VERSION 5.8 ;
BUSBITCHARS "[]" ;
DIVIDERCHAR "/" ;
UNITS
    DATABASE MICRONS 1000 ;
END UNITS

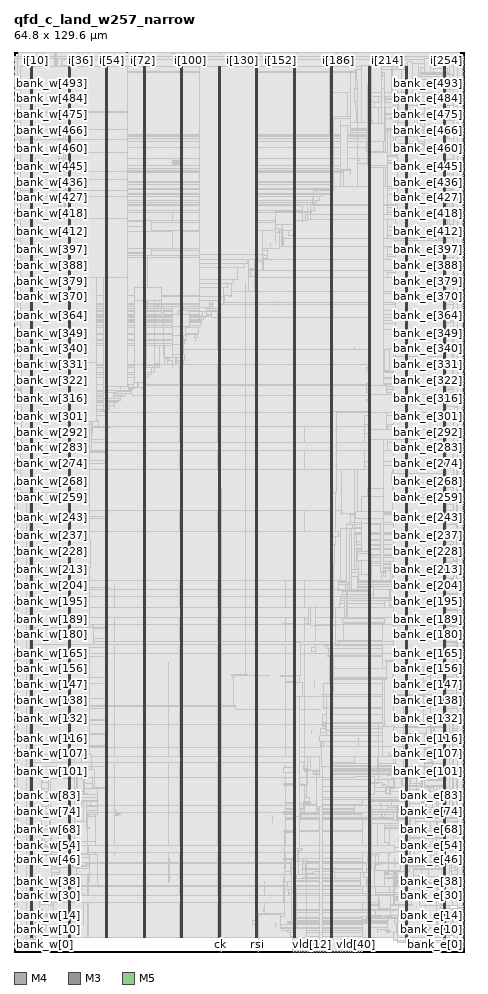
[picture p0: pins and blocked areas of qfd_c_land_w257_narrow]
MACRO qfd_c_land_w257_narrow
  FOREIGN qfd_c_land_w257_narrow 0 0 ;
  CLASS BLOCK ;
  SIZE 64.8 BY 129.6 ;
  PIN bank_e[0]
    DIRECTION OUTPUT ;
    USE SIGNAL ;
    PORT
      LAYER M4 ;
        RECT  64.716 0.672 64.8 0.696 ;
    END
  END bank_e[0]
  PIN bank_e[100]
    DIRECTION OUTPUT ;
    USE SIGNAL ;
    PORT
      LAYER M4 ;
        RECT  64.716 25.68 64.8 25.704 ;
    END
  END bank_e[100]
  PIN bank_e[101]
    DIRECTION OUTPUT ;
    USE SIGNAL ;
    PORT
      LAYER M4 ;
        RECT  64.716 25.92 64.8 25.944 ;
    END
  END bank_e[101]
  PIN bank_e[102]
    DIRECTION OUTPUT ;
    USE SIGNAL ;
    PORT
      LAYER M4 ;
        RECT  64.716 26.16 64.8 26.184 ;
    END
  END bank_e[102]
  PIN bank_e[103]
    DIRECTION OUTPUT ;
    USE SIGNAL ;
    PORT
      LAYER M4 ;
        RECT  64.716 26.4 64.8 26.424 ;
    END
  END bank_e[103]
  PIN bank_e[104]
    DIRECTION OUTPUT ;
    USE SIGNAL ;
    PORT
      LAYER M4 ;
        RECT  64.716 26.64 64.8 26.664 ;
    END
  END bank_e[104]
  PIN bank_e[105]
    DIRECTION OUTPUT ;
    USE SIGNAL ;
    PORT
      LAYER M4 ;
        RECT  64.716 26.928 64.8 26.952 ;
    END
  END bank_e[105]
  PIN bank_e[106]
    DIRECTION OUTPUT ;
    USE SIGNAL ;
    PORT
      LAYER M4 ;
        RECT  64.716 27.168 64.8 27.192 ;
    END
  END bank_e[106]
  PIN bank_e[107]
    DIRECTION OUTPUT ;
    USE SIGNAL ;
    PORT
      LAYER M4 ;
        RECT  64.716 27.408 64.8 27.432 ;
    END
  END bank_e[107]
  PIN bank_e[108]
    DIRECTION OUTPUT ;
    USE SIGNAL ;
    PORT
      LAYER M4 ;
        RECT  64.716 27.648 64.8 27.672 ;
    END
  END bank_e[108]
  PIN bank_e[109]
    DIRECTION OUTPUT ;
    USE SIGNAL ;
    PORT
      LAYER M4 ;
        RECT  64.716 27.888 64.8 27.912 ;
    END
  END bank_e[109]
  PIN bank_e[10]
    DIRECTION OUTPUT ;
    USE SIGNAL ;
    PORT
      LAYER M4 ;
        RECT  64.716 3.168 64.8 3.192 ;
    END
  END bank_e[10]
  PIN bank_e[110]
    DIRECTION OUTPUT ;
    USE SIGNAL ;
    PORT
      LAYER M4 ;
        RECT  64.716 28.176 64.8 28.2 ;
    END
  END bank_e[110]
  PIN bank_e[111]
    DIRECTION OUTPUT ;
    USE SIGNAL ;
    PORT
      LAYER M4 ;
        RECT  64.716 28.416 64.8 28.44 ;
    END
  END bank_e[111]
  PIN bank_e[112]
    DIRECTION OUTPUT ;
    USE SIGNAL ;
    PORT
      LAYER M4 ;
        RECT  64.716 28.656 64.8 28.68 ;
    END
  END bank_e[112]
  PIN bank_e[113]
    DIRECTION OUTPUT ;
    USE SIGNAL ;
    PORT
      LAYER M4 ;
        RECT  64.716 28.896 64.8 28.92 ;
    END
  END bank_e[113]
  PIN bank_e[114]
    DIRECTION OUTPUT ;
    USE SIGNAL ;
    PORT
      LAYER M4 ;
        RECT  64.716 29.136 64.8 29.16 ;
    END
  END bank_e[114]
  PIN bank_e[115]
    DIRECTION OUTPUT ;
    USE SIGNAL ;
    PORT
      LAYER M4 ;
        RECT  64.716 29.424 64.8 29.448 ;
    END
  END bank_e[115]
  PIN bank_e[116]
    DIRECTION OUTPUT ;
    USE SIGNAL ;
    PORT
      LAYER M4 ;
        RECT  64.716 29.664 64.8 29.688 ;
    END
  END bank_e[116]
  PIN bank_e[117]
    DIRECTION OUTPUT ;
    USE SIGNAL ;
    PORT
      LAYER M4 ;
        RECT  64.716 29.904 64.8 29.928 ;
    END
  END bank_e[117]
  PIN bank_e[118]
    DIRECTION OUTPUT ;
    USE SIGNAL ;
    PORT
      LAYER M4 ;
        RECT  64.716 30.144 64.8 30.168 ;
    END
  END bank_e[118]
  PIN bank_e[119]
    DIRECTION OUTPUT ;
    USE SIGNAL ;
    PORT
      LAYER M4 ;
        RECT  64.716 30.432 64.8 30.456 ;
    END
  END bank_e[119]
  PIN bank_e[11]
    DIRECTION OUTPUT ;
    USE SIGNAL ;
    PORT
      LAYER M4 ;
        RECT  64.716 3.408 64.8 3.432 ;
    END
  END bank_e[11]
  PIN bank_e[120]
    DIRECTION OUTPUT ;
    USE SIGNAL ;
    PORT
      LAYER M4 ;
        RECT  64.716 30.672 64.8 30.696 ;
    END
  END bank_e[120]
  PIN bank_e[121]
    DIRECTION OUTPUT ;
    USE SIGNAL ;
    PORT
      LAYER M4 ;
        RECT  64.716 30.912 64.8 30.936 ;
    END
  END bank_e[121]
  PIN bank_e[122]
    DIRECTION OUTPUT ;
    USE SIGNAL ;
    PORT
      LAYER M4 ;
        RECT  64.716 31.152 64.8 31.176 ;
    END
  END bank_e[122]
  PIN bank_e[123]
    DIRECTION OUTPUT ;
    USE SIGNAL ;
    PORT
      LAYER M4 ;
        RECT  64.716 31.392 64.8 31.416 ;
    END
  END bank_e[123]
  PIN bank_e[124]
    DIRECTION OUTPUT ;
    USE SIGNAL ;
    PORT
      LAYER M4 ;
        RECT  64.716 31.68 64.8 31.704 ;
    END
  END bank_e[124]
  PIN bank_e[125]
    DIRECTION OUTPUT ;
    USE SIGNAL ;
    PORT
      LAYER M4 ;
        RECT  64.716 31.92 64.8 31.944 ;
    END
  END bank_e[125]
  PIN bank_e[126]
    DIRECTION OUTPUT ;
    USE SIGNAL ;
    PORT
      LAYER M4 ;
        RECT  64.716 32.16 64.8 32.184 ;
    END
  END bank_e[126]
  PIN bank_e[127]
    DIRECTION OUTPUT ;
    USE SIGNAL ;
    PORT
      LAYER M4 ;
        RECT  64.716 32.4 64.8 32.424 ;
    END
  END bank_e[127]
  PIN bank_e[128]
    DIRECTION OUTPUT ;
    USE SIGNAL ;
    PORT
      LAYER M4 ;
        RECT  64.716 32.64 64.8 32.664 ;
    END
  END bank_e[128]
  PIN bank_e[129]
    DIRECTION OUTPUT ;
    USE SIGNAL ;
    PORT
      LAYER M4 ;
        RECT  64.716 32.928 64.8 32.952 ;
    END
  END bank_e[129]
  PIN bank_e[12]
    DIRECTION OUTPUT ;
    USE SIGNAL ;
    PORT
      LAYER M4 ;
        RECT  64.716 3.648 64.8 3.672 ;
    END
  END bank_e[12]
  PIN bank_e[130]
    DIRECTION OUTPUT ;
    USE SIGNAL ;
    PORT
      LAYER M4 ;
        RECT  64.716 33.168 64.8 33.192 ;
    END
  END bank_e[130]
  PIN bank_e[131]
    DIRECTION OUTPUT ;
    USE SIGNAL ;
    PORT
      LAYER M4 ;
        RECT  64.716 33.408 64.8 33.432 ;
    END
  END bank_e[131]
  PIN bank_e[132]
    DIRECTION OUTPUT ;
    USE SIGNAL ;
    PORT
      LAYER M4 ;
        RECT  64.716 33.648 64.8 33.672 ;
    END
  END bank_e[132]
  PIN bank_e[133]
    DIRECTION OUTPUT ;
    USE SIGNAL ;
    PORT
      LAYER M4 ;
        RECT  64.716 33.888 64.8 33.912 ;
    END
  END bank_e[133]
  PIN bank_e[134]
    DIRECTION OUTPUT ;
    USE SIGNAL ;
    PORT
      LAYER M4 ;
        RECT  64.716 34.176 64.8 34.2 ;
    END
  END bank_e[134]
  PIN bank_e[135]
    DIRECTION OUTPUT ;
    USE SIGNAL ;
    PORT
      LAYER M4 ;
        RECT  64.716 34.416 64.8 34.44 ;
    END
  END bank_e[135]
  PIN bank_e[136]
    DIRECTION OUTPUT ;
    USE SIGNAL ;
    PORT
      LAYER M4 ;
        RECT  64.716 34.656 64.8 34.68 ;
    END
  END bank_e[136]
  PIN bank_e[137]
    DIRECTION OUTPUT ;
    USE SIGNAL ;
    PORT
      LAYER M4 ;
        RECT  64.716 34.896 64.8 34.92 ;
    END
  END bank_e[137]
  PIN bank_e[138]
    DIRECTION OUTPUT ;
    USE SIGNAL ;
    PORT
      LAYER M4 ;
        RECT  64.716 35.136 64.8 35.16 ;
    END
  END bank_e[138]
  PIN bank_e[139]
    DIRECTION OUTPUT ;
    USE SIGNAL ;
    PORT
      LAYER M4 ;
        RECT  64.716 35.424 64.8 35.448 ;
    END
  END bank_e[139]
  PIN bank_e[13]
    DIRECTION OUTPUT ;
    USE SIGNAL ;
    PORT
      LAYER M4 ;
        RECT  64.716 3.888 64.8 3.912 ;
    END
  END bank_e[13]
  PIN bank_e[140]
    DIRECTION OUTPUT ;
    USE SIGNAL ;
    PORT
      LAYER M4 ;
        RECT  64.716 35.664 64.8 35.688 ;
    END
  END bank_e[140]
  PIN bank_e[141]
    DIRECTION OUTPUT ;
    USE SIGNAL ;
    PORT
      LAYER M4 ;
        RECT  64.716 35.904 64.8 35.928 ;
    END
  END bank_e[141]
  PIN bank_e[142]
    DIRECTION OUTPUT ;
    USE SIGNAL ;
    PORT
      LAYER M4 ;
        RECT  64.716 36.144 64.8 36.168 ;
    END
  END bank_e[142]
  PIN bank_e[143]
    DIRECTION OUTPUT ;
    USE SIGNAL ;
    PORT
      LAYER M4 ;
        RECT  64.716 36.432 64.8 36.456 ;
    END
  END bank_e[143]
  PIN bank_e[144]
    DIRECTION OUTPUT ;
    USE SIGNAL ;
    PORT
      LAYER M4 ;
        RECT  64.716 36.672 64.8 36.696 ;
    END
  END bank_e[144]
  PIN bank_e[145]
    DIRECTION OUTPUT ;
    USE SIGNAL ;
    PORT
      LAYER M4 ;
        RECT  64.716 36.912 64.8 36.936 ;
    END
  END bank_e[145]
  PIN bank_e[146]
    DIRECTION OUTPUT ;
    USE SIGNAL ;
    PORT
      LAYER M4 ;
        RECT  64.716 37.152 64.8 37.176 ;
    END
  END bank_e[146]
  PIN bank_e[147]
    DIRECTION OUTPUT ;
    USE SIGNAL ;
    PORT
      LAYER M4 ;
        RECT  64.716 37.392 64.8 37.416 ;
    END
  END bank_e[147]
  PIN bank_e[148]
    DIRECTION OUTPUT ;
    USE SIGNAL ;
    PORT
      LAYER M4 ;
        RECT  64.716 37.68 64.8 37.704 ;
    END
  END bank_e[148]
  PIN bank_e[149]
    DIRECTION OUTPUT ;
    USE SIGNAL ;
    PORT
      LAYER M4 ;
        RECT  64.716 37.92 64.8 37.944 ;
    END
  END bank_e[149]
  PIN bank_e[14]
    DIRECTION OUTPUT ;
    USE SIGNAL ;
    PORT
      LAYER M4 ;
        RECT  64.716 4.176 64.8 4.2 ;
    END
  END bank_e[14]
  PIN bank_e[150]
    DIRECTION OUTPUT ;
    USE SIGNAL ;
    PORT
      LAYER M4 ;
        RECT  64.716 38.16 64.8 38.184 ;
    END
  END bank_e[150]
  PIN bank_e[151]
    DIRECTION OUTPUT ;
    USE SIGNAL ;
    PORT
      LAYER M4 ;
        RECT  64.716 38.4 64.8 38.424 ;
    END
  END bank_e[151]
  PIN bank_e[152]
    DIRECTION OUTPUT ;
    USE SIGNAL ;
    PORT
      LAYER M4 ;
        RECT  64.716 38.64 64.8 38.664 ;
    END
  END bank_e[152]
  PIN bank_e[153]
    DIRECTION OUTPUT ;
    USE SIGNAL ;
    PORT
      LAYER M4 ;
        RECT  64.716 38.928 64.8 38.952 ;
    END
  END bank_e[153]
  PIN bank_e[154]
    DIRECTION OUTPUT ;
    USE SIGNAL ;
    PORT
      LAYER M4 ;
        RECT  64.716 39.168 64.8 39.192 ;
    END
  END bank_e[154]
  PIN bank_e[155]
    DIRECTION OUTPUT ;
    USE SIGNAL ;
    PORT
      LAYER M4 ;
        RECT  64.716 39.408 64.8 39.432 ;
    END
  END bank_e[155]
  PIN bank_e[156]
    DIRECTION OUTPUT ;
    USE SIGNAL ;
    PORT
      LAYER M4 ;
        RECT  64.716 39.648 64.8 39.672 ;
    END
  END bank_e[156]
  PIN bank_e[157]
    DIRECTION OUTPUT ;
    USE SIGNAL ;
    PORT
      LAYER M4 ;
        RECT  64.716 39.888 64.8 39.912 ;
    END
  END bank_e[157]
  PIN bank_e[158]
    DIRECTION OUTPUT ;
    USE SIGNAL ;
    PORT
      LAYER M4 ;
        RECT  64.716 40.176 64.8 40.2 ;
    END
  END bank_e[158]
  PIN bank_e[159]
    DIRECTION OUTPUT ;
    USE SIGNAL ;
    PORT
      LAYER M4 ;
        RECT  64.716 40.416 64.8 40.44 ;
    END
  END bank_e[159]
  PIN bank_e[15]
    DIRECTION OUTPUT ;
    USE SIGNAL ;
    PORT
      LAYER M4 ;
        RECT  64.716 4.416 64.8 4.44 ;
    END
  END bank_e[15]
  PIN bank_e[160]
    DIRECTION OUTPUT ;
    USE SIGNAL ;
    PORT
      LAYER M4 ;
        RECT  64.716 40.656 64.8 40.68 ;
    END
  END bank_e[160]
  PIN bank_e[161]
    DIRECTION OUTPUT ;
    USE SIGNAL ;
    PORT
      LAYER M4 ;
        RECT  64.716 40.896 64.8 40.92 ;
    END
  END bank_e[161]
  PIN bank_e[162]
    DIRECTION OUTPUT ;
    USE SIGNAL ;
    PORT
      LAYER M4 ;
        RECT  64.716 41.136 64.8 41.16 ;
    END
  END bank_e[162]
  PIN bank_e[163]
    DIRECTION OUTPUT ;
    USE SIGNAL ;
    PORT
      LAYER M4 ;
        RECT  64.716 41.424 64.8 41.448 ;
    END
  END bank_e[163]
  PIN bank_e[164]
    DIRECTION OUTPUT ;
    USE SIGNAL ;
    PORT
      LAYER M4 ;
        RECT  64.716 41.664 64.8 41.688 ;
    END
  END bank_e[164]
  PIN bank_e[165]
    DIRECTION OUTPUT ;
    USE SIGNAL ;
    PORT
      LAYER M4 ;
        RECT  64.716 41.904 64.8 41.928 ;
    END
  END bank_e[165]
  PIN bank_e[166]
    DIRECTION OUTPUT ;
    USE SIGNAL ;
    PORT
      LAYER M4 ;
        RECT  64.716 42.144 64.8 42.168 ;
    END
  END bank_e[166]
  PIN bank_e[167]
    DIRECTION OUTPUT ;
    USE SIGNAL ;
    PORT
      LAYER M4 ;
        RECT  64.716 42.432 64.8 42.456 ;
    END
  END bank_e[167]
  PIN bank_e[168]
    DIRECTION OUTPUT ;
    USE SIGNAL ;
    PORT
      LAYER M4 ;
        RECT  64.716 42.672 64.8 42.696 ;
    END
  END bank_e[168]
  PIN bank_e[169]
    DIRECTION OUTPUT ;
    USE SIGNAL ;
    PORT
      LAYER M4 ;
        RECT  64.716 42.912 64.8 42.936 ;
    END
  END bank_e[169]
  PIN bank_e[16]
    DIRECTION OUTPUT ;
    USE SIGNAL ;
    PORT
      LAYER M4 ;
        RECT  64.716 4.656 64.8 4.68 ;
    END
  END bank_e[16]
  PIN bank_e[170]
    DIRECTION OUTPUT ;
    USE SIGNAL ;
    PORT
      LAYER M4 ;
        RECT  64.716 43.152 64.8 43.176 ;
    END
  END bank_e[170]
  PIN bank_e[171]
    DIRECTION OUTPUT ;
    USE SIGNAL ;
    PORT
      LAYER M4 ;
        RECT  64.716 43.392 64.8 43.416 ;
    END
  END bank_e[171]
  PIN bank_e[172]
    DIRECTION OUTPUT ;
    USE SIGNAL ;
    PORT
      LAYER M4 ;
        RECT  64.716 43.68 64.8 43.704 ;
    END
  END bank_e[172]
  PIN bank_e[173]
    DIRECTION OUTPUT ;
    USE SIGNAL ;
    PORT
      LAYER M4 ;
        RECT  64.716 43.92 64.8 43.944 ;
    END
  END bank_e[173]
  PIN bank_e[174]
    DIRECTION OUTPUT ;
    USE SIGNAL ;
    PORT
      LAYER M4 ;
        RECT  64.716 44.16 64.8 44.184 ;
    END
  END bank_e[174]
  PIN bank_e[175]
    DIRECTION OUTPUT ;
    USE SIGNAL ;
    PORT
      LAYER M4 ;
        RECT  64.716 44.4 64.8 44.424 ;
    END
  END bank_e[175]
  PIN bank_e[176]
    DIRECTION OUTPUT ;
    USE SIGNAL ;
    PORT
      LAYER M4 ;
        RECT  64.716 44.64 64.8 44.664 ;
    END
  END bank_e[176]
  PIN bank_e[177]
    DIRECTION OUTPUT ;
    USE SIGNAL ;
    PORT
      LAYER M4 ;
        RECT  64.716 44.928 64.8 44.952 ;
    END
  END bank_e[177]
  PIN bank_e[178]
    DIRECTION OUTPUT ;
    USE SIGNAL ;
    PORT
      LAYER M4 ;
        RECT  64.716 45.168 64.8 45.192 ;
    END
  END bank_e[178]
  PIN bank_e[179]
    DIRECTION OUTPUT ;
    USE SIGNAL ;
    PORT
      LAYER M4 ;
        RECT  64.716 45.408 64.8 45.432 ;
    END
  END bank_e[179]
  PIN bank_e[17]
    DIRECTION OUTPUT ;
    USE SIGNAL ;
    PORT
      LAYER M4 ;
        RECT  64.716 4.896 64.8 4.92 ;
    END
  END bank_e[17]
  PIN bank_e[180]
    DIRECTION OUTPUT ;
    USE SIGNAL ;
    PORT
      LAYER M4 ;
        RECT  64.716 45.648 64.8 45.672 ;
    END
  END bank_e[180]
  PIN bank_e[181]
    DIRECTION OUTPUT ;
    USE SIGNAL ;
    PORT
      LAYER M4 ;
        RECT  64.716 45.888 64.8 45.912 ;
    END
  END bank_e[181]
  PIN bank_e[182]
    DIRECTION OUTPUT ;
    USE SIGNAL ;
    PORT
      LAYER M4 ;
        RECT  64.716 46.176 64.8 46.2 ;
    END
  END bank_e[182]
  PIN bank_e[183]
    DIRECTION OUTPUT ;
    USE SIGNAL ;
    PORT
      LAYER M4 ;
        RECT  64.716 46.416 64.8 46.44 ;
    END
  END bank_e[183]
  PIN bank_e[184]
    DIRECTION OUTPUT ;
    USE SIGNAL ;
    PORT
      LAYER M4 ;
        RECT  64.716 46.656 64.8 46.68 ;
    END
  END bank_e[184]
  PIN bank_e[185]
    DIRECTION OUTPUT ;
    USE SIGNAL ;
    PORT
      LAYER M4 ;
        RECT  64.716 46.896 64.8 46.92 ;
    END
  END bank_e[185]
  PIN bank_e[186]
    DIRECTION OUTPUT ;
    USE SIGNAL ;
    PORT
      LAYER M4 ;
        RECT  64.716 47.184 64.8 47.208 ;
    END
  END bank_e[186]
  PIN bank_e[187]
    DIRECTION OUTPUT ;
    USE SIGNAL ;
    PORT
      LAYER M4 ;
        RECT  64.716 47.424 64.8 47.448 ;
    END
  END bank_e[187]
  PIN bank_e[188]
    DIRECTION OUTPUT ;
    USE SIGNAL ;
    PORT
      LAYER M4 ;
        RECT  64.716 47.664 64.8 47.688 ;
    END
  END bank_e[188]
  PIN bank_e[189]
    DIRECTION OUTPUT ;
    USE SIGNAL ;
    PORT
      LAYER M4 ;
        RECT  64.716 47.904 64.8 47.928 ;
    END
  END bank_e[189]
  PIN bank_e[18]
    DIRECTION OUTPUT ;
    USE SIGNAL ;
    PORT
      LAYER M4 ;
        RECT  64.716 5.136 64.8 5.16 ;
    END
  END bank_e[18]
  PIN bank_e[190]
    DIRECTION OUTPUT ;
    USE SIGNAL ;
    PORT
      LAYER M4 ;
        RECT  64.716 48.144 64.8 48.168 ;
    END
  END bank_e[190]
  PIN bank_e[191]
    DIRECTION OUTPUT ;
    USE SIGNAL ;
    PORT
      LAYER M4 ;
        RECT  64.716 48.432 64.8 48.456 ;
    END
  END bank_e[191]
  PIN bank_e[192]
    DIRECTION OUTPUT ;
    USE SIGNAL ;
    PORT
      LAYER M4 ;
        RECT  64.716 48.672 64.8 48.696 ;
    END
  END bank_e[192]
  PIN bank_e[193]
    DIRECTION OUTPUT ;
    USE SIGNAL ;
    PORT
      LAYER M4 ;
        RECT  64.716 48.912 64.8 48.936 ;
    END
  END bank_e[193]
  PIN bank_e[194]
    DIRECTION OUTPUT ;
    USE SIGNAL ;
    PORT
      LAYER M4 ;
        RECT  64.716 49.152 64.8 49.176 ;
    END
  END bank_e[194]
  PIN bank_e[195]
    DIRECTION OUTPUT ;
    USE SIGNAL ;
    PORT
      LAYER M4 ;
        RECT  64.716 49.392 64.8 49.416 ;
    END
  END bank_e[195]
  PIN bank_e[196]
    DIRECTION OUTPUT ;
    USE SIGNAL ;
    PORT
      LAYER M4 ;
        RECT  64.716 49.68 64.8 49.704 ;
    END
  END bank_e[196]
  PIN bank_e[197]
    DIRECTION OUTPUT ;
    USE SIGNAL ;
    PORT
      LAYER M4 ;
        RECT  64.716 49.92 64.8 49.944 ;
    END
  END bank_e[197]
  PIN bank_e[198]
    DIRECTION OUTPUT ;
    USE SIGNAL ;
    PORT
      LAYER M4 ;
        RECT  64.716 50.16 64.8 50.184 ;
    END
  END bank_e[198]
  PIN bank_e[199]
    DIRECTION OUTPUT ;
    USE SIGNAL ;
    PORT
      LAYER M4 ;
        RECT  64.716 50.4 64.8 50.424 ;
    END
  END bank_e[199]
  PIN bank_e[19]
    DIRECTION OUTPUT ;
    USE SIGNAL ;
    PORT
      LAYER M4 ;
        RECT  64.716 5.424 64.8 5.448 ;
    END
  END bank_e[19]
  PIN bank_e[1]
    DIRECTION OUTPUT ;
    USE SIGNAL ;
    PORT
      LAYER M4 ;
        RECT  64.716 0.912 64.8 0.936 ;
    END
  END bank_e[1]
  PIN bank_e[200]
    DIRECTION OUTPUT ;
    USE SIGNAL ;
    PORT
      LAYER M4 ;
        RECT  64.716 50.64 64.8 50.664 ;
    END
  END bank_e[200]
  PIN bank_e[201]
    DIRECTION OUTPUT ;
    USE SIGNAL ;
    PORT
      LAYER M4 ;
        RECT  64.716 50.928 64.8 50.952 ;
    END
  END bank_e[201]
  PIN bank_e[202]
    DIRECTION OUTPUT ;
    USE SIGNAL ;
    PORT
      LAYER M4 ;
        RECT  64.716 51.168 64.8 51.192 ;
    END
  END bank_e[202]
  PIN bank_e[203]
    DIRECTION OUTPUT ;
    USE SIGNAL ;
    PORT
      LAYER M4 ;
        RECT  64.716 51.408 64.8 51.432 ;
    END
  END bank_e[203]
  PIN bank_e[204]
    DIRECTION OUTPUT ;
    USE SIGNAL ;
    PORT
      LAYER M4 ;
        RECT  64.716 51.648 64.8 51.672 ;
    END
  END bank_e[204]
  PIN bank_e[205]
    DIRECTION OUTPUT ;
    USE SIGNAL ;
    PORT
      LAYER M4 ;
        RECT  64.716 51.888 64.8 51.912 ;
    END
  END bank_e[205]
  PIN bank_e[206]
    DIRECTION OUTPUT ;
    USE SIGNAL ;
    PORT
      LAYER M4 ;
        RECT  64.716 52.176 64.8 52.2 ;
    END
  END bank_e[206]
  PIN bank_e[207]
    DIRECTION OUTPUT ;
    USE SIGNAL ;
    PORT
      LAYER M4 ;
        RECT  64.716 52.416 64.8 52.44 ;
    END
  END bank_e[207]
  PIN bank_e[208]
    DIRECTION OUTPUT ;
    USE SIGNAL ;
    PORT
      LAYER M4 ;
        RECT  64.716 52.656 64.8 52.68 ;
    END
  END bank_e[208]
  PIN bank_e[209]
    DIRECTION OUTPUT ;
    USE SIGNAL ;
    PORT
      LAYER M4 ;
        RECT  64.716 52.896 64.8 52.92 ;
    END
  END bank_e[209]
  PIN bank_e[20]
    DIRECTION OUTPUT ;
    USE SIGNAL ;
    PORT
      LAYER M4 ;
        RECT  64.716 5.664 64.8 5.688 ;
    END
  END bank_e[20]
  PIN bank_e[210]
    DIRECTION OUTPUT ;
    USE SIGNAL ;
    PORT
      LAYER M4 ;
        RECT  64.716 53.184 64.8 53.208 ;
    END
  END bank_e[210]
  PIN bank_e[211]
    DIRECTION OUTPUT ;
    USE SIGNAL ;
    PORT
      LAYER M4 ;
        RECT  64.716 53.424 64.8 53.448 ;
    END
  END bank_e[211]
  PIN bank_e[212]
    DIRECTION OUTPUT ;
    USE SIGNAL ;
    PORT
      LAYER M4 ;
        RECT  64.716 53.664 64.8 53.688 ;
    END
  END bank_e[212]
  PIN bank_e[213]
    DIRECTION OUTPUT ;
    USE SIGNAL ;
    PORT
      LAYER M4 ;
        RECT  64.716 53.904 64.8 53.928 ;
    END
  END bank_e[213]
  PIN bank_e[214]
    DIRECTION OUTPUT ;
    USE SIGNAL ;
    PORT
      LAYER M4 ;
        RECT  64.716 54.144 64.8 54.168 ;
    END
  END bank_e[214]
  PIN bank_e[215]
    DIRECTION OUTPUT ;
    USE SIGNAL ;
    PORT
      LAYER M4 ;
        RECT  64.716 54.432 64.8 54.456 ;
    END
  END bank_e[215]
  PIN bank_e[216]
    DIRECTION OUTPUT ;
    USE SIGNAL ;
    PORT
      LAYER M4 ;
        RECT  64.716 54.672 64.8 54.696 ;
    END
  END bank_e[216]
  PIN bank_e[217]
    DIRECTION OUTPUT ;
    USE SIGNAL ;
    PORT
      LAYER M4 ;
        RECT  64.716 54.912 64.8 54.936 ;
    END
  END bank_e[217]
  PIN bank_e[218]
    DIRECTION OUTPUT ;
    USE SIGNAL ;
    PORT
      LAYER M4 ;
        RECT  64.716 55.152 64.8 55.176 ;
    END
  END bank_e[218]
  PIN bank_e[219]
    DIRECTION OUTPUT ;
    USE SIGNAL ;
    PORT
      LAYER M4 ;
        RECT  64.716 55.392 64.8 55.416 ;
    END
  END bank_e[219]
  PIN bank_e[21]
    DIRECTION OUTPUT ;
    USE SIGNAL ;
    PORT
      LAYER M4 ;
        RECT  64.716 5.904 64.8 5.928 ;
    END
  END bank_e[21]
  PIN bank_e[220]
    DIRECTION OUTPUT ;
    USE SIGNAL ;
    PORT
      LAYER M4 ;
        RECT  64.716 55.68 64.8 55.704 ;
    END
  END bank_e[220]
  PIN bank_e[221]
    DIRECTION OUTPUT ;
    USE SIGNAL ;
    PORT
      LAYER M4 ;
        RECT  64.716 55.92 64.8 55.944 ;
    END
  END bank_e[221]
  PIN bank_e[222]
    DIRECTION OUTPUT ;
    USE SIGNAL ;
    PORT
      LAYER M4 ;
        RECT  64.716 56.16 64.8 56.184 ;
    END
  END bank_e[222]
  PIN bank_e[223]
    DIRECTION OUTPUT ;
    USE SIGNAL ;
    PORT
      LAYER M4 ;
        RECT  64.716 56.4 64.8 56.424 ;
    END
  END bank_e[223]
  PIN bank_e[224]
    DIRECTION OUTPUT ;
    USE SIGNAL ;
    PORT
      LAYER M4 ;
        RECT  64.716 56.64 64.8 56.664 ;
    END
  END bank_e[224]
  PIN bank_e[225]
    DIRECTION OUTPUT ;
    USE SIGNAL ;
    PORT
      LAYER M4 ;
        RECT  64.716 56.928 64.8 56.952 ;
    END
  END bank_e[225]
  PIN bank_e[226]
    DIRECTION OUTPUT ;
    USE SIGNAL ;
    PORT
      LAYER M4 ;
        RECT  64.716 57.168 64.8 57.192 ;
    END
  END bank_e[226]
  PIN bank_e[227]
    DIRECTION OUTPUT ;
    USE SIGNAL ;
    PORT
      LAYER M4 ;
        RECT  64.716 57.408 64.8 57.432 ;
    END
  END bank_e[227]
  PIN bank_e[228]
    DIRECTION OUTPUT ;
    USE SIGNAL ;
    PORT
      LAYER M4 ;
        RECT  64.716 57.648 64.8 57.672 ;
    END
  END bank_e[228]
  PIN bank_e[229]
    DIRECTION OUTPUT ;
    USE SIGNAL ;
    PORT
      LAYER M4 ;
        RECT  64.716 57.936 64.8 57.96 ;
    END
  END bank_e[229]
  PIN bank_e[22]
    DIRECTION OUTPUT ;
    USE SIGNAL ;
    PORT
      LAYER M4 ;
        RECT  64.716 6.144 64.8 6.168 ;
    END
  END bank_e[22]
  PIN bank_e[230]
    DIRECTION OUTPUT ;
    USE SIGNAL ;
    PORT
      LAYER M4 ;
        RECT  64.716 58.176 64.8 58.2 ;
    END
  END bank_e[230]
  PIN bank_e[231]
    DIRECTION OUTPUT ;
    USE SIGNAL ;
    PORT
      LAYER M4 ;
        RECT  64.716 58.416 64.8 58.44 ;
    END
  END bank_e[231]
  PIN bank_e[232]
    DIRECTION OUTPUT ;
    USE SIGNAL ;
    PORT
      LAYER M4 ;
        RECT  64.716 58.656 64.8 58.68 ;
    END
  END bank_e[232]
  PIN bank_e[233]
    DIRECTION OUTPUT ;
    USE SIGNAL ;
    PORT
      LAYER M4 ;
        RECT  64.716 58.896 64.8 58.92 ;
    END
  END bank_e[233]
  PIN bank_e[234]
    DIRECTION OUTPUT ;
    USE SIGNAL ;
    PORT
      LAYER M4 ;
        RECT  64.716 59.184 64.8 59.208 ;
    END
  END bank_e[234]
  PIN bank_e[235]
    DIRECTION OUTPUT ;
    USE SIGNAL ;
    PORT
      LAYER M4 ;
        RECT  64.716 59.424 64.8 59.448 ;
    END
  END bank_e[235]
  PIN bank_e[236]
    DIRECTION OUTPUT ;
    USE SIGNAL ;
    PORT
      LAYER M4 ;
        RECT  64.716 59.664 64.8 59.688 ;
    END
  END bank_e[236]
  PIN bank_e[237]
    DIRECTION OUTPUT ;
    USE SIGNAL ;
    PORT
      LAYER M4 ;
        RECT  64.716 59.904 64.8 59.928 ;
    END
  END bank_e[237]
  PIN bank_e[238]
    DIRECTION OUTPUT ;
    USE SIGNAL ;
    PORT
      LAYER M4 ;
        RECT  64.716 60.144 64.8 60.168 ;
    END
  END bank_e[238]
  PIN bank_e[239]
    DIRECTION OUTPUT ;
    USE SIGNAL ;
    PORT
      LAYER M4 ;
        RECT  64.716 60.432 64.8 60.456 ;
    END
  END bank_e[239]
  PIN bank_e[23]
    DIRECTION OUTPUT ;
    USE SIGNAL ;
    PORT
      LAYER M4 ;
        RECT  64.716 6.384 64.8 6.408 ;
    END
  END bank_e[23]
  PIN bank_e[240]
    DIRECTION OUTPUT ;
    USE SIGNAL ;
    PORT
      LAYER M4 ;
        RECT  64.716 60.672 64.8 60.696 ;
    END
  END bank_e[240]
  PIN bank_e[241]
    DIRECTION OUTPUT ;
    USE SIGNAL ;
    PORT
      LAYER M4 ;
        RECT  64.716 60.912 64.8 60.936 ;
    END
  END bank_e[241]
  PIN bank_e[242]
    DIRECTION OUTPUT ;
    USE SIGNAL ;
    PORT
      LAYER M4 ;
        RECT  64.716 61.152 64.8 61.176 ;
    END
  END bank_e[242]
  PIN bank_e[243]
    DIRECTION OUTPUT ;
    USE SIGNAL ;
    PORT
      LAYER M4 ;
        RECT  64.716 61.392 64.8 61.416 ;
    END
  END bank_e[243]
  PIN bank_e[244]
    DIRECTION OUTPUT ;
    USE SIGNAL ;
    PORT
      LAYER M4 ;
        RECT  64.716 61.68 64.8 61.704 ;
    END
  END bank_e[244]
  PIN bank_e[245]
    DIRECTION OUTPUT ;
    USE SIGNAL ;
    PORT
      LAYER M4 ;
        RECT  64.716 61.92 64.8 61.944 ;
    END
  END bank_e[245]
  PIN bank_e[246]
    DIRECTION OUTPUT ;
    USE SIGNAL ;
    PORT
      LAYER M4 ;
        RECT  64.716 62.16 64.8 62.184 ;
    END
  END bank_e[246]
  PIN bank_e[247]
    DIRECTION OUTPUT ;
    USE SIGNAL ;
    PORT
      LAYER M4 ;
        RECT  64.716 62.4 64.8 62.424 ;
    END
  END bank_e[247]
  PIN bank_e[248]
    DIRECTION OUTPUT ;
    USE SIGNAL ;
    PORT
      LAYER M4 ;
        RECT  64.716 62.64 64.8 62.664 ;
    END
  END bank_e[248]
  PIN bank_e[249]
    DIRECTION OUTPUT ;
    USE SIGNAL ;
    PORT
      LAYER M4 ;
        RECT  64.716 62.928 64.8 62.952 ;
    END
  END bank_e[249]
  PIN bank_e[24]
    DIRECTION OUTPUT ;
    USE SIGNAL ;
    PORT
      LAYER M4 ;
        RECT  64.716 6.672 64.8 6.696 ;
    END
  END bank_e[24]
  PIN bank_e[250]
    DIRECTION OUTPUT ;
    USE SIGNAL ;
    PORT
      LAYER M4 ;
        RECT  64.716 63.168 64.8 63.192 ;
    END
  END bank_e[250]
  PIN bank_e[251]
    DIRECTION OUTPUT ;
    USE SIGNAL ;
    PORT
      LAYER M4 ;
        RECT  64.716 63.408 64.8 63.432 ;
    END
  END bank_e[251]
  PIN bank_e[252]
    DIRECTION OUTPUT ;
    USE SIGNAL ;
    PORT
      LAYER M4 ;
        RECT  64.716 63.648 64.8 63.672 ;
    END
  END bank_e[252]
  PIN bank_e[253]
    DIRECTION OUTPUT ;
    USE SIGNAL ;
    PORT
      LAYER M4 ;
        RECT  64.716 63.936 64.8 63.96 ;
    END
  END bank_e[253]
  PIN bank_e[254]
    DIRECTION OUTPUT ;
    USE SIGNAL ;
    PORT
      LAYER M4 ;
        RECT  64.716 64.176 64.8 64.2 ;
    END
  END bank_e[254]
  PIN bank_e[255]
    DIRECTION OUTPUT ;
    USE SIGNAL ;
    PORT
      LAYER M4 ;
        RECT  64.716 64.416 64.8 64.44 ;
    END
  END bank_e[255]
  PIN bank_e[256]
    DIRECTION OUTPUT ;
    USE SIGNAL ;
    PORT
      LAYER M4 ;
        RECT  64.716 64.656 64.8 64.68 ;
    END
  END bank_e[256]
  PIN bank_e[257]
    DIRECTION OUTPUT ;
    USE SIGNAL ;
    PORT
      LAYER M4 ;
        RECT  64.716 64.896 64.8 64.92 ;
    END
  END bank_e[257]
  PIN bank_e[258]
    DIRECTION OUTPUT ;
    USE SIGNAL ;
    PORT
      LAYER M4 ;
        RECT  64.716 65.184 64.8 65.208 ;
    END
  END bank_e[258]
  PIN bank_e[259]
    DIRECTION OUTPUT ;
    USE SIGNAL ;
    PORT
      LAYER M4 ;
        RECT  64.716 65.424 64.8 65.448 ;
    END
  END bank_e[259]
  PIN bank_e[25]
    DIRECTION OUTPUT ;
    USE SIGNAL ;
    PORT
      LAYER M4 ;
        RECT  64.716 6.912 64.8 6.936 ;
    END
  END bank_e[25]
  PIN bank_e[260]
    DIRECTION OUTPUT ;
    USE SIGNAL ;
    PORT
      LAYER M4 ;
        RECT  64.716 65.664 64.8 65.688 ;
    END
  END bank_e[260]
  PIN bank_e[261]
    DIRECTION OUTPUT ;
    USE SIGNAL ;
    PORT
      LAYER M4 ;
        RECT  64.716 65.904 64.8 65.928 ;
    END
  END bank_e[261]
  PIN bank_e[262]
    DIRECTION OUTPUT ;
    USE SIGNAL ;
    PORT
      LAYER M4 ;
        RECT  64.716 66.144 64.8 66.168 ;
    END
  END bank_e[262]
  PIN bank_e[263]
    DIRECTION OUTPUT ;
    USE SIGNAL ;
    PORT
      LAYER M4 ;
        RECT  64.716 66.432 64.8 66.456 ;
    END
  END bank_e[263]
  PIN bank_e[264]
    DIRECTION OUTPUT ;
    USE SIGNAL ;
    PORT
      LAYER M4 ;
        RECT  64.716 66.672 64.8 66.696 ;
    END
  END bank_e[264]
  PIN bank_e[265]
    DIRECTION OUTPUT ;
    USE SIGNAL ;
    PORT
      LAYER M4 ;
        RECT  64.716 66.912 64.8 66.936 ;
    END
  END bank_e[265]
  PIN bank_e[266]
    DIRECTION OUTPUT ;
    USE SIGNAL ;
    PORT
      LAYER M4 ;
        RECT  64.716 67.152 64.8 67.176 ;
    END
  END bank_e[266]
  PIN bank_e[267]
    DIRECTION OUTPUT ;
    USE SIGNAL ;
    PORT
      LAYER M4 ;
        RECT  64.716 67.392 64.8 67.416 ;
    END
  END bank_e[267]
  PIN bank_e[268]
    DIRECTION OUTPUT ;
    USE SIGNAL ;
    PORT
      LAYER M4 ;
        RECT  64.716 67.68 64.8 67.704 ;
    END
  END bank_e[268]
  PIN bank_e[269]
    DIRECTION OUTPUT ;
    USE SIGNAL ;
    PORT
      LAYER M4 ;
        RECT  64.716 67.92 64.8 67.944 ;
    END
  END bank_e[269]
  PIN bank_e[26]
    DIRECTION OUTPUT ;
    USE SIGNAL ;
    PORT
      LAYER M4 ;
        RECT  64.716 7.152 64.8 7.176 ;
    END
  END bank_e[26]
  PIN bank_e[270]
    DIRECTION OUTPUT ;
    USE SIGNAL ;
    PORT
      LAYER M4 ;
        RECT  64.716 68.16 64.8 68.184 ;
    END
  END bank_e[270]
  PIN bank_e[271]
    DIRECTION OUTPUT ;
    USE SIGNAL ;
    PORT
      LAYER M4 ;
        RECT  64.716 68.4 64.8 68.424 ;
    END
  END bank_e[271]
  PIN bank_e[272]
    DIRECTION OUTPUT ;
    USE SIGNAL ;
    PORT
      LAYER M4 ;
        RECT  64.716 68.688 64.8 68.712 ;
    END
  END bank_e[272]
  PIN bank_e[273]
    DIRECTION OUTPUT ;
    USE SIGNAL ;
    PORT
      LAYER M4 ;
        RECT  64.716 68.928 64.8 68.952 ;
    END
  END bank_e[273]
  PIN bank_e[274]
    DIRECTION OUTPUT ;
    USE SIGNAL ;
    PORT
      LAYER M4 ;
        RECT  64.716 69.168 64.8 69.192 ;
    END
  END bank_e[274]
  PIN bank_e[275]
    DIRECTION OUTPUT ;
    USE SIGNAL ;
    PORT
      LAYER M4 ;
        RECT  64.716 69.408 64.8 69.432 ;
    END
  END bank_e[275]
  PIN bank_e[276]
    DIRECTION OUTPUT ;
    USE SIGNAL ;
    PORT
      LAYER M4 ;
        RECT  64.716 69.648 64.8 69.672 ;
    END
  END bank_e[276]
  PIN bank_e[277]
    DIRECTION OUTPUT ;
    USE SIGNAL ;
    PORT
      LAYER M4 ;
        RECT  64.716 69.936 64.8 69.96 ;
    END
  END bank_e[277]
  PIN bank_e[278]
    DIRECTION OUTPUT ;
    USE SIGNAL ;
    PORT
      LAYER M4 ;
        RECT  64.716 70.176 64.8 70.2 ;
    END
  END bank_e[278]
  PIN bank_e[279]
    DIRECTION OUTPUT ;
    USE SIGNAL ;
    PORT
      LAYER M4 ;
        RECT  64.716 70.416 64.8 70.44 ;
    END
  END bank_e[279]
  PIN bank_e[27]
    DIRECTION OUTPUT ;
    USE SIGNAL ;
    PORT
      LAYER M4 ;
        RECT  64.716 7.392 64.8 7.416 ;
    END
  END bank_e[27]
  PIN bank_e[280]
    DIRECTION OUTPUT ;
    USE SIGNAL ;
    PORT
      LAYER M4 ;
        RECT  64.716 70.656 64.8 70.68 ;
    END
  END bank_e[280]
  PIN bank_e[281]
    DIRECTION OUTPUT ;
    USE SIGNAL ;
    PORT
      LAYER M4 ;
        RECT  64.716 70.896 64.8 70.92 ;
    END
  END bank_e[281]
  PIN bank_e[282]
    DIRECTION OUTPUT ;
    USE SIGNAL ;
    PORT
      LAYER M4 ;
        RECT  64.716 71.184 64.8 71.208 ;
    END
  END bank_e[282]
  PIN bank_e[283]
    DIRECTION OUTPUT ;
    USE SIGNAL ;
    PORT
      LAYER M4 ;
        RECT  64.716 71.424 64.8 71.448 ;
    END
  END bank_e[283]
  PIN bank_e[284]
    DIRECTION OUTPUT ;
    USE SIGNAL ;
    PORT
      LAYER M4 ;
        RECT  64.716 71.664 64.8 71.688 ;
    END
  END bank_e[284]
  PIN bank_e[285]
    DIRECTION OUTPUT ;
    USE SIGNAL ;
    PORT
      LAYER M4 ;
        RECT  64.716 71.904 64.8 71.928 ;
    END
  END bank_e[285]
  PIN bank_e[286]
    DIRECTION OUTPUT ;
    USE SIGNAL ;
    PORT
      LAYER M4 ;
        RECT  64.716 72.144 64.8 72.168 ;
    END
  END bank_e[286]
  PIN bank_e[287]
    DIRECTION OUTPUT ;
    USE SIGNAL ;
    PORT
      LAYER M4 ;
        RECT  64.716 72.432 64.8 72.456 ;
    END
  END bank_e[287]
  PIN bank_e[288]
    DIRECTION OUTPUT ;
    USE SIGNAL ;
    PORT
      LAYER M4 ;
        RECT  64.716 72.672 64.8 72.696 ;
    END
  END bank_e[288]
  PIN bank_e[289]
    DIRECTION OUTPUT ;
    USE SIGNAL ;
    PORT
      LAYER M4 ;
        RECT  64.716 72.912 64.8 72.936 ;
    END
  END bank_e[289]
  PIN bank_e[28]
    DIRECTION OUTPUT ;
    USE SIGNAL ;
    PORT
      LAYER M4 ;
        RECT  64.716 7.632 64.8 7.656 ;
    END
  END bank_e[28]
  PIN bank_e[290]
    DIRECTION OUTPUT ;
    USE SIGNAL ;
    PORT
      LAYER M4 ;
        RECT  64.716 73.152 64.8 73.176 ;
    END
  END bank_e[290]
  PIN bank_e[291]
    DIRECTION OUTPUT ;
    USE SIGNAL ;
    PORT
      LAYER M4 ;
        RECT  64.716 73.392 64.8 73.416 ;
    END
  END bank_e[291]
  PIN bank_e[292]
    DIRECTION OUTPUT ;
    USE SIGNAL ;
    PORT
      LAYER M4 ;
        RECT  64.716 73.68 64.8 73.704 ;
    END
  END bank_e[292]
  PIN bank_e[293]
    DIRECTION OUTPUT ;
    USE SIGNAL ;
    PORT
      LAYER M4 ;
        RECT  64.716 73.92 64.8 73.944 ;
    END
  END bank_e[293]
  PIN bank_e[294]
    DIRECTION OUTPUT ;
    USE SIGNAL ;
    PORT
      LAYER M4 ;
        RECT  64.716 74.16 64.8 74.184 ;
    END
  END bank_e[294]
  PIN bank_e[295]
    DIRECTION OUTPUT ;
    USE SIGNAL ;
    PORT
      LAYER M4 ;
        RECT  64.716 74.4 64.8 74.424 ;
    END
  END bank_e[295]
  PIN bank_e[296]
    DIRECTION OUTPUT ;
    USE SIGNAL ;
    PORT
      LAYER M4 ;
        RECT  64.716 74.688 64.8 74.712 ;
    END
  END bank_e[296]
  PIN bank_e[297]
    DIRECTION OUTPUT ;
    USE SIGNAL ;
    PORT
      LAYER M4 ;
        RECT  64.716 74.928 64.8 74.952 ;
    END
  END bank_e[297]
  PIN bank_e[298]
    DIRECTION OUTPUT ;
    USE SIGNAL ;
    PORT
      LAYER M4 ;
        RECT  64.716 75.168 64.8 75.192 ;
    END
  END bank_e[298]
  PIN bank_e[299]
    DIRECTION OUTPUT ;
    USE SIGNAL ;
    PORT
      LAYER M4 ;
        RECT  64.716 75.408 64.8 75.432 ;
    END
  END bank_e[299]
  PIN bank_e[29]
    DIRECTION OUTPUT ;
    USE SIGNAL ;
    PORT
      LAYER M4 ;
        RECT  64.716 7.92 64.8 7.944 ;
    END
  END bank_e[29]
  PIN bank_e[2]
    DIRECTION OUTPUT ;
    USE SIGNAL ;
    PORT
      LAYER M4 ;
        RECT  64.716 1.152 64.8 1.176 ;
    END
  END bank_e[2]
  PIN bank_e[300]
    DIRECTION OUTPUT ;
    USE SIGNAL ;
    PORT
      LAYER M4 ;
        RECT  64.716 75.648 64.8 75.672 ;
    END
  END bank_e[300]
  PIN bank_e[301]
    DIRECTION OUTPUT ;
    USE SIGNAL ;
    PORT
      LAYER M4 ;
        RECT  64.716 75.936 64.8 75.96 ;
    END
  END bank_e[301]
  PIN bank_e[302]
    DIRECTION OUTPUT ;
    USE SIGNAL ;
    PORT
      LAYER M4 ;
        RECT  64.716 76.176 64.8 76.2 ;
    END
  END bank_e[302]
  PIN bank_e[303]
    DIRECTION OUTPUT ;
    USE SIGNAL ;
    PORT
      LAYER M4 ;
        RECT  64.716 76.416 64.8 76.44 ;
    END
  END bank_e[303]
  PIN bank_e[304]
    DIRECTION OUTPUT ;
    USE SIGNAL ;
    PORT
      LAYER M4 ;
        RECT  64.716 76.656 64.8 76.68 ;
    END
  END bank_e[304]
  PIN bank_e[305]
    DIRECTION OUTPUT ;
    USE SIGNAL ;
    PORT
      LAYER M4 ;
        RECT  64.716 76.896 64.8 76.92 ;
    END
  END bank_e[305]
  PIN bank_e[306]
    DIRECTION OUTPUT ;
    USE SIGNAL ;
    PORT
      LAYER M4 ;
        RECT  64.716 77.184 64.8 77.208 ;
    END
  END bank_e[306]
  PIN bank_e[307]
    DIRECTION OUTPUT ;
    USE SIGNAL ;
    PORT
      LAYER M4 ;
        RECT  64.716 77.424 64.8 77.448 ;
    END
  END bank_e[307]
  PIN bank_e[308]
    DIRECTION OUTPUT ;
    USE SIGNAL ;
    PORT
      LAYER M4 ;
        RECT  64.716 77.664 64.8 77.688 ;
    END
  END bank_e[308]
  PIN bank_e[309]
    DIRECTION OUTPUT ;
    USE SIGNAL ;
    PORT
      LAYER M4 ;
        RECT  64.716 77.904 64.8 77.928 ;
    END
  END bank_e[309]
  PIN bank_e[30]
    DIRECTION OUTPUT ;
    USE SIGNAL ;
    PORT
      LAYER M4 ;
        RECT  64.716 8.16 64.8 8.184 ;
    END
  END bank_e[30]
  PIN bank_e[310]
    DIRECTION OUTPUT ;
    USE SIGNAL ;
    PORT
      LAYER M4 ;
        RECT  64.716 78.144 64.8 78.168 ;
    END
  END bank_e[310]
  PIN bank_e[311]
    DIRECTION OUTPUT ;
    USE SIGNAL ;
    PORT
      LAYER M4 ;
        RECT  64.716 78.432 64.8 78.456 ;
    END
  END bank_e[311]
  PIN bank_e[312]
    DIRECTION OUTPUT ;
    USE SIGNAL ;
    PORT
      LAYER M4 ;
        RECT  64.716 78.672 64.8 78.696 ;
    END
  END bank_e[312]
  PIN bank_e[313]
    DIRECTION OUTPUT ;
    USE SIGNAL ;
    PORT
      LAYER M4 ;
        RECT  64.716 78.912 64.8 78.936 ;
    END
  END bank_e[313]
  PIN bank_e[314]
    DIRECTION OUTPUT ;
    USE SIGNAL ;
    PORT
      LAYER M4 ;
        RECT  64.716 79.152 64.8 79.176 ;
    END
  END bank_e[314]
  PIN bank_e[315]
    DIRECTION OUTPUT ;
    USE SIGNAL ;
    PORT
      LAYER M4 ;
        RECT  64.716 79.392 64.8 79.416 ;
    END
  END bank_e[315]
  PIN bank_e[316]
    DIRECTION OUTPUT ;
    USE SIGNAL ;
    PORT
      LAYER M4 ;
        RECT  64.716 79.68 64.8 79.704 ;
    END
  END bank_e[316]
  PIN bank_e[317]
    DIRECTION OUTPUT ;
    USE SIGNAL ;
    PORT
      LAYER M4 ;
        RECT  64.716 79.92 64.8 79.944 ;
    END
  END bank_e[317]
  PIN bank_e[318]
    DIRECTION OUTPUT ;
    USE SIGNAL ;
    PORT
      LAYER M4 ;
        RECT  64.716 80.16 64.8 80.184 ;
    END
  END bank_e[318]
  PIN bank_e[319]
    DIRECTION OUTPUT ;
    USE SIGNAL ;
    PORT
      LAYER M4 ;
        RECT  64.716 80.4 64.8 80.424 ;
    END
  END bank_e[319]
  PIN bank_e[31]
    DIRECTION OUTPUT ;
    USE SIGNAL ;
    PORT
      LAYER M4 ;
        RECT  64.716 8.4 64.8 8.424 ;
    END
  END bank_e[31]
  PIN bank_e[320]
    DIRECTION OUTPUT ;
    USE SIGNAL ;
    PORT
      LAYER M4 ;
        RECT  64.716 80.688 64.8 80.712 ;
    END
  END bank_e[320]
  PIN bank_e[321]
    DIRECTION OUTPUT ;
    USE SIGNAL ;
    PORT
      LAYER M4 ;
        RECT  64.716 80.928 64.8 80.952 ;
    END
  END bank_e[321]
  PIN bank_e[322]
    DIRECTION OUTPUT ;
    USE SIGNAL ;
    PORT
      LAYER M4 ;
        RECT  64.716 81.168 64.8 81.192 ;
    END
  END bank_e[322]
  PIN bank_e[323]
    DIRECTION OUTPUT ;
    USE SIGNAL ;
    PORT
      LAYER M4 ;
        RECT  64.716 81.408 64.8 81.432 ;
    END
  END bank_e[323]
  PIN bank_e[324]
    DIRECTION OUTPUT ;
    USE SIGNAL ;
    PORT
      LAYER M4 ;
        RECT  64.716 81.648 64.8 81.672 ;
    END
  END bank_e[324]
  PIN bank_e[325]
    DIRECTION OUTPUT ;
    USE SIGNAL ;
    PORT
      LAYER M4 ;
        RECT  64.716 81.936 64.8 81.96 ;
    END
  END bank_e[325]
  PIN bank_e[326]
    DIRECTION OUTPUT ;
    USE SIGNAL ;
    PORT
      LAYER M4 ;
        RECT  64.716 82.176 64.8 82.2 ;
    END
  END bank_e[326]
  PIN bank_e[327]
    DIRECTION OUTPUT ;
    USE SIGNAL ;
    PORT
      LAYER M4 ;
        RECT  64.716 82.416 64.8 82.44 ;
    END
  END bank_e[327]
  PIN bank_e[328]
    DIRECTION OUTPUT ;
    USE SIGNAL ;
    PORT
      LAYER M4 ;
        RECT  64.716 82.656 64.8 82.68 ;
    END
  END bank_e[328]
  PIN bank_e[329]
    DIRECTION OUTPUT ;
    USE SIGNAL ;
    PORT
      LAYER M4 ;
        RECT  64.716 82.896 64.8 82.92 ;
    END
  END bank_e[329]
  PIN bank_e[32]
    DIRECTION OUTPUT ;
    USE SIGNAL ;
    PORT
      LAYER M4 ;
        RECT  64.716 8.64 64.8 8.664 ;
    END
  END bank_e[32]
  PIN bank_e[330]
    DIRECTION OUTPUT ;
    USE SIGNAL ;
    PORT
      LAYER M4 ;
        RECT  64.716 83.184 64.8 83.208 ;
    END
  END bank_e[330]
  PIN bank_e[331]
    DIRECTION OUTPUT ;
    USE SIGNAL ;
    PORT
      LAYER M4 ;
        RECT  64.716 83.424 64.8 83.448 ;
    END
  END bank_e[331]
  PIN bank_e[332]
    DIRECTION OUTPUT ;
    USE SIGNAL ;
    PORT
      LAYER M4 ;
        RECT  64.716 83.664 64.8 83.688 ;
    END
  END bank_e[332]
  PIN bank_e[333]
    DIRECTION OUTPUT ;
    USE SIGNAL ;
    PORT
      LAYER M4 ;
        RECT  64.716 83.904 64.8 83.928 ;
    END
  END bank_e[333]
  PIN bank_e[334]
    DIRECTION OUTPUT ;
    USE SIGNAL ;
    PORT
      LAYER M4 ;
        RECT  64.716 84.144 64.8 84.168 ;
    END
  END bank_e[334]
  PIN bank_e[335]
    DIRECTION OUTPUT ;
    USE SIGNAL ;
    PORT
      LAYER M4 ;
        RECT  64.716 84.432 64.8 84.456 ;
    END
  END bank_e[335]
  PIN bank_e[336]
    DIRECTION OUTPUT ;
    USE SIGNAL ;
    PORT
      LAYER M4 ;
        RECT  64.716 84.672 64.8 84.696 ;
    END
  END bank_e[336]
  PIN bank_e[337]
    DIRECTION OUTPUT ;
    USE SIGNAL ;
    PORT
      LAYER M4 ;
        RECT  64.716 84.912 64.8 84.936 ;
    END
  END bank_e[337]
  PIN bank_e[338]
    DIRECTION OUTPUT ;
    USE SIGNAL ;
    PORT
      LAYER M4 ;
        RECT  64.716 85.152 64.8 85.176 ;
    END
  END bank_e[338]
  PIN bank_e[339]
    DIRECTION OUTPUT ;
    USE SIGNAL ;
    PORT
      LAYER M4 ;
        RECT  64.716 85.44 64.8 85.464 ;
    END
  END bank_e[339]
  PIN bank_e[33]
    DIRECTION OUTPUT ;
    USE SIGNAL ;
    PORT
      LAYER M4 ;
        RECT  64.716 8.928 64.8 8.952 ;
    END
  END bank_e[33]
  PIN bank_e[340]
    DIRECTION OUTPUT ;
    USE SIGNAL ;
    PORT
      LAYER M4 ;
        RECT  64.716 85.68 64.8 85.704 ;
    END
  END bank_e[340]
  PIN bank_e[341]
    DIRECTION OUTPUT ;
    USE SIGNAL ;
    PORT
      LAYER M4 ;
        RECT  64.716 85.92 64.8 85.944 ;
    END
  END bank_e[341]
  PIN bank_e[342]
    DIRECTION OUTPUT ;
    USE SIGNAL ;
    PORT
      LAYER M4 ;
        RECT  64.716 86.16 64.8 86.184 ;
    END
  END bank_e[342]
  PIN bank_e[343]
    DIRECTION OUTPUT ;
    USE SIGNAL ;
    PORT
      LAYER M4 ;
        RECT  64.716 86.4 64.8 86.424 ;
    END
  END bank_e[343]
  PIN bank_e[344]
    DIRECTION OUTPUT ;
    USE SIGNAL ;
    PORT
      LAYER M4 ;
        RECT  64.716 86.688 64.8 86.712 ;
    END
  END bank_e[344]
  PIN bank_e[345]
    DIRECTION OUTPUT ;
    USE SIGNAL ;
    PORT
      LAYER M4 ;
        RECT  64.716 86.928 64.8 86.952 ;
    END
  END bank_e[345]
  PIN bank_e[346]
    DIRECTION OUTPUT ;
    USE SIGNAL ;
    PORT
      LAYER M4 ;
        RECT  64.716 87.168 64.8 87.192 ;
    END
  END bank_e[346]
  PIN bank_e[347]
    DIRECTION OUTPUT ;
    USE SIGNAL ;
    PORT
      LAYER M4 ;
        RECT  64.716 87.408 64.8 87.432 ;
    END
  END bank_e[347]
  PIN bank_e[348]
    DIRECTION OUTPUT ;
    USE SIGNAL ;
    PORT
      LAYER M4 ;
        RECT  64.716 87.648 64.8 87.672 ;
    END
  END bank_e[348]
  PIN bank_e[349]
    DIRECTION OUTPUT ;
    USE SIGNAL ;
    PORT
      LAYER M4 ;
        RECT  64.716 87.936 64.8 87.96 ;
    END
  END bank_e[349]
  PIN bank_e[34]
    DIRECTION OUTPUT ;
    USE SIGNAL ;
    PORT
      LAYER M4 ;
        RECT  64.716 9.168 64.8 9.192 ;
    END
  END bank_e[34]
  PIN bank_e[350]
    DIRECTION OUTPUT ;
    USE SIGNAL ;
    PORT
      LAYER M4 ;
        RECT  64.716 88.176 64.8 88.2 ;
    END
  END bank_e[350]
  PIN bank_e[351]
    DIRECTION OUTPUT ;
    USE SIGNAL ;
    PORT
      LAYER M4 ;
        RECT  64.716 88.416 64.8 88.44 ;
    END
  END bank_e[351]
  PIN bank_e[352]
    DIRECTION OUTPUT ;
    USE SIGNAL ;
    PORT
      LAYER M4 ;
        RECT  64.716 88.656 64.8 88.68 ;
    END
  END bank_e[352]
  PIN bank_e[353]
    DIRECTION OUTPUT ;
    USE SIGNAL ;
    PORT
      LAYER M4 ;
        RECT  64.716 88.896 64.8 88.92 ;
    END
  END bank_e[353]
  PIN bank_e[354]
    DIRECTION OUTPUT ;
    USE SIGNAL ;
    PORT
      LAYER M4 ;
        RECT  64.716 89.184 64.8 89.208 ;
    END
  END bank_e[354]
  PIN bank_e[355]
    DIRECTION OUTPUT ;
    USE SIGNAL ;
    PORT
      LAYER M4 ;
        RECT  64.716 89.424 64.8 89.448 ;
    END
  END bank_e[355]
  PIN bank_e[356]
    DIRECTION OUTPUT ;
    USE SIGNAL ;
    PORT
      LAYER M4 ;
        RECT  64.716 89.664 64.8 89.688 ;
    END
  END bank_e[356]
  PIN bank_e[357]
    DIRECTION OUTPUT ;
    USE SIGNAL ;
    PORT
      LAYER M4 ;
        RECT  64.716 89.904 64.8 89.928 ;
    END
  END bank_e[357]
  PIN bank_e[358]
    DIRECTION OUTPUT ;
    USE SIGNAL ;
    PORT
      LAYER M4 ;
        RECT  64.716 90.144 64.8 90.168 ;
    END
  END bank_e[358]
  PIN bank_e[359]
    DIRECTION OUTPUT ;
    USE SIGNAL ;
    PORT
      LAYER M4 ;
        RECT  64.716 90.432 64.8 90.456 ;
    END
  END bank_e[359]
  PIN bank_e[35]
    DIRECTION OUTPUT ;
    USE SIGNAL ;
    PORT
      LAYER M4 ;
        RECT  64.716 9.408 64.8 9.432 ;
    END
  END bank_e[35]
  PIN bank_e[360]
    DIRECTION OUTPUT ;
    USE SIGNAL ;
    PORT
      LAYER M4 ;
        RECT  64.716 90.672 64.8 90.696 ;
    END
  END bank_e[360]
  PIN bank_e[361]
    DIRECTION OUTPUT ;
    USE SIGNAL ;
    PORT
      LAYER M4 ;
        RECT  64.716 90.912 64.8 90.936 ;
    END
  END bank_e[361]
  PIN bank_e[362]
    DIRECTION OUTPUT ;
    USE SIGNAL ;
    PORT
      LAYER M4 ;
        RECT  64.716 91.152 64.8 91.176 ;
    END
  END bank_e[362]
  PIN bank_e[363]
    DIRECTION OUTPUT ;
    USE SIGNAL ;
    PORT
      LAYER M4 ;
        RECT  64.716 91.44 64.8 91.464 ;
    END
  END bank_e[363]
  PIN bank_e[364]
    DIRECTION OUTPUT ;
    USE SIGNAL ;
    PORT
      LAYER M4 ;
        RECT  64.716 91.68 64.8 91.704 ;
    END
  END bank_e[364]
  PIN bank_e[365]
    DIRECTION OUTPUT ;
    USE SIGNAL ;
    PORT
      LAYER M4 ;
        RECT  64.716 91.92 64.8 91.944 ;
    END
  END bank_e[365]
  PIN bank_e[366]
    DIRECTION OUTPUT ;
    USE SIGNAL ;
    PORT
      LAYER M4 ;
        RECT  64.716 92.16 64.8 92.184 ;
    END
  END bank_e[366]
  PIN bank_e[367]
    DIRECTION OUTPUT ;
    USE SIGNAL ;
    PORT
      LAYER M4 ;
        RECT  64.716 92.4 64.8 92.424 ;
    END
  END bank_e[367]
  PIN bank_e[368]
    DIRECTION OUTPUT ;
    USE SIGNAL ;
    PORT
      LAYER M4 ;
        RECT  64.716 92.688 64.8 92.712 ;
    END
  END bank_e[368]
  PIN bank_e[369]
    DIRECTION OUTPUT ;
    USE SIGNAL ;
    PORT
      LAYER M4 ;
        RECT  64.716 92.928 64.8 92.952 ;
    END
  END bank_e[369]
  PIN bank_e[36]
    DIRECTION OUTPUT ;
    USE SIGNAL ;
    PORT
      LAYER M4 ;
        RECT  64.716 9.648 64.8 9.672 ;
    END
  END bank_e[36]
  PIN bank_e[370]
    DIRECTION OUTPUT ;
    USE SIGNAL ;
    PORT
      LAYER M4 ;
        RECT  64.716 93.168 64.8 93.192 ;
    END
  END bank_e[370]
  PIN bank_e[371]
    DIRECTION OUTPUT ;
    USE SIGNAL ;
    PORT
      LAYER M4 ;
        RECT  64.716 93.408 64.8 93.432 ;
    END
  END bank_e[371]
  PIN bank_e[372]
    DIRECTION OUTPUT ;
    USE SIGNAL ;
    PORT
      LAYER M4 ;
        RECT  64.716 93.648 64.8 93.672 ;
    END
  END bank_e[372]
  PIN bank_e[373]
    DIRECTION OUTPUT ;
    USE SIGNAL ;
    PORT
      LAYER M4 ;
        RECT  64.716 93.936 64.8 93.96 ;
    END
  END bank_e[373]
  PIN bank_e[374]
    DIRECTION OUTPUT ;
    USE SIGNAL ;
    PORT
      LAYER M4 ;
        RECT  64.716 94.176 64.8 94.2 ;
    END
  END bank_e[374]
  PIN bank_e[375]
    DIRECTION OUTPUT ;
    USE SIGNAL ;
    PORT
      LAYER M4 ;
        RECT  64.716 94.416 64.8 94.44 ;
    END
  END bank_e[375]
  PIN bank_e[376]
    DIRECTION OUTPUT ;
    USE SIGNAL ;
    PORT
      LAYER M4 ;
        RECT  64.716 94.656 64.8 94.68 ;
    END
  END bank_e[376]
  PIN bank_e[377]
    DIRECTION OUTPUT ;
    USE SIGNAL ;
    PORT
      LAYER M4 ;
        RECT  64.716 94.896 64.8 94.92 ;
    END
  END bank_e[377]
  PIN bank_e[378]
    DIRECTION OUTPUT ;
    USE SIGNAL ;
    PORT
      LAYER M4 ;
        RECT  64.716 95.184 64.8 95.208 ;
    END
  END bank_e[378]
  PIN bank_e[379]
    DIRECTION OUTPUT ;
    USE SIGNAL ;
    PORT
      LAYER M4 ;
        RECT  64.716 95.424 64.8 95.448 ;
    END
  END bank_e[379]
  PIN bank_e[37]
    DIRECTION OUTPUT ;
    USE SIGNAL ;
    PORT
      LAYER M4 ;
        RECT  64.716 9.888 64.8 9.912 ;
    END
  END bank_e[37]
  PIN bank_e[380]
    DIRECTION OUTPUT ;
    USE SIGNAL ;
    PORT
      LAYER M4 ;
        RECT  64.716 95.664 64.8 95.688 ;
    END
  END bank_e[380]
  PIN bank_e[381]
    DIRECTION OUTPUT ;
    USE SIGNAL ;
    PORT
      LAYER M4 ;
        RECT  64.716 95.904 64.8 95.928 ;
    END
  END bank_e[381]
  PIN bank_e[382]
    DIRECTION OUTPUT ;
    USE SIGNAL ;
    PORT
      LAYER M4 ;
        RECT  64.716 96.192 64.8 96.216 ;
    END
  END bank_e[382]
  PIN bank_e[383]
    DIRECTION OUTPUT ;
    USE SIGNAL ;
    PORT
      LAYER M4 ;
        RECT  64.716 96.432 64.8 96.456 ;
    END
  END bank_e[383]
  PIN bank_e[384]
    DIRECTION OUTPUT ;
    USE SIGNAL ;
    PORT
      LAYER M4 ;
        RECT  64.716 96.672 64.8 96.696 ;
    END
  END bank_e[384]
  PIN bank_e[385]
    DIRECTION OUTPUT ;
    USE SIGNAL ;
    PORT
      LAYER M4 ;
        RECT  64.716 96.912 64.8 96.936 ;
    END
  END bank_e[385]
  PIN bank_e[386]
    DIRECTION OUTPUT ;
    USE SIGNAL ;
    PORT
      LAYER M4 ;
        RECT  64.716 97.152 64.8 97.176 ;
    END
  END bank_e[386]
  PIN bank_e[387]
    DIRECTION OUTPUT ;
    USE SIGNAL ;
    PORT
      LAYER M4 ;
        RECT  64.716 97.44 64.8 97.464 ;
    END
  END bank_e[387]
  PIN bank_e[388]
    DIRECTION OUTPUT ;
    USE SIGNAL ;
    PORT
      LAYER M4 ;
        RECT  64.716 97.68 64.8 97.704 ;
    END
  END bank_e[388]
  PIN bank_e[389]
    DIRECTION OUTPUT ;
    USE SIGNAL ;
    PORT
      LAYER M4 ;
        RECT  64.716 97.92 64.8 97.944 ;
    END
  END bank_e[389]
  PIN bank_e[38]
    DIRECTION OUTPUT ;
    USE SIGNAL ;
    PORT
      LAYER M4 ;
        RECT  64.716 10.176 64.8 10.2 ;
    END
  END bank_e[38]
  PIN bank_e[390]
    DIRECTION OUTPUT ;
    USE SIGNAL ;
    PORT
      LAYER M4 ;
        RECT  64.716 98.16 64.8 98.184 ;
    END
  END bank_e[390]
  PIN bank_e[391]
    DIRECTION OUTPUT ;
    USE SIGNAL ;
    PORT
      LAYER M4 ;
        RECT  64.716 98.4 64.8 98.424 ;
    END
  END bank_e[391]
  PIN bank_e[392]
    DIRECTION OUTPUT ;
    USE SIGNAL ;
    PORT
      LAYER M4 ;
        RECT  64.716 98.688 64.8 98.712 ;
    END
  END bank_e[392]
  PIN bank_e[393]
    DIRECTION OUTPUT ;
    USE SIGNAL ;
    PORT
      LAYER M4 ;
        RECT  64.716 98.928 64.8 98.952 ;
    END
  END bank_e[393]
  PIN bank_e[394]
    DIRECTION OUTPUT ;
    USE SIGNAL ;
    PORT
      LAYER M4 ;
        RECT  64.716 99.168 64.8 99.192 ;
    END
  END bank_e[394]
  PIN bank_e[395]
    DIRECTION OUTPUT ;
    USE SIGNAL ;
    PORT
      LAYER M4 ;
        RECT  64.716 99.408 64.8 99.432 ;
    END
  END bank_e[395]
  PIN bank_e[396]
    DIRECTION OUTPUT ;
    USE SIGNAL ;
    PORT
      LAYER M4 ;
        RECT  64.716 99.648 64.8 99.672 ;
    END
  END bank_e[396]
  PIN bank_e[397]
    DIRECTION OUTPUT ;
    USE SIGNAL ;
    PORT
      LAYER M4 ;
        RECT  64.716 99.936 64.8 99.96 ;
    END
  END bank_e[397]
  PIN bank_e[398]
    DIRECTION OUTPUT ;
    USE SIGNAL ;
    PORT
      LAYER M4 ;
        RECT  64.716 100.176 64.8 100.2 ;
    END
  END bank_e[398]
  PIN bank_e[399]
    DIRECTION OUTPUT ;
    USE SIGNAL ;
    PORT
      LAYER M4 ;
        RECT  64.716 100.416 64.8 100.44 ;
    END
  END bank_e[399]
  PIN bank_e[39]
    DIRECTION OUTPUT ;
    USE SIGNAL ;
    PORT
      LAYER M4 ;
        RECT  64.716 10.416 64.8 10.44 ;
    END
  END bank_e[39]
  PIN bank_e[3]
    DIRECTION OUTPUT ;
    USE SIGNAL ;
    PORT
      LAYER M4 ;
        RECT  64.716 1.392 64.8 1.416 ;
    END
  END bank_e[3]
  PIN bank_e[400]
    DIRECTION OUTPUT ;
    USE SIGNAL ;
    PORT
      LAYER M4 ;
        RECT  64.716 100.656 64.8 100.68 ;
    END
  END bank_e[400]
  PIN bank_e[401]
    DIRECTION OUTPUT ;
    USE SIGNAL ;
    PORT
      LAYER M4 ;
        RECT  64.716 100.896 64.8 100.92 ;
    END
  END bank_e[401]
  PIN bank_e[402]
    DIRECTION OUTPUT ;
    USE SIGNAL ;
    PORT
      LAYER M4 ;
        RECT  64.716 101.184 64.8 101.208 ;
    END
  END bank_e[402]
  PIN bank_e[403]
    DIRECTION OUTPUT ;
    USE SIGNAL ;
    PORT
      LAYER M4 ;
        RECT  64.716 101.424 64.8 101.448 ;
    END
  END bank_e[403]
  PIN bank_e[404]
    DIRECTION OUTPUT ;
    USE SIGNAL ;
    PORT
      LAYER M4 ;
        RECT  64.716 101.664 64.8 101.688 ;
    END
  END bank_e[404]
  PIN bank_e[405]
    DIRECTION OUTPUT ;
    USE SIGNAL ;
    PORT
      LAYER M4 ;
        RECT  64.716 101.904 64.8 101.928 ;
    END
  END bank_e[405]
  PIN bank_e[406]
    DIRECTION OUTPUT ;
    USE SIGNAL ;
    PORT
      LAYER M4 ;
        RECT  64.716 102.192 64.8 102.216 ;
    END
  END bank_e[406]
  PIN bank_e[407]
    DIRECTION OUTPUT ;
    USE SIGNAL ;
    PORT
      LAYER M4 ;
        RECT  64.716 102.432 64.8 102.456 ;
    END
  END bank_e[407]
  PIN bank_e[408]
    DIRECTION OUTPUT ;
    USE SIGNAL ;
    PORT
      LAYER M4 ;
        RECT  64.716 102.672 64.8 102.696 ;
    END
  END bank_e[408]
  PIN bank_e[409]
    DIRECTION OUTPUT ;
    USE SIGNAL ;
    PORT
      LAYER M4 ;
        RECT  64.716 102.912 64.8 102.936 ;
    END
  END bank_e[409]
  PIN bank_e[40]
    DIRECTION OUTPUT ;
    USE SIGNAL ;
    PORT
      LAYER M4 ;
        RECT  64.716 10.656 64.8 10.68 ;
    END
  END bank_e[40]
  PIN bank_e[410]
    DIRECTION OUTPUT ;
    USE SIGNAL ;
    PORT
      LAYER M4 ;
        RECT  64.716 103.152 64.8 103.176 ;
    END
  END bank_e[410]
  PIN bank_e[411]
    DIRECTION OUTPUT ;
    USE SIGNAL ;
    PORT
      LAYER M4 ;
        RECT  64.716 103.44 64.8 103.464 ;
    END
  END bank_e[411]
  PIN bank_e[412]
    DIRECTION OUTPUT ;
    USE SIGNAL ;
    PORT
      LAYER M4 ;
        RECT  64.716 103.68 64.8 103.704 ;
    END
  END bank_e[412]
  PIN bank_e[413]
    DIRECTION OUTPUT ;
    USE SIGNAL ;
    PORT
      LAYER M4 ;
        RECT  64.716 103.92 64.8 103.944 ;
    END
  END bank_e[413]
  PIN bank_e[414]
    DIRECTION OUTPUT ;
    USE SIGNAL ;
    PORT
      LAYER M4 ;
        RECT  64.716 104.16 64.8 104.184 ;
    END
  END bank_e[414]
  PIN bank_e[415]
    DIRECTION OUTPUT ;
    USE SIGNAL ;
    PORT
      LAYER M4 ;
        RECT  64.716 104.4 64.8 104.424 ;
    END
  END bank_e[415]
  PIN bank_e[416]
    DIRECTION OUTPUT ;
    USE SIGNAL ;
    PORT
      LAYER M4 ;
        RECT  64.716 104.688 64.8 104.712 ;
    END
  END bank_e[416]
  PIN bank_e[417]
    DIRECTION OUTPUT ;
    USE SIGNAL ;
    PORT
      LAYER M4 ;
        RECT  64.716 104.928 64.8 104.952 ;
    END
  END bank_e[417]
  PIN bank_e[418]
    DIRECTION OUTPUT ;
    USE SIGNAL ;
    PORT
      LAYER M4 ;
        RECT  64.716 105.168 64.8 105.192 ;
    END
  END bank_e[418]
  PIN bank_e[419]
    DIRECTION OUTPUT ;
    USE SIGNAL ;
    PORT
      LAYER M4 ;
        RECT  64.716 105.408 64.8 105.432 ;
    END
  END bank_e[419]
  PIN bank_e[41]
    DIRECTION OUTPUT ;
    USE SIGNAL ;
    PORT
      LAYER M4 ;
        RECT  64.716 10.896 64.8 10.92 ;
    END
  END bank_e[41]
  PIN bank_e[420]
    DIRECTION OUTPUT ;
    USE SIGNAL ;
    PORT
      LAYER M4 ;
        RECT  64.716 105.648 64.8 105.672 ;
    END
  END bank_e[420]
  PIN bank_e[421]
    DIRECTION OUTPUT ;
    USE SIGNAL ;
    PORT
      LAYER M4 ;
        RECT  64.716 105.936 64.8 105.96 ;
    END
  END bank_e[421]
  PIN bank_e[422]
    DIRECTION OUTPUT ;
    USE SIGNAL ;
    PORT
      LAYER M4 ;
        RECT  64.716 106.176 64.8 106.2 ;
    END
  END bank_e[422]
  PIN bank_e[423]
    DIRECTION OUTPUT ;
    USE SIGNAL ;
    PORT
      LAYER M4 ;
        RECT  64.716 106.416 64.8 106.44 ;
    END
  END bank_e[423]
  PIN bank_e[424]
    DIRECTION OUTPUT ;
    USE SIGNAL ;
    PORT
      LAYER M4 ;
        RECT  64.716 106.656 64.8 106.68 ;
    END
  END bank_e[424]
  PIN bank_e[425]
    DIRECTION OUTPUT ;
    USE SIGNAL ;
    PORT
      LAYER M4 ;
        RECT  64.716 106.944 64.8 106.968 ;
    END
  END bank_e[425]
  PIN bank_e[426]
    DIRECTION OUTPUT ;
    USE SIGNAL ;
    PORT
      LAYER M4 ;
        RECT  64.716 107.184 64.8 107.208 ;
    END
  END bank_e[426]
  PIN bank_e[427]
    DIRECTION OUTPUT ;
    USE SIGNAL ;
    PORT
      LAYER M4 ;
        RECT  64.716 107.424 64.8 107.448 ;
    END
  END bank_e[427]
  PIN bank_e[428]
    DIRECTION OUTPUT ;
    USE SIGNAL ;
    PORT
      LAYER M4 ;
        RECT  64.716 107.664 64.8 107.688 ;
    END
  END bank_e[428]
  PIN bank_e[429]
    DIRECTION OUTPUT ;
    USE SIGNAL ;
    PORT
      LAYER M4 ;
        RECT  64.716 107.904 64.8 107.928 ;
    END
  END bank_e[429]
  PIN bank_e[42]
    DIRECTION OUTPUT ;
    USE SIGNAL ;
    PORT
      LAYER M4 ;
        RECT  64.716 11.136 64.8 11.16 ;
    END
  END bank_e[42]
  PIN bank_e[430]
    DIRECTION OUTPUT ;
    USE SIGNAL ;
    PORT
      LAYER M4 ;
        RECT  64.716 108.192 64.8 108.216 ;
    END
  END bank_e[430]
  PIN bank_e[431]
    DIRECTION OUTPUT ;
    USE SIGNAL ;
    PORT
      LAYER M4 ;
        RECT  64.716 108.432 64.8 108.456 ;
    END
  END bank_e[431]
  PIN bank_e[432]
    DIRECTION OUTPUT ;
    USE SIGNAL ;
    PORT
      LAYER M4 ;
        RECT  64.716 108.672 64.8 108.696 ;
    END
  END bank_e[432]
  PIN bank_e[433]
    DIRECTION OUTPUT ;
    USE SIGNAL ;
    PORT
      LAYER M4 ;
        RECT  64.716 108.912 64.8 108.936 ;
    END
  END bank_e[433]
  PIN bank_e[434]
    DIRECTION OUTPUT ;
    USE SIGNAL ;
    PORT
      LAYER M4 ;
        RECT  64.716 109.152 64.8 109.176 ;
    END
  END bank_e[434]
  PIN bank_e[435]
    DIRECTION OUTPUT ;
    USE SIGNAL ;
    PORT
      LAYER M4 ;
        RECT  64.716 109.44 64.8 109.464 ;
    END
  END bank_e[435]
  PIN bank_e[436]
    DIRECTION OUTPUT ;
    USE SIGNAL ;
    PORT
      LAYER M4 ;
        RECT  64.716 109.68 64.8 109.704 ;
    END
  END bank_e[436]
  PIN bank_e[437]
    DIRECTION OUTPUT ;
    USE SIGNAL ;
    PORT
      LAYER M4 ;
        RECT  64.716 109.92 64.8 109.944 ;
    END
  END bank_e[437]
  PIN bank_e[438]
    DIRECTION OUTPUT ;
    USE SIGNAL ;
    PORT
      LAYER M4 ;
        RECT  64.716 110.16 64.8 110.184 ;
    END
  END bank_e[438]
  PIN bank_e[439]
    DIRECTION OUTPUT ;
    USE SIGNAL ;
    PORT
      LAYER M4 ;
        RECT  64.716 110.4 64.8 110.424 ;
    END
  END bank_e[439]
  PIN bank_e[43]
    DIRECTION OUTPUT ;
    USE SIGNAL ;
    PORT
      LAYER M4 ;
        RECT  64.716 11.424 64.8 11.448 ;
    END
  END bank_e[43]
  PIN bank_e[440]
    DIRECTION OUTPUT ;
    USE SIGNAL ;
    PORT
      LAYER M4 ;
        RECT  64.716 110.688 64.8 110.712 ;
    END
  END bank_e[440]
  PIN bank_e[441]
    DIRECTION OUTPUT ;
    USE SIGNAL ;
    PORT
      LAYER M4 ;
        RECT  64.716 110.928 64.8 110.952 ;
    END
  END bank_e[441]
  PIN bank_e[442]
    DIRECTION OUTPUT ;
    USE SIGNAL ;
    PORT
      LAYER M4 ;
        RECT  64.716 111.168 64.8 111.192 ;
    END
  END bank_e[442]
  PIN bank_e[443]
    DIRECTION OUTPUT ;
    USE SIGNAL ;
    PORT
      LAYER M4 ;
        RECT  64.716 111.408 64.8 111.432 ;
    END
  END bank_e[443]
  PIN bank_e[444]
    DIRECTION OUTPUT ;
    USE SIGNAL ;
    PORT
      LAYER M4 ;
        RECT  64.716 111.648 64.8 111.672 ;
    END
  END bank_e[444]
  PIN bank_e[445]
    DIRECTION OUTPUT ;
    USE SIGNAL ;
    PORT
      LAYER M4 ;
        RECT  64.716 111.936 64.8 111.96 ;
    END
  END bank_e[445]
  PIN bank_e[446]
    DIRECTION OUTPUT ;
    USE SIGNAL ;
    PORT
      LAYER M4 ;
        RECT  64.716 112.176 64.8 112.2 ;
    END
  END bank_e[446]
  PIN bank_e[447]
    DIRECTION OUTPUT ;
    USE SIGNAL ;
    PORT
      LAYER M4 ;
        RECT  64.716 112.416 64.8 112.44 ;
    END
  END bank_e[447]
  PIN bank_e[448]
    DIRECTION OUTPUT ;
    USE SIGNAL ;
    PORT
      LAYER M4 ;
        RECT  64.716 112.656 64.8 112.68 ;
    END
  END bank_e[448]
  PIN bank_e[449]
    DIRECTION OUTPUT ;
    USE SIGNAL ;
    PORT
      LAYER M4 ;
        RECT  64.716 112.944 64.8 112.968 ;
    END
  END bank_e[449]
  PIN bank_e[44]
    DIRECTION OUTPUT ;
    USE SIGNAL ;
    PORT
      LAYER M4 ;
        RECT  64.716 11.664 64.8 11.688 ;
    END
  END bank_e[44]
  PIN bank_e[450]
    DIRECTION OUTPUT ;
    USE SIGNAL ;
    PORT
      LAYER M4 ;
        RECT  64.716 113.184 64.8 113.208 ;
    END
  END bank_e[450]
  PIN bank_e[451]
    DIRECTION OUTPUT ;
    USE SIGNAL ;
    PORT
      LAYER M4 ;
        RECT  64.716 113.424 64.8 113.448 ;
    END
  END bank_e[451]
  PIN bank_e[452]
    DIRECTION OUTPUT ;
    USE SIGNAL ;
    PORT
      LAYER M4 ;
        RECT  64.716 113.664 64.8 113.688 ;
    END
  END bank_e[452]
  PIN bank_e[453]
    DIRECTION OUTPUT ;
    USE SIGNAL ;
    PORT
      LAYER M4 ;
        RECT  64.716 113.904 64.8 113.928 ;
    END
  END bank_e[453]
  PIN bank_e[454]
    DIRECTION OUTPUT ;
    USE SIGNAL ;
    PORT
      LAYER M4 ;
        RECT  64.716 114.192 64.8 114.216 ;
    END
  END bank_e[454]
  PIN bank_e[455]
    DIRECTION OUTPUT ;
    USE SIGNAL ;
    PORT
      LAYER M4 ;
        RECT  64.716 114.432 64.8 114.456 ;
    END
  END bank_e[455]
  PIN bank_e[456]
    DIRECTION OUTPUT ;
    USE SIGNAL ;
    PORT
      LAYER M4 ;
        RECT  64.716 114.672 64.8 114.696 ;
    END
  END bank_e[456]
  PIN bank_e[457]
    DIRECTION OUTPUT ;
    USE SIGNAL ;
    PORT
      LAYER M4 ;
        RECT  64.716 114.912 64.8 114.936 ;
    END
  END bank_e[457]
  PIN bank_e[458]
    DIRECTION OUTPUT ;
    USE SIGNAL ;
    PORT
      LAYER M4 ;
        RECT  64.716 115.152 64.8 115.176 ;
    END
  END bank_e[458]
  PIN bank_e[459]
    DIRECTION OUTPUT ;
    USE SIGNAL ;
    PORT
      LAYER M4 ;
        RECT  64.716 115.44 64.8 115.464 ;
    END
  END bank_e[459]
  PIN bank_e[45]
    DIRECTION OUTPUT ;
    USE SIGNAL ;
    PORT
      LAYER M4 ;
        RECT  64.716 11.904 64.8 11.928 ;
    END
  END bank_e[45]
  PIN bank_e[460]
    DIRECTION OUTPUT ;
    USE SIGNAL ;
    PORT
      LAYER M4 ;
        RECT  64.716 115.68 64.8 115.704 ;
    END
  END bank_e[460]
  PIN bank_e[461]
    DIRECTION OUTPUT ;
    USE SIGNAL ;
    PORT
      LAYER M4 ;
        RECT  64.716 115.92 64.8 115.944 ;
    END
  END bank_e[461]
  PIN bank_e[462]
    DIRECTION OUTPUT ;
    USE SIGNAL ;
    PORT
      LAYER M4 ;
        RECT  64.716 116.16 64.8 116.184 ;
    END
  END bank_e[462]
  PIN bank_e[463]
    DIRECTION OUTPUT ;
    USE SIGNAL ;
    PORT
      LAYER M4 ;
        RECT  64.716 116.4 64.8 116.424 ;
    END
  END bank_e[463]
  PIN bank_e[464]
    DIRECTION OUTPUT ;
    USE SIGNAL ;
    PORT
      LAYER M4 ;
        RECT  64.716 116.688 64.8 116.712 ;
    END
  END bank_e[464]
  PIN bank_e[465]
    DIRECTION OUTPUT ;
    USE SIGNAL ;
    PORT
      LAYER M4 ;
        RECT  64.716 116.928 64.8 116.952 ;
    END
  END bank_e[465]
  PIN bank_e[466]
    DIRECTION OUTPUT ;
    USE SIGNAL ;
    PORT
      LAYER M4 ;
        RECT  64.716 117.168 64.8 117.192 ;
    END
  END bank_e[466]
  PIN bank_e[467]
    DIRECTION OUTPUT ;
    USE SIGNAL ;
    PORT
      LAYER M4 ;
        RECT  64.716 117.408 64.8 117.432 ;
    END
  END bank_e[467]
  PIN bank_e[468]
    DIRECTION OUTPUT ;
    USE SIGNAL ;
    PORT
      LAYER M4 ;
        RECT  64.716 117.648 64.8 117.672 ;
    END
  END bank_e[468]
  PIN bank_e[469]
    DIRECTION OUTPUT ;
    USE SIGNAL ;
    PORT
      LAYER M4 ;
        RECT  64.716 117.936 64.8 117.96 ;
    END
  END bank_e[469]
  PIN bank_e[46]
    DIRECTION OUTPUT ;
    USE SIGNAL ;
    PORT
      LAYER M4 ;
        RECT  64.716 12.144 64.8 12.168 ;
    END
  END bank_e[46]
  PIN bank_e[470]
    DIRECTION OUTPUT ;
    USE SIGNAL ;
    PORT
      LAYER M4 ;
        RECT  64.716 118.176 64.8 118.2 ;
    END
  END bank_e[470]
  PIN bank_e[471]
    DIRECTION OUTPUT ;
    USE SIGNAL ;
    PORT
      LAYER M4 ;
        RECT  64.716 118.416 64.8 118.44 ;
    END
  END bank_e[471]
  PIN bank_e[472]
    DIRECTION OUTPUT ;
    USE SIGNAL ;
    PORT
      LAYER M4 ;
        RECT  64.716 118.656 64.8 118.68 ;
    END
  END bank_e[472]
  PIN bank_e[473]
    DIRECTION OUTPUT ;
    USE SIGNAL ;
    PORT
      LAYER M4 ;
        RECT  64.716 118.944 64.8 118.968 ;
    END
  END bank_e[473]
  PIN bank_e[474]
    DIRECTION OUTPUT ;
    USE SIGNAL ;
    PORT
      LAYER M4 ;
        RECT  64.716 119.184 64.8 119.208 ;
    END
  END bank_e[474]
  PIN bank_e[475]
    DIRECTION OUTPUT ;
    USE SIGNAL ;
    PORT
      LAYER M4 ;
        RECT  64.716 119.424 64.8 119.448 ;
    END
  END bank_e[475]
  PIN bank_e[476]
    DIRECTION OUTPUT ;
    USE SIGNAL ;
    PORT
      LAYER M4 ;
        RECT  64.716 119.664 64.8 119.688 ;
    END
  END bank_e[476]
  PIN bank_e[477]
    DIRECTION OUTPUT ;
    USE SIGNAL ;
    PORT
      LAYER M4 ;
        RECT  64.716 119.904 64.8 119.928 ;
    END
  END bank_e[477]
  PIN bank_e[478]
    DIRECTION OUTPUT ;
    USE SIGNAL ;
    PORT
      LAYER M4 ;
        RECT  64.716 120.192 64.8 120.216 ;
    END
  END bank_e[478]
  PIN bank_e[479]
    DIRECTION OUTPUT ;
    USE SIGNAL ;
    PORT
      LAYER M4 ;
        RECT  64.716 120.432 64.8 120.456 ;
    END
  END bank_e[479]
  PIN bank_e[47]
    DIRECTION OUTPUT ;
    USE SIGNAL ;
    PORT
      LAYER M4 ;
        RECT  64.716 12.384 64.8 12.408 ;
    END
  END bank_e[47]
  PIN bank_e[480]
    DIRECTION OUTPUT ;
    USE SIGNAL ;
    PORT
      LAYER M4 ;
        RECT  64.716 120.672 64.8 120.696 ;
    END
  END bank_e[480]
  PIN bank_e[481]
    DIRECTION OUTPUT ;
    USE SIGNAL ;
    PORT
      LAYER M4 ;
        RECT  64.716 120.912 64.8 120.936 ;
    END
  END bank_e[481]
  PIN bank_e[482]
    DIRECTION OUTPUT ;
    USE SIGNAL ;
    PORT
      LAYER M4 ;
        RECT  64.716 121.152 64.8 121.176 ;
    END
  END bank_e[482]
  PIN bank_e[483]
    DIRECTION OUTPUT ;
    USE SIGNAL ;
    PORT
      LAYER M4 ;
        RECT  64.716 121.44 64.8 121.464 ;
    END
  END bank_e[483]
  PIN bank_e[484]
    DIRECTION OUTPUT ;
    USE SIGNAL ;
    PORT
      LAYER M4 ;
        RECT  64.716 121.68 64.8 121.704 ;
    END
  END bank_e[484]
  PIN bank_e[485]
    DIRECTION OUTPUT ;
    USE SIGNAL ;
    PORT
      LAYER M4 ;
        RECT  64.716 121.92 64.8 121.944 ;
    END
  END bank_e[485]
  PIN bank_e[486]
    DIRECTION OUTPUT ;
    USE SIGNAL ;
    PORT
      LAYER M4 ;
        RECT  64.716 122.16 64.8 122.184 ;
    END
  END bank_e[486]
  PIN bank_e[487]
    DIRECTION OUTPUT ;
    USE SIGNAL ;
    PORT
      LAYER M4 ;
        RECT  64.716 122.4 64.8 122.424 ;
    END
  END bank_e[487]
  PIN bank_e[488]
    DIRECTION OUTPUT ;
    USE SIGNAL ;
    PORT
      LAYER M4 ;
        RECT  64.716 122.688 64.8 122.712 ;
    END
  END bank_e[488]
  PIN bank_e[489]
    DIRECTION OUTPUT ;
    USE SIGNAL ;
    PORT
      LAYER M4 ;
        RECT  64.716 122.928 64.8 122.952 ;
    END
  END bank_e[489]
  PIN bank_e[48]
    DIRECTION OUTPUT ;
    USE SIGNAL ;
    PORT
      LAYER M4 ;
        RECT  64.716 12.672 64.8 12.696 ;
    END
  END bank_e[48]
  PIN bank_e[490]
    DIRECTION OUTPUT ;
    USE SIGNAL ;
    PORT
      LAYER M4 ;
        RECT  64.716 123.168 64.8 123.192 ;
    END
  END bank_e[490]
  PIN bank_e[491]
    DIRECTION OUTPUT ;
    USE SIGNAL ;
    PORT
      LAYER M4 ;
        RECT  64.716 123.408 64.8 123.432 ;
    END
  END bank_e[491]
  PIN bank_e[492]
    DIRECTION OUTPUT ;
    USE SIGNAL ;
    PORT
      LAYER M4 ;
        RECT  64.716 123.696 64.8 123.72 ;
    END
  END bank_e[492]
  PIN bank_e[493]
    DIRECTION OUTPUT ;
    USE SIGNAL ;
    PORT
      LAYER M4 ;
        RECT  64.716 123.936 64.8 123.96 ;
    END
  END bank_e[493]
  PIN bank_e[494]
    DIRECTION OUTPUT ;
    USE SIGNAL ;
    PORT
      LAYER M4 ;
        RECT  64.716 124.176 64.8 124.2 ;
    END
  END bank_e[494]
  PIN bank_e[495]
    DIRECTION OUTPUT ;
    USE SIGNAL ;
    PORT
      LAYER M4 ;
        RECT  64.716 124.416 64.8 124.44 ;
    END
  END bank_e[495]
  PIN bank_e[496]
    DIRECTION OUTPUT ;
    USE SIGNAL ;
    PORT
      LAYER M4 ;
        RECT  64.716 124.656 64.8 124.68 ;
    END
  END bank_e[496]
  PIN bank_e[497]
    DIRECTION OUTPUT ;
    USE SIGNAL ;
    PORT
      LAYER M4 ;
        RECT  64.716 124.944 64.8 124.968 ;
    END
  END bank_e[497]
  PIN bank_e[498]
    DIRECTION OUTPUT ;
    USE SIGNAL ;
    PORT
      LAYER M4 ;
        RECT  64.716 125.184 64.8 125.208 ;
    END
  END bank_e[498]
  PIN bank_e[499]
    DIRECTION OUTPUT ;
    USE SIGNAL ;
    PORT
      LAYER M4 ;
        RECT  64.716 125.424 64.8 125.448 ;
    END
  END bank_e[499]
  PIN bank_e[49]
    DIRECTION OUTPUT ;
    USE SIGNAL ;
    PORT
      LAYER M4 ;
        RECT  64.716 12.912 64.8 12.936 ;
    END
  END bank_e[49]
  PIN bank_e[4]
    DIRECTION OUTPUT ;
    USE SIGNAL ;
    PORT
      LAYER M4 ;
        RECT  64.716 1.632 64.8 1.656 ;
    END
  END bank_e[4]
  PIN bank_e[500]
    DIRECTION OUTPUT ;
    USE SIGNAL ;
    PORT
      LAYER M4 ;
        RECT  64.716 125.664 64.8 125.688 ;
    END
  END bank_e[500]
  PIN bank_e[501]
    DIRECTION OUTPUT ;
    USE SIGNAL ;
    PORT
      LAYER M4 ;
        RECT  64.716 125.904 64.8 125.928 ;
    END
  END bank_e[501]
  PIN bank_e[502]
    DIRECTION OUTPUT ;
    USE SIGNAL ;
    PORT
      LAYER M4 ;
        RECT  64.716 126.192 64.8 126.216 ;
    END
  END bank_e[502]
  PIN bank_e[503]
    DIRECTION OUTPUT ;
    USE SIGNAL ;
    PORT
      LAYER M4 ;
        RECT  64.716 126.432 64.8 126.456 ;
    END
  END bank_e[503]
  PIN bank_e[504]
    DIRECTION OUTPUT ;
    USE SIGNAL ;
    PORT
      LAYER M4 ;
        RECT  64.716 126.672 64.8 126.696 ;
    END
  END bank_e[504]
  PIN bank_e[505]
    DIRECTION OUTPUT ;
    USE SIGNAL ;
    PORT
      LAYER M4 ;
        RECT  64.716 126.912 64.8 126.936 ;
    END
  END bank_e[505]
  PIN bank_e[506]
    DIRECTION OUTPUT ;
    USE SIGNAL ;
    PORT
      LAYER M4 ;
        RECT  64.716 127.152 64.8 127.176 ;
    END
  END bank_e[506]
  PIN bank_e[507]
    DIRECTION OUTPUT ;
    USE SIGNAL ;
    PORT
      LAYER M4 ;
        RECT  64.716 127.44 64.8 127.464 ;
    END
  END bank_e[507]
  PIN bank_e[508]
    DIRECTION OUTPUT ;
    USE SIGNAL ;
    PORT
      LAYER M4 ;
        RECT  64.716 127.68 64.8 127.704 ;
    END
  END bank_e[508]
  PIN bank_e[509]
    DIRECTION OUTPUT ;
    USE SIGNAL ;
    PORT
      LAYER M4 ;
        RECT  64.716 127.92 64.8 127.944 ;
    END
  END bank_e[509]
  PIN bank_e[50]
    DIRECTION OUTPUT ;
    USE SIGNAL ;
    PORT
      LAYER M4 ;
        RECT  64.716 13.152 64.8 13.176 ;
    END
  END bank_e[50]
  PIN bank_e[510]
    DIRECTION OUTPUT ;
    USE SIGNAL ;
    PORT
      LAYER M4 ;
        RECT  64.716 128.16 64.8 128.184 ;
    END
  END bank_e[510]
  PIN bank_e[511]
    DIRECTION OUTPUT ;
    USE SIGNAL ;
    PORT
      LAYER M4 ;
        RECT  64.716 128.4 64.8 128.424 ;
    END
  END bank_e[511]
  PIN bank_e[512]
    DIRECTION OUTPUT ;
    USE SIGNAL ;
    PORT
      LAYER M4 ;
        RECT  64.716 128.688 64.8 128.712 ;
    END
  END bank_e[512]
  PIN bank_e[513]
    DIRECTION OUTPUT ;
    USE SIGNAL ;
    PORT
      LAYER M4 ;
        RECT  64.716 128.928 64.8 128.952 ;
    END
  END bank_e[513]
  PIN bank_e[51]
    DIRECTION OUTPUT ;
    USE SIGNAL ;
    PORT
      LAYER M4 ;
        RECT  64.716 13.392 64.8 13.416 ;
    END
  END bank_e[51]
  PIN bank_e[52]
    DIRECTION OUTPUT ;
    USE SIGNAL ;
    PORT
      LAYER M4 ;
        RECT  64.716 13.632 64.8 13.656 ;
    END
  END bank_e[52]
  PIN bank_e[53]
    DIRECTION OUTPUT ;
    USE SIGNAL ;
    PORT
      LAYER M4 ;
        RECT  64.716 13.92 64.8 13.944 ;
    END
  END bank_e[53]
  PIN bank_e[54]
    DIRECTION OUTPUT ;
    USE SIGNAL ;
    PORT
      LAYER M4 ;
        RECT  64.716 14.16 64.8 14.184 ;
    END
  END bank_e[54]
  PIN bank_e[55]
    DIRECTION OUTPUT ;
    USE SIGNAL ;
    PORT
      LAYER M4 ;
        RECT  64.716 14.4 64.8 14.424 ;
    END
  END bank_e[55]
  PIN bank_e[56]
    DIRECTION OUTPUT ;
    USE SIGNAL ;
    PORT
      LAYER M4 ;
        RECT  64.716 14.64 64.8 14.664 ;
    END
  END bank_e[56]
  PIN bank_e[57]
    DIRECTION OUTPUT ;
    USE SIGNAL ;
    PORT
      LAYER M4 ;
        RECT  64.716 14.928 64.8 14.952 ;
    END
  END bank_e[57]
  PIN bank_e[58]
    DIRECTION OUTPUT ;
    USE SIGNAL ;
    PORT
      LAYER M4 ;
        RECT  64.716 15.168 64.8 15.192 ;
    END
  END bank_e[58]
  PIN bank_e[59]
    DIRECTION OUTPUT ;
    USE SIGNAL ;
    PORT
      LAYER M4 ;
        RECT  64.716 15.408 64.8 15.432 ;
    END
  END bank_e[59]
  PIN bank_e[5]
    DIRECTION OUTPUT ;
    USE SIGNAL ;
    PORT
      LAYER M4 ;
        RECT  64.716 1.92 64.8 1.944 ;
    END
  END bank_e[5]
  PIN bank_e[60]
    DIRECTION OUTPUT ;
    USE SIGNAL ;
    PORT
      LAYER M4 ;
        RECT  64.716 15.648 64.8 15.672 ;
    END
  END bank_e[60]
  PIN bank_e[61]
    DIRECTION OUTPUT ;
    USE SIGNAL ;
    PORT
      LAYER M4 ;
        RECT  64.716 15.888 64.8 15.912 ;
    END
  END bank_e[61]
  PIN bank_e[62]
    DIRECTION OUTPUT ;
    USE SIGNAL ;
    PORT
      LAYER M4 ;
        RECT  64.716 16.176 64.8 16.2 ;
    END
  END bank_e[62]
  PIN bank_e[63]
    DIRECTION OUTPUT ;
    USE SIGNAL ;
    PORT
      LAYER M4 ;
        RECT  64.716 16.416 64.8 16.44 ;
    END
  END bank_e[63]
  PIN bank_e[64]
    DIRECTION OUTPUT ;
    USE SIGNAL ;
    PORT
      LAYER M4 ;
        RECT  64.716 16.656 64.8 16.68 ;
    END
  END bank_e[64]
  PIN bank_e[65]
    DIRECTION OUTPUT ;
    USE SIGNAL ;
    PORT
      LAYER M4 ;
        RECT  64.716 16.896 64.8 16.92 ;
    END
  END bank_e[65]
  PIN bank_e[66]
    DIRECTION OUTPUT ;
    USE SIGNAL ;
    PORT
      LAYER M4 ;
        RECT  64.716 17.136 64.8 17.16 ;
    END
  END bank_e[66]
  PIN bank_e[67]
    DIRECTION OUTPUT ;
    USE SIGNAL ;
    PORT
      LAYER M4 ;
        RECT  64.716 17.424 64.8 17.448 ;
    END
  END bank_e[67]
  PIN bank_e[68]
    DIRECTION OUTPUT ;
    USE SIGNAL ;
    PORT
      LAYER M4 ;
        RECT  64.716 17.664 64.8 17.688 ;
    END
  END bank_e[68]
  PIN bank_e[69]
    DIRECTION OUTPUT ;
    USE SIGNAL ;
    PORT
      LAYER M4 ;
        RECT  64.716 17.904 64.8 17.928 ;
    END
  END bank_e[69]
  PIN bank_e[6]
    DIRECTION OUTPUT ;
    USE SIGNAL ;
    PORT
      LAYER M4 ;
        RECT  64.716 2.16 64.8 2.184 ;
    END
  END bank_e[6]
  PIN bank_e[70]
    DIRECTION OUTPUT ;
    USE SIGNAL ;
    PORT
      LAYER M4 ;
        RECT  64.716 18.144 64.8 18.168 ;
    END
  END bank_e[70]
  PIN bank_e[71]
    DIRECTION OUTPUT ;
    USE SIGNAL ;
    PORT
      LAYER M4 ;
        RECT  64.716 18.384 64.8 18.408 ;
    END
  END bank_e[71]
  PIN bank_e[72]
    DIRECTION OUTPUT ;
    USE SIGNAL ;
    PORT
      LAYER M4 ;
        RECT  64.716 18.672 64.8 18.696 ;
    END
  END bank_e[72]
  PIN bank_e[73]
    DIRECTION OUTPUT ;
    USE SIGNAL ;
    PORT
      LAYER M4 ;
        RECT  64.716 18.912 64.8 18.936 ;
    END
  END bank_e[73]
  PIN bank_e[74]
    DIRECTION OUTPUT ;
    USE SIGNAL ;
    PORT
      LAYER M4 ;
        RECT  64.716 19.152 64.8 19.176 ;
    END
  END bank_e[74]
  PIN bank_e[75]
    DIRECTION OUTPUT ;
    USE SIGNAL ;
    PORT
      LAYER M4 ;
        RECT  64.716 19.392 64.8 19.416 ;
    END
  END bank_e[75]
  PIN bank_e[76]
    DIRECTION OUTPUT ;
    USE SIGNAL ;
    PORT
      LAYER M4 ;
        RECT  64.716 19.68 64.8 19.704 ;
    END
  END bank_e[76]
  PIN bank_e[77]
    DIRECTION OUTPUT ;
    USE SIGNAL ;
    PORT
      LAYER M4 ;
        RECT  64.716 19.92 64.8 19.944 ;
    END
  END bank_e[77]
  PIN bank_e[78]
    DIRECTION OUTPUT ;
    USE SIGNAL ;
    PORT
      LAYER M4 ;
        RECT  64.716 20.16 64.8 20.184 ;
    END
  END bank_e[78]
  PIN bank_e[79]
    DIRECTION OUTPUT ;
    USE SIGNAL ;
    PORT
      LAYER M4 ;
        RECT  64.716 20.4 64.8 20.424 ;
    END
  END bank_e[79]
  PIN bank_e[7]
    DIRECTION OUTPUT ;
    USE SIGNAL ;
    PORT
      LAYER M4 ;
        RECT  64.716 2.4 64.8 2.424 ;
    END
  END bank_e[7]
  PIN bank_e[80]
    DIRECTION OUTPUT ;
    USE SIGNAL ;
    PORT
      LAYER M4 ;
        RECT  64.716 20.64 64.8 20.664 ;
    END
  END bank_e[80]
  PIN bank_e[81]
    DIRECTION OUTPUT ;
    USE SIGNAL ;
    PORT
      LAYER M4 ;
        RECT  64.716 20.928 64.8 20.952 ;
    END
  END bank_e[81]
  PIN bank_e[82]
    DIRECTION OUTPUT ;
    USE SIGNAL ;
    PORT
      LAYER M4 ;
        RECT  64.716 21.168 64.8 21.192 ;
    END
  END bank_e[82]
  PIN bank_e[83]
    DIRECTION OUTPUT ;
    USE SIGNAL ;
    PORT
      LAYER M4 ;
        RECT  64.716 21.408 64.8 21.432 ;
    END
  END bank_e[83]
  PIN bank_e[84]
    DIRECTION OUTPUT ;
    USE SIGNAL ;
    PORT
      LAYER M4 ;
        RECT  64.716 21.648 64.8 21.672 ;
    END
  END bank_e[84]
  PIN bank_e[85]
    DIRECTION OUTPUT ;
    USE SIGNAL ;
    PORT
      LAYER M4 ;
        RECT  64.716 21.888 64.8 21.912 ;
    END
  END bank_e[85]
  PIN bank_e[86]
    DIRECTION OUTPUT ;
    USE SIGNAL ;
    PORT
      LAYER M4 ;
        RECT  64.716 22.176 64.8 22.2 ;
    END
  END bank_e[86]
  PIN bank_e[87]
    DIRECTION OUTPUT ;
    USE SIGNAL ;
    PORT
      LAYER M4 ;
        RECT  64.716 22.416 64.8 22.44 ;
    END
  END bank_e[87]
  PIN bank_e[88]
    DIRECTION OUTPUT ;
    USE SIGNAL ;
    PORT
      LAYER M4 ;
        RECT  64.716 22.656 64.8 22.68 ;
    END
  END bank_e[88]
  PIN bank_e[89]
    DIRECTION OUTPUT ;
    USE SIGNAL ;
    PORT
      LAYER M4 ;
        RECT  64.716 22.896 64.8 22.92 ;
    END
  END bank_e[89]
  PIN bank_e[8]
    DIRECTION OUTPUT ;
    USE SIGNAL ;
    PORT
      LAYER M4 ;
        RECT  64.716 2.64 64.8 2.664 ;
    END
  END bank_e[8]
  PIN bank_e[90]
    DIRECTION OUTPUT ;
    USE SIGNAL ;
    PORT
      LAYER M4 ;
        RECT  64.716 23.136 64.8 23.16 ;
    END
  END bank_e[90]
  PIN bank_e[91]
    DIRECTION OUTPUT ;
    USE SIGNAL ;
    PORT
      LAYER M4 ;
        RECT  64.716 23.424 64.8 23.448 ;
    END
  END bank_e[91]
  PIN bank_e[92]
    DIRECTION OUTPUT ;
    USE SIGNAL ;
    PORT
      LAYER M4 ;
        RECT  64.716 23.664 64.8 23.688 ;
    END
  END bank_e[92]
  PIN bank_e[93]
    DIRECTION OUTPUT ;
    USE SIGNAL ;
    PORT
      LAYER M4 ;
        RECT  64.716 23.904 64.8 23.928 ;
    END
  END bank_e[93]
  PIN bank_e[94]
    DIRECTION OUTPUT ;
    USE SIGNAL ;
    PORT
      LAYER M4 ;
        RECT  64.716 24.144 64.8 24.168 ;
    END
  END bank_e[94]
  PIN bank_e[95]
    DIRECTION OUTPUT ;
    USE SIGNAL ;
    PORT
      LAYER M4 ;
        RECT  64.716 24.384 64.8 24.408 ;
    END
  END bank_e[95]
  PIN bank_e[96]
    DIRECTION OUTPUT ;
    USE SIGNAL ;
    PORT
      LAYER M4 ;
        RECT  64.716 24.672 64.8 24.696 ;
    END
  END bank_e[96]
  PIN bank_e[97]
    DIRECTION OUTPUT ;
    USE SIGNAL ;
    PORT
      LAYER M4 ;
        RECT  64.716 24.912 64.8 24.936 ;
    END
  END bank_e[97]
  PIN bank_e[98]
    DIRECTION OUTPUT ;
    USE SIGNAL ;
    PORT
      LAYER M4 ;
        RECT  64.716 25.152 64.8 25.176 ;
    END
  END bank_e[98]
  PIN bank_e[99]
    DIRECTION OUTPUT ;
    USE SIGNAL ;
    PORT
      LAYER M4 ;
        RECT  64.716 25.392 64.8 25.416 ;
    END
  END bank_e[99]
  PIN bank_e[9]
    DIRECTION OUTPUT ;
    USE SIGNAL ;
    PORT
      LAYER M4 ;
        RECT  64.716 2.88 64.8 2.904 ;
    END
  END bank_e[9]
  PIN bank_w[0]
    DIRECTION OUTPUT ;
    USE SIGNAL ;
    PORT
      LAYER M4 ;
        RECT  0 0.672 0.084 0.696 ;
    END
  END bank_w[0]
  PIN bank_w[100]
    DIRECTION OUTPUT ;
    USE SIGNAL ;
    PORT
      LAYER M4 ;
        RECT  0 25.68 0.084 25.704 ;
    END
  END bank_w[100]
  PIN bank_w[101]
    DIRECTION OUTPUT ;
    USE SIGNAL ;
    PORT
      LAYER M4 ;
        RECT  0 25.92 0.084 25.944 ;
    END
  END bank_w[101]
  PIN bank_w[102]
    DIRECTION OUTPUT ;
    USE SIGNAL ;
    PORT
      LAYER M4 ;
        RECT  0 26.16 0.084 26.184 ;
    END
  END bank_w[102]
  PIN bank_w[103]
    DIRECTION OUTPUT ;
    USE SIGNAL ;
    PORT
      LAYER M4 ;
        RECT  0 26.4 0.084 26.424 ;
    END
  END bank_w[103]
  PIN bank_w[104]
    DIRECTION OUTPUT ;
    USE SIGNAL ;
    PORT
      LAYER M4 ;
        RECT  0 26.64 0.084 26.664 ;
    END
  END bank_w[104]
  PIN bank_w[105]
    DIRECTION OUTPUT ;
    USE SIGNAL ;
    PORT
      LAYER M4 ;
        RECT  0 26.928 0.084 26.952 ;
    END
  END bank_w[105]
  PIN bank_w[106]
    DIRECTION OUTPUT ;
    USE SIGNAL ;
    PORT
      LAYER M4 ;
        RECT  0 27.168 0.084 27.192 ;
    END
  END bank_w[106]
  PIN bank_w[107]
    DIRECTION OUTPUT ;
    USE SIGNAL ;
    PORT
      LAYER M4 ;
        RECT  0 27.408 0.084 27.432 ;
    END
  END bank_w[107]
  PIN bank_w[108]
    DIRECTION OUTPUT ;
    USE SIGNAL ;
    PORT
      LAYER M4 ;
        RECT  0 27.648 0.084 27.672 ;
    END
  END bank_w[108]
  PIN bank_w[109]
    DIRECTION OUTPUT ;
    USE SIGNAL ;
    PORT
      LAYER M4 ;
        RECT  0 27.888 0.084 27.912 ;
    END
  END bank_w[109]
  PIN bank_w[10]
    DIRECTION OUTPUT ;
    USE SIGNAL ;
    PORT
      LAYER M4 ;
        RECT  0 3.168 0.084 3.192 ;
    END
  END bank_w[10]
  PIN bank_w[110]
    DIRECTION OUTPUT ;
    USE SIGNAL ;
    PORT
      LAYER M4 ;
        RECT  0 28.176 0.084 28.2 ;
    END
  END bank_w[110]
  PIN bank_w[111]
    DIRECTION OUTPUT ;
    USE SIGNAL ;
    PORT
      LAYER M4 ;
        RECT  0 28.416 0.084 28.44 ;
    END
  END bank_w[111]
  PIN bank_w[112]
    DIRECTION OUTPUT ;
    USE SIGNAL ;
    PORT
      LAYER M4 ;
        RECT  0 28.656 0.084 28.68 ;
    END
  END bank_w[112]
  PIN bank_w[113]
    DIRECTION OUTPUT ;
    USE SIGNAL ;
    PORT
      LAYER M4 ;
        RECT  0 28.896 0.084 28.92 ;
    END
  END bank_w[113]
  PIN bank_w[114]
    DIRECTION OUTPUT ;
    USE SIGNAL ;
    PORT
      LAYER M4 ;
        RECT  0 29.136 0.084 29.16 ;
    END
  END bank_w[114]
  PIN bank_w[115]
    DIRECTION OUTPUT ;
    USE SIGNAL ;
    PORT
      LAYER M4 ;
        RECT  0 29.424 0.084 29.448 ;
    END
  END bank_w[115]
  PIN bank_w[116]
    DIRECTION OUTPUT ;
    USE SIGNAL ;
    PORT
      LAYER M4 ;
        RECT  0 29.664 0.084 29.688 ;
    END
  END bank_w[116]
  PIN bank_w[117]
    DIRECTION OUTPUT ;
    USE SIGNAL ;
    PORT
      LAYER M4 ;
        RECT  0 29.904 0.084 29.928 ;
    END
  END bank_w[117]
  PIN bank_w[118]
    DIRECTION OUTPUT ;
    USE SIGNAL ;
    PORT
      LAYER M4 ;
        RECT  0 30.144 0.084 30.168 ;
    END
  END bank_w[118]
  PIN bank_w[119]
    DIRECTION OUTPUT ;
    USE SIGNAL ;
    PORT
      LAYER M4 ;
        RECT  0 30.432 0.084 30.456 ;
    END
  END bank_w[119]
  PIN bank_w[11]
    DIRECTION OUTPUT ;
    USE SIGNAL ;
    PORT
      LAYER M4 ;
        RECT  0 3.408 0.084 3.432 ;
    END
  END bank_w[11]
  PIN bank_w[120]
    DIRECTION OUTPUT ;
    USE SIGNAL ;
    PORT
      LAYER M4 ;
        RECT  0 30.672 0.084 30.696 ;
    END
  END bank_w[120]
  PIN bank_w[121]
    DIRECTION OUTPUT ;
    USE SIGNAL ;
    PORT
      LAYER M4 ;
        RECT  0 30.912 0.084 30.936 ;
    END
  END bank_w[121]
  PIN bank_w[122]
    DIRECTION OUTPUT ;
    USE SIGNAL ;
    PORT
      LAYER M4 ;
        RECT  0 31.152 0.084 31.176 ;
    END
  END bank_w[122]
  PIN bank_w[123]
    DIRECTION OUTPUT ;
    USE SIGNAL ;
    PORT
      LAYER M4 ;
        RECT  0 31.392 0.084 31.416 ;
    END
  END bank_w[123]
  PIN bank_w[124]
    DIRECTION OUTPUT ;
    USE SIGNAL ;
    PORT
      LAYER M4 ;
        RECT  0 31.68 0.084 31.704 ;
    END
  END bank_w[124]
  PIN bank_w[125]
    DIRECTION OUTPUT ;
    USE SIGNAL ;
    PORT
      LAYER M4 ;
        RECT  0 31.92 0.084 31.944 ;
    END
  END bank_w[125]
  PIN bank_w[126]
    DIRECTION OUTPUT ;
    USE SIGNAL ;
    PORT
      LAYER M4 ;
        RECT  0 32.16 0.084 32.184 ;
    END
  END bank_w[126]
  PIN bank_w[127]
    DIRECTION OUTPUT ;
    USE SIGNAL ;
    PORT
      LAYER M4 ;
        RECT  0 32.4 0.084 32.424 ;
    END
  END bank_w[127]
  PIN bank_w[128]
    DIRECTION OUTPUT ;
    USE SIGNAL ;
    PORT
      LAYER M4 ;
        RECT  0 32.64 0.084 32.664 ;
    END
  END bank_w[128]
  PIN bank_w[129]
    DIRECTION OUTPUT ;
    USE SIGNAL ;
    PORT
      LAYER M4 ;
        RECT  0 32.928 0.084 32.952 ;
    END
  END bank_w[129]
  PIN bank_w[12]
    DIRECTION OUTPUT ;
    USE SIGNAL ;
    PORT
      LAYER M4 ;
        RECT  0 3.648 0.084 3.672 ;
    END
  END bank_w[12]
  PIN bank_w[130]
    DIRECTION OUTPUT ;
    USE SIGNAL ;
    PORT
      LAYER M4 ;
        RECT  0 33.168 0.084 33.192 ;
    END
  END bank_w[130]
  PIN bank_w[131]
    DIRECTION OUTPUT ;
    USE SIGNAL ;
    PORT
      LAYER M4 ;
        RECT  0 33.408 0.084 33.432 ;
    END
  END bank_w[131]
  PIN bank_w[132]
    DIRECTION OUTPUT ;
    USE SIGNAL ;
    PORT
      LAYER M4 ;
        RECT  0 33.648 0.084 33.672 ;
    END
  END bank_w[132]
  PIN bank_w[133]
    DIRECTION OUTPUT ;
    USE SIGNAL ;
    PORT
      LAYER M4 ;
        RECT  0 33.888 0.084 33.912 ;
    END
  END bank_w[133]
  PIN bank_w[134]
    DIRECTION OUTPUT ;
    USE SIGNAL ;
    PORT
      LAYER M4 ;
        RECT  0 34.176 0.084 34.2 ;
    END
  END bank_w[134]
  PIN bank_w[135]
    DIRECTION OUTPUT ;
    USE SIGNAL ;
    PORT
      LAYER M4 ;
        RECT  0 34.416 0.084 34.44 ;
    END
  END bank_w[135]
  PIN bank_w[136]
    DIRECTION OUTPUT ;
    USE SIGNAL ;
    PORT
      LAYER M4 ;
        RECT  0 34.656 0.084 34.68 ;
    END
  END bank_w[136]
  PIN bank_w[137]
    DIRECTION OUTPUT ;
    USE SIGNAL ;
    PORT
      LAYER M4 ;
        RECT  0 34.896 0.084 34.92 ;
    END
  END bank_w[137]
  PIN bank_w[138]
    DIRECTION OUTPUT ;
    USE SIGNAL ;
    PORT
      LAYER M4 ;
        RECT  0 35.136 0.084 35.16 ;
    END
  END bank_w[138]
  PIN bank_w[139]
    DIRECTION OUTPUT ;
    USE SIGNAL ;
    PORT
      LAYER M4 ;
        RECT  0 35.424 0.084 35.448 ;
    END
  END bank_w[139]
  PIN bank_w[13]
    DIRECTION OUTPUT ;
    USE SIGNAL ;
    PORT
      LAYER M4 ;
        RECT  0 3.888 0.084 3.912 ;
    END
  END bank_w[13]
  PIN bank_w[140]
    DIRECTION OUTPUT ;
    USE SIGNAL ;
    PORT
      LAYER M4 ;
        RECT  0 35.664 0.084 35.688 ;
    END
  END bank_w[140]
  PIN bank_w[141]
    DIRECTION OUTPUT ;
    USE SIGNAL ;
    PORT
      LAYER M4 ;
        RECT  0 35.904 0.084 35.928 ;
    END
  END bank_w[141]
  PIN bank_w[142]
    DIRECTION OUTPUT ;
    USE SIGNAL ;
    PORT
      LAYER M4 ;
        RECT  0 36.144 0.084 36.168 ;
    END
  END bank_w[142]
  PIN bank_w[143]
    DIRECTION OUTPUT ;
    USE SIGNAL ;
    PORT
      LAYER M4 ;
        RECT  0 36.432 0.084 36.456 ;
    END
  END bank_w[143]
  PIN bank_w[144]
    DIRECTION OUTPUT ;
    USE SIGNAL ;
    PORT
      LAYER M4 ;
        RECT  0 36.672 0.084 36.696 ;
    END
  END bank_w[144]
  PIN bank_w[145]
    DIRECTION OUTPUT ;
    USE SIGNAL ;
    PORT
      LAYER M4 ;
        RECT  0 36.912 0.084 36.936 ;
    END
  END bank_w[145]
  PIN bank_w[146]
    DIRECTION OUTPUT ;
    USE SIGNAL ;
    PORT
      LAYER M4 ;
        RECT  0 37.152 0.084 37.176 ;
    END
  END bank_w[146]
  PIN bank_w[147]
    DIRECTION OUTPUT ;
    USE SIGNAL ;
    PORT
      LAYER M4 ;
        RECT  0 37.392 0.084 37.416 ;
    END
  END bank_w[147]
  PIN bank_w[148]
    DIRECTION OUTPUT ;
    USE SIGNAL ;
    PORT
      LAYER M4 ;
        RECT  0 37.68 0.084 37.704 ;
    END
  END bank_w[148]
  PIN bank_w[149]
    DIRECTION OUTPUT ;
    USE SIGNAL ;
    PORT
      LAYER M4 ;
        RECT  0 37.92 0.084 37.944 ;
    END
  END bank_w[149]
  PIN bank_w[14]
    DIRECTION OUTPUT ;
    USE SIGNAL ;
    PORT
      LAYER M4 ;
        RECT  0 4.176 0.084 4.2 ;
    END
  END bank_w[14]
  PIN bank_w[150]
    DIRECTION OUTPUT ;
    USE SIGNAL ;
    PORT
      LAYER M4 ;
        RECT  0 38.16 0.084 38.184 ;
    END
  END bank_w[150]
  PIN bank_w[151]
    DIRECTION OUTPUT ;
    USE SIGNAL ;
    PORT
      LAYER M4 ;
        RECT  0 38.4 0.084 38.424 ;
    END
  END bank_w[151]
  PIN bank_w[152]
    DIRECTION OUTPUT ;
    USE SIGNAL ;
    PORT
      LAYER M4 ;
        RECT  0 38.64 0.084 38.664 ;
    END
  END bank_w[152]
  PIN bank_w[153]
    DIRECTION OUTPUT ;
    USE SIGNAL ;
    PORT
      LAYER M4 ;
        RECT  0 38.928 0.084 38.952 ;
    END
  END bank_w[153]
  PIN bank_w[154]
    DIRECTION OUTPUT ;
    USE SIGNAL ;
    PORT
      LAYER M4 ;
        RECT  0 39.168 0.084 39.192 ;
    END
  END bank_w[154]
  PIN bank_w[155]
    DIRECTION OUTPUT ;
    USE SIGNAL ;
    PORT
      LAYER M4 ;
        RECT  0 39.408 0.084 39.432 ;
    END
  END bank_w[155]
  PIN bank_w[156]
    DIRECTION OUTPUT ;
    USE SIGNAL ;
    PORT
      LAYER M4 ;
        RECT  0 39.648 0.084 39.672 ;
    END
  END bank_w[156]
  PIN bank_w[157]
    DIRECTION OUTPUT ;
    USE SIGNAL ;
    PORT
      LAYER M4 ;
        RECT  0 39.888 0.084 39.912 ;
    END
  END bank_w[157]
  PIN bank_w[158]
    DIRECTION OUTPUT ;
    USE SIGNAL ;
    PORT
      LAYER M4 ;
        RECT  0 40.176 0.084 40.2 ;
    END
  END bank_w[158]
  PIN bank_w[159]
    DIRECTION OUTPUT ;
    USE SIGNAL ;
    PORT
      LAYER M4 ;
        RECT  0 40.416 0.084 40.44 ;
    END
  END bank_w[159]
  PIN bank_w[15]
    DIRECTION OUTPUT ;
    USE SIGNAL ;
    PORT
      LAYER M4 ;
        RECT  0 4.416 0.084 4.44 ;
    END
  END bank_w[15]
  PIN bank_w[160]
    DIRECTION OUTPUT ;
    USE SIGNAL ;
    PORT
      LAYER M4 ;
        RECT  0 40.656 0.084 40.68 ;
    END
  END bank_w[160]
  PIN bank_w[161]
    DIRECTION OUTPUT ;
    USE SIGNAL ;
    PORT
      LAYER M4 ;
        RECT  0 40.896 0.084 40.92 ;
    END
  END bank_w[161]
  PIN bank_w[162]
    DIRECTION OUTPUT ;
    USE SIGNAL ;
    PORT
      LAYER M4 ;
        RECT  0 41.136 0.084 41.16 ;
    END
  END bank_w[162]
  PIN bank_w[163]
    DIRECTION OUTPUT ;
    USE SIGNAL ;
    PORT
      LAYER M4 ;
        RECT  0 41.424 0.084 41.448 ;
    END
  END bank_w[163]
  PIN bank_w[164]
    DIRECTION OUTPUT ;
    USE SIGNAL ;
    PORT
      LAYER M4 ;
        RECT  0 41.664 0.084 41.688 ;
    END
  END bank_w[164]
  PIN bank_w[165]
    DIRECTION OUTPUT ;
    USE SIGNAL ;
    PORT
      LAYER M4 ;
        RECT  0 41.904 0.084 41.928 ;
    END
  END bank_w[165]
  PIN bank_w[166]
    DIRECTION OUTPUT ;
    USE SIGNAL ;
    PORT
      LAYER M4 ;
        RECT  0 42.144 0.084 42.168 ;
    END
  END bank_w[166]
  PIN bank_w[167]
    DIRECTION OUTPUT ;
    USE SIGNAL ;
    PORT
      LAYER M4 ;
        RECT  0 42.432 0.084 42.456 ;
    END
  END bank_w[167]
  PIN bank_w[168]
    DIRECTION OUTPUT ;
    USE SIGNAL ;
    PORT
      LAYER M4 ;
        RECT  0 42.672 0.084 42.696 ;
    END
  END bank_w[168]
  PIN bank_w[169]
    DIRECTION OUTPUT ;
    USE SIGNAL ;
    PORT
      LAYER M4 ;
        RECT  0 42.912 0.084 42.936 ;
    END
  END bank_w[169]
  PIN bank_w[16]
    DIRECTION OUTPUT ;
    USE SIGNAL ;
    PORT
      LAYER M4 ;
        RECT  0 4.656 0.084 4.68 ;
    END
  END bank_w[16]
  PIN bank_w[170]
    DIRECTION OUTPUT ;
    USE SIGNAL ;
    PORT
      LAYER M4 ;
        RECT  0 43.152 0.084 43.176 ;
    END
  END bank_w[170]
  PIN bank_w[171]
    DIRECTION OUTPUT ;
    USE SIGNAL ;
    PORT
      LAYER M4 ;
        RECT  0 43.392 0.084 43.416 ;
    END
  END bank_w[171]
  PIN bank_w[172]
    DIRECTION OUTPUT ;
    USE SIGNAL ;
    PORT
      LAYER M4 ;
        RECT  0 43.68 0.084 43.704 ;
    END
  END bank_w[172]
  PIN bank_w[173]
    DIRECTION OUTPUT ;
    USE SIGNAL ;
    PORT
      LAYER M4 ;
        RECT  0 43.92 0.084 43.944 ;
    END
  END bank_w[173]
  PIN bank_w[174]
    DIRECTION OUTPUT ;
    USE SIGNAL ;
    PORT
      LAYER M4 ;
        RECT  0 44.16 0.084 44.184 ;
    END
  END bank_w[174]
  PIN bank_w[175]
    DIRECTION OUTPUT ;
    USE SIGNAL ;
    PORT
      LAYER M4 ;
        RECT  0 44.4 0.084 44.424 ;
    END
  END bank_w[175]
  PIN bank_w[176]
    DIRECTION OUTPUT ;
    USE SIGNAL ;
    PORT
      LAYER M4 ;
        RECT  0 44.64 0.084 44.664 ;
    END
  END bank_w[176]
  PIN bank_w[177]
    DIRECTION OUTPUT ;
    USE SIGNAL ;
    PORT
      LAYER M4 ;
        RECT  0 44.928 0.084 44.952 ;
    END
  END bank_w[177]
  PIN bank_w[178]
    DIRECTION OUTPUT ;
    USE SIGNAL ;
    PORT
      LAYER M4 ;
        RECT  0 45.168 0.084 45.192 ;
    END
  END bank_w[178]
  PIN bank_w[179]
    DIRECTION OUTPUT ;
    USE SIGNAL ;
    PORT
      LAYER M4 ;
        RECT  0 45.408 0.084 45.432 ;
    END
  END bank_w[179]
  PIN bank_w[17]
    DIRECTION OUTPUT ;
    USE SIGNAL ;
    PORT
      LAYER M4 ;
        RECT  0 4.896 0.084 4.92 ;
    END
  END bank_w[17]
  PIN bank_w[180]
    DIRECTION OUTPUT ;
    USE SIGNAL ;
    PORT
      LAYER M4 ;
        RECT  0 45.648 0.084 45.672 ;
    END
  END bank_w[180]
  PIN bank_w[181]
    DIRECTION OUTPUT ;
    USE SIGNAL ;
    PORT
      LAYER M4 ;
        RECT  0 45.888 0.084 45.912 ;
    END
  END bank_w[181]
  PIN bank_w[182]
    DIRECTION OUTPUT ;
    USE SIGNAL ;
    PORT
      LAYER M4 ;
        RECT  0 46.176 0.084 46.2 ;
    END
  END bank_w[182]
  PIN bank_w[183]
    DIRECTION OUTPUT ;
    USE SIGNAL ;
    PORT
      LAYER M4 ;
        RECT  0 46.416 0.084 46.44 ;
    END
  END bank_w[183]
  PIN bank_w[184]
    DIRECTION OUTPUT ;
    USE SIGNAL ;
    PORT
      LAYER M4 ;
        RECT  0 46.656 0.084 46.68 ;
    END
  END bank_w[184]
  PIN bank_w[185]
    DIRECTION OUTPUT ;
    USE SIGNAL ;
    PORT
      LAYER M4 ;
        RECT  0 46.896 0.084 46.92 ;
    END
  END bank_w[185]
  PIN bank_w[186]
    DIRECTION OUTPUT ;
    USE SIGNAL ;
    PORT
      LAYER M4 ;
        RECT  0 47.184 0.084 47.208 ;
    END
  END bank_w[186]
  PIN bank_w[187]
    DIRECTION OUTPUT ;
    USE SIGNAL ;
    PORT
      LAYER M4 ;
        RECT  0 47.424 0.084 47.448 ;
    END
  END bank_w[187]
  PIN bank_w[188]
    DIRECTION OUTPUT ;
    USE SIGNAL ;
    PORT
      LAYER M4 ;
        RECT  0 47.664 0.084 47.688 ;
    END
  END bank_w[188]
  PIN bank_w[189]
    DIRECTION OUTPUT ;
    USE SIGNAL ;
    PORT
      LAYER M4 ;
        RECT  0 47.904 0.084 47.928 ;
    END
  END bank_w[189]
  PIN bank_w[18]
    DIRECTION OUTPUT ;
    USE SIGNAL ;
    PORT
      LAYER M4 ;
        RECT  0 5.136 0.084 5.16 ;
    END
  END bank_w[18]
  PIN bank_w[190]
    DIRECTION OUTPUT ;
    USE SIGNAL ;
    PORT
      LAYER M4 ;
        RECT  0 48.144 0.084 48.168 ;
    END
  END bank_w[190]
  PIN bank_w[191]
    DIRECTION OUTPUT ;
    USE SIGNAL ;
    PORT
      LAYER M4 ;
        RECT  0 48.432 0.084 48.456 ;
    END
  END bank_w[191]
  PIN bank_w[192]
    DIRECTION OUTPUT ;
    USE SIGNAL ;
    PORT
      LAYER M4 ;
        RECT  0 48.672 0.084 48.696 ;
    END
  END bank_w[192]
  PIN bank_w[193]
    DIRECTION OUTPUT ;
    USE SIGNAL ;
    PORT
      LAYER M4 ;
        RECT  0 48.912 0.084 48.936 ;
    END
  END bank_w[193]
  PIN bank_w[194]
    DIRECTION OUTPUT ;
    USE SIGNAL ;
    PORT
      LAYER M4 ;
        RECT  0 49.152 0.084 49.176 ;
    END
  END bank_w[194]
  PIN bank_w[195]
    DIRECTION OUTPUT ;
    USE SIGNAL ;
    PORT
      LAYER M4 ;
        RECT  0 49.392 0.084 49.416 ;
    END
  END bank_w[195]
  PIN bank_w[196]
    DIRECTION OUTPUT ;
    USE SIGNAL ;
    PORT
      LAYER M4 ;
        RECT  0 49.68 0.084 49.704 ;
    END
  END bank_w[196]
  PIN bank_w[197]
    DIRECTION OUTPUT ;
    USE SIGNAL ;
    PORT
      LAYER M4 ;
        RECT  0 49.92 0.084 49.944 ;
    END
  END bank_w[197]
  PIN bank_w[198]
    DIRECTION OUTPUT ;
    USE SIGNAL ;
    PORT
      LAYER M4 ;
        RECT  0 50.16 0.084 50.184 ;
    END
  END bank_w[198]
  PIN bank_w[199]
    DIRECTION OUTPUT ;
    USE SIGNAL ;
    PORT
      LAYER M4 ;
        RECT  0 50.4 0.084 50.424 ;
    END
  END bank_w[199]
  PIN bank_w[19]
    DIRECTION OUTPUT ;
    USE SIGNAL ;
    PORT
      LAYER M4 ;
        RECT  0 5.424 0.084 5.448 ;
    END
  END bank_w[19]
  PIN bank_w[1]
    DIRECTION OUTPUT ;
    USE SIGNAL ;
    PORT
      LAYER M4 ;
        RECT  0 0.912 0.084 0.936 ;
    END
  END bank_w[1]
  PIN bank_w[200]
    DIRECTION OUTPUT ;
    USE SIGNAL ;
    PORT
      LAYER M4 ;
        RECT  0 50.64 0.084 50.664 ;
    END
  END bank_w[200]
  PIN bank_w[201]
    DIRECTION OUTPUT ;
    USE SIGNAL ;
    PORT
      LAYER M4 ;
        RECT  0 50.928 0.084 50.952 ;
    END
  END bank_w[201]
  PIN bank_w[202]
    DIRECTION OUTPUT ;
    USE SIGNAL ;
    PORT
      LAYER M4 ;
        RECT  0 51.168 0.084 51.192 ;
    END
  END bank_w[202]
  PIN bank_w[203]
    DIRECTION OUTPUT ;
    USE SIGNAL ;
    PORT
      LAYER M4 ;
        RECT  0 51.408 0.084 51.432 ;
    END
  END bank_w[203]
  PIN bank_w[204]
    DIRECTION OUTPUT ;
    USE SIGNAL ;
    PORT
      LAYER M4 ;
        RECT  0 51.648 0.084 51.672 ;
    END
  END bank_w[204]
  PIN bank_w[205]
    DIRECTION OUTPUT ;
    USE SIGNAL ;
    PORT
      LAYER M4 ;
        RECT  0 51.888 0.084 51.912 ;
    END
  END bank_w[205]
  PIN bank_w[206]
    DIRECTION OUTPUT ;
    USE SIGNAL ;
    PORT
      LAYER M4 ;
        RECT  0 52.176 0.084 52.2 ;
    END
  END bank_w[206]
  PIN bank_w[207]
    DIRECTION OUTPUT ;
    USE SIGNAL ;
    PORT
      LAYER M4 ;
        RECT  0 52.416 0.084 52.44 ;
    END
  END bank_w[207]
  PIN bank_w[208]
    DIRECTION OUTPUT ;
    USE SIGNAL ;
    PORT
      LAYER M4 ;
        RECT  0 52.656 0.084 52.68 ;
    END
  END bank_w[208]
  PIN bank_w[209]
    DIRECTION OUTPUT ;
    USE SIGNAL ;
    PORT
      LAYER M4 ;
        RECT  0 52.896 0.084 52.92 ;
    END
  END bank_w[209]
  PIN bank_w[20]
    DIRECTION OUTPUT ;
    USE SIGNAL ;
    PORT
      LAYER M4 ;
        RECT  0 5.664 0.084 5.688 ;
    END
  END bank_w[20]
  PIN bank_w[210]
    DIRECTION OUTPUT ;
    USE SIGNAL ;
    PORT
      LAYER M4 ;
        RECT  0 53.184 0.084 53.208 ;
    END
  END bank_w[210]
  PIN bank_w[211]
    DIRECTION OUTPUT ;
    USE SIGNAL ;
    PORT
      LAYER M4 ;
        RECT  0 53.424 0.084 53.448 ;
    END
  END bank_w[211]
  PIN bank_w[212]
    DIRECTION OUTPUT ;
    USE SIGNAL ;
    PORT
      LAYER M4 ;
        RECT  0 53.664 0.084 53.688 ;
    END
  END bank_w[212]
  PIN bank_w[213]
    DIRECTION OUTPUT ;
    USE SIGNAL ;
    PORT
      LAYER M4 ;
        RECT  0 53.904 0.084 53.928 ;
    END
  END bank_w[213]
  PIN bank_w[214]
    DIRECTION OUTPUT ;
    USE SIGNAL ;
    PORT
      LAYER M4 ;
        RECT  0 54.144 0.084 54.168 ;
    END
  END bank_w[214]
  PIN bank_w[215]
    DIRECTION OUTPUT ;
    USE SIGNAL ;
    PORT
      LAYER M4 ;
        RECT  0 54.432 0.084 54.456 ;
    END
  END bank_w[215]
  PIN bank_w[216]
    DIRECTION OUTPUT ;
    USE SIGNAL ;
    PORT
      LAYER M4 ;
        RECT  0 54.672 0.084 54.696 ;
    END
  END bank_w[216]
  PIN bank_w[217]
    DIRECTION OUTPUT ;
    USE SIGNAL ;
    PORT
      LAYER M4 ;
        RECT  0 54.912 0.084 54.936 ;
    END
  END bank_w[217]
  PIN bank_w[218]
    DIRECTION OUTPUT ;
    USE SIGNAL ;
    PORT
      LAYER M4 ;
        RECT  0 55.152 0.084 55.176 ;
    END
  END bank_w[218]
  PIN bank_w[219]
    DIRECTION OUTPUT ;
    USE SIGNAL ;
    PORT
      LAYER M4 ;
        RECT  0 55.392 0.084 55.416 ;
    END
  END bank_w[219]
  PIN bank_w[21]
    DIRECTION OUTPUT ;
    USE SIGNAL ;
    PORT
      LAYER M4 ;
        RECT  0 5.904 0.084 5.928 ;
    END
  END bank_w[21]
  PIN bank_w[220]
    DIRECTION OUTPUT ;
    USE SIGNAL ;
    PORT
      LAYER M4 ;
        RECT  0 55.68 0.084 55.704 ;
    END
  END bank_w[220]
  PIN bank_w[221]
    DIRECTION OUTPUT ;
    USE SIGNAL ;
    PORT
      LAYER M4 ;
        RECT  0 55.92 0.084 55.944 ;
    END
  END bank_w[221]
  PIN bank_w[222]
    DIRECTION OUTPUT ;
    USE SIGNAL ;
    PORT
      LAYER M4 ;
        RECT  0 56.16 0.084 56.184 ;
    END
  END bank_w[222]
  PIN bank_w[223]
    DIRECTION OUTPUT ;
    USE SIGNAL ;
    PORT
      LAYER M4 ;
        RECT  0 56.4 0.084 56.424 ;
    END
  END bank_w[223]
  PIN bank_w[224]
    DIRECTION OUTPUT ;
    USE SIGNAL ;
    PORT
      LAYER M4 ;
        RECT  0 56.64 0.084 56.664 ;
    END
  END bank_w[224]
  PIN bank_w[225]
    DIRECTION OUTPUT ;
    USE SIGNAL ;
    PORT
      LAYER M4 ;
        RECT  0 56.928 0.084 56.952 ;
    END
  END bank_w[225]
  PIN bank_w[226]
    DIRECTION OUTPUT ;
    USE SIGNAL ;
    PORT
      LAYER M4 ;
        RECT  0 57.168 0.084 57.192 ;
    END
  END bank_w[226]
  PIN bank_w[227]
    DIRECTION OUTPUT ;
    USE SIGNAL ;
    PORT
      LAYER M4 ;
        RECT  0 57.408 0.084 57.432 ;
    END
  END bank_w[227]
  PIN bank_w[228]
    DIRECTION OUTPUT ;
    USE SIGNAL ;
    PORT
      LAYER M4 ;
        RECT  0 57.648 0.084 57.672 ;
    END
  END bank_w[228]
  PIN bank_w[229]
    DIRECTION OUTPUT ;
    USE SIGNAL ;
    PORT
      LAYER M4 ;
        RECT  0 57.936 0.084 57.96 ;
    END
  END bank_w[229]
  PIN bank_w[22]
    DIRECTION OUTPUT ;
    USE SIGNAL ;
    PORT
      LAYER M4 ;
        RECT  0 6.144 0.084 6.168 ;
    END
  END bank_w[22]
  PIN bank_w[230]
    DIRECTION OUTPUT ;
    USE SIGNAL ;
    PORT
      LAYER M4 ;
        RECT  0 58.176 0.084 58.2 ;
    END
  END bank_w[230]
  PIN bank_w[231]
    DIRECTION OUTPUT ;
    USE SIGNAL ;
    PORT
      LAYER M4 ;
        RECT  0 58.416 0.084 58.44 ;
    END
  END bank_w[231]
  PIN bank_w[232]
    DIRECTION OUTPUT ;
    USE SIGNAL ;
    PORT
      LAYER M4 ;
        RECT  0 58.656 0.084 58.68 ;
    END
  END bank_w[232]
  PIN bank_w[233]
    DIRECTION OUTPUT ;
    USE SIGNAL ;
    PORT
      LAYER M4 ;
        RECT  0 58.896 0.084 58.92 ;
    END
  END bank_w[233]
  PIN bank_w[234]
    DIRECTION OUTPUT ;
    USE SIGNAL ;
    PORT
      LAYER M4 ;
        RECT  0 59.184 0.084 59.208 ;
    END
  END bank_w[234]
  PIN bank_w[235]
    DIRECTION OUTPUT ;
    USE SIGNAL ;
    PORT
      LAYER M4 ;
        RECT  0 59.424 0.084 59.448 ;
    END
  END bank_w[235]
  PIN bank_w[236]
    DIRECTION OUTPUT ;
    USE SIGNAL ;
    PORT
      LAYER M4 ;
        RECT  0 59.664 0.084 59.688 ;
    END
  END bank_w[236]
  PIN bank_w[237]
    DIRECTION OUTPUT ;
    USE SIGNAL ;
    PORT
      LAYER M4 ;
        RECT  0 59.904 0.084 59.928 ;
    END
  END bank_w[237]
  PIN bank_w[238]
    DIRECTION OUTPUT ;
    USE SIGNAL ;
    PORT
      LAYER M4 ;
        RECT  0 60.144 0.084 60.168 ;
    END
  END bank_w[238]
  PIN bank_w[239]
    DIRECTION OUTPUT ;
    USE SIGNAL ;
    PORT
      LAYER M4 ;
        RECT  0 60.432 0.084 60.456 ;
    END
  END bank_w[239]
  PIN bank_w[23]
    DIRECTION OUTPUT ;
    USE SIGNAL ;
    PORT
      LAYER M4 ;
        RECT  0 6.384 0.084 6.408 ;
    END
  END bank_w[23]
  PIN bank_w[240]
    DIRECTION OUTPUT ;
    USE SIGNAL ;
    PORT
      LAYER M4 ;
        RECT  0 60.672 0.084 60.696 ;
    END
  END bank_w[240]
  PIN bank_w[241]
    DIRECTION OUTPUT ;
    USE SIGNAL ;
    PORT
      LAYER M4 ;
        RECT  0 60.912 0.084 60.936 ;
    END
  END bank_w[241]
  PIN bank_w[242]
    DIRECTION OUTPUT ;
    USE SIGNAL ;
    PORT
      LAYER M4 ;
        RECT  0 61.152 0.084 61.176 ;
    END
  END bank_w[242]
  PIN bank_w[243]
    DIRECTION OUTPUT ;
    USE SIGNAL ;
    PORT
      LAYER M4 ;
        RECT  0 61.392 0.084 61.416 ;
    END
  END bank_w[243]
  PIN bank_w[244]
    DIRECTION OUTPUT ;
    USE SIGNAL ;
    PORT
      LAYER M4 ;
        RECT  0 61.68 0.084 61.704 ;
    END
  END bank_w[244]
  PIN bank_w[245]
    DIRECTION OUTPUT ;
    USE SIGNAL ;
    PORT
      LAYER M4 ;
        RECT  0 61.92 0.084 61.944 ;
    END
  END bank_w[245]
  PIN bank_w[246]
    DIRECTION OUTPUT ;
    USE SIGNAL ;
    PORT
      LAYER M4 ;
        RECT  0 62.16 0.084 62.184 ;
    END
  END bank_w[246]
  PIN bank_w[247]
    DIRECTION OUTPUT ;
    USE SIGNAL ;
    PORT
      LAYER M4 ;
        RECT  0 62.4 0.084 62.424 ;
    END
  END bank_w[247]
  PIN bank_w[248]
    DIRECTION OUTPUT ;
    USE SIGNAL ;
    PORT
      LAYER M4 ;
        RECT  0 62.64 0.084 62.664 ;
    END
  END bank_w[248]
  PIN bank_w[249]
    DIRECTION OUTPUT ;
    USE SIGNAL ;
    PORT
      LAYER M4 ;
        RECT  0 62.928 0.084 62.952 ;
    END
  END bank_w[249]
  PIN bank_w[24]
    DIRECTION OUTPUT ;
    USE SIGNAL ;
    PORT
      LAYER M4 ;
        RECT  0 6.672 0.084 6.696 ;
    END
  END bank_w[24]
  PIN bank_w[250]
    DIRECTION OUTPUT ;
    USE SIGNAL ;
    PORT
      LAYER M4 ;
        RECT  0 63.168 0.084 63.192 ;
    END
  END bank_w[250]
  PIN bank_w[251]
    DIRECTION OUTPUT ;
    USE SIGNAL ;
    PORT
      LAYER M4 ;
        RECT  0 63.408 0.084 63.432 ;
    END
  END bank_w[251]
  PIN bank_w[252]
    DIRECTION OUTPUT ;
    USE SIGNAL ;
    PORT
      LAYER M4 ;
        RECT  0 63.648 0.084 63.672 ;
    END
  END bank_w[252]
  PIN bank_w[253]
    DIRECTION OUTPUT ;
    USE SIGNAL ;
    PORT
      LAYER M4 ;
        RECT  0 63.936 0.084 63.96 ;
    END
  END bank_w[253]
  PIN bank_w[254]
    DIRECTION OUTPUT ;
    USE SIGNAL ;
    PORT
      LAYER M4 ;
        RECT  0 64.176 0.084 64.2 ;
    END
  END bank_w[254]
  PIN bank_w[255]
    DIRECTION OUTPUT ;
    USE SIGNAL ;
    PORT
      LAYER M4 ;
        RECT  0 64.416 0.084 64.44 ;
    END
  END bank_w[255]
  PIN bank_w[256]
    DIRECTION OUTPUT ;
    USE SIGNAL ;
    PORT
      LAYER M4 ;
        RECT  0 64.656 0.084 64.68 ;
    END
  END bank_w[256]
  PIN bank_w[257]
    DIRECTION OUTPUT ;
    USE SIGNAL ;
    PORT
      LAYER M4 ;
        RECT  0 64.896 0.084 64.92 ;
    END
  END bank_w[257]
  PIN bank_w[258]
    DIRECTION OUTPUT ;
    USE SIGNAL ;
    PORT
      LAYER M4 ;
        RECT  0 65.184 0.084 65.208 ;
    END
  END bank_w[258]
  PIN bank_w[259]
    DIRECTION OUTPUT ;
    USE SIGNAL ;
    PORT
      LAYER M4 ;
        RECT  0 65.424 0.084 65.448 ;
    END
  END bank_w[259]
  PIN bank_w[25]
    DIRECTION OUTPUT ;
    USE SIGNAL ;
    PORT
      LAYER M4 ;
        RECT  0 6.912 0.084 6.936 ;
    END
  END bank_w[25]
  PIN bank_w[260]
    DIRECTION OUTPUT ;
    USE SIGNAL ;
    PORT
      LAYER M4 ;
        RECT  0 65.664 0.084 65.688 ;
    END
  END bank_w[260]
  PIN bank_w[261]
    DIRECTION OUTPUT ;
    USE SIGNAL ;
    PORT
      LAYER M4 ;
        RECT  0 65.904 0.084 65.928 ;
    END
  END bank_w[261]
  PIN bank_w[262]
    DIRECTION OUTPUT ;
    USE SIGNAL ;
    PORT
      LAYER M4 ;
        RECT  0 66.144 0.084 66.168 ;
    END
  END bank_w[262]
  PIN bank_w[263]
    DIRECTION OUTPUT ;
    USE SIGNAL ;
    PORT
      LAYER M4 ;
        RECT  0 66.432 0.084 66.456 ;
    END
  END bank_w[263]
  PIN bank_w[264]
    DIRECTION OUTPUT ;
    USE SIGNAL ;
    PORT
      LAYER M4 ;
        RECT  0 66.672 0.084 66.696 ;
    END
  END bank_w[264]
  PIN bank_w[265]
    DIRECTION OUTPUT ;
    USE SIGNAL ;
    PORT
      LAYER M4 ;
        RECT  0 66.912 0.084 66.936 ;
    END
  END bank_w[265]
  PIN bank_w[266]
    DIRECTION OUTPUT ;
    USE SIGNAL ;
    PORT
      LAYER M4 ;
        RECT  0 67.152 0.084 67.176 ;
    END
  END bank_w[266]
  PIN bank_w[267]
    DIRECTION OUTPUT ;
    USE SIGNAL ;
    PORT
      LAYER M4 ;
        RECT  0 67.392 0.084 67.416 ;
    END
  END bank_w[267]
  PIN bank_w[268]
    DIRECTION OUTPUT ;
    USE SIGNAL ;
    PORT
      LAYER M4 ;
        RECT  0 67.68 0.084 67.704 ;
    END
  END bank_w[268]
  PIN bank_w[269]
    DIRECTION OUTPUT ;
    USE SIGNAL ;
    PORT
      LAYER M4 ;
        RECT  0 67.92 0.084 67.944 ;
    END
  END bank_w[269]
  PIN bank_w[26]
    DIRECTION OUTPUT ;
    USE SIGNAL ;
    PORT
      LAYER M4 ;
        RECT  0 7.152 0.084 7.176 ;
    END
  END bank_w[26]
  PIN bank_w[270]
    DIRECTION OUTPUT ;
    USE SIGNAL ;
    PORT
      LAYER M4 ;
        RECT  0 68.16 0.084 68.184 ;
    END
  END bank_w[270]
  PIN bank_w[271]
    DIRECTION OUTPUT ;
    USE SIGNAL ;
    PORT
      LAYER M4 ;
        RECT  0 68.4 0.084 68.424 ;
    END
  END bank_w[271]
  PIN bank_w[272]
    DIRECTION OUTPUT ;
    USE SIGNAL ;
    PORT
      LAYER M4 ;
        RECT  0 68.688 0.084 68.712 ;
    END
  END bank_w[272]
  PIN bank_w[273]
    DIRECTION OUTPUT ;
    USE SIGNAL ;
    PORT
      LAYER M4 ;
        RECT  0 68.928 0.084 68.952 ;
    END
  END bank_w[273]
  PIN bank_w[274]
    DIRECTION OUTPUT ;
    USE SIGNAL ;
    PORT
      LAYER M4 ;
        RECT  0 69.168 0.084 69.192 ;
    END
  END bank_w[274]
  PIN bank_w[275]
    DIRECTION OUTPUT ;
    USE SIGNAL ;
    PORT
      LAYER M4 ;
        RECT  0 69.408 0.084 69.432 ;
    END
  END bank_w[275]
  PIN bank_w[276]
    DIRECTION OUTPUT ;
    USE SIGNAL ;
    PORT
      LAYER M4 ;
        RECT  0 69.648 0.084 69.672 ;
    END
  END bank_w[276]
  PIN bank_w[277]
    DIRECTION OUTPUT ;
    USE SIGNAL ;
    PORT
      LAYER M4 ;
        RECT  0 69.936 0.084 69.96 ;
    END
  END bank_w[277]
  PIN bank_w[278]
    DIRECTION OUTPUT ;
    USE SIGNAL ;
    PORT
      LAYER M4 ;
        RECT  0 70.176 0.084 70.2 ;
    END
  END bank_w[278]
  PIN bank_w[279]
    DIRECTION OUTPUT ;
    USE SIGNAL ;
    PORT
      LAYER M4 ;
        RECT  0 70.416 0.084 70.44 ;
    END
  END bank_w[279]
  PIN bank_w[27]
    DIRECTION OUTPUT ;
    USE SIGNAL ;
    PORT
      LAYER M4 ;
        RECT  0 7.392 0.084 7.416 ;
    END
  END bank_w[27]
  PIN bank_w[280]
    DIRECTION OUTPUT ;
    USE SIGNAL ;
    PORT
      LAYER M4 ;
        RECT  0 70.656 0.084 70.68 ;
    END
  END bank_w[280]
  PIN bank_w[281]
    DIRECTION OUTPUT ;
    USE SIGNAL ;
    PORT
      LAYER M4 ;
        RECT  0 70.896 0.084 70.92 ;
    END
  END bank_w[281]
  PIN bank_w[282]
    DIRECTION OUTPUT ;
    USE SIGNAL ;
    PORT
      LAYER M4 ;
        RECT  0 71.184 0.084 71.208 ;
    END
  END bank_w[282]
  PIN bank_w[283]
    DIRECTION OUTPUT ;
    USE SIGNAL ;
    PORT
      LAYER M4 ;
        RECT  0 71.424 0.084 71.448 ;
    END
  END bank_w[283]
  PIN bank_w[284]
    DIRECTION OUTPUT ;
    USE SIGNAL ;
    PORT
      LAYER M4 ;
        RECT  0 71.664 0.084 71.688 ;
    END
  END bank_w[284]
  PIN bank_w[285]
    DIRECTION OUTPUT ;
    USE SIGNAL ;
    PORT
      LAYER M4 ;
        RECT  0 71.904 0.084 71.928 ;
    END
  END bank_w[285]
  PIN bank_w[286]
    DIRECTION OUTPUT ;
    USE SIGNAL ;
    PORT
      LAYER M4 ;
        RECT  0 72.144 0.084 72.168 ;
    END
  END bank_w[286]
  PIN bank_w[287]
    DIRECTION OUTPUT ;
    USE SIGNAL ;
    PORT
      LAYER M4 ;
        RECT  0 72.432 0.084 72.456 ;
    END
  END bank_w[287]
  PIN bank_w[288]
    DIRECTION OUTPUT ;
    USE SIGNAL ;
    PORT
      LAYER M4 ;
        RECT  0 72.672 0.084 72.696 ;
    END
  END bank_w[288]
  PIN bank_w[289]
    DIRECTION OUTPUT ;
    USE SIGNAL ;
    PORT
      LAYER M4 ;
        RECT  0 72.912 0.084 72.936 ;
    END
  END bank_w[289]
  PIN bank_w[28]
    DIRECTION OUTPUT ;
    USE SIGNAL ;
    PORT
      LAYER M4 ;
        RECT  0 7.632 0.084 7.656 ;
    END
  END bank_w[28]
  PIN bank_w[290]
    DIRECTION OUTPUT ;
    USE SIGNAL ;
    PORT
      LAYER M4 ;
        RECT  0 73.152 0.084 73.176 ;
    END
  END bank_w[290]
  PIN bank_w[291]
    DIRECTION OUTPUT ;
    USE SIGNAL ;
    PORT
      LAYER M4 ;
        RECT  0 73.392 0.084 73.416 ;
    END
  END bank_w[291]
  PIN bank_w[292]
    DIRECTION OUTPUT ;
    USE SIGNAL ;
    PORT
      LAYER M4 ;
        RECT  0 73.68 0.084 73.704 ;
    END
  END bank_w[292]
  PIN bank_w[293]
    DIRECTION OUTPUT ;
    USE SIGNAL ;
    PORT
      LAYER M4 ;
        RECT  0 73.92 0.084 73.944 ;
    END
  END bank_w[293]
  PIN bank_w[294]
    DIRECTION OUTPUT ;
    USE SIGNAL ;
    PORT
      LAYER M4 ;
        RECT  0 74.16 0.084 74.184 ;
    END
  END bank_w[294]
  PIN bank_w[295]
    DIRECTION OUTPUT ;
    USE SIGNAL ;
    PORT
      LAYER M4 ;
        RECT  0 74.4 0.084 74.424 ;
    END
  END bank_w[295]
  PIN bank_w[296]
    DIRECTION OUTPUT ;
    USE SIGNAL ;
    PORT
      LAYER M4 ;
        RECT  0 74.688 0.084 74.712 ;
    END
  END bank_w[296]
  PIN bank_w[297]
    DIRECTION OUTPUT ;
    USE SIGNAL ;
    PORT
      LAYER M4 ;
        RECT  0 74.928 0.084 74.952 ;
    END
  END bank_w[297]
  PIN bank_w[298]
    DIRECTION OUTPUT ;
    USE SIGNAL ;
    PORT
      LAYER M4 ;
        RECT  0 75.168 0.084 75.192 ;
    END
  END bank_w[298]
  PIN bank_w[299]
    DIRECTION OUTPUT ;
    USE SIGNAL ;
    PORT
      LAYER M4 ;
        RECT  0 75.408 0.084 75.432 ;
    END
  END bank_w[299]
  PIN bank_w[29]
    DIRECTION OUTPUT ;
    USE SIGNAL ;
    PORT
      LAYER M4 ;
        RECT  0 7.92 0.084 7.944 ;
    END
  END bank_w[29]
  PIN bank_w[2]
    DIRECTION OUTPUT ;
    USE SIGNAL ;
    PORT
      LAYER M4 ;
        RECT  0 1.152 0.084 1.176 ;
    END
  END bank_w[2]
  PIN bank_w[300]
    DIRECTION OUTPUT ;
    USE SIGNAL ;
    PORT
      LAYER M4 ;
        RECT  0 75.648 0.084 75.672 ;
    END
  END bank_w[300]
  PIN bank_w[301]
    DIRECTION OUTPUT ;
    USE SIGNAL ;
    PORT
      LAYER M4 ;
        RECT  0 75.936 0.084 75.96 ;
    END
  END bank_w[301]
  PIN bank_w[302]
    DIRECTION OUTPUT ;
    USE SIGNAL ;
    PORT
      LAYER M4 ;
        RECT  0 76.176 0.084 76.2 ;
    END
  END bank_w[302]
  PIN bank_w[303]
    DIRECTION OUTPUT ;
    USE SIGNAL ;
    PORT
      LAYER M4 ;
        RECT  0 76.416 0.084 76.44 ;
    END
  END bank_w[303]
  PIN bank_w[304]
    DIRECTION OUTPUT ;
    USE SIGNAL ;
    PORT
      LAYER M4 ;
        RECT  0 76.656 0.084 76.68 ;
    END
  END bank_w[304]
  PIN bank_w[305]
    DIRECTION OUTPUT ;
    USE SIGNAL ;
    PORT
      LAYER M4 ;
        RECT  0 76.896 0.084 76.92 ;
    END
  END bank_w[305]
  PIN bank_w[306]
    DIRECTION OUTPUT ;
    USE SIGNAL ;
    PORT
      LAYER M4 ;
        RECT  0 77.184 0.084 77.208 ;
    END
  END bank_w[306]
  PIN bank_w[307]
    DIRECTION OUTPUT ;
    USE SIGNAL ;
    PORT
      LAYER M4 ;
        RECT  0 77.424 0.084 77.448 ;
    END
  END bank_w[307]
  PIN bank_w[308]
    DIRECTION OUTPUT ;
    USE SIGNAL ;
    PORT
      LAYER M4 ;
        RECT  0 77.664 0.084 77.688 ;
    END
  END bank_w[308]
  PIN bank_w[309]
    DIRECTION OUTPUT ;
    USE SIGNAL ;
    PORT
      LAYER M4 ;
        RECT  0 77.904 0.084 77.928 ;
    END
  END bank_w[309]
  PIN bank_w[30]
    DIRECTION OUTPUT ;
    USE SIGNAL ;
    PORT
      LAYER M4 ;
        RECT  0 8.16 0.084 8.184 ;
    END
  END bank_w[30]
  PIN bank_w[310]
    DIRECTION OUTPUT ;
    USE SIGNAL ;
    PORT
      LAYER M4 ;
        RECT  0 78.144 0.084 78.168 ;
    END
  END bank_w[310]
  PIN bank_w[311]
    DIRECTION OUTPUT ;
    USE SIGNAL ;
    PORT
      LAYER M4 ;
        RECT  0 78.432 0.084 78.456 ;
    END
  END bank_w[311]
  PIN bank_w[312]
    DIRECTION OUTPUT ;
    USE SIGNAL ;
    PORT
      LAYER M4 ;
        RECT  0 78.672 0.084 78.696 ;
    END
  END bank_w[312]
  PIN bank_w[313]
    DIRECTION OUTPUT ;
    USE SIGNAL ;
    PORT
      LAYER M4 ;
        RECT  0 78.912 0.084 78.936 ;
    END
  END bank_w[313]
  PIN bank_w[314]
    DIRECTION OUTPUT ;
    USE SIGNAL ;
    PORT
      LAYER M4 ;
        RECT  0 79.152 0.084 79.176 ;
    END
  END bank_w[314]
  PIN bank_w[315]
    DIRECTION OUTPUT ;
    USE SIGNAL ;
    PORT
      LAYER M4 ;
        RECT  0 79.392 0.084 79.416 ;
    END
  END bank_w[315]
  PIN bank_w[316]
    DIRECTION OUTPUT ;
    USE SIGNAL ;
    PORT
      LAYER M4 ;
        RECT  0 79.68 0.084 79.704 ;
    END
  END bank_w[316]
  PIN bank_w[317]
    DIRECTION OUTPUT ;
    USE SIGNAL ;
    PORT
      LAYER M4 ;
        RECT  0 79.92 0.084 79.944 ;
    END
  END bank_w[317]
  PIN bank_w[318]
    DIRECTION OUTPUT ;
    USE SIGNAL ;
    PORT
      LAYER M4 ;
        RECT  0 80.16 0.084 80.184 ;
    END
  END bank_w[318]
  PIN bank_w[319]
    DIRECTION OUTPUT ;
    USE SIGNAL ;
    PORT
      LAYER M4 ;
        RECT  0 80.4 0.084 80.424 ;
    END
  END bank_w[319]
  PIN bank_w[31]
    DIRECTION OUTPUT ;
    USE SIGNAL ;
    PORT
      LAYER M4 ;
        RECT  0 8.4 0.084 8.424 ;
    END
  END bank_w[31]
  PIN bank_w[320]
    DIRECTION OUTPUT ;
    USE SIGNAL ;
    PORT
      LAYER M4 ;
        RECT  0 80.688 0.084 80.712 ;
    END
  END bank_w[320]
  PIN bank_w[321]
    DIRECTION OUTPUT ;
    USE SIGNAL ;
    PORT
      LAYER M4 ;
        RECT  0 80.928 0.084 80.952 ;
    END
  END bank_w[321]
  PIN bank_w[322]
    DIRECTION OUTPUT ;
    USE SIGNAL ;
    PORT
      LAYER M4 ;
        RECT  0 81.168 0.084 81.192 ;
    END
  END bank_w[322]
  PIN bank_w[323]
    DIRECTION OUTPUT ;
    USE SIGNAL ;
    PORT
      LAYER M4 ;
        RECT  0 81.408 0.084 81.432 ;
    END
  END bank_w[323]
  PIN bank_w[324]
    DIRECTION OUTPUT ;
    USE SIGNAL ;
    PORT
      LAYER M4 ;
        RECT  0 81.648 0.084 81.672 ;
    END
  END bank_w[324]
  PIN bank_w[325]
    DIRECTION OUTPUT ;
    USE SIGNAL ;
    PORT
      LAYER M4 ;
        RECT  0 81.936 0.084 81.96 ;
    END
  END bank_w[325]
  PIN bank_w[326]
    DIRECTION OUTPUT ;
    USE SIGNAL ;
    PORT
      LAYER M4 ;
        RECT  0 82.176 0.084 82.2 ;
    END
  END bank_w[326]
  PIN bank_w[327]
    DIRECTION OUTPUT ;
    USE SIGNAL ;
    PORT
      LAYER M4 ;
        RECT  0 82.416 0.084 82.44 ;
    END
  END bank_w[327]
  PIN bank_w[328]
    DIRECTION OUTPUT ;
    USE SIGNAL ;
    PORT
      LAYER M4 ;
        RECT  0 82.656 0.084 82.68 ;
    END
  END bank_w[328]
  PIN bank_w[329]
    DIRECTION OUTPUT ;
    USE SIGNAL ;
    PORT
      LAYER M4 ;
        RECT  0 82.896 0.084 82.92 ;
    END
  END bank_w[329]
  PIN bank_w[32]
    DIRECTION OUTPUT ;
    USE SIGNAL ;
    PORT
      LAYER M4 ;
        RECT  0 8.64 0.084 8.664 ;
    END
  END bank_w[32]
  PIN bank_w[330]
    DIRECTION OUTPUT ;
    USE SIGNAL ;
    PORT
      LAYER M4 ;
        RECT  0 83.184 0.084 83.208 ;
    END
  END bank_w[330]
  PIN bank_w[331]
    DIRECTION OUTPUT ;
    USE SIGNAL ;
    PORT
      LAYER M4 ;
        RECT  0 83.424 0.084 83.448 ;
    END
  END bank_w[331]
  PIN bank_w[332]
    DIRECTION OUTPUT ;
    USE SIGNAL ;
    PORT
      LAYER M4 ;
        RECT  0 83.664 0.084 83.688 ;
    END
  END bank_w[332]
  PIN bank_w[333]
    DIRECTION OUTPUT ;
    USE SIGNAL ;
    PORT
      LAYER M4 ;
        RECT  0 83.904 0.084 83.928 ;
    END
  END bank_w[333]
  PIN bank_w[334]
    DIRECTION OUTPUT ;
    USE SIGNAL ;
    PORT
      LAYER M4 ;
        RECT  0 84.144 0.084 84.168 ;
    END
  END bank_w[334]
  PIN bank_w[335]
    DIRECTION OUTPUT ;
    USE SIGNAL ;
    PORT
      LAYER M4 ;
        RECT  0 84.432 0.084 84.456 ;
    END
  END bank_w[335]
  PIN bank_w[336]
    DIRECTION OUTPUT ;
    USE SIGNAL ;
    PORT
      LAYER M4 ;
        RECT  0 84.672 0.084 84.696 ;
    END
  END bank_w[336]
  PIN bank_w[337]
    DIRECTION OUTPUT ;
    USE SIGNAL ;
    PORT
      LAYER M4 ;
        RECT  0 84.912 0.084 84.936 ;
    END
  END bank_w[337]
  PIN bank_w[338]
    DIRECTION OUTPUT ;
    USE SIGNAL ;
    PORT
      LAYER M4 ;
        RECT  0 85.152 0.084 85.176 ;
    END
  END bank_w[338]
  PIN bank_w[339]
    DIRECTION OUTPUT ;
    USE SIGNAL ;
    PORT
      LAYER M4 ;
        RECT  0 85.44 0.084 85.464 ;
    END
  END bank_w[339]
  PIN bank_w[33]
    DIRECTION OUTPUT ;
    USE SIGNAL ;
    PORT
      LAYER M4 ;
        RECT  0 8.928 0.084 8.952 ;
    END
  END bank_w[33]
  PIN bank_w[340]
    DIRECTION OUTPUT ;
    USE SIGNAL ;
    PORT
      LAYER M4 ;
        RECT  0 85.68 0.084 85.704 ;
    END
  END bank_w[340]
  PIN bank_w[341]
    DIRECTION OUTPUT ;
    USE SIGNAL ;
    PORT
      LAYER M4 ;
        RECT  0 85.92 0.084 85.944 ;
    END
  END bank_w[341]
  PIN bank_w[342]
    DIRECTION OUTPUT ;
    USE SIGNAL ;
    PORT
      LAYER M4 ;
        RECT  0 86.16 0.084 86.184 ;
    END
  END bank_w[342]
  PIN bank_w[343]
    DIRECTION OUTPUT ;
    USE SIGNAL ;
    PORT
      LAYER M4 ;
        RECT  0 86.4 0.084 86.424 ;
    END
  END bank_w[343]
  PIN bank_w[344]
    DIRECTION OUTPUT ;
    USE SIGNAL ;
    PORT
      LAYER M4 ;
        RECT  0 86.688 0.084 86.712 ;
    END
  END bank_w[344]
  PIN bank_w[345]
    DIRECTION OUTPUT ;
    USE SIGNAL ;
    PORT
      LAYER M4 ;
        RECT  0 86.928 0.084 86.952 ;
    END
  END bank_w[345]
  PIN bank_w[346]
    DIRECTION OUTPUT ;
    USE SIGNAL ;
    PORT
      LAYER M4 ;
        RECT  0 87.168 0.084 87.192 ;
    END
  END bank_w[346]
  PIN bank_w[347]
    DIRECTION OUTPUT ;
    USE SIGNAL ;
    PORT
      LAYER M4 ;
        RECT  0 87.408 0.084 87.432 ;
    END
  END bank_w[347]
  PIN bank_w[348]
    DIRECTION OUTPUT ;
    USE SIGNAL ;
    PORT
      LAYER M4 ;
        RECT  0 87.648 0.084 87.672 ;
    END
  END bank_w[348]
  PIN bank_w[349]
    DIRECTION OUTPUT ;
    USE SIGNAL ;
    PORT
      LAYER M4 ;
        RECT  0 87.936 0.084 87.96 ;
    END
  END bank_w[349]
  PIN bank_w[34]
    DIRECTION OUTPUT ;
    USE SIGNAL ;
    PORT
      LAYER M4 ;
        RECT  0 9.168 0.084 9.192 ;
    END
  END bank_w[34]
  PIN bank_w[350]
    DIRECTION OUTPUT ;
    USE SIGNAL ;
    PORT
      LAYER M4 ;
        RECT  0 88.176 0.084 88.2 ;
    END
  END bank_w[350]
  PIN bank_w[351]
    DIRECTION OUTPUT ;
    USE SIGNAL ;
    PORT
      LAYER M4 ;
        RECT  0 88.416 0.084 88.44 ;
    END
  END bank_w[351]
  PIN bank_w[352]
    DIRECTION OUTPUT ;
    USE SIGNAL ;
    PORT
      LAYER M4 ;
        RECT  0 88.656 0.084 88.68 ;
    END
  END bank_w[352]
  PIN bank_w[353]
    DIRECTION OUTPUT ;
    USE SIGNAL ;
    PORT
      LAYER M4 ;
        RECT  0 88.896 0.084 88.92 ;
    END
  END bank_w[353]
  PIN bank_w[354]
    DIRECTION OUTPUT ;
    USE SIGNAL ;
    PORT
      LAYER M4 ;
        RECT  0 89.184 0.084 89.208 ;
    END
  END bank_w[354]
  PIN bank_w[355]
    DIRECTION OUTPUT ;
    USE SIGNAL ;
    PORT
      LAYER M4 ;
        RECT  0 89.424 0.084 89.448 ;
    END
  END bank_w[355]
  PIN bank_w[356]
    DIRECTION OUTPUT ;
    USE SIGNAL ;
    PORT
      LAYER M4 ;
        RECT  0 89.664 0.084 89.688 ;
    END
  END bank_w[356]
  PIN bank_w[357]
    DIRECTION OUTPUT ;
    USE SIGNAL ;
    PORT
      LAYER M4 ;
        RECT  0 89.904 0.084 89.928 ;
    END
  END bank_w[357]
  PIN bank_w[358]
    DIRECTION OUTPUT ;
    USE SIGNAL ;
    PORT
      LAYER M4 ;
        RECT  0 90.144 0.084 90.168 ;
    END
  END bank_w[358]
  PIN bank_w[359]
    DIRECTION OUTPUT ;
    USE SIGNAL ;
    PORT
      LAYER M4 ;
        RECT  0 90.432 0.084 90.456 ;
    END
  END bank_w[359]
  PIN bank_w[35]
    DIRECTION OUTPUT ;
    USE SIGNAL ;
    PORT
      LAYER M4 ;
        RECT  0 9.408 0.084 9.432 ;
    END
  END bank_w[35]
  PIN bank_w[360]
    DIRECTION OUTPUT ;
    USE SIGNAL ;
    PORT
      LAYER M4 ;
        RECT  0 90.672 0.084 90.696 ;
    END
  END bank_w[360]
  PIN bank_w[361]
    DIRECTION OUTPUT ;
    USE SIGNAL ;
    PORT
      LAYER M4 ;
        RECT  0 90.912 0.084 90.936 ;
    END
  END bank_w[361]
  PIN bank_w[362]
    DIRECTION OUTPUT ;
    USE SIGNAL ;
    PORT
      LAYER M4 ;
        RECT  0 91.152 0.084 91.176 ;
    END
  END bank_w[362]
  PIN bank_w[363]
    DIRECTION OUTPUT ;
    USE SIGNAL ;
    PORT
      LAYER M4 ;
        RECT  0 91.44 0.084 91.464 ;
    END
  END bank_w[363]
  PIN bank_w[364]
    DIRECTION OUTPUT ;
    USE SIGNAL ;
    PORT
      LAYER M4 ;
        RECT  0 91.68 0.084 91.704 ;
    END
  END bank_w[364]
  PIN bank_w[365]
    DIRECTION OUTPUT ;
    USE SIGNAL ;
    PORT
      LAYER M4 ;
        RECT  0 91.92 0.084 91.944 ;
    END
  END bank_w[365]
  PIN bank_w[366]
    DIRECTION OUTPUT ;
    USE SIGNAL ;
    PORT
      LAYER M4 ;
        RECT  0 92.16 0.084 92.184 ;
    END
  END bank_w[366]
  PIN bank_w[367]
    DIRECTION OUTPUT ;
    USE SIGNAL ;
    PORT
      LAYER M4 ;
        RECT  0 92.4 0.084 92.424 ;
    END
  END bank_w[367]
  PIN bank_w[368]
    DIRECTION OUTPUT ;
    USE SIGNAL ;
    PORT
      LAYER M4 ;
        RECT  0 92.688 0.084 92.712 ;
    END
  END bank_w[368]
  PIN bank_w[369]
    DIRECTION OUTPUT ;
    USE SIGNAL ;
    PORT
      LAYER M4 ;
        RECT  0 92.928 0.084 92.952 ;
    END
  END bank_w[369]
  PIN bank_w[36]
    DIRECTION OUTPUT ;
    USE SIGNAL ;
    PORT
      LAYER M4 ;
        RECT  0 9.648 0.084 9.672 ;
    END
  END bank_w[36]
  PIN bank_w[370]
    DIRECTION OUTPUT ;
    USE SIGNAL ;
    PORT
      LAYER M4 ;
        RECT  0 93.168 0.084 93.192 ;
    END
  END bank_w[370]
  PIN bank_w[371]
    DIRECTION OUTPUT ;
    USE SIGNAL ;
    PORT
      LAYER M4 ;
        RECT  0 93.408 0.084 93.432 ;
    END
  END bank_w[371]
  PIN bank_w[372]
    DIRECTION OUTPUT ;
    USE SIGNAL ;
    PORT
      LAYER M4 ;
        RECT  0 93.648 0.084 93.672 ;
    END
  END bank_w[372]
  PIN bank_w[373]
    DIRECTION OUTPUT ;
    USE SIGNAL ;
    PORT
      LAYER M4 ;
        RECT  0 93.936 0.084 93.96 ;
    END
  END bank_w[373]
  PIN bank_w[374]
    DIRECTION OUTPUT ;
    USE SIGNAL ;
    PORT
      LAYER M4 ;
        RECT  0 94.176 0.084 94.2 ;
    END
  END bank_w[374]
  PIN bank_w[375]
    DIRECTION OUTPUT ;
    USE SIGNAL ;
    PORT
      LAYER M4 ;
        RECT  0 94.416 0.084 94.44 ;
    END
  END bank_w[375]
  PIN bank_w[376]
    DIRECTION OUTPUT ;
    USE SIGNAL ;
    PORT
      LAYER M4 ;
        RECT  0 94.656 0.084 94.68 ;
    END
  END bank_w[376]
  PIN bank_w[377]
    DIRECTION OUTPUT ;
    USE SIGNAL ;
    PORT
      LAYER M4 ;
        RECT  0 94.896 0.084 94.92 ;
    END
  END bank_w[377]
  PIN bank_w[378]
    DIRECTION OUTPUT ;
    USE SIGNAL ;
    PORT
      LAYER M4 ;
        RECT  0 95.184 0.084 95.208 ;
    END
  END bank_w[378]
  PIN bank_w[379]
    DIRECTION OUTPUT ;
    USE SIGNAL ;
    PORT
      LAYER M4 ;
        RECT  0 95.424 0.084 95.448 ;
    END
  END bank_w[379]
  PIN bank_w[37]
    DIRECTION OUTPUT ;
    USE SIGNAL ;
    PORT
      LAYER M4 ;
        RECT  0 9.888 0.084 9.912 ;
    END
  END bank_w[37]
  PIN bank_w[380]
    DIRECTION OUTPUT ;
    USE SIGNAL ;
    PORT
      LAYER M4 ;
        RECT  0 95.664 0.084 95.688 ;
    END
  END bank_w[380]
  PIN bank_w[381]
    DIRECTION OUTPUT ;
    USE SIGNAL ;
    PORT
      LAYER M4 ;
        RECT  0 95.904 0.084 95.928 ;
    END
  END bank_w[381]
  PIN bank_w[382]
    DIRECTION OUTPUT ;
    USE SIGNAL ;
    PORT
      LAYER M4 ;
        RECT  0 96.192 0.084 96.216 ;
    END
  END bank_w[382]
  PIN bank_w[383]
    DIRECTION OUTPUT ;
    USE SIGNAL ;
    PORT
      LAYER M4 ;
        RECT  0 96.432 0.084 96.456 ;
    END
  END bank_w[383]
  PIN bank_w[384]
    DIRECTION OUTPUT ;
    USE SIGNAL ;
    PORT
      LAYER M4 ;
        RECT  0 96.672 0.084 96.696 ;
    END
  END bank_w[384]
  PIN bank_w[385]
    DIRECTION OUTPUT ;
    USE SIGNAL ;
    PORT
      LAYER M4 ;
        RECT  0 96.912 0.084 96.936 ;
    END
  END bank_w[385]
  PIN bank_w[386]
    DIRECTION OUTPUT ;
    USE SIGNAL ;
    PORT
      LAYER M4 ;
        RECT  0 97.152 0.084 97.176 ;
    END
  END bank_w[386]
  PIN bank_w[387]
    DIRECTION OUTPUT ;
    USE SIGNAL ;
    PORT
      LAYER M4 ;
        RECT  0 97.44 0.084 97.464 ;
    END
  END bank_w[387]
  PIN bank_w[388]
    DIRECTION OUTPUT ;
    USE SIGNAL ;
    PORT
      LAYER M4 ;
        RECT  0 97.68 0.084 97.704 ;
    END
  END bank_w[388]
  PIN bank_w[389]
    DIRECTION OUTPUT ;
    USE SIGNAL ;
    PORT
      LAYER M4 ;
        RECT  0 97.92 0.084 97.944 ;
    END
  END bank_w[389]
  PIN bank_w[38]
    DIRECTION OUTPUT ;
    USE SIGNAL ;
    PORT
      LAYER M4 ;
        RECT  0 10.176 0.084 10.2 ;
    END
  END bank_w[38]
  PIN bank_w[390]
    DIRECTION OUTPUT ;
    USE SIGNAL ;
    PORT
      LAYER M4 ;
        RECT  0 98.16 0.084 98.184 ;
    END
  END bank_w[390]
  PIN bank_w[391]
    DIRECTION OUTPUT ;
    USE SIGNAL ;
    PORT
      LAYER M4 ;
        RECT  0 98.4 0.084 98.424 ;
    END
  END bank_w[391]
  PIN bank_w[392]
    DIRECTION OUTPUT ;
    USE SIGNAL ;
    PORT
      LAYER M4 ;
        RECT  0 98.688 0.084 98.712 ;
    END
  END bank_w[392]
  PIN bank_w[393]
    DIRECTION OUTPUT ;
    USE SIGNAL ;
    PORT
      LAYER M4 ;
        RECT  0 98.928 0.084 98.952 ;
    END
  END bank_w[393]
  PIN bank_w[394]
    DIRECTION OUTPUT ;
    USE SIGNAL ;
    PORT
      LAYER M4 ;
        RECT  0 99.168 0.084 99.192 ;
    END
  END bank_w[394]
  PIN bank_w[395]
    DIRECTION OUTPUT ;
    USE SIGNAL ;
    PORT
      LAYER M4 ;
        RECT  0 99.408 0.084 99.432 ;
    END
  END bank_w[395]
  PIN bank_w[396]
    DIRECTION OUTPUT ;
    USE SIGNAL ;
    PORT
      LAYER M4 ;
        RECT  0 99.648 0.084 99.672 ;
    END
  END bank_w[396]
  PIN bank_w[397]
    DIRECTION OUTPUT ;
    USE SIGNAL ;
    PORT
      LAYER M4 ;
        RECT  0 99.936 0.084 99.96 ;
    END
  END bank_w[397]
  PIN bank_w[398]
    DIRECTION OUTPUT ;
    USE SIGNAL ;
    PORT
      LAYER M4 ;
        RECT  0 100.176 0.084 100.2 ;
    END
  END bank_w[398]
  PIN bank_w[399]
    DIRECTION OUTPUT ;
    USE SIGNAL ;
    PORT
      LAYER M4 ;
        RECT  0 100.416 0.084 100.44 ;
    END
  END bank_w[399]
  PIN bank_w[39]
    DIRECTION OUTPUT ;
    USE SIGNAL ;
    PORT
      LAYER M4 ;
        RECT  0 10.416 0.084 10.44 ;
    END
  END bank_w[39]
  PIN bank_w[3]
    DIRECTION OUTPUT ;
    USE SIGNAL ;
    PORT
      LAYER M4 ;
        RECT  0 1.392 0.084 1.416 ;
    END
  END bank_w[3]
  PIN bank_w[400]
    DIRECTION OUTPUT ;
    USE SIGNAL ;
    PORT
      LAYER M4 ;
        RECT  0 100.656 0.084 100.68 ;
    END
  END bank_w[400]
  PIN bank_w[401]
    DIRECTION OUTPUT ;
    USE SIGNAL ;
    PORT
      LAYER M4 ;
        RECT  0 100.896 0.084 100.92 ;
    END
  END bank_w[401]
  PIN bank_w[402]
    DIRECTION OUTPUT ;
    USE SIGNAL ;
    PORT
      LAYER M4 ;
        RECT  0 101.184 0.084 101.208 ;
    END
  END bank_w[402]
  PIN bank_w[403]
    DIRECTION OUTPUT ;
    USE SIGNAL ;
    PORT
      LAYER M4 ;
        RECT  0 101.424 0.084 101.448 ;
    END
  END bank_w[403]
  PIN bank_w[404]
    DIRECTION OUTPUT ;
    USE SIGNAL ;
    PORT
      LAYER M4 ;
        RECT  0 101.664 0.084 101.688 ;
    END
  END bank_w[404]
  PIN bank_w[405]
    DIRECTION OUTPUT ;
    USE SIGNAL ;
    PORT
      LAYER M4 ;
        RECT  0 101.904 0.084 101.928 ;
    END
  END bank_w[405]
  PIN bank_w[406]
    DIRECTION OUTPUT ;
    USE SIGNAL ;
    PORT
      LAYER M4 ;
        RECT  0 102.192 0.084 102.216 ;
    END
  END bank_w[406]
  PIN bank_w[407]
    DIRECTION OUTPUT ;
    USE SIGNAL ;
    PORT
      LAYER M4 ;
        RECT  0 102.432 0.084 102.456 ;
    END
  END bank_w[407]
  PIN bank_w[408]
    DIRECTION OUTPUT ;
    USE SIGNAL ;
    PORT
      LAYER M4 ;
        RECT  0 102.672 0.084 102.696 ;
    END
  END bank_w[408]
  PIN bank_w[409]
    DIRECTION OUTPUT ;
    USE SIGNAL ;
    PORT
      LAYER M4 ;
        RECT  0 102.912 0.084 102.936 ;
    END
  END bank_w[409]
  PIN bank_w[40]
    DIRECTION OUTPUT ;
    USE SIGNAL ;
    PORT
      LAYER M4 ;
        RECT  0 10.656 0.084 10.68 ;
    END
  END bank_w[40]
  PIN bank_w[410]
    DIRECTION OUTPUT ;
    USE SIGNAL ;
    PORT
      LAYER M4 ;
        RECT  0 103.152 0.084 103.176 ;
    END
  END bank_w[410]
  PIN bank_w[411]
    DIRECTION OUTPUT ;
    USE SIGNAL ;
    PORT
      LAYER M4 ;
        RECT  0 103.44 0.084 103.464 ;
    END
  END bank_w[411]
  PIN bank_w[412]
    DIRECTION OUTPUT ;
    USE SIGNAL ;
    PORT
      LAYER M4 ;
        RECT  0 103.68 0.084 103.704 ;
    END
  END bank_w[412]
  PIN bank_w[413]
    DIRECTION OUTPUT ;
    USE SIGNAL ;
    PORT
      LAYER M4 ;
        RECT  0 103.92 0.084 103.944 ;
    END
  END bank_w[413]
  PIN bank_w[414]
    DIRECTION OUTPUT ;
    USE SIGNAL ;
    PORT
      LAYER M4 ;
        RECT  0 104.16 0.084 104.184 ;
    END
  END bank_w[414]
  PIN bank_w[415]
    DIRECTION OUTPUT ;
    USE SIGNAL ;
    PORT
      LAYER M4 ;
        RECT  0 104.4 0.084 104.424 ;
    END
  END bank_w[415]
  PIN bank_w[416]
    DIRECTION OUTPUT ;
    USE SIGNAL ;
    PORT
      LAYER M4 ;
        RECT  0 104.688 0.084 104.712 ;
    END
  END bank_w[416]
  PIN bank_w[417]
    DIRECTION OUTPUT ;
    USE SIGNAL ;
    PORT
      LAYER M4 ;
        RECT  0 104.928 0.084 104.952 ;
    END
  END bank_w[417]
  PIN bank_w[418]
    DIRECTION OUTPUT ;
    USE SIGNAL ;
    PORT
      LAYER M4 ;
        RECT  0 105.168 0.084 105.192 ;
    END
  END bank_w[418]
  PIN bank_w[419]
    DIRECTION OUTPUT ;
    USE SIGNAL ;
    PORT
      LAYER M4 ;
        RECT  0 105.408 0.084 105.432 ;
    END
  END bank_w[419]
  PIN bank_w[41]
    DIRECTION OUTPUT ;
    USE SIGNAL ;
    PORT
      LAYER M4 ;
        RECT  0 10.896 0.084 10.92 ;
    END
  END bank_w[41]
  PIN bank_w[420]
    DIRECTION OUTPUT ;
    USE SIGNAL ;
    PORT
      LAYER M4 ;
        RECT  0 105.648 0.084 105.672 ;
    END
  END bank_w[420]
  PIN bank_w[421]
    DIRECTION OUTPUT ;
    USE SIGNAL ;
    PORT
      LAYER M4 ;
        RECT  0 105.936 0.084 105.96 ;
    END
  END bank_w[421]
  PIN bank_w[422]
    DIRECTION OUTPUT ;
    USE SIGNAL ;
    PORT
      LAYER M4 ;
        RECT  0 106.176 0.084 106.2 ;
    END
  END bank_w[422]
  PIN bank_w[423]
    DIRECTION OUTPUT ;
    USE SIGNAL ;
    PORT
      LAYER M4 ;
        RECT  0 106.416 0.084 106.44 ;
    END
  END bank_w[423]
  PIN bank_w[424]
    DIRECTION OUTPUT ;
    USE SIGNAL ;
    PORT
      LAYER M4 ;
        RECT  0 106.656 0.084 106.68 ;
    END
  END bank_w[424]
  PIN bank_w[425]
    DIRECTION OUTPUT ;
    USE SIGNAL ;
    PORT
      LAYER M4 ;
        RECT  0 106.944 0.084 106.968 ;
    END
  END bank_w[425]
  PIN bank_w[426]
    DIRECTION OUTPUT ;
    USE SIGNAL ;
    PORT
      LAYER M4 ;
        RECT  0 107.184 0.084 107.208 ;
    END
  END bank_w[426]
  PIN bank_w[427]
    DIRECTION OUTPUT ;
    USE SIGNAL ;
    PORT
      LAYER M4 ;
        RECT  0 107.424 0.084 107.448 ;
    END
  END bank_w[427]
  PIN bank_w[428]
    DIRECTION OUTPUT ;
    USE SIGNAL ;
    PORT
      LAYER M4 ;
        RECT  0 107.664 0.084 107.688 ;
    END
  END bank_w[428]
  PIN bank_w[429]
    DIRECTION OUTPUT ;
    USE SIGNAL ;
    PORT
      LAYER M4 ;
        RECT  0 107.904 0.084 107.928 ;
    END
  END bank_w[429]
  PIN bank_w[42]
    DIRECTION OUTPUT ;
    USE SIGNAL ;
    PORT
      LAYER M4 ;
        RECT  0 11.136 0.084 11.16 ;
    END
  END bank_w[42]
  PIN bank_w[430]
    DIRECTION OUTPUT ;
    USE SIGNAL ;
    PORT
      LAYER M4 ;
        RECT  0 108.192 0.084 108.216 ;
    END
  END bank_w[430]
  PIN bank_w[431]
    DIRECTION OUTPUT ;
    USE SIGNAL ;
    PORT
      LAYER M4 ;
        RECT  0 108.432 0.084 108.456 ;
    END
  END bank_w[431]
  PIN bank_w[432]
    DIRECTION OUTPUT ;
    USE SIGNAL ;
    PORT
      LAYER M4 ;
        RECT  0 108.672 0.084 108.696 ;
    END
  END bank_w[432]
  PIN bank_w[433]
    DIRECTION OUTPUT ;
    USE SIGNAL ;
    PORT
      LAYER M4 ;
        RECT  0 108.912 0.084 108.936 ;
    END
  END bank_w[433]
  PIN bank_w[434]
    DIRECTION OUTPUT ;
    USE SIGNAL ;
    PORT
      LAYER M4 ;
        RECT  0 109.152 0.084 109.176 ;
    END
  END bank_w[434]
  PIN bank_w[435]
    DIRECTION OUTPUT ;
    USE SIGNAL ;
    PORT
      LAYER M4 ;
        RECT  0 109.44 0.084 109.464 ;
    END
  END bank_w[435]
  PIN bank_w[436]
    DIRECTION OUTPUT ;
    USE SIGNAL ;
    PORT
      LAYER M4 ;
        RECT  0 109.68 0.084 109.704 ;
    END
  END bank_w[436]
  PIN bank_w[437]
    DIRECTION OUTPUT ;
    USE SIGNAL ;
    PORT
      LAYER M4 ;
        RECT  0 109.92 0.084 109.944 ;
    END
  END bank_w[437]
  PIN bank_w[438]
    DIRECTION OUTPUT ;
    USE SIGNAL ;
    PORT
      LAYER M4 ;
        RECT  0 110.16 0.084 110.184 ;
    END
  END bank_w[438]
  PIN bank_w[439]
    DIRECTION OUTPUT ;
    USE SIGNAL ;
    PORT
      LAYER M4 ;
        RECT  0 110.4 0.084 110.424 ;
    END
  END bank_w[439]
  PIN bank_w[43]
    DIRECTION OUTPUT ;
    USE SIGNAL ;
    PORT
      LAYER M4 ;
        RECT  0 11.424 0.084 11.448 ;
    END
  END bank_w[43]
  PIN bank_w[440]
    DIRECTION OUTPUT ;
    USE SIGNAL ;
    PORT
      LAYER M4 ;
        RECT  0 110.688 0.084 110.712 ;
    END
  END bank_w[440]
  PIN bank_w[441]
    DIRECTION OUTPUT ;
    USE SIGNAL ;
    PORT
      LAYER M4 ;
        RECT  0 110.928 0.084 110.952 ;
    END
  END bank_w[441]
  PIN bank_w[442]
    DIRECTION OUTPUT ;
    USE SIGNAL ;
    PORT
      LAYER M4 ;
        RECT  0 111.168 0.084 111.192 ;
    END
  END bank_w[442]
  PIN bank_w[443]
    DIRECTION OUTPUT ;
    USE SIGNAL ;
    PORT
      LAYER M4 ;
        RECT  0 111.408 0.084 111.432 ;
    END
  END bank_w[443]
  PIN bank_w[444]
    DIRECTION OUTPUT ;
    USE SIGNAL ;
    PORT
      LAYER M4 ;
        RECT  0 111.648 0.084 111.672 ;
    END
  END bank_w[444]
  PIN bank_w[445]
    DIRECTION OUTPUT ;
    USE SIGNAL ;
    PORT
      LAYER M4 ;
        RECT  0 111.936 0.084 111.96 ;
    END
  END bank_w[445]
  PIN bank_w[446]
    DIRECTION OUTPUT ;
    USE SIGNAL ;
    PORT
      LAYER M4 ;
        RECT  0 112.176 0.084 112.2 ;
    END
  END bank_w[446]
  PIN bank_w[447]
    DIRECTION OUTPUT ;
    USE SIGNAL ;
    PORT
      LAYER M4 ;
        RECT  0 112.416 0.084 112.44 ;
    END
  END bank_w[447]
  PIN bank_w[448]
    DIRECTION OUTPUT ;
    USE SIGNAL ;
    PORT
      LAYER M4 ;
        RECT  0 112.656 0.084 112.68 ;
    END
  END bank_w[448]
  PIN bank_w[449]
    DIRECTION OUTPUT ;
    USE SIGNAL ;
    PORT
      LAYER M4 ;
        RECT  0 112.944 0.084 112.968 ;
    END
  END bank_w[449]
  PIN bank_w[44]
    DIRECTION OUTPUT ;
    USE SIGNAL ;
    PORT
      LAYER M4 ;
        RECT  0 11.664 0.084 11.688 ;
    END
  END bank_w[44]
  PIN bank_w[450]
    DIRECTION OUTPUT ;
    USE SIGNAL ;
    PORT
      LAYER M4 ;
        RECT  0 113.184 0.084 113.208 ;
    END
  END bank_w[450]
  PIN bank_w[451]
    DIRECTION OUTPUT ;
    USE SIGNAL ;
    PORT
      LAYER M4 ;
        RECT  0 113.424 0.084 113.448 ;
    END
  END bank_w[451]
  PIN bank_w[452]
    DIRECTION OUTPUT ;
    USE SIGNAL ;
    PORT
      LAYER M4 ;
        RECT  0 113.664 0.084 113.688 ;
    END
  END bank_w[452]
  PIN bank_w[453]
    DIRECTION OUTPUT ;
    USE SIGNAL ;
    PORT
      LAYER M4 ;
        RECT  0 113.904 0.084 113.928 ;
    END
  END bank_w[453]
  PIN bank_w[454]
    DIRECTION OUTPUT ;
    USE SIGNAL ;
    PORT
      LAYER M4 ;
        RECT  0 114.192 0.084 114.216 ;
    END
  END bank_w[454]
  PIN bank_w[455]
    DIRECTION OUTPUT ;
    USE SIGNAL ;
    PORT
      LAYER M4 ;
        RECT  0 114.432 0.084 114.456 ;
    END
  END bank_w[455]
  PIN bank_w[456]
    DIRECTION OUTPUT ;
    USE SIGNAL ;
    PORT
      LAYER M4 ;
        RECT  0 114.672 0.084 114.696 ;
    END
  END bank_w[456]
  PIN bank_w[457]
    DIRECTION OUTPUT ;
    USE SIGNAL ;
    PORT
      LAYER M4 ;
        RECT  0 114.912 0.084 114.936 ;
    END
  END bank_w[457]
  PIN bank_w[458]
    DIRECTION OUTPUT ;
    USE SIGNAL ;
    PORT
      LAYER M4 ;
        RECT  0 115.152 0.084 115.176 ;
    END
  END bank_w[458]
  PIN bank_w[459]
    DIRECTION OUTPUT ;
    USE SIGNAL ;
    PORT
      LAYER M4 ;
        RECT  0 115.44 0.084 115.464 ;
    END
  END bank_w[459]
  PIN bank_w[45]
    DIRECTION OUTPUT ;
    USE SIGNAL ;
    PORT
      LAYER M4 ;
        RECT  0 11.904 0.084 11.928 ;
    END
  END bank_w[45]
  PIN bank_w[460]
    DIRECTION OUTPUT ;
    USE SIGNAL ;
    PORT
      LAYER M4 ;
        RECT  0 115.68 0.084 115.704 ;
    END
  END bank_w[460]
  PIN bank_w[461]
    DIRECTION OUTPUT ;
    USE SIGNAL ;
    PORT
      LAYER M4 ;
        RECT  0 115.92 0.084 115.944 ;
    END
  END bank_w[461]
  PIN bank_w[462]
    DIRECTION OUTPUT ;
    USE SIGNAL ;
    PORT
      LAYER M4 ;
        RECT  0 116.16 0.084 116.184 ;
    END
  END bank_w[462]
  PIN bank_w[463]
    DIRECTION OUTPUT ;
    USE SIGNAL ;
    PORT
      LAYER M4 ;
        RECT  0 116.4 0.084 116.424 ;
    END
  END bank_w[463]
  PIN bank_w[464]
    DIRECTION OUTPUT ;
    USE SIGNAL ;
    PORT
      LAYER M4 ;
        RECT  0 116.688 0.084 116.712 ;
    END
  END bank_w[464]
  PIN bank_w[465]
    DIRECTION OUTPUT ;
    USE SIGNAL ;
    PORT
      LAYER M4 ;
        RECT  0 116.928 0.084 116.952 ;
    END
  END bank_w[465]
  PIN bank_w[466]
    DIRECTION OUTPUT ;
    USE SIGNAL ;
    PORT
      LAYER M4 ;
        RECT  0 117.168 0.084 117.192 ;
    END
  END bank_w[466]
  PIN bank_w[467]
    DIRECTION OUTPUT ;
    USE SIGNAL ;
    PORT
      LAYER M4 ;
        RECT  0 117.408 0.084 117.432 ;
    END
  END bank_w[467]
  PIN bank_w[468]
    DIRECTION OUTPUT ;
    USE SIGNAL ;
    PORT
      LAYER M4 ;
        RECT  0 117.648 0.084 117.672 ;
    END
  END bank_w[468]
  PIN bank_w[469]
    DIRECTION OUTPUT ;
    USE SIGNAL ;
    PORT
      LAYER M4 ;
        RECT  0 117.936 0.084 117.96 ;
    END
  END bank_w[469]
  PIN bank_w[46]
    DIRECTION OUTPUT ;
    USE SIGNAL ;
    PORT
      LAYER M4 ;
        RECT  0 12.144 0.084 12.168 ;
    END
  END bank_w[46]
  PIN bank_w[470]
    DIRECTION OUTPUT ;
    USE SIGNAL ;
    PORT
      LAYER M4 ;
        RECT  0 118.176 0.084 118.2 ;
    END
  END bank_w[470]
  PIN bank_w[471]
    DIRECTION OUTPUT ;
    USE SIGNAL ;
    PORT
      LAYER M4 ;
        RECT  0 118.416 0.084 118.44 ;
    END
  END bank_w[471]
  PIN bank_w[472]
    DIRECTION OUTPUT ;
    USE SIGNAL ;
    PORT
      LAYER M4 ;
        RECT  0 118.656 0.084 118.68 ;
    END
  END bank_w[472]
  PIN bank_w[473]
    DIRECTION OUTPUT ;
    USE SIGNAL ;
    PORT
      LAYER M4 ;
        RECT  0 118.944 0.084 118.968 ;
    END
  END bank_w[473]
  PIN bank_w[474]
    DIRECTION OUTPUT ;
    USE SIGNAL ;
    PORT
      LAYER M4 ;
        RECT  0 119.184 0.084 119.208 ;
    END
  END bank_w[474]
  PIN bank_w[475]
    DIRECTION OUTPUT ;
    USE SIGNAL ;
    PORT
      LAYER M4 ;
        RECT  0 119.424 0.084 119.448 ;
    END
  END bank_w[475]
  PIN bank_w[476]
    DIRECTION OUTPUT ;
    USE SIGNAL ;
    PORT
      LAYER M4 ;
        RECT  0 119.664 0.084 119.688 ;
    END
  END bank_w[476]
  PIN bank_w[477]
    DIRECTION OUTPUT ;
    USE SIGNAL ;
    PORT
      LAYER M4 ;
        RECT  0 119.904 0.084 119.928 ;
    END
  END bank_w[477]
  PIN bank_w[478]
    DIRECTION OUTPUT ;
    USE SIGNAL ;
    PORT
      LAYER M4 ;
        RECT  0 120.192 0.084 120.216 ;
    END
  END bank_w[478]
  PIN bank_w[479]
    DIRECTION OUTPUT ;
    USE SIGNAL ;
    PORT
      LAYER M4 ;
        RECT  0 120.432 0.084 120.456 ;
    END
  END bank_w[479]
  PIN bank_w[47]
    DIRECTION OUTPUT ;
    USE SIGNAL ;
    PORT
      LAYER M4 ;
        RECT  0 12.384 0.084 12.408 ;
    END
  END bank_w[47]
  PIN bank_w[480]
    DIRECTION OUTPUT ;
    USE SIGNAL ;
    PORT
      LAYER M4 ;
        RECT  0 120.672 0.084 120.696 ;
    END
  END bank_w[480]
  PIN bank_w[481]
    DIRECTION OUTPUT ;
    USE SIGNAL ;
    PORT
      LAYER M4 ;
        RECT  0 120.912 0.084 120.936 ;
    END
  END bank_w[481]
  PIN bank_w[482]
    DIRECTION OUTPUT ;
    USE SIGNAL ;
    PORT
      LAYER M4 ;
        RECT  0 121.152 0.084 121.176 ;
    END
  END bank_w[482]
  PIN bank_w[483]
    DIRECTION OUTPUT ;
    USE SIGNAL ;
    PORT
      LAYER M4 ;
        RECT  0 121.44 0.084 121.464 ;
    END
  END bank_w[483]
  PIN bank_w[484]
    DIRECTION OUTPUT ;
    USE SIGNAL ;
    PORT
      LAYER M4 ;
        RECT  0 121.68 0.084 121.704 ;
    END
  END bank_w[484]
  PIN bank_w[485]
    DIRECTION OUTPUT ;
    USE SIGNAL ;
    PORT
      LAYER M4 ;
        RECT  0 121.92 0.084 121.944 ;
    END
  END bank_w[485]
  PIN bank_w[486]
    DIRECTION OUTPUT ;
    USE SIGNAL ;
    PORT
      LAYER M4 ;
        RECT  0 122.16 0.084 122.184 ;
    END
  END bank_w[486]
  PIN bank_w[487]
    DIRECTION OUTPUT ;
    USE SIGNAL ;
    PORT
      LAYER M4 ;
        RECT  0 122.4 0.084 122.424 ;
    END
  END bank_w[487]
  PIN bank_w[488]
    DIRECTION OUTPUT ;
    USE SIGNAL ;
    PORT
      LAYER M4 ;
        RECT  0 122.688 0.084 122.712 ;
    END
  END bank_w[488]
  PIN bank_w[489]
    DIRECTION OUTPUT ;
    USE SIGNAL ;
    PORT
      LAYER M4 ;
        RECT  0 122.928 0.084 122.952 ;
    END
  END bank_w[489]
  PIN bank_w[48]
    DIRECTION OUTPUT ;
    USE SIGNAL ;
    PORT
      LAYER M4 ;
        RECT  0 12.672 0.084 12.696 ;
    END
  END bank_w[48]
  PIN bank_w[490]
    DIRECTION OUTPUT ;
    USE SIGNAL ;
    PORT
      LAYER M4 ;
        RECT  0 123.168 0.084 123.192 ;
    END
  END bank_w[490]
  PIN bank_w[491]
    DIRECTION OUTPUT ;
    USE SIGNAL ;
    PORT
      LAYER M4 ;
        RECT  0 123.408 0.084 123.432 ;
    END
  END bank_w[491]
  PIN bank_w[492]
    DIRECTION OUTPUT ;
    USE SIGNAL ;
    PORT
      LAYER M4 ;
        RECT  0 123.696 0.084 123.72 ;
    END
  END bank_w[492]
  PIN bank_w[493]
    DIRECTION OUTPUT ;
    USE SIGNAL ;
    PORT
      LAYER M4 ;
        RECT  0 123.936 0.084 123.96 ;
    END
  END bank_w[493]
  PIN bank_w[494]
    DIRECTION OUTPUT ;
    USE SIGNAL ;
    PORT
      LAYER M4 ;
        RECT  0 124.176 0.084 124.2 ;
    END
  END bank_w[494]
  PIN bank_w[495]
    DIRECTION OUTPUT ;
    USE SIGNAL ;
    PORT
      LAYER M4 ;
        RECT  0 124.416 0.084 124.44 ;
    END
  END bank_w[495]
  PIN bank_w[496]
    DIRECTION OUTPUT ;
    USE SIGNAL ;
    PORT
      LAYER M4 ;
        RECT  0 124.656 0.084 124.68 ;
    END
  END bank_w[496]
  PIN bank_w[497]
    DIRECTION OUTPUT ;
    USE SIGNAL ;
    PORT
      LAYER M4 ;
        RECT  0 124.944 0.084 124.968 ;
    END
  END bank_w[497]
  PIN bank_w[498]
    DIRECTION OUTPUT ;
    USE SIGNAL ;
    PORT
      LAYER M4 ;
        RECT  0 125.184 0.084 125.208 ;
    END
  END bank_w[498]
  PIN bank_w[499]
    DIRECTION OUTPUT ;
    USE SIGNAL ;
    PORT
      LAYER M4 ;
        RECT  0 125.424 0.084 125.448 ;
    END
  END bank_w[499]
  PIN bank_w[49]
    DIRECTION OUTPUT ;
    USE SIGNAL ;
    PORT
      LAYER M4 ;
        RECT  0 12.912 0.084 12.936 ;
    END
  END bank_w[49]
  PIN bank_w[4]
    DIRECTION OUTPUT ;
    USE SIGNAL ;
    PORT
      LAYER M4 ;
        RECT  0 1.632 0.084 1.656 ;
    END
  END bank_w[4]
  PIN bank_w[500]
    DIRECTION OUTPUT ;
    USE SIGNAL ;
    PORT
      LAYER M4 ;
        RECT  0 125.664 0.084 125.688 ;
    END
  END bank_w[500]
  PIN bank_w[501]
    DIRECTION OUTPUT ;
    USE SIGNAL ;
    PORT
      LAYER M4 ;
        RECT  0 125.904 0.084 125.928 ;
    END
  END bank_w[501]
  PIN bank_w[502]
    DIRECTION OUTPUT ;
    USE SIGNAL ;
    PORT
      LAYER M4 ;
        RECT  0 126.192 0.084 126.216 ;
    END
  END bank_w[502]
  PIN bank_w[503]
    DIRECTION OUTPUT ;
    USE SIGNAL ;
    PORT
      LAYER M4 ;
        RECT  0 126.432 0.084 126.456 ;
    END
  END bank_w[503]
  PIN bank_w[504]
    DIRECTION OUTPUT ;
    USE SIGNAL ;
    PORT
      LAYER M4 ;
        RECT  0 126.672 0.084 126.696 ;
    END
  END bank_w[504]
  PIN bank_w[505]
    DIRECTION OUTPUT ;
    USE SIGNAL ;
    PORT
      LAYER M4 ;
        RECT  0 126.912 0.084 126.936 ;
    END
  END bank_w[505]
  PIN bank_w[506]
    DIRECTION OUTPUT ;
    USE SIGNAL ;
    PORT
      LAYER M4 ;
        RECT  0 127.152 0.084 127.176 ;
    END
  END bank_w[506]
  PIN bank_w[507]
    DIRECTION OUTPUT ;
    USE SIGNAL ;
    PORT
      LAYER M4 ;
        RECT  0 127.44 0.084 127.464 ;
    END
  END bank_w[507]
  PIN bank_w[508]
    DIRECTION OUTPUT ;
    USE SIGNAL ;
    PORT
      LAYER M4 ;
        RECT  0 127.68 0.084 127.704 ;
    END
  END bank_w[508]
  PIN bank_w[509]
    DIRECTION OUTPUT ;
    USE SIGNAL ;
    PORT
      LAYER M4 ;
        RECT  0 127.92 0.084 127.944 ;
    END
  END bank_w[509]
  PIN bank_w[50]
    DIRECTION OUTPUT ;
    USE SIGNAL ;
    PORT
      LAYER M4 ;
        RECT  0 13.152 0.084 13.176 ;
    END
  END bank_w[50]
  PIN bank_w[510]
    DIRECTION OUTPUT ;
    USE SIGNAL ;
    PORT
      LAYER M4 ;
        RECT  0 128.16 0.084 128.184 ;
    END
  END bank_w[510]
  PIN bank_w[511]
    DIRECTION OUTPUT ;
    USE SIGNAL ;
    PORT
      LAYER M4 ;
        RECT  0 128.4 0.084 128.424 ;
    END
  END bank_w[511]
  PIN bank_w[512]
    DIRECTION OUTPUT ;
    USE SIGNAL ;
    PORT
      LAYER M4 ;
        RECT  0 128.688 0.084 128.712 ;
    END
  END bank_w[512]
  PIN bank_w[513]
    DIRECTION OUTPUT ;
    USE SIGNAL ;
    PORT
      LAYER M4 ;
        RECT  0 128.928 0.084 128.952 ;
    END
  END bank_w[513]
  PIN bank_w[51]
    DIRECTION OUTPUT ;
    USE SIGNAL ;
    PORT
      LAYER M4 ;
        RECT  0 13.392 0.084 13.416 ;
    END
  END bank_w[51]
  PIN bank_w[52]
    DIRECTION OUTPUT ;
    USE SIGNAL ;
    PORT
      LAYER M4 ;
        RECT  0 13.632 0.084 13.656 ;
    END
  END bank_w[52]
  PIN bank_w[53]
    DIRECTION OUTPUT ;
    USE SIGNAL ;
    PORT
      LAYER M4 ;
        RECT  0 13.92 0.084 13.944 ;
    END
  END bank_w[53]
  PIN bank_w[54]
    DIRECTION OUTPUT ;
    USE SIGNAL ;
    PORT
      LAYER M4 ;
        RECT  0 14.16 0.084 14.184 ;
    END
  END bank_w[54]
  PIN bank_w[55]
    DIRECTION OUTPUT ;
    USE SIGNAL ;
    PORT
      LAYER M4 ;
        RECT  0 14.4 0.084 14.424 ;
    END
  END bank_w[55]
  PIN bank_w[56]
    DIRECTION OUTPUT ;
    USE SIGNAL ;
    PORT
      LAYER M4 ;
        RECT  0 14.64 0.084 14.664 ;
    END
  END bank_w[56]
  PIN bank_w[57]
    DIRECTION OUTPUT ;
    USE SIGNAL ;
    PORT
      LAYER M4 ;
        RECT  0 14.928 0.084 14.952 ;
    END
  END bank_w[57]
  PIN bank_w[58]
    DIRECTION OUTPUT ;
    USE SIGNAL ;
    PORT
      LAYER M4 ;
        RECT  0 15.168 0.084 15.192 ;
    END
  END bank_w[58]
  PIN bank_w[59]
    DIRECTION OUTPUT ;
    USE SIGNAL ;
    PORT
      LAYER M4 ;
        RECT  0 15.408 0.084 15.432 ;
    END
  END bank_w[59]
  PIN bank_w[5]
    DIRECTION OUTPUT ;
    USE SIGNAL ;
    PORT
      LAYER M4 ;
        RECT  0 1.92 0.084 1.944 ;
    END
  END bank_w[5]
  PIN bank_w[60]
    DIRECTION OUTPUT ;
    USE SIGNAL ;
    PORT
      LAYER M4 ;
        RECT  0 15.648 0.084 15.672 ;
    END
  END bank_w[60]
  PIN bank_w[61]
    DIRECTION OUTPUT ;
    USE SIGNAL ;
    PORT
      LAYER M4 ;
        RECT  0 15.888 0.084 15.912 ;
    END
  END bank_w[61]
  PIN bank_w[62]
    DIRECTION OUTPUT ;
    USE SIGNAL ;
    PORT
      LAYER M4 ;
        RECT  0 16.176 0.084 16.2 ;
    END
  END bank_w[62]
  PIN bank_w[63]
    DIRECTION OUTPUT ;
    USE SIGNAL ;
    PORT
      LAYER M4 ;
        RECT  0 16.416 0.084 16.44 ;
    END
  END bank_w[63]
  PIN bank_w[64]
    DIRECTION OUTPUT ;
    USE SIGNAL ;
    PORT
      LAYER M4 ;
        RECT  0 16.656 0.084 16.68 ;
    END
  END bank_w[64]
  PIN bank_w[65]
    DIRECTION OUTPUT ;
    USE SIGNAL ;
    PORT
      LAYER M4 ;
        RECT  0 16.896 0.084 16.92 ;
    END
  END bank_w[65]
  PIN bank_w[66]
    DIRECTION OUTPUT ;
    USE SIGNAL ;
    PORT
      LAYER M4 ;
        RECT  0 17.136 0.084 17.16 ;
    END
  END bank_w[66]
  PIN bank_w[67]
    DIRECTION OUTPUT ;
    USE SIGNAL ;
    PORT
      LAYER M4 ;
        RECT  0 17.424 0.084 17.448 ;
    END
  END bank_w[67]
  PIN bank_w[68]
    DIRECTION OUTPUT ;
    USE SIGNAL ;
    PORT
      LAYER M4 ;
        RECT  0 17.664 0.084 17.688 ;
    END
  END bank_w[68]
  PIN bank_w[69]
    DIRECTION OUTPUT ;
    USE SIGNAL ;
    PORT
      LAYER M4 ;
        RECT  0 17.904 0.084 17.928 ;
    END
  END bank_w[69]
  PIN bank_w[6]
    DIRECTION OUTPUT ;
    USE SIGNAL ;
    PORT
      LAYER M4 ;
        RECT  0 2.16 0.084 2.184 ;
    END
  END bank_w[6]
  PIN bank_w[70]
    DIRECTION OUTPUT ;
    USE SIGNAL ;
    PORT
      LAYER M4 ;
        RECT  0 18.144 0.084 18.168 ;
    END
  END bank_w[70]
  PIN bank_w[71]
    DIRECTION OUTPUT ;
    USE SIGNAL ;
    PORT
      LAYER M4 ;
        RECT  0 18.384 0.084 18.408 ;
    END
  END bank_w[71]
  PIN bank_w[72]
    DIRECTION OUTPUT ;
    USE SIGNAL ;
    PORT
      LAYER M4 ;
        RECT  0 18.672 0.084 18.696 ;
    END
  END bank_w[72]
  PIN bank_w[73]
    DIRECTION OUTPUT ;
    USE SIGNAL ;
    PORT
      LAYER M4 ;
        RECT  0 18.912 0.084 18.936 ;
    END
  END bank_w[73]
  PIN bank_w[74]
    DIRECTION OUTPUT ;
    USE SIGNAL ;
    PORT
      LAYER M4 ;
        RECT  0 19.152 0.084 19.176 ;
    END
  END bank_w[74]
  PIN bank_w[75]
    DIRECTION OUTPUT ;
    USE SIGNAL ;
    PORT
      LAYER M4 ;
        RECT  0 19.392 0.084 19.416 ;
    END
  END bank_w[75]
  PIN bank_w[76]
    DIRECTION OUTPUT ;
    USE SIGNAL ;
    PORT
      LAYER M4 ;
        RECT  0 19.68 0.084 19.704 ;
    END
  END bank_w[76]
  PIN bank_w[77]
    DIRECTION OUTPUT ;
    USE SIGNAL ;
    PORT
      LAYER M4 ;
        RECT  0 19.92 0.084 19.944 ;
    END
  END bank_w[77]
  PIN bank_w[78]
    DIRECTION OUTPUT ;
    USE SIGNAL ;
    PORT
      LAYER M4 ;
        RECT  0 20.16 0.084 20.184 ;
    END
  END bank_w[78]
  PIN bank_w[79]
    DIRECTION OUTPUT ;
    USE SIGNAL ;
    PORT
      LAYER M4 ;
        RECT  0 20.4 0.084 20.424 ;
    END
  END bank_w[79]
  PIN bank_w[7]
    DIRECTION OUTPUT ;
    USE SIGNAL ;
    PORT
      LAYER M4 ;
        RECT  0 2.4 0.084 2.424 ;
    END
  END bank_w[7]
  PIN bank_w[80]
    DIRECTION OUTPUT ;
    USE SIGNAL ;
    PORT
      LAYER M4 ;
        RECT  0 20.64 0.084 20.664 ;
    END
  END bank_w[80]
  PIN bank_w[81]
    DIRECTION OUTPUT ;
    USE SIGNAL ;
    PORT
      LAYER M4 ;
        RECT  0 20.928 0.084 20.952 ;
    END
  END bank_w[81]
  PIN bank_w[82]
    DIRECTION OUTPUT ;
    USE SIGNAL ;
    PORT
      LAYER M4 ;
        RECT  0 21.168 0.084 21.192 ;
    END
  END bank_w[82]
  PIN bank_w[83]
    DIRECTION OUTPUT ;
    USE SIGNAL ;
    PORT
      LAYER M4 ;
        RECT  0 21.408 0.084 21.432 ;
    END
  END bank_w[83]
  PIN bank_w[84]
    DIRECTION OUTPUT ;
    USE SIGNAL ;
    PORT
      LAYER M4 ;
        RECT  0 21.648 0.084 21.672 ;
    END
  END bank_w[84]
  PIN bank_w[85]
    DIRECTION OUTPUT ;
    USE SIGNAL ;
    PORT
      LAYER M4 ;
        RECT  0 21.888 0.084 21.912 ;
    END
  END bank_w[85]
  PIN bank_w[86]
    DIRECTION OUTPUT ;
    USE SIGNAL ;
    PORT
      LAYER M4 ;
        RECT  0 22.176 0.084 22.2 ;
    END
  END bank_w[86]
  PIN bank_w[87]
    DIRECTION OUTPUT ;
    USE SIGNAL ;
    PORT
      LAYER M4 ;
        RECT  0 22.416 0.084 22.44 ;
    END
  END bank_w[87]
  PIN bank_w[88]
    DIRECTION OUTPUT ;
    USE SIGNAL ;
    PORT
      LAYER M4 ;
        RECT  0 22.656 0.084 22.68 ;
    END
  END bank_w[88]
  PIN bank_w[89]
    DIRECTION OUTPUT ;
    USE SIGNAL ;
    PORT
      LAYER M4 ;
        RECT  0 22.896 0.084 22.92 ;
    END
  END bank_w[89]
  PIN bank_w[8]
    DIRECTION OUTPUT ;
    USE SIGNAL ;
    PORT
      LAYER M4 ;
        RECT  0 2.64 0.084 2.664 ;
    END
  END bank_w[8]
  PIN bank_w[90]
    DIRECTION OUTPUT ;
    USE SIGNAL ;
    PORT
      LAYER M4 ;
        RECT  0 23.136 0.084 23.16 ;
    END
  END bank_w[90]
  PIN bank_w[91]
    DIRECTION OUTPUT ;
    USE SIGNAL ;
    PORT
      LAYER M4 ;
        RECT  0 23.424 0.084 23.448 ;
    END
  END bank_w[91]
  PIN bank_w[92]
    DIRECTION OUTPUT ;
    USE SIGNAL ;
    PORT
      LAYER M4 ;
        RECT  0 23.664 0.084 23.688 ;
    END
  END bank_w[92]
  PIN bank_w[93]
    DIRECTION OUTPUT ;
    USE SIGNAL ;
    PORT
      LAYER M4 ;
        RECT  0 23.904 0.084 23.928 ;
    END
  END bank_w[93]
  PIN bank_w[94]
    DIRECTION OUTPUT ;
    USE SIGNAL ;
    PORT
      LAYER M4 ;
        RECT  0 24.144 0.084 24.168 ;
    END
  END bank_w[94]
  PIN bank_w[95]
    DIRECTION OUTPUT ;
    USE SIGNAL ;
    PORT
      LAYER M4 ;
        RECT  0 24.384 0.084 24.408 ;
    END
  END bank_w[95]
  PIN bank_w[96]
    DIRECTION OUTPUT ;
    USE SIGNAL ;
    PORT
      LAYER M4 ;
        RECT  0 24.672 0.084 24.696 ;
    END
  END bank_w[96]
  PIN bank_w[97]
    DIRECTION OUTPUT ;
    USE SIGNAL ;
    PORT
      LAYER M4 ;
        RECT  0 24.912 0.084 24.936 ;
    END
  END bank_w[97]
  PIN bank_w[98]
    DIRECTION OUTPUT ;
    USE SIGNAL ;
    PORT
      LAYER M4 ;
        RECT  0 25.152 0.084 25.176 ;
    END
  END bank_w[98]
  PIN bank_w[99]
    DIRECTION OUTPUT ;
    USE SIGNAL ;
    PORT
      LAYER M4 ;
        RECT  0 25.392 0.084 25.416 ;
    END
  END bank_w[99]
  PIN bank_w[9]
    DIRECTION OUTPUT ;
    USE SIGNAL ;
    PORT
      LAYER M4 ;
        RECT  0 2.88 0.084 2.904 ;
    END
  END bank_w[9]
  PIN ck
    DIRECTION INPUT ;
    USE SIGNAL ;
    PORT
      LAYER M3 ;
        RECT  29.7 0 29.718 0.038 ;
    END
  END ck
  PIN i[0]
    DIRECTION INPUT ;
    USE SIGNAL ;
    PORT
      LAYER M3 ;
        RECT  0.648 129.562 0.666 129.6 ;
    END
  END i[0]
  PIN i[100]
    DIRECTION INPUT ;
    USE SIGNAL ;
    PORT
      LAYER M3 ;
        RECT  25.452 129.562 25.47 129.6 ;
    END
  END i[100]
  PIN i[101]
    DIRECTION INPUT ;
    USE SIGNAL ;
    PORT
      LAYER M5 ;
        RECT  25.68 129.516 25.704 129.6 ;
    END
  END i[101]
  PIN i[102]
    DIRECTION INPUT ;
    USE SIGNAL ;
    PORT
      LAYER M3 ;
        RECT  25.956 129.562 25.974 129.6 ;
    END
  END i[102]
  PIN i[103]
    DIRECTION INPUT ;
    USE SIGNAL ;
    PORT
      LAYER M5 ;
        RECT  26.208 129.516 26.232 129.6 ;
    END
  END i[103]
  PIN i[104]
    DIRECTION INPUT ;
    USE SIGNAL ;
    PORT
      LAYER M3 ;
        RECT  26.424 129.562 26.442 129.6 ;
    END
  END i[104]
  PIN i[105]
    DIRECTION INPUT ;
    USE SIGNAL ;
    PORT
      LAYER M5 ;
        RECT  26.688 129.516 26.712 129.6 ;
    END
  END i[105]
  PIN i[106]
    DIRECTION INPUT ;
    USE SIGNAL ;
    PORT
      LAYER M3 ;
        RECT  26.928 129.562 26.946 129.6 ;
    END
  END i[106]
  PIN i[107]
    DIRECTION INPUT ;
    USE SIGNAL ;
    PORT
      LAYER M5 ;
        RECT  27.168 129.516 27.192 129.6 ;
    END
  END i[107]
  PIN i[108]
    DIRECTION INPUT ;
    USE SIGNAL ;
    PORT
      LAYER M3 ;
        RECT  27.432 129.562 27.45 129.6 ;
    END
  END i[108]
  PIN i[109]
    DIRECTION INPUT ;
    USE SIGNAL ;
    PORT
      LAYER M5 ;
        RECT  27.696 129.516 27.72 129.6 ;
    END
  END i[109]
  PIN i[10]
    DIRECTION INPUT ;
    USE SIGNAL ;
    PORT
      LAYER M3 ;
        RECT  3.132 129.562 3.15 129.6 ;
    END
  END i[10]
  PIN i[110]
    DIRECTION INPUT ;
    USE SIGNAL ;
    PORT
      LAYER M3 ;
        RECT  27.936 129.562 27.954 129.6 ;
    END
  END i[110]
  PIN i[111]
    DIRECTION INPUT ;
    USE SIGNAL ;
    PORT
      LAYER M5 ;
        RECT  28.176 129.516 28.2 129.6 ;
    END
  END i[111]
  PIN i[112]
    DIRECTION INPUT ;
    USE SIGNAL ;
    PORT
      LAYER M3 ;
        RECT  28.44 129.562 28.458 129.6 ;
    END
  END i[112]
  PIN i[113]
    DIRECTION INPUT ;
    USE SIGNAL ;
    PORT
      LAYER M5 ;
        RECT  28.656 129.516 28.68 129.6 ;
    END
  END i[113]
  PIN i[114]
    DIRECTION INPUT ;
    USE SIGNAL ;
    PORT
      LAYER M3 ;
        RECT  28.908 129.562 28.926 129.6 ;
    END
  END i[114]
  PIN i[115]
    DIRECTION INPUT ;
    USE SIGNAL ;
    PORT
      LAYER M5 ;
        RECT  29.184 129.516 29.208 129.6 ;
    END
  END i[115]
  PIN i[116]
    DIRECTION INPUT ;
    USE SIGNAL ;
    PORT
      LAYER M3 ;
        RECT  29.412 129.562 29.43 129.6 ;
    END
  END i[116]
  PIN i[117]
    DIRECTION INPUT ;
    USE SIGNAL ;
    PORT
      LAYER M5 ;
        RECT  29.664 129.516 29.688 129.6 ;
    END
  END i[117]
  PIN i[118]
    DIRECTION INPUT ;
    USE SIGNAL ;
    PORT
      LAYER M3 ;
        RECT  29.916 129.562 29.934 129.6 ;
    END
  END i[118]
  PIN i[119]
    DIRECTION INPUT ;
    USE SIGNAL ;
    PORT
      LAYER M5 ;
        RECT  30.144 129.516 30.168 129.6 ;
    END
  END i[119]
  PIN i[11]
    DIRECTION INPUT ;
    USE SIGNAL ;
    PORT
      LAYER M5 ;
        RECT  3.36 129.516 3.384 129.6 ;
    END
  END i[11]
  PIN i[120]
    DIRECTION INPUT ;
    USE SIGNAL ;
    PORT
      LAYER M3 ;
        RECT  30.42 129.562 30.438 129.6 ;
    END
  END i[120]
  PIN i[121]
    DIRECTION INPUT ;
    USE SIGNAL ;
    PORT
      LAYER M5 ;
        RECT  30.672 129.516 30.696 129.6 ;
    END
  END i[121]
  PIN i[122]
    DIRECTION INPUT ;
    USE SIGNAL ;
    PORT
      LAYER M3 ;
        RECT  30.888 129.562 30.906 129.6 ;
    END
  END i[122]
  PIN i[123]
    DIRECTION INPUT ;
    USE SIGNAL ;
    PORT
      LAYER M5 ;
        RECT  31.152 129.516 31.176 129.6 ;
    END
  END i[123]
  PIN i[124]
    DIRECTION INPUT ;
    USE SIGNAL ;
    PORT
      LAYER M3 ;
        RECT  31.392 129.562 31.41 129.6 ;
    END
  END i[124]
  PIN i[125]
    DIRECTION INPUT ;
    USE SIGNAL ;
    PORT
      LAYER M5 ;
        RECT  31.632 129.516 31.656 129.6 ;
    END
  END i[125]
  PIN i[126]
    DIRECTION INPUT ;
    USE SIGNAL ;
    PORT
      LAYER M3 ;
        RECT  31.896 129.562 31.914 129.6 ;
    END
  END i[126]
  PIN i[127]
    DIRECTION INPUT ;
    USE SIGNAL ;
    PORT
      LAYER M5 ;
        RECT  32.16 129.516 32.184 129.6 ;
    END
  END i[127]
  PIN i[128]
    DIRECTION INPUT ;
    USE SIGNAL ;
    PORT
      LAYER M3 ;
        RECT  32.4 129.562 32.418 129.6 ;
    END
  END i[128]
  PIN i[129]
    DIRECTION INPUT ;
    USE SIGNAL ;
    PORT
      LAYER M5 ;
        RECT  32.64 129.516 32.664 129.6 ;
    END
  END i[129]
  PIN i[12]
    DIRECTION INPUT ;
    USE SIGNAL ;
    PORT
      LAYER M3 ;
        RECT  3.636 129.562 3.654 129.6 ;
    END
  END i[12]
  PIN i[130]
    DIRECTION INPUT ;
    USE SIGNAL ;
    PORT
      LAYER M3 ;
        RECT  32.904 129.562 32.922 129.6 ;
    END
  END i[130]
  PIN i[131]
    DIRECTION INPUT ;
    USE SIGNAL ;
    PORT
      LAYER M5 ;
        RECT  33.12 129.516 33.144 129.6 ;
    END
  END i[131]
  PIN i[132]
    DIRECTION INPUT ;
    USE SIGNAL ;
    PORT
      LAYER M3 ;
        RECT  33.372 129.562 33.39 129.6 ;
    END
  END i[132]
  PIN i[133]
    DIRECTION INPUT ;
    USE SIGNAL ;
    PORT
      LAYER M5 ;
        RECT  33.648 129.516 33.672 129.6 ;
    END
  END i[133]
  PIN i[134]
    DIRECTION INPUT ;
    USE SIGNAL ;
    PORT
      LAYER M3 ;
        RECT  33.876 129.562 33.894 129.6 ;
    END
  END i[134]
  PIN i[135]
    DIRECTION INPUT ;
    USE SIGNAL ;
    PORT
      LAYER M5 ;
        RECT  34.128 129.516 34.152 129.6 ;
    END
  END i[135]
  PIN i[136]
    DIRECTION INPUT ;
    USE SIGNAL ;
    PORT
      LAYER M3 ;
        RECT  34.38 129.562 34.398 129.6 ;
    END
  END i[136]
  PIN i[137]
    DIRECTION INPUT ;
    USE SIGNAL ;
    PORT
      LAYER M5 ;
        RECT  34.608 129.516 34.632 129.6 ;
    END
  END i[137]
  PIN i[138]
    DIRECTION INPUT ;
    USE SIGNAL ;
    PORT
      LAYER M3 ;
        RECT  34.884 129.562 34.902 129.6 ;
    END
  END i[138]
  PIN i[139]
    DIRECTION INPUT ;
    USE SIGNAL ;
    PORT
      LAYER M5 ;
        RECT  35.136 129.516 35.16 129.6 ;
    END
  END i[139]
  PIN i[13]
    DIRECTION INPUT ;
    USE SIGNAL ;
    PORT
      LAYER M5 ;
        RECT  3.888 129.516 3.912 129.6 ;
    END
  END i[13]
  PIN i[140]
    DIRECTION INPUT ;
    USE SIGNAL ;
    PORT
      LAYER M3 ;
        RECT  35.352 129.562 35.37 129.6 ;
    END
  END i[140]
  PIN i[141]
    DIRECTION INPUT ;
    USE SIGNAL ;
    PORT
      LAYER M5 ;
        RECT  35.616 129.516 35.64 129.6 ;
    END
  END i[141]
  PIN i[142]
    DIRECTION INPUT ;
    USE SIGNAL ;
    PORT
      LAYER M3 ;
        RECT  35.856 129.562 35.874 129.6 ;
    END
  END i[142]
  PIN i[143]
    DIRECTION INPUT ;
    USE SIGNAL ;
    PORT
      LAYER M5 ;
        RECT  36.096 129.516 36.12 129.6 ;
    END
  END i[143]
  PIN i[144]
    DIRECTION INPUT ;
    USE SIGNAL ;
    PORT
      LAYER M3 ;
        RECT  36.36 129.562 36.378 129.6 ;
    END
  END i[144]
  PIN i[145]
    DIRECTION INPUT ;
    USE SIGNAL ;
    PORT
      LAYER M5 ;
        RECT  36.624 129.516 36.648 129.6 ;
    END
  END i[145]
  PIN i[146]
    DIRECTION INPUT ;
    USE SIGNAL ;
    PORT
      LAYER M3 ;
        RECT  36.864 129.562 36.882 129.6 ;
    END
  END i[146]
  PIN i[147]
    DIRECTION INPUT ;
    USE SIGNAL ;
    PORT
      LAYER M5 ;
        RECT  37.104 129.516 37.128 129.6 ;
    END
  END i[147]
  PIN i[148]
    DIRECTION INPUT ;
    USE SIGNAL ;
    PORT
      LAYER M3 ;
        RECT  37.368 129.562 37.386 129.6 ;
    END
  END i[148]
  PIN i[149]
    DIRECTION INPUT ;
    USE SIGNAL ;
    PORT
      LAYER M5 ;
        RECT  37.584 129.516 37.608 129.6 ;
    END
  END i[149]
  PIN i[14]
    DIRECTION INPUT ;
    USE SIGNAL ;
    PORT
      LAYER M3 ;
        RECT  4.14 129.562 4.158 129.6 ;
    END
  END i[14]
  PIN i[150]
    DIRECTION INPUT ;
    USE SIGNAL ;
    PORT
      LAYER M3 ;
        RECT  37.836 129.562 37.854 129.6 ;
    END
  END i[150]
  PIN i[151]
    DIRECTION INPUT ;
    USE SIGNAL ;
    PORT
      LAYER M5 ;
        RECT  38.112 129.516 38.136 129.6 ;
    END
  END i[151]
  PIN i[152]
    DIRECTION INPUT ;
    USE SIGNAL ;
    PORT
      LAYER M3 ;
        RECT  38.34 129.562 38.358 129.6 ;
    END
  END i[152]
  PIN i[153]
    DIRECTION INPUT ;
    USE SIGNAL ;
    PORT
      LAYER M5 ;
        RECT  38.592 129.516 38.616 129.6 ;
    END
  END i[153]
  PIN i[154]
    DIRECTION INPUT ;
    USE SIGNAL ;
    PORT
      LAYER M3 ;
        RECT  38.844 129.562 38.862 129.6 ;
    END
  END i[154]
  PIN i[155]
    DIRECTION INPUT ;
    USE SIGNAL ;
    PORT
      LAYER M5 ;
        RECT  39.072 129.516 39.096 129.6 ;
    END
  END i[155]
  PIN i[156]
    DIRECTION INPUT ;
    USE SIGNAL ;
    PORT
      LAYER M3 ;
        RECT  39.348 129.562 39.366 129.6 ;
    END
  END i[156]
  PIN i[157]
    DIRECTION INPUT ;
    USE SIGNAL ;
    PORT
      LAYER M5 ;
        RECT  39.6 129.516 39.624 129.6 ;
    END
  END i[157]
  PIN i[158]
    DIRECTION INPUT ;
    USE SIGNAL ;
    PORT
      LAYER M3 ;
        RECT  39.816 129.562 39.834 129.6 ;
    END
  END i[158]
  PIN i[159]
    DIRECTION INPUT ;
    USE SIGNAL ;
    PORT
      LAYER M5 ;
        RECT  40.08 129.516 40.104 129.6 ;
    END
  END i[159]
  PIN i[15]
    DIRECTION INPUT ;
    USE SIGNAL ;
    PORT
      LAYER M5 ;
        RECT  4.368 129.516 4.392 129.6 ;
    END
  END i[15]
  PIN i[160]
    DIRECTION INPUT ;
    USE SIGNAL ;
    PORT
      LAYER M3 ;
        RECT  40.32 129.562 40.338 129.6 ;
    END
  END i[160]
  PIN i[161]
    DIRECTION INPUT ;
    USE SIGNAL ;
    PORT
      LAYER M5 ;
        RECT  40.56 129.516 40.584 129.6 ;
    END
  END i[161]
  PIN i[162]
    DIRECTION INPUT ;
    USE SIGNAL ;
    PORT
      LAYER M3 ;
        RECT  40.824 129.562 40.842 129.6 ;
    END
  END i[162]
  PIN i[163]
    DIRECTION INPUT ;
    USE SIGNAL ;
    PORT
      LAYER M5 ;
        RECT  41.088 129.516 41.112 129.6 ;
    END
  END i[163]
  PIN i[164]
    DIRECTION INPUT ;
    USE SIGNAL ;
    PORT
      LAYER M3 ;
        RECT  41.328 129.562 41.346 129.6 ;
    END
  END i[164]
  PIN i[165]
    DIRECTION INPUT ;
    USE SIGNAL ;
    PORT
      LAYER M5 ;
        RECT  41.568 129.516 41.592 129.6 ;
    END
  END i[165]
  PIN i[166]
    DIRECTION INPUT ;
    USE SIGNAL ;
    PORT
      LAYER M3 ;
        RECT  41.796 129.562 41.814 129.6 ;
    END
  END i[166]
  PIN i[167]
    DIRECTION INPUT ;
    USE SIGNAL ;
    PORT
      LAYER M5 ;
        RECT  42.048 129.516 42.072 129.6 ;
    END
  END i[167]
  PIN i[168]
    DIRECTION INPUT ;
    USE SIGNAL ;
    PORT
      LAYER M3 ;
        RECT  42.3 129.562 42.318 129.6 ;
    END
  END i[168]
  PIN i[169]
    DIRECTION INPUT ;
    USE SIGNAL ;
    PORT
      LAYER M5 ;
        RECT  42.576 129.516 42.6 129.6 ;
    END
  END i[169]
  PIN i[16]
    DIRECTION INPUT ;
    USE SIGNAL ;
    PORT
      LAYER M3 ;
        RECT  4.608 129.562 4.626 129.6 ;
    END
  END i[16]
  PIN i[170]
    DIRECTION INPUT ;
    USE SIGNAL ;
    PORT
      LAYER M3 ;
        RECT  42.804 129.562 42.822 129.6 ;
    END
  END i[170]
  PIN i[171]
    DIRECTION INPUT ;
    USE SIGNAL ;
    PORT
      LAYER M5 ;
        RECT  43.056 129.516 43.08 129.6 ;
    END
  END i[171]
  PIN i[172]
    DIRECTION INPUT ;
    USE SIGNAL ;
    PORT
      LAYER M3 ;
        RECT  43.308 129.562 43.326 129.6 ;
    END
  END i[172]
  PIN i[173]
    DIRECTION INPUT ;
    USE SIGNAL ;
    PORT
      LAYER M5 ;
        RECT  43.536 129.516 43.56 129.6 ;
    END
  END i[173]
  PIN i[174]
    DIRECTION INPUT ;
    USE SIGNAL ;
    PORT
      LAYER M3 ;
        RECT  43.812 129.562 43.83 129.6 ;
    END
  END i[174]
  PIN i[175]
    DIRECTION INPUT ;
    USE SIGNAL ;
    PORT
      LAYER M5 ;
        RECT  44.064 129.516 44.088 129.6 ;
    END
  END i[175]
  PIN i[176]
    DIRECTION INPUT ;
    USE SIGNAL ;
    PORT
      LAYER M3 ;
        RECT  44.28 129.562 44.298 129.6 ;
    END
  END i[176]
  PIN i[177]
    DIRECTION INPUT ;
    USE SIGNAL ;
    PORT
      LAYER M5 ;
        RECT  44.544 129.516 44.568 129.6 ;
    END
  END i[177]
  PIN i[178]
    DIRECTION INPUT ;
    USE SIGNAL ;
    PORT
      LAYER M3 ;
        RECT  44.784 129.562 44.802 129.6 ;
    END
  END i[178]
  PIN i[179]
    DIRECTION INPUT ;
    USE SIGNAL ;
    PORT
      LAYER M5 ;
        RECT  45.024 129.516 45.048 129.6 ;
    END
  END i[179]
  PIN i[17]
    DIRECTION INPUT ;
    USE SIGNAL ;
    PORT
      LAYER M5 ;
        RECT  4.848 129.516 4.872 129.6 ;
    END
  END i[17]
  PIN i[180]
    DIRECTION INPUT ;
    USE SIGNAL ;
    PORT
      LAYER M3 ;
        RECT  45.288 129.562 45.306 129.6 ;
    END
  END i[180]
  PIN i[181]
    DIRECTION INPUT ;
    USE SIGNAL ;
    PORT
      LAYER M5 ;
        RECT  45.552 129.516 45.576 129.6 ;
    END
  END i[181]
  PIN i[182]
    DIRECTION INPUT ;
    USE SIGNAL ;
    PORT
      LAYER M3 ;
        RECT  45.792 129.562 45.81 129.6 ;
    END
  END i[182]
  PIN i[183]
    DIRECTION INPUT ;
    USE SIGNAL ;
    PORT
      LAYER M5 ;
        RECT  46.032 129.516 46.056 129.6 ;
    END
  END i[183]
  PIN i[184]
    DIRECTION INPUT ;
    USE SIGNAL ;
    PORT
      LAYER M3 ;
        RECT  46.26 129.562 46.278 129.6 ;
    END
  END i[184]
  PIN i[185]
    DIRECTION INPUT ;
    USE SIGNAL ;
    PORT
      LAYER M5 ;
        RECT  46.512 129.516 46.536 129.6 ;
    END
  END i[185]
  PIN i[186]
    DIRECTION INPUT ;
    USE SIGNAL ;
    PORT
      LAYER M3 ;
        RECT  46.764 129.562 46.782 129.6 ;
    END
  END i[186]
  PIN i[187]
    DIRECTION INPUT ;
    USE SIGNAL ;
    PORT
      LAYER M5 ;
        RECT  47.04 129.516 47.064 129.6 ;
    END
  END i[187]
  PIN i[188]
    DIRECTION INPUT ;
    USE SIGNAL ;
    PORT
      LAYER M3 ;
        RECT  47.268 129.562 47.286 129.6 ;
    END
  END i[188]
  PIN i[189]
    DIRECTION INPUT ;
    USE SIGNAL ;
    PORT
      LAYER M5 ;
        RECT  47.52 129.516 47.544 129.6 ;
    END
  END i[189]
  PIN i[18]
    DIRECTION INPUT ;
    USE SIGNAL ;
    PORT
      LAYER M3 ;
        RECT  5.112 129.562 5.13 129.6 ;
    END
  END i[18]
  PIN i[190]
    DIRECTION INPUT ;
    USE SIGNAL ;
    PORT
      LAYER M3 ;
        RECT  47.772 129.562 47.79 129.6 ;
    END
  END i[190]
  PIN i[191]
    DIRECTION INPUT ;
    USE SIGNAL ;
    PORT
      LAYER M5 ;
        RECT  48 129.516 48.024 129.6 ;
    END
  END i[191]
  PIN i[192]
    DIRECTION INPUT ;
    USE SIGNAL ;
    PORT
      LAYER M3 ;
        RECT  48.276 129.562 48.294 129.6 ;
    END
  END i[192]
  PIN i[193]
    DIRECTION INPUT ;
    USE SIGNAL ;
    PORT
      LAYER M5 ;
        RECT  48.528 129.516 48.552 129.6 ;
    END
  END i[193]
  PIN i[194]
    DIRECTION INPUT ;
    USE SIGNAL ;
    PORT
      LAYER M3 ;
        RECT  48.744 129.562 48.762 129.6 ;
    END
  END i[194]
  PIN i[195]
    DIRECTION INPUT ;
    USE SIGNAL ;
    PORT
      LAYER M5 ;
        RECT  49.008 129.516 49.032 129.6 ;
    END
  END i[195]
  PIN i[196]
    DIRECTION INPUT ;
    USE SIGNAL ;
    PORT
      LAYER M3 ;
        RECT  49.248 129.562 49.266 129.6 ;
    END
  END i[196]
  PIN i[197]
    DIRECTION INPUT ;
    USE SIGNAL ;
    PORT
      LAYER M5 ;
        RECT  49.488 129.516 49.512 129.6 ;
    END
  END i[197]
  PIN i[198]
    DIRECTION INPUT ;
    USE SIGNAL ;
    PORT
      LAYER M3 ;
        RECT  49.752 129.562 49.77 129.6 ;
    END
  END i[198]
  PIN i[199]
    DIRECTION INPUT ;
    USE SIGNAL ;
    PORT
      LAYER M5 ;
        RECT  50.016 129.516 50.04 129.6 ;
    END
  END i[199]
  PIN i[19]
    DIRECTION INPUT ;
    USE SIGNAL ;
    PORT
      LAYER M5 ;
        RECT  5.376 129.516 5.4 129.6 ;
    END
  END i[19]
  PIN i[1]
    DIRECTION INPUT ;
    USE SIGNAL ;
    PORT
      LAYER M5 ;
        RECT  0.912 129.516 0.936 129.6 ;
    END
  END i[1]
  PIN i[200]
    DIRECTION INPUT ;
    USE SIGNAL ;
    PORT
      LAYER M3 ;
        RECT  50.256 129.562 50.274 129.6 ;
    END
  END i[200]
  PIN i[201]
    DIRECTION INPUT ;
    USE SIGNAL ;
    PORT
      LAYER M5 ;
        RECT  50.496 129.516 50.52 129.6 ;
    END
  END i[201]
  PIN i[202]
    DIRECTION INPUT ;
    USE SIGNAL ;
    PORT
      LAYER M3 ;
        RECT  50.724 129.562 50.742 129.6 ;
    END
  END i[202]
  PIN i[203]
    DIRECTION INPUT ;
    USE SIGNAL ;
    PORT
      LAYER M5 ;
        RECT  50.976 129.516 51 129.6 ;
    END
  END i[203]
  PIN i[204]
    DIRECTION INPUT ;
    USE SIGNAL ;
    PORT
      LAYER M3 ;
        RECT  51.228 129.562 51.246 129.6 ;
    END
  END i[204]
  PIN i[205]
    DIRECTION INPUT ;
    USE SIGNAL ;
    PORT
      LAYER M5 ;
        RECT  51.456 129.516 51.48 129.6 ;
    END
  END i[205]
  PIN i[206]
    DIRECTION INPUT ;
    USE SIGNAL ;
    PORT
      LAYER M3 ;
        RECT  51.732 129.562 51.75 129.6 ;
    END
  END i[206]
  PIN i[207]
    DIRECTION INPUT ;
    USE SIGNAL ;
    PORT
      LAYER M5 ;
        RECT  51.984 129.516 52.008 129.6 ;
    END
  END i[207]
  PIN i[208]
    DIRECTION INPUT ;
    USE SIGNAL ;
    PORT
      LAYER M3 ;
        RECT  52.236 129.562 52.254 129.6 ;
    END
  END i[208]
  PIN i[209]
    DIRECTION INPUT ;
    USE SIGNAL ;
    PORT
      LAYER M5 ;
        RECT  52.464 129.516 52.488 129.6 ;
    END
  END i[209]
  PIN i[20]
    DIRECTION INPUT ;
    USE SIGNAL ;
    PORT
      LAYER M3 ;
        RECT  5.616 129.562 5.634 129.6 ;
    END
  END i[20]
  PIN i[210]
    DIRECTION INPUT ;
    USE SIGNAL ;
    PORT
      LAYER M3 ;
        RECT  52.74 129.562 52.758 129.6 ;
    END
  END i[210]
  PIN i[211]
    DIRECTION INPUT ;
    USE SIGNAL ;
    PORT
      LAYER M5 ;
        RECT  52.944 129.516 52.968 129.6 ;
    END
  END i[211]
  PIN i[212]
    DIRECTION INPUT ;
    USE SIGNAL ;
    PORT
      LAYER M3 ;
        RECT  53.208 129.562 53.226 129.6 ;
    END
  END i[212]
  PIN i[213]
    DIRECTION INPUT ;
    USE SIGNAL ;
    PORT
      LAYER M5 ;
        RECT  53.472 129.516 53.496 129.6 ;
    END
  END i[213]
  PIN i[214]
    DIRECTION INPUT ;
    USE SIGNAL ;
    PORT
      LAYER M3 ;
        RECT  53.712 129.562 53.73 129.6 ;
    END
  END i[214]
  PIN i[215]
    DIRECTION INPUT ;
    USE SIGNAL ;
    PORT
      LAYER M5 ;
        RECT  53.952 129.516 53.976 129.6 ;
    END
  END i[215]
  PIN i[216]
    DIRECTION INPUT ;
    USE SIGNAL ;
    PORT
      LAYER M3 ;
        RECT  54.216 129.562 54.234 129.6 ;
    END
  END i[216]
  PIN i[217]
    DIRECTION INPUT ;
    USE SIGNAL ;
    PORT
      LAYER M5 ;
        RECT  54.432 129.516 54.456 129.6 ;
    END
  END i[217]
  PIN i[218]
    DIRECTION INPUT ;
    USE SIGNAL ;
    PORT
      LAYER M3 ;
        RECT  54.72 129.562 54.738 129.6 ;
    END
  END i[218]
  PIN i[219]
    DIRECTION INPUT ;
    USE SIGNAL ;
    PORT
      LAYER M5 ;
        RECT  54.96 129.516 54.984 129.6 ;
    END
  END i[219]
  PIN i[21]
    DIRECTION INPUT ;
    USE SIGNAL ;
    PORT
      LAYER M5 ;
        RECT  5.856 129.516 5.88 129.6 ;
    END
  END i[21]
  PIN i[220]
    DIRECTION INPUT ;
    USE SIGNAL ;
    PORT
      LAYER M3 ;
        RECT  55.188 129.562 55.206 129.6 ;
    END
  END i[220]
  PIN i[221]
    DIRECTION INPUT ;
    USE SIGNAL ;
    PORT
      LAYER M5 ;
        RECT  55.44 129.516 55.464 129.6 ;
    END
  END i[221]
  PIN i[222]
    DIRECTION INPUT ;
    USE SIGNAL ;
    PORT
      LAYER M3 ;
        RECT  55.692 129.562 55.71 129.6 ;
    END
  END i[222]
  PIN i[223]
    DIRECTION INPUT ;
    USE SIGNAL ;
    PORT
      LAYER M5 ;
        RECT  55.92 129.516 55.944 129.6 ;
    END
  END i[223]
  PIN i[224]
    DIRECTION INPUT ;
    USE SIGNAL ;
    PORT
      LAYER M3 ;
        RECT  56.196 129.562 56.214 129.6 ;
    END
  END i[224]
  PIN i[225]
    DIRECTION INPUT ;
    USE SIGNAL ;
    PORT
      LAYER M5 ;
        RECT  56.448 129.516 56.472 129.6 ;
    END
  END i[225]
  PIN i[226]
    DIRECTION INPUT ;
    USE SIGNAL ;
    PORT
      LAYER M3 ;
        RECT  56.7 129.562 56.718 129.6 ;
    END
  END i[226]
  PIN i[227]
    DIRECTION INPUT ;
    USE SIGNAL ;
    PORT
      LAYER M5 ;
        RECT  56.928 129.516 56.952 129.6 ;
    END
  END i[227]
  PIN i[228]
    DIRECTION INPUT ;
    USE SIGNAL ;
    PORT
      LAYER M3 ;
        RECT  57.168 129.562 57.186 129.6 ;
    END
  END i[228]
  PIN i[229]
    DIRECTION INPUT ;
    USE SIGNAL ;
    PORT
      LAYER M5 ;
        RECT  57.408 129.516 57.432 129.6 ;
    END
  END i[229]
  PIN i[22]
    DIRECTION INPUT ;
    USE SIGNAL ;
    PORT
      LAYER M3 ;
        RECT  6.12 129.562 6.138 129.6 ;
    END
  END i[22]
  PIN i[230]
    DIRECTION INPUT ;
    USE SIGNAL ;
    PORT
      LAYER M3 ;
        RECT  57.672 129.562 57.69 129.6 ;
    END
  END i[230]
  PIN i[231]
    DIRECTION INPUT ;
    USE SIGNAL ;
    PORT
      LAYER M5 ;
        RECT  57.936 129.516 57.96 129.6 ;
    END
  END i[231]
  PIN i[232]
    DIRECTION INPUT ;
    USE SIGNAL ;
    PORT
      LAYER M3 ;
        RECT  58.176 129.562 58.194 129.6 ;
    END
  END i[232]
  PIN i[233]
    DIRECTION INPUT ;
    USE SIGNAL ;
    PORT
      LAYER M5 ;
        RECT  58.416 129.516 58.44 129.6 ;
    END
  END i[233]
  PIN i[234]
    DIRECTION INPUT ;
    USE SIGNAL ;
    PORT
      LAYER M3 ;
        RECT  58.68 129.562 58.698 129.6 ;
    END
  END i[234]
  PIN i[235]
    DIRECTION INPUT ;
    USE SIGNAL ;
    PORT
      LAYER M5 ;
        RECT  58.896 129.516 58.92 129.6 ;
    END
  END i[235]
  PIN i[236]
    DIRECTION INPUT ;
    USE SIGNAL ;
    PORT
      LAYER M3 ;
        RECT  59.184 129.562 59.202 129.6 ;
    END
  END i[236]
  PIN i[237]
    DIRECTION INPUT ;
    USE SIGNAL ;
    PORT
      LAYER M5 ;
        RECT  59.424 129.516 59.448 129.6 ;
    END
  END i[237]
  PIN i[238]
    DIRECTION INPUT ;
    USE SIGNAL ;
    PORT
      LAYER M3 ;
        RECT  59.652 129.562 59.67 129.6 ;
    END
  END i[238]
  PIN i[239]
    DIRECTION INPUT ;
    USE SIGNAL ;
    PORT
      LAYER M5 ;
        RECT  59.904 129.516 59.928 129.6 ;
    END
  END i[239]
  PIN i[23]
    DIRECTION INPUT ;
    USE SIGNAL ;
    PORT
      LAYER M5 ;
        RECT  6.336 129.516 6.36 129.6 ;
    END
  END i[23]
  PIN i[240]
    DIRECTION INPUT ;
    USE SIGNAL ;
    PORT
      LAYER M3 ;
        RECT  60.156 129.562 60.174 129.6 ;
    END
  END i[240]
  PIN i[241]
    DIRECTION INPUT ;
    USE SIGNAL ;
    PORT
      LAYER M5 ;
        RECT  60.384 129.516 60.408 129.6 ;
    END
  END i[241]
  PIN i[242]
    DIRECTION INPUT ;
    USE SIGNAL ;
    PORT
      LAYER M3 ;
        RECT  60.66 129.562 60.678 129.6 ;
    END
  END i[242]
  PIN i[243]
    DIRECTION INPUT ;
    USE SIGNAL ;
    PORT
      LAYER M5 ;
        RECT  60.912 129.516 60.936 129.6 ;
    END
  END i[243]
  PIN i[244]
    DIRECTION INPUT ;
    USE SIGNAL ;
    PORT
      LAYER M3 ;
        RECT  61.164 129.562 61.182 129.6 ;
    END
  END i[244]
  PIN i[245]
    DIRECTION INPUT ;
    USE SIGNAL ;
    PORT
      LAYER M5 ;
        RECT  61.392 129.516 61.416 129.6 ;
    END
  END i[245]
  PIN i[246]
    DIRECTION INPUT ;
    USE SIGNAL ;
    PORT
      LAYER M3 ;
        RECT  61.632 129.562 61.65 129.6 ;
    END
  END i[246]
  PIN i[247]
    DIRECTION INPUT ;
    USE SIGNAL ;
    PORT
      LAYER M5 ;
        RECT  61.872 129.516 61.896 129.6 ;
    END
  END i[247]
  PIN i[248]
    DIRECTION INPUT ;
    USE SIGNAL ;
    PORT
      LAYER M3 ;
        RECT  62.136 129.562 62.154 129.6 ;
    END
  END i[248]
  PIN i[249]
    DIRECTION INPUT ;
    USE SIGNAL ;
    PORT
      LAYER M5 ;
        RECT  62.4 129.516 62.424 129.6 ;
    END
  END i[249]
  PIN i[24]
    DIRECTION INPUT ;
    USE SIGNAL ;
    PORT
      LAYER M3 ;
        RECT  6.588 129.562 6.606 129.6 ;
    END
  END i[24]
  PIN i[250]
    DIRECTION INPUT ;
    USE SIGNAL ;
    PORT
      LAYER M3 ;
        RECT  62.64 129.562 62.658 129.6 ;
    END
  END i[250]
  PIN i[251]
    DIRECTION INPUT ;
    USE SIGNAL ;
    PORT
      LAYER M5 ;
        RECT  62.88 129.516 62.904 129.6 ;
    END
  END i[251]
  PIN i[252]
    DIRECTION INPUT ;
    USE SIGNAL ;
    PORT
      LAYER M3 ;
        RECT  63.144 129.562 63.162 129.6 ;
    END
  END i[252]
  PIN i[253]
    DIRECTION INPUT ;
    USE SIGNAL ;
    PORT
      LAYER M5 ;
        RECT  63.36 129.516 63.384 129.6 ;
    END
  END i[253]
  PIN i[254]
    DIRECTION INPUT ;
    USE SIGNAL ;
    PORT
      LAYER M3 ;
        RECT  63.648 129.562 63.666 129.6 ;
    END
  END i[254]
  PIN i[255]
    DIRECTION INPUT ;
    USE SIGNAL ;
    PORT
      LAYER M5 ;
        RECT  63.888 129.516 63.912 129.6 ;
    END
  END i[255]
  PIN i[256]
    DIRECTION INPUT ;
    USE SIGNAL ;
    PORT
      LAYER M3 ;
        RECT  64.116 129.562 64.134 129.6 ;
    END
  END i[256]
  PIN i[25]
    DIRECTION INPUT ;
    USE SIGNAL ;
    PORT
      LAYER M5 ;
        RECT  6.864 129.516 6.888 129.6 ;
    END
  END i[25]
  PIN i[26]
    DIRECTION INPUT ;
    USE SIGNAL ;
    PORT
      LAYER M3 ;
        RECT  7.092 129.562 7.11 129.6 ;
    END
  END i[26]
  PIN i[27]
    DIRECTION INPUT ;
    USE SIGNAL ;
    PORT
      LAYER M5 ;
        RECT  7.344 129.516 7.368 129.6 ;
    END
  END i[27]
  PIN i[28]
    DIRECTION INPUT ;
    USE SIGNAL ;
    PORT
      LAYER M3 ;
        RECT  7.596 129.562 7.614 129.6 ;
    END
  END i[28]
  PIN i[29]
    DIRECTION INPUT ;
    USE SIGNAL ;
    PORT
      LAYER M5 ;
        RECT  7.824 129.516 7.848 129.6 ;
    END
  END i[29]
  PIN i[2]
    DIRECTION INPUT ;
    USE SIGNAL ;
    PORT
      LAYER M3 ;
        RECT  1.152 129.562 1.17 129.6 ;
    END
  END i[2]
  PIN i[30]
    DIRECTION INPUT ;
    USE SIGNAL ;
    PORT
      LAYER M3 ;
        RECT  8.1 129.562 8.118 129.6 ;
    END
  END i[30]
  PIN i[31]
    DIRECTION INPUT ;
    USE SIGNAL ;
    PORT
      LAYER M5 ;
        RECT  8.352 129.516 8.376 129.6 ;
    END
  END i[31]
  PIN i[32]
    DIRECTION INPUT ;
    USE SIGNAL ;
    PORT
      LAYER M3 ;
        RECT  8.604 129.562 8.622 129.6 ;
    END
  END i[32]
  PIN i[33]
    DIRECTION INPUT ;
    USE SIGNAL ;
    PORT
      LAYER M5 ;
        RECT  8.832 129.516 8.856 129.6 ;
    END
  END i[33]
  PIN i[34]
    DIRECTION INPUT ;
    USE SIGNAL ;
    PORT
      LAYER M3 ;
        RECT  9.072 129.562 9.09 129.6 ;
    END
  END i[34]
  PIN i[35]
    DIRECTION INPUT ;
    USE SIGNAL ;
    PORT
      LAYER M5 ;
        RECT  9.312 129.516 9.336 129.6 ;
    END
  END i[35]
  PIN i[36]
    DIRECTION INPUT ;
    USE SIGNAL ;
    PORT
      LAYER M3 ;
        RECT  9.576 129.562 9.594 129.6 ;
    END
  END i[36]
  PIN i[37]
    DIRECTION INPUT ;
    USE SIGNAL ;
    PORT
      LAYER M5 ;
        RECT  9.84 129.516 9.864 129.6 ;
    END
  END i[37]
  PIN i[38]
    DIRECTION INPUT ;
    USE SIGNAL ;
    PORT
      LAYER M3 ;
        RECT  10.08 129.562 10.098 129.6 ;
    END
  END i[38]
  PIN i[39]
    DIRECTION INPUT ;
    USE SIGNAL ;
    PORT
      LAYER M5 ;
        RECT  10.32 129.516 10.344 129.6 ;
    END
  END i[39]
  PIN i[3]
    DIRECTION INPUT ;
    USE SIGNAL ;
    PORT
      LAYER M5 ;
        RECT  1.392 129.516 1.416 129.6 ;
    END
  END i[3]
  PIN i[40]
    DIRECTION INPUT ;
    USE SIGNAL ;
    PORT
      LAYER M3 ;
        RECT  10.584 129.562 10.602 129.6 ;
    END
  END i[40]
  PIN i[41]
    DIRECTION INPUT ;
    USE SIGNAL ;
    PORT
      LAYER M5 ;
        RECT  10.8 129.516 10.824 129.6 ;
    END
  END i[41]
  PIN i[42]
    DIRECTION INPUT ;
    USE SIGNAL ;
    PORT
      LAYER M3 ;
        RECT  11.052 129.562 11.07 129.6 ;
    END
  END i[42]
  PIN i[43]
    DIRECTION INPUT ;
    USE SIGNAL ;
    PORT
      LAYER M5 ;
        RECT  11.328 129.516 11.352 129.6 ;
    END
  END i[43]
  PIN i[44]
    DIRECTION INPUT ;
    USE SIGNAL ;
    PORT
      LAYER M3 ;
        RECT  11.556 129.562 11.574 129.6 ;
    END
  END i[44]
  PIN i[45]
    DIRECTION INPUT ;
    USE SIGNAL ;
    PORT
      LAYER M5 ;
        RECT  11.808 129.516 11.832 129.6 ;
    END
  END i[45]
  PIN i[46]
    DIRECTION INPUT ;
    USE SIGNAL ;
    PORT
      LAYER M3 ;
        RECT  12.06 129.562 12.078 129.6 ;
    END
  END i[46]
  PIN i[47]
    DIRECTION INPUT ;
    USE SIGNAL ;
    PORT
      LAYER M5 ;
        RECT  12.288 129.516 12.312 129.6 ;
    END
  END i[47]
  PIN i[48]
    DIRECTION INPUT ;
    USE SIGNAL ;
    PORT
      LAYER M3 ;
        RECT  12.564 129.562 12.582 129.6 ;
    END
  END i[48]
  PIN i[49]
    DIRECTION INPUT ;
    USE SIGNAL ;
    PORT
      LAYER M5 ;
        RECT  12.816 129.516 12.84 129.6 ;
    END
  END i[49]
  PIN i[4]
    DIRECTION INPUT ;
    USE SIGNAL ;
    PORT
      LAYER M3 ;
        RECT  1.656 129.562 1.674 129.6 ;
    END
  END i[4]
  PIN i[50]
    DIRECTION INPUT ;
    USE SIGNAL ;
    PORT
      LAYER M3 ;
        RECT  13.068 129.562 13.086 129.6 ;
    END
  END i[50]
  PIN i[51]
    DIRECTION INPUT ;
    USE SIGNAL ;
    PORT
      LAYER M5 ;
        RECT  13.296 129.516 13.32 129.6 ;
    END
  END i[51]
  PIN i[52]
    DIRECTION INPUT ;
    USE SIGNAL ;
    PORT
      LAYER M3 ;
        RECT  13.536 129.562 13.554 129.6 ;
    END
  END i[52]
  PIN i[53]
    DIRECTION INPUT ;
    USE SIGNAL ;
    PORT
      LAYER M5 ;
        RECT  13.776 129.516 13.8 129.6 ;
    END
  END i[53]
  PIN i[54]
    DIRECTION INPUT ;
    USE SIGNAL ;
    PORT
      LAYER M3 ;
        RECT  14.04 129.562 14.058 129.6 ;
    END
  END i[54]
  PIN i[55]
    DIRECTION INPUT ;
    USE SIGNAL ;
    PORT
      LAYER M5 ;
        RECT  14.304 129.516 14.328 129.6 ;
    END
  END i[55]
  PIN i[56]
    DIRECTION INPUT ;
    USE SIGNAL ;
    PORT
      LAYER M3 ;
        RECT  14.544 129.562 14.562 129.6 ;
    END
  END i[56]
  PIN i[57]
    DIRECTION INPUT ;
    USE SIGNAL ;
    PORT
      LAYER M5 ;
        RECT  14.784 129.516 14.808 129.6 ;
    END
  END i[57]
  PIN i[58]
    DIRECTION INPUT ;
    USE SIGNAL ;
    PORT
      LAYER M3 ;
        RECT  15.048 129.562 15.066 129.6 ;
    END
  END i[58]
  PIN i[59]
    DIRECTION INPUT ;
    USE SIGNAL ;
    PORT
      LAYER M5 ;
        RECT  15.264 129.516 15.288 129.6 ;
    END
  END i[59]
  PIN i[5]
    DIRECTION INPUT ;
    USE SIGNAL ;
    PORT
      LAYER M5 ;
        RECT  1.872 129.516 1.896 129.6 ;
    END
  END i[5]
  PIN i[60]
    DIRECTION INPUT ;
    USE SIGNAL ;
    PORT
      LAYER M3 ;
        RECT  15.516 129.562 15.534 129.6 ;
    END
  END i[60]
  PIN i[61]
    DIRECTION INPUT ;
    USE SIGNAL ;
    PORT
      LAYER M5 ;
        RECT  15.792 129.516 15.816 129.6 ;
    END
  END i[61]
  PIN i[62]
    DIRECTION INPUT ;
    USE SIGNAL ;
    PORT
      LAYER M3 ;
        RECT  16.02 129.562 16.038 129.6 ;
    END
  END i[62]
  PIN i[63]
    DIRECTION INPUT ;
    USE SIGNAL ;
    PORT
      LAYER M5 ;
        RECT  16.272 129.516 16.296 129.6 ;
    END
  END i[63]
  PIN i[64]
    DIRECTION INPUT ;
    USE SIGNAL ;
    PORT
      LAYER M3 ;
        RECT  16.524 129.562 16.542 129.6 ;
    END
  END i[64]
  PIN i[65]
    DIRECTION INPUT ;
    USE SIGNAL ;
    PORT
      LAYER M5 ;
        RECT  16.752 129.516 16.776 129.6 ;
    END
  END i[65]
  PIN i[66]
    DIRECTION INPUT ;
    USE SIGNAL ;
    PORT
      LAYER M3 ;
        RECT  17.028 129.562 17.046 129.6 ;
    END
  END i[66]
  PIN i[67]
    DIRECTION INPUT ;
    USE SIGNAL ;
    PORT
      LAYER M5 ;
        RECT  17.28 129.516 17.304 129.6 ;
    END
  END i[67]
  PIN i[68]
    DIRECTION INPUT ;
    USE SIGNAL ;
    PORT
      LAYER M3 ;
        RECT  17.532 129.562 17.55 129.6 ;
    END
  END i[68]
  PIN i[69]
    DIRECTION INPUT ;
    USE SIGNAL ;
    PORT
      LAYER M5 ;
        RECT  17.76 129.516 17.784 129.6 ;
    END
  END i[69]
  PIN i[6]
    DIRECTION INPUT ;
    USE SIGNAL ;
    PORT
      LAYER M3 ;
        RECT  2.16 129.562 2.178 129.6 ;
    END
  END i[6]
  PIN i[70]
    DIRECTION INPUT ;
    USE SIGNAL ;
    PORT
      LAYER M3 ;
        RECT  18 129.562 18.018 129.6 ;
    END
  END i[70]
  PIN i[71]
    DIRECTION INPUT ;
    USE SIGNAL ;
    PORT
      LAYER M5 ;
        RECT  18.24 129.516 18.264 129.6 ;
    END
  END i[71]
  PIN i[72]
    DIRECTION INPUT ;
    USE SIGNAL ;
    PORT
      LAYER M3 ;
        RECT  18.504 129.562 18.522 129.6 ;
    END
  END i[72]
  PIN i[73]
    DIRECTION INPUT ;
    USE SIGNAL ;
    PORT
      LAYER M5 ;
        RECT  18.768 129.516 18.792 129.6 ;
    END
  END i[73]
  PIN i[74]
    DIRECTION INPUT ;
    USE SIGNAL ;
    PORT
      LAYER M3 ;
        RECT  19.008 129.562 19.026 129.6 ;
    END
  END i[74]
  PIN i[75]
    DIRECTION INPUT ;
    USE SIGNAL ;
    PORT
      LAYER M5 ;
        RECT  19.248 129.516 19.272 129.6 ;
    END
  END i[75]
  PIN i[76]
    DIRECTION INPUT ;
    USE SIGNAL ;
    PORT
      LAYER M3 ;
        RECT  19.512 129.562 19.53 129.6 ;
    END
  END i[76]
  PIN i[77]
    DIRECTION INPUT ;
    USE SIGNAL ;
    PORT
      LAYER M5 ;
        RECT  19.728 129.516 19.752 129.6 ;
    END
  END i[77]
  PIN i[78]
    DIRECTION INPUT ;
    USE SIGNAL ;
    PORT
      LAYER M3 ;
        RECT  19.98 129.562 19.998 129.6 ;
    END
  END i[78]
  PIN i[79]
    DIRECTION INPUT ;
    USE SIGNAL ;
    PORT
      LAYER M5 ;
        RECT  20.256 129.516 20.28 129.6 ;
    END
  END i[79]
  PIN i[7]
    DIRECTION INPUT ;
    USE SIGNAL ;
    PORT
      LAYER M5 ;
        RECT  2.4 129.516 2.424 129.6 ;
    END
  END i[7]
  PIN i[80]
    DIRECTION INPUT ;
    USE SIGNAL ;
    PORT
      LAYER M3 ;
        RECT  20.484 129.562 20.502 129.6 ;
    END
  END i[80]
  PIN i[81]
    DIRECTION INPUT ;
    USE SIGNAL ;
    PORT
      LAYER M5 ;
        RECT  20.736 129.516 20.76 129.6 ;
    END
  END i[81]
  PIN i[82]
    DIRECTION INPUT ;
    USE SIGNAL ;
    PORT
      LAYER M3 ;
        RECT  20.988 129.562 21.006 129.6 ;
    END
  END i[82]
  PIN i[83]
    DIRECTION INPUT ;
    USE SIGNAL ;
    PORT
      LAYER M5 ;
        RECT  21.216 129.516 21.24 129.6 ;
    END
  END i[83]
  PIN i[84]
    DIRECTION INPUT ;
    USE SIGNAL ;
    PORT
      LAYER M3 ;
        RECT  21.492 129.562 21.51 129.6 ;
    END
  END i[84]
  PIN i[85]
    DIRECTION INPUT ;
    USE SIGNAL ;
    PORT
      LAYER M5 ;
        RECT  21.744 129.516 21.768 129.6 ;
    END
  END i[85]
  PIN i[86]
    DIRECTION INPUT ;
    USE SIGNAL ;
    PORT
      LAYER M3 ;
        RECT  21.996 129.562 22.014 129.6 ;
    END
  END i[86]
  PIN i[87]
    DIRECTION INPUT ;
    USE SIGNAL ;
    PORT
      LAYER M5 ;
        RECT  22.224 129.516 22.248 129.6 ;
    END
  END i[87]
  PIN i[88]
    DIRECTION INPUT ;
    USE SIGNAL ;
    PORT
      LAYER M3 ;
        RECT  22.464 129.562 22.482 129.6 ;
    END
  END i[88]
  PIN i[89]
    DIRECTION INPUT ;
    USE SIGNAL ;
    PORT
      LAYER M5 ;
        RECT  22.704 129.516 22.728 129.6 ;
    END
  END i[89]
  PIN i[8]
    DIRECTION INPUT ;
    USE SIGNAL ;
    PORT
      LAYER M3 ;
        RECT  2.628 129.562 2.646 129.6 ;
    END
  END i[8]
  PIN i[90]
    DIRECTION INPUT ;
    USE SIGNAL ;
    PORT
      LAYER M3 ;
        RECT  22.968 129.562 22.986 129.6 ;
    END
  END i[90]
  PIN i[91]
    DIRECTION INPUT ;
    USE SIGNAL ;
    PORT
      LAYER M5 ;
        RECT  23.232 129.516 23.256 129.6 ;
    END
  END i[91]
  PIN i[92]
    DIRECTION INPUT ;
    USE SIGNAL ;
    PORT
      LAYER M3 ;
        RECT  23.472 129.562 23.49 129.6 ;
    END
  END i[92]
  PIN i[93]
    DIRECTION INPUT ;
    USE SIGNAL ;
    PORT
      LAYER M5 ;
        RECT  23.712 129.516 23.736 129.6 ;
    END
  END i[93]
  PIN i[94]
    DIRECTION INPUT ;
    USE SIGNAL ;
    PORT
      LAYER M3 ;
        RECT  23.976 129.562 23.994 129.6 ;
    END
  END i[94]
  PIN i[95]
    DIRECTION INPUT ;
    USE SIGNAL ;
    PORT
      LAYER M5 ;
        RECT  24.192 129.516 24.216 129.6 ;
    END
  END i[95]
  PIN i[96]
    DIRECTION INPUT ;
    USE SIGNAL ;
    PORT
      LAYER M3 ;
        RECT  24.444 129.562 24.462 129.6 ;
    END
  END i[96]
  PIN i[97]
    DIRECTION INPUT ;
    USE SIGNAL ;
    PORT
      LAYER M5 ;
        RECT  24.72 129.516 24.744 129.6 ;
    END
  END i[97]
  PIN i[98]
    DIRECTION INPUT ;
    USE SIGNAL ;
    PORT
      LAYER M3 ;
        RECT  24.948 129.562 24.966 129.6 ;
    END
  END i[98]
  PIN i[99]
    DIRECTION INPUT ;
    USE SIGNAL ;
    PORT
      LAYER M5 ;
        RECT  25.2 129.516 25.224 129.6 ;
    END
  END i[99]
  PIN i[9]
    DIRECTION INPUT ;
    USE SIGNAL ;
    PORT
      LAYER M5 ;
        RECT  2.88 129.516 2.904 129.6 ;
    END
  END i[9]
  PIN rsi
    DIRECTION INPUT ;
    USE SIGNAL ;
    PORT
      LAYER M3 ;
        RECT  35.1 0 35.118 0.038 ;
    END
  END rsi
  PIN vld[0]
    DIRECTION OUTPUT ;
    USE SIGNAL ;
    PORT
      LAYER M3 ;
        RECT  40.104 0 40.122 0.038 ;
    END
  END vld[0]
  PIN vld[10]
    DIRECTION OUTPUT ;
    USE SIGNAL ;
    PORT
      LAYER M3 ;
        RECT  42.372 0 42.39 0.038 ;
    END
  END vld[10]
  PIN vld[11]
    DIRECTION OUTPUT ;
    USE SIGNAL ;
    PORT
      LAYER M5 ;
        RECT  42.624 0 42.648 0.084 ;
    END
  END vld[11]
  PIN vld[12]
    DIRECTION OUTPUT ;
    USE SIGNAL ;
    PORT
      LAYER M3 ;
        RECT  42.84 0 42.858 0.038 ;
    END
  END vld[12]
  PIN vld[13]
    DIRECTION OUTPUT ;
    USE SIGNAL ;
    PORT
      LAYER M5 ;
        RECT  43.056 0 43.08 0.084 ;
    END
  END vld[13]
  PIN vld[14]
    DIRECTION OUTPUT ;
    USE SIGNAL ;
    PORT
      LAYER M3 ;
        RECT  43.272 0 43.29 0.038 ;
    END
  END vld[14]
  PIN vld[15]
    DIRECTION OUTPUT ;
    USE SIGNAL ;
    PORT
      LAYER M5 ;
        RECT  43.488 0 43.512 0.084 ;
    END
  END vld[15]
  PIN vld[16]
    DIRECTION OUTPUT ;
    USE SIGNAL ;
    PORT
      LAYER M3 ;
        RECT  43.74 0 43.758 0.038 ;
    END
  END vld[16]
  PIN vld[17]
    DIRECTION OUTPUT ;
    USE SIGNAL ;
    PORT
      LAYER M5 ;
        RECT  43.968 0 43.992 0.084 ;
    END
  END vld[17]
  PIN vld[18]
    DIRECTION OUTPUT ;
    USE SIGNAL ;
    PORT
      LAYER M3 ;
        RECT  44.208 0 44.226 0.038 ;
    END
  END vld[18]
  PIN vld[19]
    DIRECTION OUTPUT ;
    USE SIGNAL ;
    PORT
      LAYER M5 ;
        RECT  44.4 0 44.424 0.084 ;
    END
  END vld[19]
  PIN vld[1]
    DIRECTION OUTPUT ;
    USE SIGNAL ;
    PORT
      LAYER M5 ;
        RECT  40.32 0 40.344 0.084 ;
    END
  END vld[1]
  PIN vld[20]
    DIRECTION OUTPUT ;
    USE SIGNAL ;
    PORT
      LAYER M3 ;
        RECT  44.64 0 44.658 0.038 ;
    END
  END vld[20]
  PIN vld[21]
    DIRECTION OUTPUT ;
    USE SIGNAL ;
    PORT
      LAYER M5 ;
        RECT  44.88 0 44.904 0.084 ;
    END
  END vld[21]
  PIN vld[22]
    DIRECTION OUTPUT ;
    USE SIGNAL ;
    PORT
      LAYER M3 ;
        RECT  45.108 0 45.126 0.038 ;
    END
  END vld[22]
  PIN vld[23]
    DIRECTION OUTPUT ;
    USE SIGNAL ;
    PORT
      LAYER M5 ;
        RECT  45.312 0 45.336 0.084 ;
    END
  END vld[23]
  PIN vld[24]
    DIRECTION OUTPUT ;
    USE SIGNAL ;
    PORT
      LAYER M3 ;
        RECT  45.576 0 45.594 0.038 ;
    END
  END vld[24]
  PIN vld[25]
    DIRECTION OUTPUT ;
    USE SIGNAL ;
    PORT
      LAYER M5 ;
        RECT  45.792 0 45.816 0.084 ;
    END
  END vld[25]
  PIN vld[26]
    DIRECTION OUTPUT ;
    USE SIGNAL ;
    PORT
      LAYER M3 ;
        RECT  46.008 0 46.026 0.038 ;
    END
  END vld[26]
  PIN vld[27]
    DIRECTION OUTPUT ;
    USE SIGNAL ;
    PORT
      LAYER M5 ;
        RECT  46.224 0 46.248 0.084 ;
    END
  END vld[27]
  PIN vld[28]
    DIRECTION OUTPUT ;
    USE SIGNAL ;
    PORT
      LAYER M3 ;
        RECT  46.476 0 46.494 0.038 ;
    END
  END vld[28]
  PIN vld[29]
    DIRECTION OUTPUT ;
    USE SIGNAL ;
    PORT
      LAYER M5 ;
        RECT  46.704 0 46.728 0.084 ;
    END
  END vld[29]
  PIN vld[2]
    DIRECTION OUTPUT ;
    USE SIGNAL ;
    PORT
      LAYER M3 ;
        RECT  40.572 0 40.59 0.038 ;
    END
  END vld[2]
  PIN vld[30]
    DIRECTION OUTPUT ;
    USE SIGNAL ;
    PORT
      LAYER M3 ;
        RECT  46.908 0 46.926 0.038 ;
    END
  END vld[30]
  PIN vld[31]
    DIRECTION OUTPUT ;
    USE SIGNAL ;
    PORT
      LAYER M5 ;
        RECT  47.136 0 47.16 0.084 ;
    END
  END vld[31]
  PIN vld[32]
    DIRECTION OUTPUT ;
    USE SIGNAL ;
    PORT
      LAYER M3 ;
        RECT  47.376 0 47.394 0.038 ;
    END
  END vld[32]
  PIN vld[33]
    DIRECTION OUTPUT ;
    USE SIGNAL ;
    PORT
      LAYER M5 ;
        RECT  47.616 0 47.64 0.084 ;
    END
  END vld[33]
  PIN vld[34]
    DIRECTION OUTPUT ;
    USE SIGNAL ;
    PORT
      LAYER M3 ;
        RECT  47.844 0 47.862 0.038 ;
    END
  END vld[34]
  PIN vld[35]
    DIRECTION OUTPUT ;
    USE SIGNAL ;
    PORT
      LAYER M5 ;
        RECT  48.048 0 48.072 0.084 ;
    END
  END vld[35]
  PIN vld[36]
    DIRECTION OUTPUT ;
    USE SIGNAL ;
    PORT
      LAYER M3 ;
        RECT  48.276 0 48.294 0.038 ;
    END
  END vld[36]
  PIN vld[37]
    DIRECTION OUTPUT ;
    USE SIGNAL ;
    PORT
      LAYER M5 ;
        RECT  48.528 0 48.552 0.084 ;
    END
  END vld[37]
  PIN vld[38]
    DIRECTION OUTPUT ;
    USE SIGNAL ;
    PORT
      LAYER M3 ;
        RECT  48.744 0 48.762 0.038 ;
    END
  END vld[38]
  PIN vld[39]
    DIRECTION OUTPUT ;
    USE SIGNAL ;
    PORT
      LAYER M5 ;
        RECT  48.96 0 48.984 0.084 ;
    END
  END vld[39]
  PIN vld[3]
    DIRECTION OUTPUT ;
    USE SIGNAL ;
    PORT
      LAYER M5 ;
        RECT  40.8 0 40.824 0.084 ;
    END
  END vld[3]
  PIN vld[40]
    DIRECTION OUTPUT ;
    USE SIGNAL ;
    PORT
      LAYER M3 ;
        RECT  49.212 0 49.23 0.038 ;
    END
  END vld[40]
  PIN vld[41]
    DIRECTION OUTPUT ;
    USE SIGNAL ;
    PORT
      LAYER M5 ;
        RECT  49.44 0 49.464 0.084 ;
    END
  END vld[41]
  PIN vld[42]
    DIRECTION OUTPUT ;
    USE SIGNAL ;
    PORT
      LAYER M3 ;
        RECT  49.644 0 49.662 0.038 ;
    END
  END vld[42]
  PIN vld[43]
    DIRECTION OUTPUT ;
    USE SIGNAL ;
    PORT
      LAYER M5 ;
        RECT  49.872 0 49.896 0.084 ;
    END
  END vld[43]
  PIN vld[4]
    DIRECTION OUTPUT ;
    USE SIGNAL ;
    PORT
      LAYER M3 ;
        RECT  41.004 0 41.022 0.038 ;
    END
  END vld[4]
  PIN vld[5]
    DIRECTION OUTPUT ;
    USE SIGNAL ;
    PORT
      LAYER M5 ;
        RECT  41.232 0 41.256 0.084 ;
    END
  END vld[5]
  PIN vld[6]
    DIRECTION OUTPUT ;
    USE SIGNAL ;
    PORT
      LAYER M3 ;
        RECT  41.472 0 41.49 0.038 ;
    END
  END vld[6]
  PIN vld[7]
    DIRECTION OUTPUT ;
    USE SIGNAL ;
    PORT
      LAYER M5 ;
        RECT  41.712 0 41.736 0.084 ;
    END
  END vld[7]
  PIN vld[8]
    DIRECTION OUTPUT ;
    USE SIGNAL ;
    PORT
      LAYER M3 ;
        RECT  41.94 0 41.958 0.038 ;
    END
  END vld[8]
  PIN vld[9]
    DIRECTION OUTPUT ;
    USE SIGNAL ;
    PORT
      LAYER M5 ;
        RECT  42.144 0 42.168 0.084 ;
    END
  END vld[9]
  PIN VDD
    DIRECTION INOUT ;
    USE POWER ;
    PORT
      LAYER M5 ;
        RECT  61.992 2.151 62.112 127.449 ;
        RECT  56.592 2.151 56.712 127.449 ;
        RECT  51.192 2.151 51.312 127.449 ;
        RECT  45.792 2.151 45.912 127.449 ;
        RECT  40.392 2.151 40.512 127.449 ;
        RECT  34.992 2.151 35.112 127.449 ;
        RECT  29.592 2.151 29.712 127.449 ;
        RECT  24.192 2.151 24.312 127.449 ;
        RECT  18.792 2.151 18.912 127.449 ;
        RECT  13.392 2.151 13.512 127.449 ;
        RECT  7.992 2.151 8.112 127.449 ;
        RECT  2.592 2.151 2.712 127.449 ;
    END
  END VDD
  PIN VSS
    DIRECTION INOUT ;
    USE GROUND ;
    PORT
      LAYER M5 ;
        RECT  61.8 2.137 61.92 127.463 ;
        RECT  56.4 2.137 56.52 127.463 ;
        RECT  51 2.137 51.12 127.463 ;
        RECT  45.6 2.137 45.72 127.463 ;
        RECT  40.2 2.137 40.32 127.463 ;
        RECT  34.8 2.137 34.92 127.463 ;
        RECT  29.4 2.137 29.52 127.463 ;
        RECT  24 2.137 24.12 127.463 ;
        RECT  18.6 2.137 18.72 127.463 ;
        RECT  13.2 2.137 13.32 127.463 ;
        RECT  7.8 2.137 7.92 127.463 ;
        RECT  2.4 2.137 2.52 127.463 ;
    END
  END VSS
  OBS
    LAYER RVTN ;
     RECT  2.16 2.16 62.64 2.295 ;
     RECT  2.16 2.565 62.64 2.835 ;
     RECT  2.16 3.105 62.64 3.375 ;
     RECT  2.16 3.645 62.64 3.915 ;
     RECT  2.16 4.185 62.64 4.455 ;
     RECT  2.16 4.725 62.64 4.995 ;
     RECT  2.16 5.265 62.64 5.535 ;
     RECT  2.16 5.805 62.64 6.075 ;
     RECT  2.16 6.345 62.64 6.615 ;
     RECT  2.16 6.885 62.64 7.155 ;
     RECT  2.16 7.425 62.64 7.695 ;
     RECT  2.16 7.965 62.64 8.235 ;
     RECT  2.16 8.505 62.64 8.775 ;
     RECT  2.16 9.045 62.64 9.315 ;
     RECT  2.16 9.585 62.64 9.855 ;
     RECT  2.16 10.125 62.64 10.395 ;
     RECT  2.16 10.665 62.64 10.935 ;
     RECT  2.16 11.205 62.64 11.475 ;
     RECT  2.16 11.745 62.64 12.015 ;
     RECT  2.16 12.285 62.64 12.555 ;
     RECT  2.16 12.825 62.64 13.095 ;
     RECT  2.16 13.365 62.64 13.635 ;
     RECT  2.16 13.905 62.64 14.175 ;
     RECT  2.16 14.445 62.64 14.715 ;
     RECT  2.16 14.985 62.64 15.255 ;
     RECT  2.16 15.525 62.64 15.795 ;
     RECT  2.16 16.065 62.64 16.335 ;
     RECT  2.16 16.605 62.64 16.875 ;
     RECT  2.16 17.145 62.64 17.415 ;
     RECT  2.16 17.685 62.64 17.955 ;
     RECT  2.16 18.225 62.64 18.495 ;
     RECT  2.16 18.765 62.64 19.035 ;
     RECT  2.16 19.305 62.64 19.575 ;
     RECT  2.16 19.845 62.64 20.115 ;
     RECT  2.16 20.385 62.64 20.655 ;
     RECT  2.16 20.925 62.64 21.195 ;
     RECT  2.16 21.465 62.64 21.735 ;
     RECT  2.16 22.005 62.64 22.275 ;
     RECT  2.16 22.545 62.64 22.815 ;
     RECT  2.16 23.085 62.64 23.355 ;
     RECT  2.16 23.625 62.64 23.895 ;
     RECT  2.16 24.165 62.64 24.435 ;
     RECT  2.16 24.705 62.64 24.975 ;
     RECT  2.16 25.245 62.64 25.515 ;
     RECT  2.16 25.785 62.64 26.055 ;
     RECT  2.16 26.325 62.64 26.595 ;
     RECT  2.16 26.865 62.64 27.135 ;
     RECT  2.16 27.405 62.64 27.675 ;
     RECT  2.16 27.945 62.64 28.215 ;
     RECT  2.16 28.485 62.64 28.755 ;
     RECT  2.16 29.025 62.64 29.295 ;
     RECT  2.16 29.565 62.64 29.835 ;
     RECT  2.16 30.105 62.64 30.375 ;
     RECT  2.16 30.645 62.64 30.915 ;
     RECT  2.16 31.185 62.64 31.455 ;
     RECT  2.16 31.725 62.64 31.995 ;
     RECT  2.16 32.265 62.64 32.535 ;
     RECT  2.16 32.805 62.64 33.075 ;
     RECT  2.16 33.345 62.64 33.615 ;
     RECT  2.16 33.885 62.64 34.155 ;
     RECT  2.16 34.425 62.64 34.695 ;
     RECT  2.16 34.965 62.64 35.235 ;
     RECT  2.16 35.505 62.64 35.775 ;
     RECT  2.16 36.045 62.64 36.315 ;
     RECT  2.16 36.585 62.64 36.855 ;
     RECT  2.16 37.125 62.64 37.395 ;
     RECT  2.16 37.665 62.64 37.935 ;
     RECT  2.16 38.205 62.64 38.475 ;
     RECT  2.16 38.745 62.64 39.015 ;
     RECT  2.16 39.285 62.64 39.555 ;
     RECT  2.16 39.825 62.64 40.095 ;
     RECT  2.16 40.365 62.64 40.635 ;
     RECT  2.16 40.905 62.64 41.175 ;
     RECT  2.16 41.445 62.64 41.715 ;
     RECT  2.16 41.985 62.64 42.255 ;
     RECT  2.16 42.525 62.64 42.795 ;
     RECT  2.16 43.065 62.64 43.335 ;
     RECT  2.16 43.605 62.64 43.875 ;
     RECT  2.16 44.145 62.64 44.415 ;
     RECT  2.16 44.685 62.64 44.955 ;
     RECT  2.16 45.225 62.64 45.495 ;
     RECT  2.16 45.765 62.64 46.035 ;
     RECT  2.16 46.305 62.64 46.575 ;
     RECT  2.16 46.845 62.64 47.115 ;
     RECT  2.16 47.385 62.64 47.655 ;
     RECT  2.16 47.925 62.64 48.195 ;
     RECT  2.16 48.465 62.64 48.735 ;
     RECT  2.16 49.005 62.64 49.275 ;
     RECT  2.16 49.545 62.64 49.815 ;
     RECT  2.16 50.085 62.64 50.355 ;
     RECT  2.16 50.625 62.64 50.895 ;
     RECT  2.16 51.165 62.64 51.435 ;
     RECT  2.16 51.705 62.64 51.975 ;
     RECT  2.16 52.245 62.64 52.515 ;
     RECT  2.16 52.785 62.64 53.055 ;
     RECT  2.16 53.325 62.64 53.595 ;
     RECT  2.16 53.865 62.64 54.135 ;
     RECT  2.16 54.405 62.64 54.675 ;
     RECT  2.16 54.945 62.64 55.215 ;
     RECT  2.16 55.485 62.64 55.755 ;
     RECT  2.16 56.025 62.64 56.295 ;
     RECT  2.16 56.565 62.64 56.835 ;
     RECT  2.16 57.105 62.64 57.375 ;
     RECT  2.16 57.645 62.64 57.915 ;
     RECT  2.16 58.185 62.64 58.455 ;
     RECT  2.16 58.725 62.64 58.995 ;
     RECT  2.16 59.265 62.64 59.535 ;
     RECT  2.16 59.805 62.64 60.075 ;
     RECT  2.16 60.345 62.64 60.615 ;
     RECT  2.16 60.885 62.64 61.155 ;
     RECT  2.16 61.425 62.64 61.695 ;
     RECT  2.16 61.965 62.64 62.235 ;
     RECT  2.16 62.505 62.64 62.775 ;
     RECT  2.16 63.045 62.64 63.315 ;
     RECT  2.16 63.585 62.64 63.855 ;
     RECT  2.16 64.125 62.64 64.395 ;
     RECT  2.16 64.665 62.64 64.935 ;
     RECT  2.16 65.205 62.64 65.475 ;
     RECT  2.16 65.745 62.64 66.015 ;
     RECT  2.16 66.285 62.64 66.555 ;
     RECT  2.16 66.825 62.64 67.095 ;
     RECT  2.16 67.365 62.64 67.635 ;
     RECT  2.16 67.905 62.64 68.175 ;
     RECT  2.16 68.445 62.64 68.715 ;
     RECT  2.16 68.985 62.64 69.255 ;
     RECT  2.16 69.525 62.64 69.795 ;
     RECT  2.16 70.065 62.64 70.335 ;
     RECT  2.16 70.605 62.64 70.875 ;
     RECT  2.16 71.145 62.64 71.415 ;
     RECT  2.16 71.685 62.64 71.955 ;
     RECT  2.16 72.225 62.64 72.495 ;
     RECT  2.16 72.765 62.64 73.035 ;
     RECT  2.16 73.305 62.64 73.575 ;
     RECT  2.16 73.845 62.64 74.115 ;
     RECT  2.16 74.385 62.64 74.655 ;
     RECT  2.16 74.925 62.64 75.195 ;
     RECT  2.16 75.465 62.64 75.735 ;
     RECT  2.16 76.005 62.64 76.275 ;
     RECT  2.16 76.545 62.64 76.815 ;
     RECT  2.16 77.085 62.64 77.355 ;
     RECT  2.16 77.625 62.64 77.895 ;
     RECT  2.16 78.165 62.64 78.435 ;
     RECT  2.16 78.705 62.64 78.975 ;
     RECT  2.16 79.245 62.64 79.515 ;
     RECT  2.16 79.785 62.64 80.055 ;
     RECT  2.16 80.325 62.64 80.595 ;
     RECT  2.16 80.865 62.64 81.135 ;
     RECT  2.16 81.405 62.64 81.675 ;
     RECT  2.16 81.945 62.64 82.215 ;
     RECT  2.16 82.485 62.64 82.755 ;
     RECT  2.16 83.025 62.64 83.295 ;
     RECT  2.16 83.565 62.64 83.835 ;
     RECT  2.16 84.105 62.64 84.375 ;
     RECT  2.16 84.645 62.64 84.915 ;
     RECT  2.16 85.185 62.64 85.455 ;
     RECT  2.16 85.725 62.64 85.995 ;
     RECT  2.16 86.265 62.64 86.535 ;
     RECT  2.16 86.805 62.64 87.075 ;
     RECT  2.16 87.345 62.64 87.615 ;
     RECT  2.16 87.885 62.64 88.155 ;
     RECT  2.16 88.425 62.64 88.695 ;
     RECT  2.16 88.965 62.64 89.235 ;
     RECT  2.16 89.505 62.64 89.775 ;
     RECT  2.16 90.045 62.64 90.315 ;
     RECT  2.16 90.585 62.64 90.855 ;
     RECT  2.16 91.125 62.64 91.395 ;
     RECT  2.16 91.665 62.64 91.935 ;
     RECT  2.16 92.205 62.64 92.475 ;
     RECT  2.16 92.745 62.64 93.015 ;
     RECT  2.16 93.285 62.64 93.555 ;
     RECT  2.16 93.825 62.64 94.095 ;
     RECT  2.16 94.365 62.64 94.635 ;
     RECT  2.16 94.905 62.64 95.175 ;
     RECT  2.16 95.445 62.64 95.715 ;
     RECT  2.16 95.985 62.64 96.255 ;
     RECT  2.16 96.525 62.64 96.795 ;
     RECT  2.16 97.065 62.64 97.335 ;
     RECT  2.16 97.605 62.64 97.875 ;
     RECT  2.16 98.145 62.64 98.415 ;
     RECT  2.16 98.685 62.64 98.955 ;
     RECT  2.16 99.225 62.64 99.495 ;
     RECT  2.16 99.765 62.64 100.035 ;
     RECT  2.16 100.305 62.64 100.575 ;
     RECT  2.16 100.845 62.64 101.115 ;
     RECT  2.16 101.385 62.64 101.655 ;
     RECT  2.16 101.925 62.64 102.195 ;
     RECT  2.16 102.465 62.64 102.735 ;
     RECT  2.16 103.005 62.64 103.275 ;
     RECT  2.16 103.545 62.64 103.815 ;
     RECT  2.16 104.085 62.64 104.355 ;
     RECT  2.16 104.625 62.64 104.895 ;
     RECT  2.16 105.165 62.64 105.435 ;
     RECT  2.16 105.705 62.64 105.975 ;
     RECT  2.16 106.245 62.64 106.515 ;
     RECT  2.16 106.785 62.64 107.055 ;
     RECT  2.16 107.325 62.64 107.595 ;
     RECT  2.16 107.865 62.64 108.135 ;
     RECT  2.16 108.405 62.64 108.675 ;
     RECT  2.16 108.945 62.64 109.215 ;
     RECT  2.16 109.485 62.64 109.755 ;
     RECT  2.16 110.025 62.64 110.295 ;
     RECT  2.16 110.565 62.64 110.835 ;
     RECT  2.16 111.105 62.64 111.375 ;
     RECT  2.16 111.645 62.64 111.915 ;
     RECT  2.16 112.185 62.64 112.455 ;
     RECT  2.16 112.725 62.64 112.995 ;
     RECT  2.16 113.265 62.64 113.535 ;
     RECT  2.16 113.805 62.64 114.075 ;
     RECT  2.16 114.345 62.64 114.615 ;
     RECT  2.16 114.885 62.64 115.155 ;
     RECT  2.16 115.425 62.64 115.695 ;
     RECT  2.16 115.965 62.64 116.235 ;
     RECT  2.16 116.505 62.64 116.775 ;
     RECT  2.16 117.045 62.64 117.315 ;
     RECT  2.16 117.585 62.64 117.855 ;
     RECT  2.16 118.125 62.64 118.395 ;
     RECT  2.16 118.665 62.64 118.935 ;
     RECT  2.16 119.205 62.64 119.475 ;
     RECT  2.16 119.745 62.64 120.015 ;
     RECT  2.16 120.285 62.64 120.555 ;
     RECT  2.16 120.825 62.64 121.095 ;
     RECT  2.16 121.365 62.64 121.635 ;
     RECT  2.16 121.905 62.64 122.175 ;
     RECT  2.16 122.445 62.64 122.715 ;
     RECT  2.16 122.985 62.64 123.255 ;
     RECT  2.16 123.525 62.64 123.795 ;
     RECT  2.16 124.065 62.64 124.335 ;
     RECT  2.16 124.605 62.64 124.875 ;
     RECT  2.16 125.145 62.64 125.415 ;
     RECT  2.16 125.685 62.64 125.955 ;
     RECT  2.16 126.225 62.64 126.495 ;
     RECT  2.16 126.765 62.64 127.035 ;
     RECT  2.16 127.305 62.64 127.44 ;
    LAYER RVTP ;
     RECT  2.16 2.295 62.64 2.565 ;
     RECT  2.16 2.835 62.64 3.105 ;
     RECT  2.16 3.375 62.64 3.645 ;
     RECT  2.16 3.915 62.64 4.185 ;
     RECT  2.16 4.455 62.64 4.725 ;
     RECT  2.16 4.995 62.64 5.265 ;
     RECT  2.16 5.535 62.64 5.805 ;
     RECT  2.16 6.075 62.64 6.345 ;
     RECT  2.16 6.615 62.64 6.885 ;
     RECT  2.16 7.155 62.64 7.425 ;
     RECT  2.16 7.695 62.64 7.965 ;
     RECT  2.16 8.235 62.64 8.505 ;
     RECT  2.16 8.775 62.64 9.045 ;
     RECT  2.16 9.315 62.64 9.585 ;
     RECT  2.16 9.855 62.64 10.125 ;
     RECT  2.16 10.395 62.64 10.665 ;
     RECT  2.16 10.935 62.64 11.205 ;
     RECT  2.16 11.475 62.64 11.745 ;
     RECT  2.16 12.015 62.64 12.285 ;
     RECT  2.16 12.555 62.64 12.825 ;
     RECT  2.16 13.095 62.64 13.365 ;
     RECT  2.16 13.635 62.64 13.905 ;
     RECT  2.16 14.175 62.64 14.445 ;
     RECT  2.16 14.715 62.64 14.985 ;
     RECT  2.16 15.255 62.64 15.525 ;
     RECT  2.16 15.795 62.64 16.065 ;
     RECT  2.16 16.335 62.64 16.605 ;
     RECT  2.16 16.875 62.64 17.145 ;
     RECT  2.16 17.415 62.64 17.685 ;
     RECT  2.16 17.955 62.64 18.225 ;
     RECT  2.16 18.495 62.64 18.765 ;
     RECT  2.16 19.035 62.64 19.305 ;
     RECT  2.16 19.575 62.64 19.845 ;
     RECT  2.16 20.115 62.64 20.385 ;
     RECT  2.16 20.655 62.64 20.925 ;
     RECT  2.16 21.195 62.64 21.465 ;
     RECT  2.16 21.735 62.64 22.005 ;
     RECT  2.16 22.275 62.64 22.545 ;
     RECT  2.16 22.815 62.64 23.085 ;
     RECT  2.16 23.355 62.64 23.625 ;
     RECT  2.16 23.895 62.64 24.165 ;
     RECT  2.16 24.435 62.64 24.705 ;
     RECT  2.16 24.975 62.64 25.245 ;
     RECT  2.16 25.515 62.64 25.785 ;
     RECT  2.16 26.055 62.64 26.325 ;
     RECT  2.16 26.595 62.64 26.865 ;
     RECT  2.16 27.135 62.64 27.405 ;
     RECT  2.16 27.675 62.64 27.945 ;
     RECT  2.16 28.215 62.64 28.485 ;
     RECT  2.16 28.755 62.64 29.025 ;
     RECT  2.16 29.295 62.64 29.565 ;
     RECT  2.16 29.835 62.64 30.105 ;
     RECT  2.16 30.375 62.64 30.645 ;
     RECT  2.16 30.915 62.64 31.185 ;
     RECT  2.16 31.455 62.64 31.725 ;
     RECT  2.16 31.995 62.64 32.265 ;
     RECT  2.16 32.535 62.64 32.805 ;
     RECT  2.16 33.075 62.64 33.345 ;
     RECT  2.16 33.615 62.64 33.885 ;
     RECT  2.16 34.155 62.64 34.425 ;
     RECT  2.16 34.695 62.64 34.965 ;
     RECT  2.16 35.235 62.64 35.505 ;
     RECT  2.16 35.775 62.64 36.045 ;
     RECT  2.16 36.315 62.64 36.585 ;
     RECT  2.16 36.855 62.64 37.125 ;
     RECT  2.16 37.395 62.64 37.665 ;
     RECT  2.16 37.935 62.64 38.205 ;
     RECT  2.16 38.475 62.64 38.745 ;
     RECT  2.16 39.015 62.64 39.285 ;
     RECT  2.16 39.555 62.64 39.825 ;
     RECT  2.16 40.095 62.64 40.365 ;
     RECT  2.16 40.635 62.64 40.905 ;
     RECT  2.16 41.175 62.64 41.445 ;
     RECT  2.16 41.715 62.64 41.985 ;
     RECT  2.16 42.255 62.64 42.525 ;
     RECT  2.16 42.795 62.64 43.065 ;
     RECT  2.16 43.335 62.64 43.605 ;
     RECT  2.16 43.875 62.64 44.145 ;
     RECT  2.16 44.415 62.64 44.685 ;
     RECT  2.16 44.955 62.64 45.225 ;
     RECT  2.16 45.495 62.64 45.765 ;
     RECT  2.16 46.035 62.64 46.305 ;
     RECT  2.16 46.575 62.64 46.845 ;
     RECT  2.16 47.115 62.64 47.385 ;
     RECT  2.16 47.655 62.64 47.925 ;
     RECT  2.16 48.195 62.64 48.465 ;
     RECT  2.16 48.735 62.64 49.005 ;
     RECT  2.16 49.275 62.64 49.545 ;
     RECT  2.16 49.815 62.64 50.085 ;
     RECT  2.16 50.355 62.64 50.625 ;
     RECT  2.16 50.895 62.64 51.165 ;
     RECT  2.16 51.435 62.64 51.705 ;
     RECT  2.16 51.975 62.64 52.245 ;
     RECT  2.16 52.515 62.64 52.785 ;
     RECT  2.16 53.055 62.64 53.325 ;
     RECT  2.16 53.595 62.64 53.865 ;
     RECT  2.16 54.135 62.64 54.405 ;
     RECT  2.16 54.675 62.64 54.945 ;
     RECT  2.16 55.215 62.64 55.485 ;
     RECT  2.16 55.755 62.64 56.025 ;
     RECT  2.16 56.295 62.64 56.565 ;
     RECT  2.16 56.835 62.64 57.105 ;
     RECT  2.16 57.375 62.64 57.645 ;
     RECT  2.16 57.915 62.64 58.185 ;
     RECT  2.16 58.455 62.64 58.725 ;
     RECT  2.16 58.995 62.64 59.265 ;
     RECT  2.16 59.535 62.64 59.805 ;
     RECT  2.16 60.075 62.64 60.345 ;
     RECT  2.16 60.615 62.64 60.885 ;
     RECT  2.16 61.155 62.64 61.425 ;
     RECT  2.16 61.695 62.64 61.965 ;
     RECT  2.16 62.235 62.64 62.505 ;
     RECT  2.16 62.775 62.64 63.045 ;
     RECT  2.16 63.315 62.64 63.585 ;
     RECT  2.16 63.855 62.64 64.125 ;
     RECT  2.16 64.395 62.64 64.665 ;
     RECT  2.16 64.935 62.64 65.205 ;
     RECT  2.16 65.475 62.64 65.745 ;
     RECT  2.16 66.015 62.64 66.285 ;
     RECT  2.16 66.555 62.64 66.825 ;
     RECT  2.16 67.095 62.64 67.365 ;
     RECT  2.16 67.635 62.64 67.905 ;
     RECT  2.16 68.175 62.64 68.445 ;
     RECT  2.16 68.715 62.64 68.985 ;
     RECT  2.16 69.255 62.64 69.525 ;
     RECT  2.16 69.795 62.64 70.065 ;
     RECT  2.16 70.335 62.64 70.605 ;
     RECT  2.16 70.875 62.64 71.145 ;
     RECT  2.16 71.415 62.64 71.685 ;
     RECT  2.16 71.955 62.64 72.225 ;
     RECT  2.16 72.495 62.64 72.765 ;
     RECT  2.16 73.035 62.64 73.305 ;
     RECT  2.16 73.575 62.64 73.845 ;
     RECT  2.16 74.115 62.64 74.385 ;
     RECT  2.16 74.655 62.64 74.925 ;
     RECT  2.16 75.195 62.64 75.465 ;
     RECT  2.16 75.735 62.64 76.005 ;
     RECT  2.16 76.275 62.64 76.545 ;
     RECT  2.16 76.815 62.64 77.085 ;
     RECT  2.16 77.355 62.64 77.625 ;
     RECT  2.16 77.895 62.64 78.165 ;
     RECT  2.16 78.435 62.64 78.705 ;
     RECT  2.16 78.975 62.64 79.245 ;
     RECT  2.16 79.515 62.64 79.785 ;
     RECT  2.16 80.055 62.64 80.325 ;
     RECT  2.16 80.595 62.64 80.865 ;
     RECT  2.16 81.135 62.64 81.405 ;
     RECT  2.16 81.675 62.64 81.945 ;
     RECT  2.16 82.215 62.64 82.485 ;
     RECT  2.16 82.755 62.64 83.025 ;
     RECT  2.16 83.295 62.64 83.565 ;
     RECT  2.16 83.835 62.64 84.105 ;
     RECT  2.16 84.375 62.64 84.645 ;
     RECT  2.16 84.915 62.64 85.185 ;
     RECT  2.16 85.455 62.64 85.725 ;
     RECT  2.16 85.995 62.64 86.265 ;
     RECT  2.16 86.535 62.64 86.805 ;
     RECT  2.16 87.075 62.64 87.345 ;
     RECT  2.16 87.615 62.64 87.885 ;
     RECT  2.16 88.155 62.64 88.425 ;
     RECT  2.16 88.695 62.64 88.965 ;
     RECT  2.16 89.235 62.64 89.505 ;
     RECT  2.16 89.775 62.64 90.045 ;
     RECT  2.16 90.315 62.64 90.585 ;
     RECT  2.16 90.855 62.64 91.125 ;
     RECT  2.16 91.395 62.64 91.665 ;
     RECT  2.16 91.935 62.64 92.205 ;
     RECT  2.16 92.475 62.64 92.745 ;
     RECT  2.16 93.015 62.64 93.285 ;
     RECT  2.16 93.555 62.64 93.825 ;
     RECT  2.16 94.095 62.64 94.365 ;
     RECT  2.16 94.635 62.64 94.905 ;
     RECT  2.16 95.175 62.64 95.445 ;
     RECT  2.16 95.715 62.64 95.985 ;
     RECT  2.16 96.255 62.64 96.525 ;
     RECT  2.16 96.795 62.64 97.065 ;
     RECT  2.16 97.335 62.64 97.605 ;
     RECT  2.16 97.875 62.64 98.145 ;
     RECT  2.16 98.415 62.64 98.685 ;
     RECT  2.16 98.955 62.64 99.225 ;
     RECT  2.16 99.495 62.64 99.765 ;
     RECT  2.16 100.035 62.64 100.305 ;
     RECT  2.16 100.575 62.64 100.845 ;
     RECT  2.16 101.115 62.64 101.385 ;
     RECT  2.16 101.655 62.64 101.925 ;
     RECT  2.16 102.195 62.64 102.465 ;
     RECT  2.16 102.735 62.64 103.005 ;
     RECT  2.16 103.275 62.64 103.545 ;
     RECT  2.16 103.815 62.64 104.085 ;
     RECT  2.16 104.355 62.64 104.625 ;
     RECT  2.16 104.895 62.64 105.165 ;
     RECT  2.16 105.435 62.64 105.705 ;
     RECT  2.16 105.975 62.64 106.245 ;
     RECT  2.16 106.515 62.64 106.785 ;
     RECT  2.16 107.055 62.64 107.325 ;
     RECT  2.16 107.595 62.64 107.865 ;
     RECT  2.16 108.135 62.64 108.405 ;
     RECT  2.16 108.675 62.64 108.945 ;
     RECT  2.16 109.215 62.64 109.485 ;
     RECT  2.16 109.755 62.64 110.025 ;
     RECT  2.16 110.295 62.64 110.565 ;
     RECT  2.16 110.835 62.64 111.105 ;
     RECT  2.16 111.375 62.64 111.645 ;
     RECT  2.16 111.915 62.64 112.185 ;
     RECT  2.16 112.455 62.64 112.725 ;
     RECT  2.16 112.995 62.64 113.265 ;
     RECT  2.16 113.535 62.64 113.805 ;
     RECT  2.16 114.075 62.64 114.345 ;
     RECT  2.16 114.615 62.64 114.885 ;
     RECT  2.16 115.155 62.64 115.425 ;
     RECT  2.16 115.695 62.64 115.965 ;
     RECT  2.16 116.235 62.64 116.505 ;
     RECT  2.16 116.775 62.64 117.045 ;
     RECT  2.16 117.315 62.64 117.585 ;
     RECT  2.16 117.855 62.64 118.125 ;
     RECT  2.16 118.395 62.64 118.665 ;
     RECT  2.16 118.935 62.64 119.205 ;
     RECT  2.16 119.475 62.64 119.745 ;
     RECT  2.16 120.015 62.64 120.285 ;
     RECT  2.16 120.555 62.64 120.825 ;
     RECT  2.16 121.095 62.64 121.365 ;
     RECT  2.16 121.635 62.64 121.905 ;
     RECT  2.16 122.175 62.64 122.445 ;
     RECT  2.16 122.715 62.64 122.985 ;
     RECT  2.16 123.255 62.64 123.525 ;
     RECT  2.16 123.795 62.64 124.065 ;
     RECT  2.16 124.335 62.64 124.605 ;
     RECT  2.16 124.875 62.64 125.145 ;
     RECT  2.16 125.415 62.64 125.685 ;
     RECT  2.16 125.955 62.64 126.225 ;
     RECT  2.16 126.495 62.64 126.765 ;
     RECT  2.16 127.035 62.64 127.305 ;
    LAYER M1 ;
     RECT  2.16 2.151 62.64 127.449 ;
    LAYER M2 ;
     RECT  0.103 80.91 0.139 80.928 ;
     RECT  0.103 86.616 0.139 86.634 ;
     RECT  0.103 89.406 0.139 89.424 ;
     RECT  0.103 76.086 0.175 76.104 ;
     RECT  0.139 76.896 0.175 76.914 ;
     RECT  0.103 36.126 0.203 36.144 ;
     RECT  0.175 72.468 0.275 72.486 ;
     RECT  0.139 86.274 0.391 86.634 ;
     RECT  0.391 86.274 0.427 86.679 ;
     RECT  0.103 68.886 0.463 68.904 ;
     RECT  0.103 70.686 0.463 70.704 ;
     RECT  0.103 79.686 0.463 79.704 ;
     RECT  0.139 80.766 0.463 80.928 ;
     RECT  0.427 86.274 0.463 86.904 ;
     RECT  0.103 14.256 0.499 14.274 ;
     RECT  0.427 69.876 0.527 69.894 ;
     RECT  0.103 56.61 0.535 57.132 ;
     RECT  0.463 58.968 0.535 58.986 ;
     RECT  0.463 70.686 0.535 71.064 ;
     RECT  0.463 79.686 0.535 80.928 ;
     RECT  0.103 85.464 0.535 85.482 ;
     RECT  0.463 86.238 0.535 87.219 ;
     RECT  0.103 88.236 0.535 88.254 ;
     RECT  0.103 122.616 0.535 123.246 ;
     RECT  0.535 58.662 0.563 58.986 ;
     RECT  0.535 70.074 0.563 71.064 ;
     RECT  0.535 121.806 0.643 121.824 ;
     RECT  0.643 120.834 0.743 121.824 ;
     RECT  0.103 15.498 0.823 15.516 ;
     RECT  0.823 15.498 0.859 15.894 ;
     RECT  0.031 21.474 1.039 21.492 ;
     RECT  1.039 21.204 1.075 21.492 ;
     RECT  0.535 104.094 1.111 104.112 ;
     RECT  0.499 13.572 1.147 14.274 ;
     RECT  0.859 15.066 1.147 15.894 ;
     RECT  0.463 68.616 1.147 68.904 ;
     RECT  0.103 8.856 1.363 8.874 ;
     RECT  0.103 9.711 1.363 9.729 ;
     RECT  1.075 20.97 1.399 21.492 ;
     RECT  0.103 6.858 1.427 6.876 ;
     RECT  1.147 13.572 1.471 15.894 ;
     RECT  1.147 68.382 1.471 68.904 ;
     RECT  1.435 18.036 1.507 18.054 ;
     RECT  0.139 89.406 1.507 90.612 ;
     RECT  0.103 91.746 1.507 92.304 ;
     RECT  0.103 128.511 1.543 128.529 ;
     RECT  0.535 26.334 1.579 26.352 ;
     RECT  0.535 84.726 1.579 88.254 ;
     RECT  1.507 89.406 1.579 92.304 ;
     RECT  1.363 65.988 1.651 66.006 ;
     RECT  1.507 30.456 1.687 30.474 ;
     RECT  0.535 56.61 1.723 57.294 ;
     RECT  0.643 65.142 1.723 65.16 ;
     RECT  1.651 65.988 1.723 66.078 ;
     RECT  1.723 2.646 1.759 2.664 ;
     RECT  1.723 19.116 1.975 19.134 ;
     RECT  1.471 67.914 1.975 68.904 ;
     RECT  1.471 13.572 2.047 16.164 ;
     RECT  1.507 17.316 2.047 18.054 ;
     RECT  1.723 65.142 2.047 66.078 ;
     RECT  1.543 67.14 2.047 67.158 ;
     RECT  0.563 70.074 2.047 70.974 ;
     RECT  2.011 72.27 2.083 72.288 ;
     RECT  1.759 2.106 2.16 2.664 ;
     RECT  1.363 8.856 2.16 9.729 ;
     RECT  2.047 13.572 2.16 18.054 ;
     RECT  1.975 19.116 2.16 19.602 ;
     RECT  1.399 20.394 2.16 21.492 ;
     RECT  2.119 22.626 2.16 22.644 ;
     RECT  1.579 26.334 2.16 26.784 ;
     RECT  1.615 29.034 2.16 29.052 ;
     RECT  1.687 29.916 2.16 30.474 ;
     RECT  2.083 32.886 2.16 32.904 ;
     RECT  2.155 39.636 2.16 39.654 ;
     RECT  1.111 41.076 2.16 41.094 ;
     RECT  1.723 56.07 2.16 57.294 ;
     RECT  0.563 58.662 2.16 58.68 ;
     RECT  0.103 62.406 2.16 62.424 ;
     RECT  2.047 64.872 2.16 67.158 ;
     RECT  1.975 67.914 2.16 69.084 ;
     RECT  2.047 69.876 2.16 70.974 ;
     RECT  2.083 72.27 2.16 72.324 ;
     RECT  0.427 73.278 2.16 73.296 ;
     RECT  0.175 76.086 2.16 76.914 ;
     RECT  2.119 77.67 2.16 77.688 ;
     RECT  0.535 79.686 2.16 83.214 ;
     RECT  1.579 84.726 2.16 92.304 ;
     RECT  1.687 93.492 2.16 93.51 ;
     RECT  1.975 94.338 2.16 94.356 ;
     RECT  0.535 96.3 2.16 96.318 ;
     RECT  0.535 98.586 2.16 98.604 ;
     RECT  0.103 100.656 2.16 100.674 ;
     RECT  0.535 103.014 2.16 103.032 ;
     RECT  1.111 103.824 2.16 104.112 ;
     RECT  0.103 105.984 2.16 106.578 ;
     RECT  0.103 108.846 2.16 108.864 ;
     RECT  2.083 110.646 2.16 110.664 ;
     RECT  0.535 112.266 2.16 112.284 ;
     RECT  0.535 116.244 2.16 116.262 ;
     RECT  0.535 119.016 2.16 119.034 ;
     RECT  0.103 119.916 2.16 119.934 ;
     RECT  0.743 121.806 2.16 121.824 ;
     RECT  0.535 122.616 2.16 124.254 ;
     RECT  2.16 2.106 2.299 127.449 ;
     RECT  1.543 128.511 2.651 128.844 ;
     RECT  2.299 2.034 3.479 127.449 ;
     RECT  2.651 128.511 9.923 128.529 ;
     RECT  3.479 2.151 10.579 127.449 ;
     RECT  10.579 2.151 10.715 127.719 ;
     RECT  16.411 128.826 16.547 128.844 ;
     RECT  10.715 2.151 23.899 127.449 ;
     RECT  23.899 2.151 23.999 127.719 ;
     RECT  23.999 2.151 29.299 127.449 ;
     RECT  29.299 2.151 29.435 127.53 ;
     RECT  29.435 2.151 34.771 127.449 ;
     RECT  34.771 2.151 34.907 127.53 ;
     RECT  35.095 0.036 35.159 0.054 ;
     RECT  34.907 2.151 40.315 127.449 ;
     RECT  40.315 2.151 40.451 127.53 ;
     RECT  41.467 0.036 41.567 0.054 ;
     RECT  44.599 0.036 44.663 0.054 ;
     RECT  45.535 0.036 45.599 0.054 ;
     RECT  46.435 0.036 46.499 0.054 ;
     RECT  46.723 128.826 46.787 128.844 ;
     RECT  48.739 0.036 50.135 0.054 ;
     RECT  57.595 129.546 57.695 129.564 ;
     RECT  40.451 2.151 60.835 127.449 ;
     RECT  60.835 2.151 62.64 127.566 ;
     RECT  62.64 2.376 62.699 7.884 ;
     RECT  62.64 9.756 62.699 12.474 ;
     RECT  62.64 61.596 62.699 87.174 ;
     RECT  62.64 100.926 62.699 116.964 ;
     RECT  62.64 117.756 62.699 127.566 ;
     RECT  62.699 61.596 62.735 71.064 ;
     RECT  62.699 72.126 62.735 87.174 ;
     RECT  62.64 87.966 62.735 100.134 ;
     RECT  62.699 100.926 62.735 108.774 ;
     RECT  62.699 109.836 62.735 116.964 ;
     RECT  62.699 117.756 62.735 121.464 ;
     RECT  62.735 81.756 62.771 87.174 ;
     RECT  62.735 100.926 62.771 103.914 ;
     RECT  62.735 111.186 62.771 116.964 ;
     RECT  62.771 100.926 62.843 103.878 ;
     RECT  62.64 13.266 63.095 13.284 ;
     RECT  62.699 2.376 63.203 6.264 ;
     RECT  62.64 15.606 63.203 42.354 ;
     RECT  63.203 4.626 63.239 6.264 ;
     RECT  62.699 9.756 63.239 10.584 ;
     RECT  63.203 17.856 63.239 42.354 ;
     RECT  63.239 4.626 63.275 4.644 ;
     RECT  63.239 18.126 63.275 42.354 ;
     RECT  62.64 43.416 63.275 44.604 ;
     RECT  62.64 45.396 63.275 54.738 ;
     RECT  62.64 57.546 63.275 60.534 ;
     RECT  62.735 63.486 63.275 71.064 ;
     RECT  62.735 72.126 63.275 74.754 ;
     RECT  62.735 75.636 63.275 80.784 ;
     RECT  62.771 81.756 63.275 86.364 ;
     RECT  62.771 87.156 63.275 87.174 ;
     RECT  62.735 88.236 63.275 93.474 ;
     RECT  62.735 94.446 63.275 97.164 ;
     RECT  62.843 100.926 63.275 102.294 ;
     RECT  62.771 111.654 63.275 116.964 ;
     RECT  63.203 2.376 63.311 3.834 ;
     RECT  63.275 21.402 63.311 21.654 ;
     RECT  63.275 23.796 63.311 25.974 ;
     RECT  63.275 26.91 63.311 29.52 ;
     RECT  63.275 57.546 63.311 60.264 ;
     RECT  63.275 63.486 63.311 68.004 ;
     RECT  63.275 75.636 63.311 79.542 ;
     RECT  63.275 81.756 63.311 84.942 ;
     RECT  63.275 88.236 63.311 93.204 ;
     RECT  63.275 96.066 63.311 97.164 ;
     RECT  63.275 101.466 63.311 102.294 ;
     RECT  62.735 104.706 63.311 106.578 ;
     RECT  62.735 107.37 63.311 108.774 ;
     RECT  63.275 111.654 63.311 116.424 ;
     RECT  62.735 119.916 63.311 121.464 ;
     RECT  62.699 122.346 63.311 127.566 ;
     RECT  63.275 72.774 63.347 73.26 ;
     RECT  63.311 88.236 63.347 88.524 ;
     RECT  63.311 89.361 63.347 91.854 ;
     RECT  63.311 122.346 63.347 125.946 ;
     RECT  63.311 126.702 63.347 127.566 ;
     RECT  63.311 26.91 63.383 28.134 ;
     RECT  63.311 28.926 63.383 29.52 ;
     RECT  63.275 46.206 63.383 54.738 ;
     RECT  62.735 61.596 63.383 62.73 ;
     RECT  63.311 66.528 63.383 67.824 ;
     RECT  63.275 68.886 63.383 71.064 ;
     RECT  63.275 74.664 63.383 74.754 ;
     RECT  63.311 77.256 63.383 79.542 ;
     RECT  63.347 88.506 63.383 88.524 ;
     RECT  63.275 37.206 63.419 42.354 ;
     RECT  63.383 70.731 63.419 71.064 ;
     RECT  63.347 72.936 63.419 73.26 ;
     RECT  63.311 84.456 63.419 84.942 ;
     RECT  63.347 89.361 63.419 90.648 ;
     RECT  63.347 91.521 63.419 91.854 ;
     RECT  63.419 39.186 63.455 42.354 ;
     RECT  63.347 125.316 63.563 125.946 ;
     RECT  63.203 15.606 63.635 16.704 ;
     RECT  63.635 15.606 63.671 16.362 ;
     RECT  63.347 126.702 63.671 126.72 ;
     RECT  63.239 9.864 63.743 10.584 ;
     RECT  63.671 16.236 63.743 16.362 ;
     RECT  63.743 9.864 63.815 10.494 ;
     RECT  63.275 30.276 63.815 36.144 ;
     RECT  63.383 46.206 63.815 54.594 ;
     RECT  63.383 61.596 63.815 62.424 ;
     RECT  62.699 7.326 63.851 7.884 ;
     RECT  63.815 10.026 63.851 10.494 ;
     RECT  62.699 11.556 63.851 12.474 ;
     RECT  63.275 18.126 63.851 20.574 ;
     RECT  63.311 21.546 63.851 21.654 ;
     RECT  63.275 22.446 63.851 23.004 ;
     RECT  63.311 23.796 63.851 24.084 ;
     RECT  63.383 27.306 63.851 28.134 ;
     RECT  63.383 28.926 63.851 28.944 ;
     RECT  63.815 30.276 63.851 33.984 ;
     RECT  63.815 34.776 63.851 36.144 ;
     RECT  63.419 37.206 63.851 38.196 ;
     RECT  63.455 39.186 63.851 42.174 ;
     RECT  63.275 43.506 63.851 44.604 ;
     RECT  63.275 45.396 63.851 45.414 ;
     RECT  63.815 46.206 63.851 48.654 ;
     RECT  63.815 49.59 63.851 51.426 ;
     RECT  63.815 53.226 63.851 53.244 ;
     RECT  62.64 55.566 63.851 56.754 ;
     RECT  63.311 57.546 63.851 58.014 ;
     RECT  63.311 59.076 63.851 60.264 ;
     RECT  63.815 61.704 63.851 62.424 ;
     RECT  63.311 63.486 63.851 65.664 ;
     RECT  63.383 66.996 63.851 67.824 ;
     RECT  63.419 72.936 63.851 72.954 ;
     RECT  63.311 75.636 63.851 75.96 ;
     RECT  63.311 81.756 63.851 82.584 ;
     RECT  63.311 83.466 63.851 83.484 ;
     RECT  63.419 89.676 63.851 90.414 ;
     RECT  63.311 92.916 63.851 93.204 ;
     RECT  62.735 97.956 63.851 100.134 ;
     RECT  63.311 101.466 63.851 102.222 ;
     RECT  62.843 103.176 63.851 103.878 ;
     RECT  63.311 106.56 63.851 106.578 ;
     RECT  63.311 107.37 63.851 108.504 ;
     RECT  63.311 111.654 63.851 113.454 ;
     RECT  63.311 114.246 63.851 116.424 ;
     RECT  62.735 117.756 63.851 119.034 ;
     RECT  63.311 119.916 63.851 120.474 ;
     RECT  63.311 25.29 63.887 25.974 ;
     RECT  63.851 30.456 63.887 32.094 ;
     RECT  63.851 39.636 63.887 41.814 ;
     RECT  63.851 44.586 63.887 44.604 ;
     RECT  63.851 49.896 63.887 50.814 ;
     RECT  63.851 55.926 63.887 55.944 ;
     RECT  63.851 60.246 63.887 60.264 ;
     RECT  63.851 67.806 63.887 67.824 ;
     RECT  63.383 68.886 63.887 69.984 ;
     RECT  63.851 75.636 63.887 75.654 ;
     RECT  63.383 78.372 63.887 79.542 ;
     RECT  63.275 80.604 63.887 80.784 ;
     RECT  63.419 84.456 63.887 84.6 ;
     RECT  63.851 89.676 63.887 90 ;
     RECT  63.419 91.836 63.887 91.854 ;
     RECT  63.275 95.148 63.887 95.274 ;
     RECT  63.311 96.066 63.887 96.084 ;
     RECT  63.311 96.876 63.887 96.894 ;
     RECT  63.851 98.424 63.887 98.442 ;
     RECT  63.851 100.116 63.887 100.134 ;
     RECT  63.851 103.86 63.887 103.878 ;
     RECT  63.851 108.306 63.887 108.504 ;
     RECT  62.735 109.836 63.887 110.214 ;
     RECT  63.851 111.996 63.887 113.454 ;
     RECT  63.851 115.326 63.887 115.794 ;
     RECT  63.851 118.296 63.887 119.034 ;
     RECT  63.851 120.186 63.887 120.474 ;
     RECT  63.347 122.346 63.887 122.364 ;
     RECT  63.347 123.426 63.887 124.524 ;
     RECT  63.563 125.316 63.887 125.874 ;
     RECT  63.887 69.426 63.923 69.984 ;
     RECT  63.887 89.676 63.923 89.694 ;
     RECT  63.887 120.456 63.923 120.474 ;
     RECT  63.887 123.696 63.923 123.714 ;
     RECT  63.887 124.506 63.923 124.524 ;
     RECT  63.347 127.548 64.139 127.566 ;
     RECT  63.311 2.376 64.643 3.366 ;
     RECT  63.239 5.436 64.643 6.264 ;
     RECT  64.643 2.376 64.679 2.592 ;
     RECT  63.851 7.326 64.679 7.344 ;
     RECT  63.851 12.366 64.679 12.474 ;
     RECT  63.851 18.126 64.679 19.674 ;
     RECT  63.851 37.476 64.679 37.62 ;
     RECT  63.851 46.854 64.679 48.564 ;
     RECT  63.851 63.756 64.679 65.232 ;
     RECT  64.679 2.376 64.715 2.394 ;
     RECT  64.643 3.348 64.715 3.366 ;
     RECT  64.643 5.436 64.715 5.454 ;
     RECT  64.643 6.246 64.715 6.264 ;
     RECT  63.851 10.476 64.715 10.494 ;
     RECT  64.679 12.366 64.715 12.384 ;
     RECT  64.679 18.936 64.715 19.674 ;
     RECT  63.851 21.546 64.715 21.564 ;
     RECT  63.887 25.29 64.715 25.812 ;
     RECT  63.887 30.456 64.715 31.824 ;
     RECT  63.851 34.776 64.715 34.992 ;
     RECT  64.679 37.476 64.715 37.494 ;
     RECT  63.887 39.996 64.715 41.814 ;
     RECT  63.851 43.614 64.715 43.632 ;
     RECT  64.679 46.854 64.715 46.872 ;
     RECT  64.679 47.736 64.715 47.754 ;
     RECT  64.679 48.546 64.715 48.564 ;
     RECT  63.887 49.986 64.715 50.814 ;
     RECT  63.815 52.254 64.715 52.272 ;
     RECT  63.815 54.036 64.715 54.594 ;
     RECT  63.851 57.546 64.715 57.564 ;
     RECT  63.851 59.076 64.715 59.094 ;
     RECT  63.851 61.866 64.715 61.884 ;
     RECT  64.679 63.756 64.715 63.774 ;
     RECT  64.679 64.566 64.715 65.232 ;
     RECT  63.923 69.426 64.715 69.444 ;
     RECT  63.419 71.046 64.715 71.064 ;
     RECT  63.383 74.736 64.715 74.754 ;
     RECT  63.383 77.256 64.715 77.274 ;
     RECT  63.887 78.372 64.715 78.579 ;
     RECT  63.887 79.416 64.715 79.434 ;
     RECT  63.851 81.756 64.715 81.972 ;
     RECT  63.887 84.456 64.715 84.474 ;
     RECT  63.887 95.148 64.715 95.166 ;
     RECT  63.311 104.976 64.715 104.994 ;
     RECT  63.851 107.37 64.715 107.388 ;
     RECT  63.887 108.306 64.715 108.324 ;
     RECT  63.887 113.436 64.715 113.454 ;
     RECT  63.887 118.332 64.715 119.034 ;
     RECT  63.311 121.446 64.715 121.464 ;
     RECT  64.679 18.126 64.751 18.144 ;
     RECT  63.851 11.556 64.787 11.574 ;
     RECT  63.743 16.236 64.787 16.254 ;
     RECT  64.715 64.566 64.787 64.584 ;
    LAYER M3 ;
     RECT  35.1 0.012 35.118 0.031 ;
     RECT  40.104 0.012 49.662 0.031 ;
     RECT  35.1 0.031 35.154 0.059 ;
     RECT  29.7 0.012 29.718 0.125 ;
     RECT  1.728 0.667 1.746 1.147 ;
     RECT  3.024 0.907 3.042 1.147 ;
     RECT  62.676 0.667 62.694 1.147 ;
     RECT  55.26 1.387 55.278 1.627 ;
     RECT  1.728 1.147 3.042 1.915 ;
     RECT  64.692 0.907 64.71 1.915 ;
     RECT  1.728 1.915 3.15 2.029 ;
     RECT  3.924 1.387 3.942 2.029 ;
     RECT  35.136 0.059 35.154 2.143 ;
     RECT  61.956 1.147 62.694 2.143 ;
     RECT  64.656 1.915 64.71 2.155 ;
     RECT  40.104 0.031 50.13 2.263 ;
     RECT  0.108 2.155 0.126 2.285 ;
     RECT  61.815 2.143 62.694 2.371 ;
     RECT  61.344 2.371 62.694 2.395 ;
     RECT  64.62 2.155 64.71 2.399 ;
     RECT  7.815 2.143 7.905 2.413 ;
     RECT  13.215 2.143 13.305 2.413 ;
     RECT  18.615 2.143 18.705 2.413 ;
     RECT  24.015 2.143 24.105 2.413 ;
     RECT  29.415 2.143 29.505 2.413 ;
     RECT  51.015 2.143 51.105 2.413 ;
     RECT  56.415 2.143 56.505 2.413 ;
     RECT  61.344 2.395 63.27 2.489 ;
     RECT  60.696 2.605 60.714 2.641 ;
     RECT  1.728 2.029 3.942 2.669 ;
     RECT  64.62 2.399 64.674 2.669 ;
     RECT  54.684 1.627 55.278 2.759 ;
     RECT  58.068 2.641 58.086 2.759 ;
     RECT  39.816 2.263 50.13 2.767 ;
     RECT  53.784 2.641 53.802 2.767 ;
     RECT  60.66 2.641 60.714 2.767 ;
     RECT  2.304 2.669 3.942 2.803 ;
     RECT  2.304 2.803 3.978 3.001 ;
     RECT  53.784 2.767 54.198 3.001 ;
     RECT  53.532 3.001 54.198 3.029 ;
     RECT  57.852 2.911 57.87 3.029 ;
     RECT  39.348 2.767 50.13 3.109 ;
     RECT  58.68 2.875 58.698 3.137 ;
     RECT  39.096 3.109 50.13 3.145 ;
     RECT  56.415 2.413 56.697 3.145 ;
     RECT  52.38 2.803 52.398 3.181 ;
     RECT  2.304 3.001 4.518 3.209 ;
     RECT  51.015 2.413 51.297 3.271 ;
     RECT  52.38 3.181 52.722 3.271 ;
     RECT  53.532 3.029 53.802 3.271 ;
     RECT  59.688 2.605 59.706 3.307 ;
     RECT  64.692 3.163 64.71 3.371 ;
     RECT  59.292 3.307 59.706 3.379 ;
     RECT  60.444 2.767 60.714 3.379 ;
     RECT  38.7 3.145 50.13 3.415 ;
     RECT  38.304 3.415 50.13 3.569 ;
     RECT  56.376 3.145 56.697 3.569 ;
     RECT  59.292 3.379 60.714 3.569 ;
     RECT  51.015 3.271 51.354 3.577 ;
     RECT  52.38 3.271 53.802 3.577 ;
     RECT  2.415 3.209 4.518 3.649 ;
     RECT  2.415 3.649 4.554 3.685 ;
     RECT  61.815 2.489 63.27 3.811 ;
     RECT  59.292 3.569 59.886 3.839 ;
     RECT  61.815 3.811 63.306 3.917 ;
     RECT  38.376 3.569 50.13 3.947 ;
     RECT  2.415 3.685 4.698 3.955 ;
     RECT  55.116 2.759 55.278 3.955 ;
     RECT  60.984 3.847 61.002 3.955 ;
     RECT  61.815 3.917 63.27 3.955 ;
     RECT  34.815 2.143 35.154 3.991 ;
     RECT  59.868 3.839 59.886 4.019 ;
     RECT  55.008 3.955 55.278 4.081 ;
     RECT  37.62 3.721 37.638 4.109 ;
     RECT  2.34 3.955 4.698 4.117 ;
     RECT  7.815 2.413 8.097 4.117 ;
     RECT  39.348 3.947 50.13 4.117 ;
     RECT  51.015 3.577 53.802 4.117 ;
     RECT  2.34 4.117 5.058 4.171 ;
     RECT  39.348 4.117 53.802 4.217 ;
     RECT  6.84 4.117 6.858 4.253 ;
     RECT  38.376 3.947 38.394 4.301 ;
     RECT  39.384 4.217 53.802 4.351 ;
     RECT  10.044 3.919 10.062 4.379 ;
     RECT  39.384 4.351 53.838 4.415 ;
     RECT  7.815 4.117 8.802 4.451 ;
     RECT  39.384 4.415 39.402 4.451 ;
     RECT  40.215 4.415 53.838 4.459 ;
     RECT  34.272 3.991 35.154 4.487 ;
     RECT  40.215 4.459 53.91 4.495 ;
     RECT  40.215 4.495 53.982 4.801 ;
     RECT  54.72 4.081 55.278 4.801 ;
     RECT  60.984 3.955 63.27 4.829 ;
     RECT  61.272 4.829 63.27 4.919 ;
     RECT  40.215 4.801 55.278 4.991 ;
     RECT  1.98 4.171 5.058 5.161 ;
     RECT  1.98 5.161 5.634 5.269 ;
     RECT  52.056 4.991 55.278 5.269 ;
     RECT  34.815 4.487 35.154 5.305 ;
     RECT  1.98 5.269 5.994 5.341 ;
     RECT  34.815 5.305 35.298 5.459 ;
     RECT  34.815 5.459 35.118 5.501 ;
     RECT  1.98 5.341 6.066 5.531 ;
     RECT  59.292 5.575 59.31 5.729 ;
     RECT  40.215 4.991 51.297 5.737 ;
     RECT  36.036 5.611 36.054 5.845 ;
     RECT  64.692 5.419 64.71 5.899 ;
     RECT  40.215 5.737 51.318 5.971 ;
     RECT  52.056 5.269 55.386 5.971 ;
     RECT  40.215 5.971 55.386 6.107 ;
     RECT  35.964 5.845 36.054 6.115 ;
     RECT  64.656 5.899 64.71 6.139 ;
     RECT  61.272 4.919 62.694 6.151 ;
     RECT  64.62 6.139 64.71 6.179 ;
     RECT  35.964 6.115 36.126 6.269 ;
     RECT  61.236 6.151 62.694 6.269 ;
     RECT  64.656 6.179 64.71 6.269 ;
     RECT  36 6.269 36.126 6.539 ;
     RECT  57.96 6.385 57.978 6.539 ;
     RECT  36 6.539 36.09 6.575 ;
     RECT  50.904 6.107 55.386 6.691 ;
     RECT  56.415 3.569 56.697 6.691 ;
     RECT  50.904 6.691 57.33 6.809 ;
     RECT  61.38 6.269 62.694 6.809 ;
     RECT  1.98 5.531 5.67 6.853 ;
     RECT  0.108 5.899 0.126 6.881 ;
     RECT  63.828 5.131 63.846 6.907 ;
     RECT  64.656 6.269 64.674 7.147 ;
     RECT  61.38 6.809 62.097 7.223 ;
     RECT  64.656 7.147 64.71 7.243 ;
     RECT  59.256 6.385 59.274 7.349 ;
     RECT  64.656 7.243 64.782 7.349 ;
     RECT  1.404 6.853 5.67 7.465 ;
     RECT  63.792 6.907 63.846 7.627 ;
     RECT  50.904 6.809 57.222 7.861 ;
     RECT  50.868 7.861 57.222 7.889 ;
     RECT  62.964 7.387 62.982 7.915 ;
     RECT  63.756 7.627 63.846 7.915 ;
     RECT  40.215 6.107 50.13 7.933 ;
     RECT  0.108 7.915 0.126 8.155 ;
     RECT  1.404 7.465 5.706 8.155 ;
     RECT  61.815 7.223 62.097 8.155 ;
     RECT  62.964 7.915 63.846 8.155 ;
     RECT  39.492 7.933 50.13 8.203 ;
     RECT  50.868 7.889 51.297 8.203 ;
     RECT  52.056 7.889 57.222 8.339 ;
     RECT  0.108 8.155 5.706 8.401 ;
     RECT  9.972 4.531 9.99 8.401 ;
     RECT  9.648 8.401 9.99 8.429 ;
     RECT  39.492 8.203 51.297 8.429 ;
     RECT  60.984 7.933 61.002 8.429 ;
     RECT  0.108 8.401 5.742 8.473 ;
     RECT  7.815 4.451 8.097 8.491 ;
     RECT  7.815 8.491 8.73 8.537 ;
     RECT  52.056 8.339 56.697 8.537 ;
     RECT  0.108 8.473 5.922 8.545 ;
     RECT  9.648 8.429 9.666 8.581 ;
     RECT  59.292 7.393 59.31 8.699 ;
     RECT  39.492 8.429 50.13 8.971 ;
     RECT  52.056 8.537 54.09 9.383 ;
     RECT  0.108 8.545 6.174 9.391 ;
     RECT  34.815 5.501 35.097 9.391 ;
     RECT  50.868 8.429 51.297 9.391 ;
     RECT  52.056 9.383 52.47 9.391 ;
     RECT  64.764 7.349 64.782 9.403 ;
     RECT  38.916 8.971 50.13 9.419 ;
     RECT  53.352 9.383 54.09 9.499 ;
     RECT  54.828 8.537 56.697 9.499 ;
     RECT  61.056 9.019 61.074 9.499 ;
     RECT  61.815 8.155 63.846 9.499 ;
     RECT  34.776 9.391 35.097 9.509 ;
     RECT  64.692 9.403 64.782 9.533 ;
     RECT  8.82 8.581 9.666 9.545 ;
     RECT  0.108 9.391 6.282 9.653 ;
     RECT  0.108 9.653 6.21 9.734 ;
     RECT  12.168 9.283 12.186 9.779 ;
     RECT  59.832 9.859 59.85 9.883 ;
     RECT  61.056 9.499 63.846 9.883 ;
     RECT  59.832 9.883 63.846 9.931 ;
     RECT  59.688 9.931 63.846 10.049 ;
     RECT  22.392 10.021 22.41 10.057 ;
     RECT  36.072 6.575 36.09 10.085 ;
     RECT  53.352 9.499 56.697 10.121 ;
     RECT  38.772 9.481 38.79 10.157 ;
     RECT  40.032 9.419 50.13 10.165 ;
     RECT  50.868 9.391 52.47 10.165 ;
     RECT  53.352 10.121 55.494 10.165 ;
     RECT  38.808 10.165 50.13 10.205 ;
     RECT  40.032 10.205 50.13 10.229 ;
     RECT  40.215 10.229 50.13 10.291 ;
     RECT  50.868 10.165 55.494 10.291 ;
     RECT  0.828 9.734 6.21 10.399 ;
     RECT  64.764 9.533 64.782 10.411 ;
     RECT  58.392 6.667 58.41 10.471 ;
     RECT  0.828 10.399 6.858 10.499 ;
     RECT  64.692 10.411 64.782 10.499 ;
     RECT  56.232 10.121 56.697 10.541 ;
     RECT  58.392 10.471 58.878 10.589 ;
     RECT  40.215 10.291 55.494 10.625 ;
     RECT  41.544 10.625 55.494 10.661 ;
     RECT  38.808 10.205 38.826 10.733 ;
     RECT  41.544 10.661 55.278 10.733 ;
     RECT  59.688 10.049 63.738 10.859 ;
     RECT  7.815 8.537 8.097 10.939 ;
     RECT  57.492 10.201 57.51 11.011 ;
     RECT  58.392 10.589 58.698 11.011 ;
     RECT  41.94 10.733 55.278 11.129 ;
     RECT  62.964 10.859 63.738 11.131 ;
     RECT  9.036 9.545 9.666 11.173 ;
     RECT  10.872 10.201 10.89 11.173 ;
     RECT  7.344 10.939 8.097 11.245 ;
     RECT  41.94 11.129 53.874 11.309 ;
     RECT  54.972 11.129 55.278 11.357 ;
     RECT  50.904 11.309 53.874 11.399 ;
     RECT  55.044 11.357 55.278 11.399 ;
     RECT  64.764 10.499 64.782 11.419 ;
     RECT  55.044 11.399 55.062 11.435 ;
     RECT  0.828 10.499 6.318 11.479 ;
     RECT  7.272 11.245 8.097 11.479 ;
     RECT  64.692 11.419 64.782 11.579 ;
     RECT  64.692 11.579 64.71 11.659 ;
     RECT  38.988 11.611 39.006 11.669 ;
     RECT  50.904 11.399 52.794 11.669 ;
     RECT  53.604 11.399 53.874 11.669 ;
     RECT  62.964 11.131 63.846 11.669 ;
     RECT  50.904 11.669 52.65 11.705 ;
     RECT  40.215 10.625 40.662 11.821 ;
     RECT  57.492 11.011 58.698 11.821 ;
     RECT  59.688 10.859 62.097 11.821 ;
     RECT  39.888 11.821 41.058 11.947 ;
     RECT  41.94 11.309 50.13 11.947 ;
     RECT  39.888 11.947 50.13 11.984 ;
     RECT  0.828 11.479 8.097 12.019 ;
     RECT  9.036 11.173 10.89 12.055 ;
     RECT  57.492 11.821 62.097 12.091 ;
     RECT  63 11.669 63.846 12.209 ;
     RECT  56.415 10.541 56.697 12.289 ;
     RECT  57.456 12.091 62.097 12.289 ;
     RECT  0.828 12.019 8.226 12.325 ;
     RECT  54.792 12.289 54.81 12.325 ;
     RECT  9.036 12.055 10.926 12.353 ;
     RECT  0.828 12.325 8.298 12.379 ;
     RECT  64.656 11.659 64.71 12.379 ;
     RECT  54.72 12.325 54.81 12.389 ;
     RECT  64.62 12.379 64.71 12.475 ;
     RECT  50.904 11.705 52.11 12.479 ;
     RECT  64.62 12.475 64.782 12.509 ;
     RECT  56.415 12.289 62.097 12.523 ;
     RECT  9.036 12.353 10.89 12.551 ;
     RECT  52.092 12.479 52.11 12.631 ;
     RECT  52.092 12.631 52.722 12.749 ;
     RECT  0.108 12.379 8.298 12.763 ;
     RECT  9.036 12.551 10.818 12.763 ;
     RECT  0.108 12.763 10.818 12.797 ;
     RECT  55.728 12.523 62.097 12.859 ;
     RECT  55.584 12.859 62.097 12.907 ;
     RECT  63 12.209 63.666 12.907 ;
     RECT  41.94 11.984 50.13 13.027 ;
     RECT  55.584 12.907 63.666 13.055 ;
     RECT  39.132 11.821 39.15 13.333 ;
     RECT  38.772 13.333 39.15 13.369 ;
     RECT  39.888 11.984 40.986 13.369 ;
     RECT  22.284 10.057 22.41 13.397 ;
     RECT  38.772 13.369 40.986 13.405 ;
     RECT  41.724 13.027 50.13 13.405 ;
     RECT  38.772 13.405 50.13 13.433 ;
     RECT  0.828 12.797 10.818 13.567 ;
     RECT  54.72 12.389 54.738 13.595 ;
     RECT  0.504 13.567 10.818 13.627 ;
     RECT  50.904 12.479 51.297 13.829 ;
     RECT  55.692 13.055 63.666 13.829 ;
     RECT  53.856 11.669 53.874 13.909 ;
     RECT  52.092 12.749 52.47 13.973 ;
     RECT  0.108 13.627 10.818 13.981 ;
     RECT  51.015 13.829 51.297 13.981 ;
     RECT  52.092 13.973 52.29 13.981 ;
     RECT  0.108 13.981 10.926 14.071 ;
     RECT  12.06 9.931 12.078 14.071 ;
     RECT  0.108 14.071 12.078 14.099 ;
     RECT  0.108 14.099 10.746 14.279 ;
     RECT  0.504 14.279 10.746 14.285 ;
     RECT  53.856 13.909 54.126 14.341 ;
     RECT  53.856 14.341 54.702 14.347 ;
     RECT  55.692 13.829 60.57 14.369 ;
     RECT  64.764 12.509 64.782 14.395 ;
     RECT  39.132 13.433 50.13 14.413 ;
     RECT  64.656 14.395 64.782 14.573 ;
     RECT  61.596 13.829 63.666 14.635 ;
     RECT  38.772 14.413 50.13 14.639 ;
     RECT  55.872 14.369 60.57 14.639 ;
     RECT  0.504 14.285 10.674 15.025 ;
     RECT  0.504 15.025 10.746 15.151 ;
     RECT  11.52 14.099 11.718 15.151 ;
     RECT  55.872 14.639 60.462 15.259 ;
     RECT  53.856 14.347 54.738 15.293 ;
     RECT  61.596 14.635 63.738 15.295 ;
     RECT  0.504 15.151 11.718 15.403 ;
     RECT  64.728 14.573 64.782 15.403 ;
     RECT  55.764 15.259 60.462 15.421 ;
     RECT  55.728 15.421 60.462 15.449 ;
     RECT  61.236 15.295 63.738 15.643 ;
     RECT  55.728 15.449 60.282 15.791 ;
     RECT  53.856 15.293 54.126 15.835 ;
     RECT  0.108 15.403 11.718 15.899 ;
     RECT  55.296 15.871 55.314 16.169 ;
     RECT  64.692 15.403 64.782 16.259 ;
     RECT  0.108 15.899 0.522 16.301 ;
     RECT  56.415 15.791 60.282 16.339 ;
     RECT  61.236 15.643 63.846 16.339 ;
     RECT  56.415 16.339 63.846 16.529 ;
     RECT  39.132 14.639 50.13 17.347 ;
     RECT  55.44 17.221 55.458 17.347 ;
     RECT  56.415 16.529 60.354 17.347 ;
     RECT  61.308 16.529 63.846 17.419 ;
     RECT  38.772 17.347 50.13 17.447 ;
     RECT  55.44 17.347 60.354 17.455 ;
     RECT  61.164 17.419 63.846 17.455 ;
     RECT  64.692 16.259 64.746 17.659 ;
     RECT  53.316 15.835 54.126 17.761 ;
     RECT  55.44 17.455 63.846 17.761 ;
     RECT  53.316 17.761 63.846 17.879 ;
     RECT  64.656 17.659 64.746 18.139 ;
     RECT  64.62 18.139 64.746 18.149 ;
     RECT  53.316 17.879 59.994 18.221 ;
     RECT  0.504 16.301 0.522 18.379 ;
     RECT  51.015 13.981 52.29 18.463 ;
     RECT  53.316 18.221 57.042 18.463 ;
     RECT  57.816 18.221 59.994 18.733 ;
     RECT  0.108 18.379 0.522 18.763 ;
     RECT  57.816 18.733 60.174 18.841 ;
     RECT  60.984 17.879 63.846 18.841 ;
     RECT  39.132 17.447 50.13 19.111 ;
     RECT  51.015 18.463 57.042 19.111 ;
     RECT  39.132 19.111 57.042 19.201 ;
     RECT  57.816 18.841 63.846 19.201 ;
     RECT  64.62 18.149 64.71 19.229 ;
     RECT  39.132 19.201 63.846 19.337 ;
     RECT  37.224 18.661 37.242 19.499 ;
     RECT  1.368 15.899 11.718 19.507 ;
     RECT  14.4 13.945 14.418 19.615 ;
     RECT  14.4 19.615 14.994 19.651 ;
     RECT  36.972 19.507 36.99 19.679 ;
     RECT  64.692 19.229 64.71 19.679 ;
     RECT  39.132 19.337 50.094 19.741 ;
     RECT  14.4 19.651 15.102 19.813 ;
     RECT  1.368 19.507 11.754 19.849 ;
     RECT  14.4 19.813 15.282 19.913 ;
     RECT  38.772 19.741 50.094 19.913 ;
     RECT  51.015 19.337 63.846 20.147 ;
     RECT  38.808 19.913 50.094 20.191 ;
     RECT  51.015 20.147 62.478 20.191 ;
     RECT  38.808 20.191 62.478 20.219 ;
     RECT  14.4 19.913 14.814 20.309 ;
     RECT  1.368 19.849 12.006 20.417 ;
     RECT  39.132 20.219 62.478 20.453 ;
     RECT  53.82 20.453 62.478 20.489 ;
     RECT  39.132 20.453 50.13 20.615 ;
     RECT  53.82 20.489 62.298 20.849 ;
     RECT  63.216 20.147 63.846 20.849 ;
     RECT  1.368 20.417 11.97 20.957 ;
     RECT  0.036 18.763 0.522 20.965 ;
     RECT  1.368 20.957 1.386 20.965 ;
     RECT  61.056 20.849 62.298 20.993 ;
     RECT  41.652 20.615 50.13 21.227 ;
     RECT  39.132 20.615 40.914 21.355 ;
     RECT  41.652 21.227 42.75 21.355 ;
     RECT  39.132 21.355 42.75 21.389 ;
     RECT  39.132 21.389 42.642 21.425 ;
     RECT  0.036 20.965 1.386 21.497 ;
     RECT  39.132 21.425 40.842 21.497 ;
     RECT  41.652 21.425 42.642 21.497 ;
     RECT  64.692 20.635 64.71 21.569 ;
     RECT  51.015 20.453 52.938 21.643 ;
     RECT  53.82 20.849 60.246 21.643 ;
     RECT  2.196 20.957 11.97 21.667 ;
     RECT  41.652 21.497 42.606 21.731 ;
     RECT  51.015 21.643 60.246 21.775 ;
     RECT  61.092 20.993 62.298 21.775 ;
     RECT  2.196 21.667 12.078 21.839 ;
     RECT  51.015 21.775 62.298 21.883 ;
     RECT  63.252 20.849 63.846 21.883 ;
     RECT  51.015 21.883 63.846 21.929 ;
     RECT  43.74 21.227 50.13 22.009 ;
     RECT  51.015 21.929 62.982 22.009 ;
     RECT  2.196 21.839 12.042 22.199 ;
     RECT  41.868 21.731 42.606 22.199 ;
     RECT  43.74 22.009 62.982 22.207 ;
     RECT  2.196 22.199 11.97 22.621 ;
     RECT  0.504 21.497 1.386 22.651 ;
     RECT  0.108 22.651 1.386 22.781 ;
     RECT  43.488 22.207 62.982 23.081 ;
     RECT  61.308 23.081 62.982 23.117 ;
     RECT  63.792 21.929 63.846 23.131 ;
     RECT  63.252 23.131 63.846 23.279 ;
     RECT  61.308 23.117 62.298 23.459 ;
     RECT  2.124 22.621 11.97 23.521 ;
     RECT  13.215 2.413 13.497 23.521 ;
     RECT  43.488 23.081 60.462 23.855 ;
     RECT  54.648 23.855 60.462 23.899 ;
     RECT  61.308 23.459 62.262 23.899 ;
     RECT  39.132 21.497 40.497 23.935 ;
     RECT  41.868 22.199 42.066 23.935 ;
     RECT  54.648 23.899 62.262 23.999 ;
     RECT  38.772 23.935 42.066 24.089 ;
     RECT  63.828 23.279 63.846 24.089 ;
     RECT  38.772 24.089 41.202 24.197 ;
     RECT  63.252 24.139 63.306 24.379 ;
     RECT  63.216 24.379 63.306 24.701 ;
     RECT  63.216 24.701 63.27 24.737 ;
     RECT  54.648 23.999 62.097 24.745 ;
     RECT  43.488 23.855 53.91 24.781 ;
     RECT  54.648 24.745 62.298 24.781 ;
     RECT  43.488 24.781 62.298 24.899 ;
     RECT  63.252 24.737 63.27 24.971 ;
     RECT  0.504 22.781 1.386 25.387 ;
     RECT  43.488 24.899 62.097 25.583 ;
     RECT  43.488 25.583 55.278 25.591 ;
     RECT  43.092 25.591 55.278 25.709 ;
     RECT  39.132 24.197 40.497 25.789 ;
     RECT  56.052 25.583 62.097 25.789 ;
     RECT  64.692 25.147 64.71 25.817 ;
     RECT  63.864 25.519 63.882 25.861 ;
     RECT  56.052 25.789 62.442 25.889 ;
     RECT  63.288 25.861 63.882 25.915 ;
     RECT  43.092 25.709 55.242 25.951 ;
     RECT  0.108 25.387 1.386 26.045 ;
     RECT  42.048 24.089 42.066 26.059 ;
     RECT  41.868 26.059 42.066 26.131 ;
     RECT  42.948 25.951 55.242 26.131 ;
     RECT  41.868 26.131 55.242 26.257 ;
     RECT  41.616 26.257 55.242 26.393 ;
     RECT  63.252 25.915 63.882 26.429 ;
     RECT  38.772 25.789 40.497 26.519 ;
     RECT  56.052 25.889 62.154 26.629 ;
     RECT  63.252 26.429 63.378 26.629 ;
     RECT  56.052 26.629 63.378 26.669 ;
     RECT  41.616 26.393 55.134 26.699 ;
     RECT  0.504 26.045 1.386 26.761 ;
     RECT  2.124 23.521 13.497 26.761 ;
     RECT  41.616 26.699 55.098 26.789 ;
     RECT  42.912 26.789 42.93 26.825 ;
     RECT  41.616 26.789 41.886 26.897 ;
     RECT  43.956 26.789 55.098 27.095 ;
     RECT  63.252 26.669 63.378 27.163 ;
     RECT  56.052 26.669 62.097 27.715 ;
     RECT  56.052 27.715 62.298 28.021 ;
     RECT  63.252 27.163 63.846 28.021 ;
     RECT  56.052 28.021 63.846 28.139 ;
     RECT  44.604 27.095 54.99 28.211 ;
     RECT  53.856 28.211 54.99 28.247 ;
     RECT  53.856 28.247 53.946 28.283 ;
     RECT  54.972 28.247 54.99 28.283 ;
     RECT  53.928 28.283 53.946 28.787 ;
     RECT  56.052 28.139 63.378 28.891 ;
     RECT  56.052 28.891 63.846 28.949 ;
     RECT  56.052 28.949 63.378 29.165 ;
     RECT  56.052 29.165 62.298 29.219 ;
     RECT  0.504 26.761 13.497 29.461 ;
     RECT  56.052 29.219 62.262 29.489 ;
     RECT  0.504 29.461 13.59 29.501 ;
     RECT  0.504 29.501 13.497 29.659 ;
     RECT  0.108 29.659 13.497 29.789 ;
     RECT  63.252 29.165 63.378 30.139 ;
     RECT  44.604 28.211 53.118 30.283 ;
     RECT  44.244 30.283 53.118 30.307 ;
     RECT  56.052 29.489 62.097 30.415 ;
     RECT  56.052 30.415 62.262 30.451 ;
     RECT  63.252 30.139 63.846 30.451 ;
     RECT  43.956 30.307 53.118 31.109 ;
     RECT  56.052 30.451 63.846 31.109 ;
     RECT  0.504 29.789 13.497 31.387 ;
     RECT  0.108 31.387 13.497 31.517 ;
     RECT  56.052 31.109 63.306 31.559 ;
     RECT  44.1 31.109 53.118 31.649 ;
     RECT  63.252 31.559 63.306 31.649 ;
     RECT  42.768 31.495 42.786 31.793 ;
     RECT  64.692 30.427 64.71 31.829 ;
     RECT  63.288 31.649 63.306 31.891 ;
     RECT  44.172 31.649 53.118 32.189 ;
     RECT  63.288 31.891 63.882 32.189 ;
     RECT  44.46 32.189 53.118 32.431 ;
     RECT  54.72 32.299 54.738 32.477 ;
     RECT  56.052 31.559 62.097 32.845 ;
     RECT  44.46 32.431 53.298 32.957 ;
     RECT  44.46 32.957 53.118 32.999 ;
     RECT  56.052 32.845 62.118 33.043 ;
     RECT  0.504 31.517 13.497 33.307 ;
     RECT  56.052 33.043 62.19 33.349 ;
     RECT  0.108 33.307 13.497 33.437 ;
     RECT  63.288 32.189 63.846 33.989 ;
     RECT  63.288 33.989 63.81 34.171 ;
     RECT  44.46 32.999 44.478 34.195 ;
     RECT  45.504 32.999 53.118 34.195 ;
     RECT  44.46 34.195 53.118 34.223 ;
     RECT  56.052 33.349 62.298 34.231 ;
     RECT  63.252 34.171 63.81 34.231 ;
     RECT  44.1 34.861 44.118 34.925 ;
     RECT  64.692 34.651 64.71 34.997 ;
     RECT  44.928 34.223 53.118 35.041 ;
     RECT  56.052 34.231 63.81 35.069 ;
     RECT  0.504 33.437 13.497 35.131 ;
     RECT  63.252 35.069 63.81 35.131 ;
     RECT  44.532 35.041 53.118 35.261 ;
     RECT  56.052 35.069 62.097 35.815 ;
     RECT  56.052 35.815 62.19 35.969 ;
     RECT  0.108 35.131 13.497 36.461 ;
     RECT  44.928 35.261 53.118 36.763 ;
     RECT  56.052 35.969 62.097 36.823 ;
     RECT  63.252 35.131 63.846 36.823 ;
     RECT  44.352 36.763 53.118 37.049 ;
     RECT  56.052 36.823 63.846 37.229 ;
     RECT  64.692 36.907 64.71 37.387 ;
     RECT  64.656 37.387 64.71 37.499 ;
     RECT  64.656 37.499 64.674 37.625 ;
     RECT  56.052 37.229 63.378 38.155 ;
     RECT  56.052 38.155 63.846 38.201 ;
     RECT  0.504 36.461 13.497 38.635 ;
     RECT  44.604 37.049 53.118 38.669 ;
     RECT  44.748 38.669 53.118 38.717 ;
     RECT  39.132 26.519 40.497 38.779 ;
     RECT  39.132 38.779 41.058 38.939 ;
     RECT  43.308 37.975 43.326 38.939 ;
     RECT  56.052 38.201 61.002 39.055 ;
     RECT  61.815 38.201 63.846 39.055 ;
     RECT  54.468 38.101 54.486 39.181 ;
     RECT  54.468 39.181 54.522 39.209 ;
     RECT  45.396 38.717 53.118 39.289 ;
     RECT  45.396 39.289 53.55 39.361 ;
     RECT  45.396 39.361 53.766 39.479 ;
     RECT  0.108 38.635 13.497 39.533 ;
     RECT  56.052 39.055 63.846 39.631 ;
     RECT  56.052 39.631 63.882 39.677 ;
     RECT  38.34 39.721 38.358 39.773 ;
     RECT  36.792 39.784 36.81 39.821 ;
     RECT  31.716 39.499 31.734 39.883 ;
     RECT  54.504 39.209 54.522 39.901 ;
     RECT  54.504 39.901 54.774 39.929 ;
     RECT  31.392 39.883 31.734 40.019 ;
     RECT  56.052 39.677 63.846 40.703 ;
     RECT  56.052 40.703 60.966 40.837 ;
     RECT  45.396 39.479 53.622 40.865 ;
     RECT  22.284 13.397 22.302 41.675 ;
     RECT  55.908 40.837 60.966 41.755 ;
     RECT  61.704 40.703 63.846 41.755 ;
     RECT  64.692 39.403 64.71 41.819 ;
     RECT  55.908 41.755 63.846 42.179 ;
     RECT  45.396 40.865 53.118 42.565 ;
     RECT  55.908 42.179 63.45 42.565 ;
     RECT  0.504 39.533 13.497 42.571 ;
     RECT  55.8 42.565 63.45 42.605 ;
     RECT  45.072 42.565 53.118 42.719 ;
     RECT  54.756 39.929 54.774 42.763 ;
     RECT  55.908 42.605 63.45 42.791 ;
     RECT  54.72 42.763 54.774 42.863 ;
     RECT  55.98 42.791 63.45 42.899 ;
     RECT  56.052 42.899 63.45 43.147 ;
     RECT  43.38 43.105 43.398 43.339 ;
     RECT  64.692 42.907 64.71 43.637 ;
     RECT  45.288 42.719 53.118 43.771 ;
     RECT  42.768 43.339 43.398 43.835 ;
     RECT  0.108 42.571 13.497 43.853 ;
     RECT  45 43.771 53.118 44.149 ;
     RECT  54.756 42.863 54.774 44.149 ;
     RECT  56.052 43.147 63.846 44.149 ;
     RECT  44.604 44.149 53.118 44.339 ;
     RECT  54.756 44.149 63.846 44.581 ;
     RECT  54.756 44.581 63.882 44.587 ;
     RECT  45.288 44.339 45.99 44.621 ;
     RECT  54.72 44.587 63.882 44.669 ;
     RECT  54.72 44.669 63.846 44.717 ;
     RECT  46.764 44.339 53.118 44.813 ;
     RECT  0.504 43.853 13.497 45.163 ;
     RECT  54.756 44.717 63.846 46.499 ;
     RECT  0.108 45.163 13.497 46.541 ;
     RECT  0.18 46.541 13.497 46.685 ;
     RECT  54.756 46.499 63.774 46.913 ;
     RECT  54.756 46.913 63.342 47.011 ;
     RECT  43.38 43.835 43.398 47.035 ;
     RECT  42.768 47.035 43.398 47.039 ;
     RECT  54.54 47.011 63.342 47.069 ;
     RECT  41.868 26.897 41.886 47.155 ;
     RECT  42.768 47.039 42.894 47.155 ;
     RECT  39.132 38.939 40.497 47.191 ;
     RECT  54.612 47.069 63.342 47.219 ;
     RECT  38.772 47.191 40.497 47.309 ;
     RECT  41.868 47.155 42.894 47.309 ;
     RECT  47.376 44.813 53.118 47.317 ;
     RECT  64.692 46.171 64.71 47.419 ;
     RECT  47.376 47.317 53.298 47.425 ;
     RECT  54.72 47.219 54.846 47.489 ;
     RECT  41.868 47.309 42.534 47.849 ;
     RECT  45.615 44.621 45.897 48.091 ;
     RECT  47.232 47.425 53.298 48.091 ;
     RECT  55.728 47.219 63.342 48.139 ;
     RECT  45.615 48.091 46.278 48.163 ;
     RECT  47.196 48.091 53.298 48.163 ;
     RECT  64.656 47.419 64.71 48.299 ;
     RECT  54.72 47.489 54.774 48.361 ;
     RECT  55.728 48.139 63.846 48.361 ;
     RECT  45.615 48.163 53.298 48.389 ;
     RECT  46.764 48.389 53.298 48.659 ;
     RECT  54.72 48.361 63.846 48.659 ;
     RECT  54.72 48.659 63.81 48.763 ;
     RECT  42.804 48.505 42.894 48.839 ;
     RECT  64.692 48.299 64.71 48.941 ;
     RECT  0.504 46.685 13.497 49.051 ;
     RECT  0.108 49.051 13.497 49.181 ;
     RECT  54.216 48.763 63.81 49.387 ;
     RECT  44.46 49.243 44.478 49.469 ;
     RECT  43.452 49.003 43.47 49.505 ;
     RECT  46.98 48.659 53.298 49.621 ;
     RECT  54.216 49.387 63.846 49.855 ;
     RECT  43.596 49.621 43.614 49.883 ;
     RECT  54.036 49.855 63.846 49.891 ;
     RECT  54.036 49.891 63.882 49.949 ;
     RECT  46.8 49.621 53.298 50.189 ;
     RECT  46.944 50.189 53.298 50.665 ;
     RECT  54.036 49.949 63.342 50.665 ;
     RECT  64.692 49.675 64.71 50.819 ;
     RECT  46.944 50.665 63.342 50.923 ;
     RECT  46.944 50.923 63.846 51.133 ;
     RECT  46.764 51.133 63.846 51.233 ;
     RECT  47.232 51.233 63.846 51.431 ;
     RECT  47.232 51.431 63.81 51.899 ;
     RECT  47.232 51.899 63.342 52.051 ;
     RECT  46.764 52.051 63.342 52.169 ;
     RECT  64.692 51.883 64.71 52.277 ;
     RECT  0.504 49.181 13.497 52.321 ;
     RECT  0.504 52.321 13.662 52.439 ;
     RECT  14.4 20.309 14.418 52.439 ;
     RECT  48.528 52.169 63.342 52.651 ;
     RECT  14.472 52.447 14.49 52.709 ;
     RECT  46.764 52.169 47.718 52.987 ;
     RECT  48.528 52.651 63.846 52.987 ;
     RECT  46.764 52.987 63.846 53.249 ;
     RECT  46.764 53.249 63.81 53.285 ;
     RECT  46.764 53.285 47.718 53.429 ;
     RECT  48.456 53.285 63.81 53.789 ;
     RECT  64.692 53.419 64.71 54.599 ;
     RECT  48.456 53.789 63.342 54.715 ;
     RECT  47.232 53.429 47.718 54.751 ;
     RECT  42.768 54.949 42.786 55.139 ;
     RECT  0.504 52.439 13.497 55.147 ;
     RECT  46.764 54.751 47.718 55.285 ;
     RECT  48.456 54.715 63.378 55.285 ;
     RECT  46.764 55.285 63.378 55.325 ;
     RECT  48.312 55.325 63.378 55.387 ;
     RECT  45.615 48.389 45.897 55.525 ;
     RECT  46.764 55.325 47.574 55.525 ;
     RECT  48.312 55.387 63.846 55.921 ;
     RECT  48.312 55.921 63.882 56.189 ;
     RECT  24.015 2.413 24.297 56.191 ;
     RECT  34.815 9.509 35.097 56.191 ;
     RECT  45.615 55.525 47.574 56.191 ;
     RECT  48.312 56.189 63.846 56.191 ;
     RECT  45.504 56.191 63.846 56.237 ;
     RECT  48.24 56.237 63.846 56.759 ;
     RECT  0.108 55.147 13.497 57.137 ;
     RECT  45.504 56.237 47.394 57.145 ;
     RECT  48.24 56.759 63.378 57.145 ;
     RECT  23.904 56.191 24.297 57.209 ;
     RECT  34.704 56.191 35.097 57.209 ;
     RECT  45.504 57.145 63.378 57.209 ;
     RECT  64.692 57.163 64.71 57.569 ;
     RECT  42.768 57.811 42.786 57.883 ;
     RECT  42.732 57.883 42.786 57.911 ;
     RECT  45.615 57.209 63.378 57.931 ;
     RECT  45.615 57.931 63.846 57.955 ;
     RECT  45.54 57.955 63.846 58.019 ;
     RECT  39.132 47.309 40.497 58.109 ;
     RECT  42.732 57.911 42.75 58.109 ;
     RECT  43.596 57.721 43.614 58.109 ;
     RECT  45.54 58.019 63.378 58.145 ;
     RECT  0.468 57.137 13.497 58.507 ;
     RECT  45.576 58.145 63.378 58.649 ;
     RECT  0.108 58.507 13.497 58.685 ;
     RECT  45.576 58.649 46.206 58.685 ;
     RECT  64.692 58.891 64.71 59.099 ;
     RECT  46.944 58.649 63.378 59.261 ;
     RECT  24.015 57.209 24.297 59.323 ;
     RECT  34.815 57.209 35.097 59.323 ;
     RECT  45.576 58.685 45.897 59.323 ;
     RECT  23.904 59.323 24.297 59.369 ;
     RECT  34.704 59.323 35.097 59.369 ;
     RECT  45.504 59.323 45.897 59.369 ;
     RECT  48.6 59.261 63.378 59.419 ;
     RECT  0.468 58.685 13.497 59.563 ;
     RECT  46.944 59.261 47.682 59.575 ;
     RECT  46.692 59.575 47.682 59.603 ;
     RECT  0.108 59.563 13.497 59.693 ;
     RECT  39.132 58.109 39.15 59.729 ;
     RECT  48.6 59.419 63.846 60.151 ;
     RECT  45.615 59.369 45.897 60.241 ;
     RECT  46.692 59.603 47.538 60.241 ;
     RECT  48.42 60.151 63.846 60.241 ;
     RECT  42.768 60.139 42.786 60.317 ;
     RECT  45.615 60.241 47.538 60.317 ;
     RECT  48.42 60.241 63.882 60.341 ;
     RECT  47.052 60.317 47.538 60.385 ;
     RECT  0.504 59.693 13.497 60.427 ;
     RECT  48.78 60.341 63.882 60.461 ;
     RECT  47.052 60.385 47.61 60.547 ;
     RECT  0.108 60.427 13.497 60.605 ;
     RECT  47.052 60.547 47.898 60.953 ;
     RECT  47.052 60.953 47.07 60.989 ;
     RECT  47.88 60.953 47.898 61.501 ;
     RECT  48.78 60.461 63.846 61.501 ;
     RECT  47.88 61.501 63.846 61.619 ;
     RECT  48.276 61.619 63.846 61.889 ;
     RECT  0.504 60.605 13.497 62.392 ;
     RECT  64.692 60.907 64.71 62.491 ;
     RECT  0.108 62.392 13.497 62.669 ;
     RECT  48.42 61.889 63.846 63.049 ;
     RECT  47.16 62.977 47.178 63.211 ;
     RECT  48.312 63.049 63.846 63.211 ;
     RECT  48.06 63.211 63.846 63.239 ;
     RECT  47.16 63.211 47.214 63.248 ;
     RECT  48.06 63.239 49.338 63.275 ;
     RECT  48.06 63.275 48.798 63.347 ;
     RECT  47.16 63.248 47.178 63.419 ;
     RECT  48.06 63.347 48.762 63.419 ;
     RECT  50.184 63.239 63.846 63.509 ;
     RECT  48.708 63.419 48.762 63.533 ;
     RECT  50.292 63.509 63.378 63.581 ;
     RECT  24.015 59.369 24.297 63.643 ;
     RECT  34.815 59.369 35.097 63.643 ;
     RECT  45.615 60.317 45.897 63.643 ;
     RECT  64.692 62.491 64.782 63.643 ;
     RECT  23.904 63.643 24.297 63.689 ;
     RECT  34.704 63.643 35.097 63.689 ;
     RECT  45.504 63.643 45.897 63.689 ;
     RECT  0.504 62.669 13.497 63.931 ;
     RECT  0.108 63.931 13.497 64.109 ;
     RECT  64.656 63.643 64.782 64.229 ;
     RECT  50.436 63.581 63.378 64.411 ;
     RECT  64.692 64.229 64.782 64.589 ;
     RECT  50.436 64.411 63.846 64.741 ;
     RECT  50.076 64.741 63.846 64.831 ;
     RECT  50.076 64.831 63.882 64.895 ;
     RECT  50.184 64.895 63.882 64.925 ;
     RECT  50.184 64.925 63.846 64.931 ;
     RECT  50.256 64.931 63.846 64.967 ;
     RECT  64.692 64.589 64.71 65.237 ;
     RECT  47.772 65.563 47.79 65.939 ;
     RECT  48.708 63.533 48.726 66.019 ;
     RECT  47.916 66.019 48.726 66.119 ;
     RECT  47.916 66.119 47.934 66.389 ;
     RECT  0.504 64.109 13.497 66.811 ;
     RECT  46.764 66.019 46.782 66.893 ;
     RECT  0.108 66.811 13.497 66.941 ;
     RECT  31.788 66.715 31.806 67.019 ;
     RECT  33.336 66.715 33.354 67.019 ;
     RECT  50.436 64.967 63.846 67.801 ;
     RECT  50.436 67.801 63.882 67.949 ;
     RECT  49.608 67.801 49.626 68.243 ;
     RECT  50.436 67.949 63.378 68.341 ;
     RECT  48.708 66.119 48.726 68.369 ;
     RECT  50.004 68.341 63.378 68.381 ;
     RECT  0.504 66.941 13.497 68.611 ;
     RECT  0.468 68.611 13.497 68.881 ;
     RECT  50.184 68.381 63.378 68.881 ;
     RECT  50.184 68.881 63.882 69.287 ;
     RECT  0.108 68.881 13.497 69.293 ;
     RECT  45.615 63.689 45.897 69.421 ;
     RECT  0.18 69.293 13.497 69.437 ;
     RECT  47.304 68.377 47.322 69.449 ;
     RECT  64.692 68.683 64.71 69.449 ;
     RECT  45.576 69.421 45.897 69.485 ;
     RECT  50.436 69.287 63.882 69.961 ;
     RECT  0.432 69.437 13.497 70.411 ;
     RECT  50.436 69.961 63.918 70.685 ;
     RECT  0.108 70.411 13.497 70.709 ;
     RECT  64.692 70.891 64.71 71.069 ;
     RECT  0.432 70.709 13.497 71.899 ;
     RECT  0.108 71.899 13.497 72.029 ;
     RECT  50.436 70.685 63.414 72.427 ;
     RECT  0.18 72.029 13.497 72.763 ;
     RECT  50.436 72.427 63.846 72.959 ;
     RECT  50.436 72.959 63.414 73.265 ;
     RECT  0.108 72.763 13.497 73.805 ;
     RECT  50.436 73.265 63.342 74.659 ;
     RECT  64.692 74.683 64.71 74.759 ;
     RECT  0.54 73.805 13.497 75.541 ;
     RECT  41.868 47.849 41.886 75.569 ;
     RECT  50.436 74.659 63.378 75.631 ;
     RECT  0.54 75.541 13.95 75.643 ;
     RECT  14.796 75.541 14.814 75.659 ;
     RECT  50.436 75.631 63.882 75.677 ;
     RECT  0.108 75.643 13.95 75.731 ;
     RECT  50.436 75.677 63.846 75.965 ;
     RECT  0.108 75.731 13.497 77.309 ;
     RECT  50.436 75.965 63.378 77.315 ;
     RECT  0.54 77.309 13.497 78.061 ;
     RECT  64.692 77.179 64.71 78.584 ;
     RECT  51.015 77.315 63.378 78.601 ;
     RECT  0.54 78.061 13.734 78.745 ;
     RECT  14.472 78.205 14.49 78.745 ;
     RECT  0.54 78.745 14.49 79.141 ;
     RECT  0.54 79.141 14.814 79.285 ;
     RECT  0.54 79.285 14.85 79.321 ;
     RECT  51.015 78.601 63.882 79.321 ;
     RECT  64.692 79.387 64.71 79.439 ;
     RECT  0.54 79.321 15.03 79.483 ;
     RECT  50.724 79.321 63.882 79.511 ;
     RECT  0.54 79.483 15.39 79.672 ;
     RECT  0.108 79.672 15.39 79.709 ;
     RECT  0.468 79.709 15.39 80.059 ;
     RECT  0.468 80.059 15.75 80.095 ;
     RECT  17.064 80.107 17.082 80.249 ;
     RECT  0.468 80.095 16.11 80.401 ;
     RECT  51.015 79.511 63.882 80.635 ;
     RECT  0.468 80.401 16.974 80.683 ;
     RECT  0.144 80.683 16.974 80.905 ;
     RECT  0.108 80.905 16.974 80.957 ;
     RECT  50.724 80.635 63.882 80.957 ;
     RECT  0.468 80.957 16.974 81.103 ;
     RECT  18.615 2.413 18.897 81.103 ;
     RECT  0.468 81.103 17.406 81.643 ;
     RECT  18.36 81.103 18.897 81.643 ;
     RECT  50.724 80.957 63.378 81.869 ;
     RECT  64.692 81.643 64.71 81.977 ;
     RECT  51.015 81.869 63.378 82.561 ;
     RECT  51.015 82.561 63.846 82.685 ;
     RECT  0.468 81.643 18.897 82.723 ;
     RECT  0.468 82.723 19.422 83.227 ;
     RECT  51.015 82.685 63.378 83.419 ;
     RECT  51.015 83.419 63.846 83.489 ;
     RECT  51.015 83.489 63.378 83.569 ;
     RECT  0.468 83.227 19.818 84.145 ;
     RECT  0.468 84.145 20.538 84.181 ;
     RECT  50.724 83.569 63.378 84.209 ;
     RECT  0.468 84.181 20.934 84.451 ;
     RECT  22.752 84.145 22.77 84.451 ;
     RECT  64.692 84.139 64.71 84.479 ;
     RECT  22.752 84.451 22.878 84.541 ;
     RECT  22.068 84.541 22.878 84.569 ;
     RECT  51.015 84.209 63.378 84.577 ;
     RECT  49.104 84.955 49.122 84.991 ;
     RECT  22.068 84.569 22.842 85.109 ;
     RECT  49.068 84.991 49.122 85.109 ;
     RECT  51.015 84.577 63.882 85.181 ;
     RECT  49.068 85.109 49.086 85.217 ;
     RECT  24.015 63.689 24.297 85.225 ;
     RECT  0.468 84.451 20.97 85.261 ;
     RECT  0.468 85.261 21.258 85.459 ;
     RECT  22.068 85.109 22.446 85.459 ;
     RECT  23.616 85.225 24.297 85.483 ;
     RECT  0.108 85.459 22.446 85.709 ;
     RECT  23.616 85.483 24.498 85.927 ;
     RECT  49.032 85.627 49.05 85.955 ;
     RECT  23.616 85.927 24.534 86.035 ;
     RECT  0.144 85.709 22.446 86.071 ;
     RECT  23.364 86.035 24.534 86.071 ;
     RECT  0.144 86.071 24.534 86.611 ;
     RECT  0.108 86.611 24.534 86.701 ;
     RECT  0.108 86.701 25.074 86.717 ;
     RECT  0.144 86.717 25.074 86.765 ;
     RECT  49.032 86.881 49.05 87.071 ;
     RECT  0.144 86.765 24.462 87.197 ;
     RECT  0.396 87.197 24.462 87.583 ;
     RECT  0.396 87.583 24.57 88.087 ;
     RECT  0.396 88.087 24.858 88.231 ;
     RECT  49.032 88.159 49.05 88.259 ;
     RECT  26.064 87.889 26.082 88.465 ;
     RECT  25.956 88.465 26.082 88.501 ;
     RECT  0.108 88.231 24.858 88.897 ;
     RECT  25.956 88.501 26.442 88.897 ;
     RECT  0.108 88.897 26.442 89.041 ;
     RECT  51.015 85.181 63.414 89.671 ;
     RECT  0.108 89.041 26.514 89.933 ;
     RECT  64.692 89.803 64.71 89.933 ;
     RECT  0.144 89.933 26.514 90.211 ;
     RECT  51.015 89.671 63.918 90.461 ;
     RECT  0.144 90.211 27.054 90.667 ;
     RECT  0.108 90.667 27.054 90.845 ;
     RECT  0.144 90.845 27.054 90.941 ;
     RECT  51.015 90.461 63.846 90.941 ;
     RECT  0.648 90.941 27.054 91.021 ;
     RECT  34.815 63.689 35.097 91.291 ;
     RECT  45.615 69.485 45.897 91.291 ;
     RECT  45.504 91.291 45.897 91.328 ;
     RECT  0.648 91.021 27.342 91.363 ;
     RECT  34.74 91.291 35.097 91.421 ;
     RECT  28.476 91.387 28.494 91.427 ;
     RECT  0.648 91.363 27.63 91.471 ;
     RECT  0.648 91.471 28.386 91.741 ;
     RECT  51.015 90.941 63.414 91.831 ;
     RECT  0.108 91.741 28.386 92.209 ;
     RECT  29.415 2.413 29.697 92.209 ;
     RECT  0.108 92.209 29.697 92.429 ;
     RECT  51.015 91.831 63.882 92.429 ;
     RECT  0.648 92.429 29.697 93.208 ;
     RECT  51.015 92.429 63.846 93.209 ;
     RECT  0.648 93.208 30.33 93.245 ;
     RECT  0.648 93.245 30.294 93.389 ;
     RECT  34.815 91.421 35.097 93.445 ;
     RECT  45.615 91.328 45.897 93.451 ;
     RECT  34.704 93.445 35.097 93.485 ;
     RECT  45.504 93.451 45.897 93.488 ;
     RECT  38.196 93.055 38.214 93.659 ;
     RECT  21.24 93.389 30.294 94.445 ;
     RECT  51.015 93.209 63.342 94.865 ;
     RECT  31.068 94.441 31.266 94.939 ;
     RECT  30.708 94.939 31.266 94.981 ;
     RECT  64.692 95.143 64.71 95.213 ;
     RECT  21.24 94.445 29.97 95.251 ;
     RECT  30.708 94.981 31.338 95.251 ;
     RECT  53.712 94.865 63.342 95.251 ;
     RECT  21.24 95.251 31.338 95.449 ;
     RECT  34.815 93.485 35.097 95.605 ;
     RECT  21.24 95.449 31.842 95.611 ;
     RECT  45.615 93.488 45.897 95.611 ;
     RECT  34.704 95.605 35.097 95.645 ;
     RECT  45.504 95.611 45.897 95.648 ;
     RECT  21.24 95.611 31.878 95.741 ;
     RECT  33.012 95.647 33.102 95.747 ;
     RECT  22.068 95.741 31.878 95.755 ;
     RECT  0.648 93.389 20.502 96.151 ;
     RECT  21.24 95.741 21.258 96.151 ;
     RECT  0.648 96.151 21.258 96.295 ;
     RECT  36.576 96.151 36.594 96.461 ;
     RECT  22.068 95.755 32.526 96.475 ;
     RECT  34.815 95.645 35.097 96.715 ;
     RECT  0.54 96.295 21.258 96.835 ;
     RECT  22.068 96.475 33.03 96.835 ;
     RECT  0.54 96.835 33.03 96.871 ;
     RECT  0.54 96.871 33.426 96.907 ;
     RECT  53.712 95.251 63.882 96.941 ;
     RECT  0.108 96.907 33.426 96.989 ;
     RECT  0.108 96.989 19.746 97.085 ;
     RECT  20.484 96.989 33.426 97.099 ;
     RECT  34.2 96.715 35.097 97.099 ;
     RECT  20.484 97.099 35.097 97.277 ;
     RECT  53.712 96.941 63.342 97.915 ;
     RECT  20.484 97.277 34.038 98.104 ;
     RECT  34.815 97.277 35.097 98.104 ;
     RECT  20.484 98.104 35.097 98.311 ;
     RECT  20.484 98.311 35.334 98.381 ;
     RECT  53.712 97.915 63.846 98.419 ;
     RECT  0.648 97.085 19.746 98.581 ;
     RECT  0.54 98.581 19.746 98.635 ;
     RECT  20.484 98.381 35.262 98.635 ;
     RECT  0.54 98.635 35.262 98.717 ;
     RECT  53.712 98.419 63.882 98.717 ;
     RECT  0.648 98.717 35.262 99.259 ;
     RECT  45.615 95.648 45.897 99.391 ;
     RECT  37.008 99.391 37.026 99.437 ;
     RECT  45.504 99.391 45.897 99.437 ;
     RECT  0.648 99.259 35.334 99.571 ;
     RECT  0.648 99.571 35.694 99.661 ;
     RECT  0.648 99.661 35.874 99.841 ;
     RECT  53.712 98.717 63.846 100.111 ;
     RECT  0.648 99.841 36.486 100.229 ;
     RECT  53.712 100.111 63.882 100.445 ;
     RECT  0.648 100.229 18.99 100.651 ;
     RECT  0.108 100.651 18.99 100.688 ;
     RECT  19.728 100.229 36.486 101.083 ;
     RECT  53.712 100.445 63.342 101.419 ;
     RECT  38.232 101.281 38.25 101.461 ;
     RECT  19.728 101.083 36.522 101.551 ;
     RECT  19.728 101.551 36.99 101.659 ;
     RECT  37.764 101.461 38.25 101.659 ;
     RECT  19.728 101.659 38.25 101.707 ;
     RECT  53.712 101.419 63.846 102.227 ;
     RECT  19.728 101.707 38.754 102.361 ;
     RECT  19.728 102.361 39.222 102.413 ;
     RECT  19.728 102.413 38.862 102.989 ;
     RECT  0.648 100.688 18.99 103.009 ;
     RECT  53.712 102.227 63.342 103.147 ;
     RECT  40.215 58.109 40.497 103.243 ;
     RECT  53.712 103.147 63.846 103.855 ;
     RECT  19.728 102.989 38.718 103.891 ;
     RECT  39.528 103.243 40.497 103.891 ;
     RECT  53.712 103.855 63.882 103.949 ;
     RECT  63.864 103.949 63.882 104.189 ;
     RECT  0.54 103.009 18.99 104.429 ;
     RECT  53.712 103.949 62.73 104.429 ;
     RECT  64.692 104.683 64.71 104.999 ;
     RECT  19.728 103.891 40.497 105.061 ;
     RECT  63.288 104.701 63.306 105.163 ;
     RECT  0.648 104.429 18.99 105.211 ;
     RECT  41.472 105.169 41.49 105.397 ;
     RECT  42.228 105.331 42.246 105.397 ;
     RECT  41.472 105.397 42.246 105.499 ;
     RECT  19.728 105.061 40.554 105.643 ;
     RECT  41.436 105.499 42.246 105.643 ;
     RECT  0.144 105.211 18.99 105.745 ;
     RECT  19.728 105.643 42.246 105.745 ;
     RECT  53.712 104.429 62.37 105.781 ;
     RECT  63.252 105.163 63.306 105.781 ;
     RECT  0.144 105.745 42.246 105.871 ;
     RECT  45.615 99.437 45.897 105.871 ;
     RECT  45.504 105.871 45.897 105.917 ;
     RECT  0.144 105.871 42.642 105.979 ;
     RECT  53.712 105.781 63.306 106.205 ;
     RECT  0.108 105.979 42.642 106.447 ;
     RECT  53.712 106.205 62.73 106.493 ;
     RECT  63.828 106.555 63.846 106.685 ;
     RECT  0.108 106.447 42.786 106.753 ;
     RECT  58.572 106.493 62.73 106.973 ;
     RECT  53.712 106.493 57.762 107.221 ;
     RECT  58.572 106.973 62.37 107.221 ;
     RECT  64.692 107.179 64.71 107.393 ;
     RECT  0.108 106.753 43.29 107.549 ;
     RECT  63.252 107.419 63.27 107.659 ;
     RECT  63.252 107.659 63.846 107.699 ;
     RECT  0.648 107.549 43.29 107.869 ;
     RECT  63.252 107.699 63.27 107.899 ;
     RECT  63.216 107.899 63.27 107.969 ;
     RECT  63.252 107.969 63.27 108.059 ;
     RECT  0.648 107.869 43.506 108.211 ;
     RECT  64.692 108.187 64.71 108.329 ;
     RECT  63.288 108.481 63.882 108.701 ;
     RECT  0.648 108.211 44.046 108.841 ;
     RECT  63.288 108.701 63.306 108.941 ;
     RECT  0.108 108.841 44.442 109.021 ;
     RECT  45.615 105.917 45.897 109.021 ;
     RECT  53.712 107.221 62.37 109.111 ;
     RECT  0.108 109.021 45.897 109.181 ;
     RECT  0.648 109.181 45.897 109.949 ;
     RECT  53.712 109.111 62.694 109.993 ;
     RECT  63.864 109.831 63.882 109.993 ;
     RECT  53.712 109.993 63.882 110.189 ;
     RECT  0.648 109.949 2.97 110.251 ;
     RECT  0.108 110.251 2.97 110.429 ;
     RECT  63.864 110.189 63.882 110.429 ;
     RECT  3.744 109.949 45.897 110.587 ;
     RECT  47.16 110.731 47.178 110.767 ;
     RECT  3.744 110.587 45.99 110.795 ;
     RECT  4.068 110.795 45.99 110.911 ;
     RECT  47.16 110.767 47.25 110.911 ;
     RECT  53.712 110.189 62.73 111.181 ;
     RECT  53.712 111.181 62.766 111.437 ;
     RECT  4.068 110.911 47.25 111.721 ;
     RECT  63.828 111.64 63.846 111.991 ;
     RECT  63.828 111.991 63.882 112.189 ;
     RECT  0.648 110.429 2.97 112.261 ;
     RECT  4.068 111.721 47.718 112.261 ;
     RECT  48.492 111.883 48.51 112.261 ;
     RECT  0.54 112.261 2.97 112.445 ;
     RECT  63.288 112.189 63.882 112.445 ;
     RECT  4.068 112.261 48.51 112.459 ;
     RECT  4.068 112.459 48.906 112.496 ;
     RECT  0.648 112.445 2.97 112.801 ;
     RECT  4.068 112.496 48.69 112.801 ;
     RECT  51.015 94.865 52.974 112.891 ;
     RECT  63.864 112.445 63.882 112.973 ;
     RECT  50.724 112.891 52.974 113.071 ;
     RECT  53.712 111.437 62.37 113.071 ;
     RECT  50.724 113.071 62.37 113.099 ;
     RECT  50.904 113.099 62.37 113.357 ;
     RECT  0.648 112.801 48.69 113.419 ;
     RECT  51.015 113.357 62.37 113.459 ;
     RECT  64.692 113.419 64.71 113.459 ;
     RECT  0.108 113.419 48.69 113.539 ;
     RECT  63.252 113.179 63.306 113.693 ;
     RECT  0.108 113.539 49.158 113.701 ;
     RECT  51.015 113.459 57.834 113.729 ;
     RECT  0.108 113.701 49.446 113.837 ;
     RECT  58.572 113.459 62.37 113.971 ;
     RECT  53.136 113.729 57.69 113.999 ;
     RECT  0.648 113.837 49.446 114.043 ;
     RECT  58.572 113.971 62.73 114.221 ;
     RECT  0.648 114.043 49.806 114.241 ;
     RECT  51.015 113.729 52.398 114.241 ;
     RECT  53.424 113.999 57.69 114.547 ;
     RECT  58.572 114.221 62.37 114.547 ;
     RECT  53.424 114.547 62.37 114.683 ;
     RECT  53.46 114.683 62.37 114.917 ;
     RECT  63.828 113.899 63.846 114.953 ;
     RECT  53.712 114.917 62.37 115.147 ;
     RECT  63.864 115.321 63.882 115.949 ;
     RECT  53.712 115.147 62.694 116.131 ;
     RECT  0.648 114.241 52.398 116.239 ;
     RECT  0.54 116.239 52.398 116.299 ;
     RECT  53.712 116.131 62.73 116.299 ;
     RECT  0.54 116.299 62.73 116.429 ;
     RECT  63.828 116.155 63.846 116.429 ;
     RECT  0.648 116.429 62.73 116.683 ;
     RECT  0.648 116.683 63.27 117.197 ;
     RECT  0.648 117.197 62.37 117.403 ;
     RECT  63.252 117.197 63.27 117.403 ;
     RECT  0.108 117.403 62.37 117.533 ;
     RECT  0.648 117.533 62.37 118.291 ;
     RECT  63.252 117.403 63.846 118.291 ;
     RECT  0.648 118.291 63.882 118.319 ;
     RECT  0.648 118.319 57.69 118.391 ;
     RECT  58.464 118.319 63.882 118.445 ;
     RECT  7.596 118.391 57.69 118.589 ;
     RECT  58.464 118.445 63.306 118.685 ;
     RECT  0.648 118.391 6.858 118.895 ;
     RECT  58.464 118.685 62.73 118.931 ;
     RECT  0.648 118.895 4.086 119.011 ;
     RECT  64.692 118.171 64.71 119.039 ;
     RECT  58.572 118.931 62.73 119.693 ;
     RECT  0.54 119.011 4.086 119.899 ;
     RECT  63.828 119.419 63.846 119.899 ;
     RECT  0.108 119.899 4.086 119.939 ;
     RECT  53.532 118.589 57.69 120.019 ;
     RECT  63.792 119.899 63.846 120.055 ;
     RECT  53.532 120.019 57.798 120.091 ;
     RECT  58.572 119.693 62.37 120.091 ;
     RECT  63.288 120.055 63.846 120.181 ;
     RECT  63.288 120.181 63.882 120.451 ;
     RECT  53.532 120.091 62.37 120.631 ;
     RECT  63.288 120.451 63.918 120.631 ;
     RECT  53.532 120.631 63.918 120.701 ;
     RECT  63.288 120.701 63.918 121.181 ;
     RECT  64.692 121.432 64.71 121.469 ;
     RECT  0.648 119.939 4.086 121.801 ;
     RECT  53.532 120.701 62.37 121.909 ;
     RECT  63.288 121.181 63.306 121.909 ;
     RECT  53.532 121.909 63.306 121.949 ;
     RECT  63.252 121.949 63.306 122.341 ;
     RECT  0.54 121.801 4.086 122.395 ;
     RECT  53.532 121.949 62.37 122.791 ;
     RECT  63.252 122.341 63.882 122.791 ;
     RECT  53.532 122.791 63.882 122.957 ;
     RECT  7.596 118.589 52.506 123.223 ;
     RECT  53.532 122.957 62.298 123.223 ;
     RECT  63.288 122.957 63.882 123.691 ;
     RECT  4.86 118.895 6.858 123.835 ;
     RECT  7.596 123.223 62.298 123.835 ;
     RECT  0.108 122.395 4.086 123.965 ;
     RECT  4.86 123.835 62.298 124.141 ;
     RECT  63.288 123.691 63.918 124.141 ;
     RECT  4.86 124.141 63.918 124.205 ;
     RECT  0.54 123.965 4.086 124.445 ;
     RECT  0.648 124.445 4.086 124.609 ;
     RECT  4.86 124.205 62.097 124.609 ;
     RECT  0.648 124.609 62.097 124.951 ;
     RECT  63.288 124.205 63.918 124.973 ;
     RECT  63.288 124.973 63.882 126.221 ;
     RECT  63.288 126.221 63.666 126.265 ;
     RECT  0.648 124.951 62.226 126.301 ;
     RECT  0.648 126.301 62.298 126.427 ;
     RECT  63.144 126.265 63.666 126.427 ;
     RECT  0.648 126.427 63.666 126.811 ;
     RECT  0.108 126.811 63.666 127.469 ;
     RECT  0.648 127.469 63.666 127.543 ;
     RECT  0.648 127.543 64.134 128.506 ;
     RECT  0.108 128.506 64.134 128.957 ;
     RECT  0.648 128.957 64.134 129.581 ;
    LAYER M4 ;
     RECT  0.025 18.768 0.06 18.792 ;
     RECT  0.06 0.672 0.137 128.952 ;
     RECT  0.137 0.672 0.533 128.712 ;
     RECT  0.533 0.672 0.569 87.432 ;
     RECT  0.569 0.672 1.757 80.184 ;
     RECT  1.757 0.912 2.408 80.184 ;
     RECT  0.569 81.168 2.408 86.952 ;
     RECT  0.533 88.416 2.408 128.712 ;
     RECT  2.408 0.912 2.704 128.712 ;
     RECT  2.704 0.912 2.765 13.944 ;
     RECT  2.704 22.752 2.819 41.496 ;
     RECT  2.704 79.776 2.909 79.992 ;
     RECT  2.765 0.912 3.053 2.28 ;
     RECT  2.704 17.904 3.053 21.192 ;
     RECT  3.053 1.392 3.089 2.28 ;
     RECT  2.704 86.64 3.089 110.28 ;
     RECT  3.089 91.44 3.125 110.28 ;
     RECT  3.089 1.392 3.161 1.944 ;
     RECT  2.704 111.408 3.253 128.712 ;
     RECT  2.819 22.752 3.305 27.912 ;
     RECT  2.704 66.72 3.377 78.696 ;
     RECT  3.053 17.904 3.413 20.664 ;
     RECT  2.765 3.36 3.521 13.944 ;
     RECT  3.521 3.36 3.629 6.072 ;
     RECT  3.377 75.84 3.629 78.696 ;
     RECT  3.305 22.752 3.697 23.16 ;
     RECT  2.704 42.48 3.697 65.688 ;
     RECT  3.377 66.72 3.697 74.712 ;
     RECT  2.819 29.088 3.733 41.496 ;
     RECT  3.697 42.48 3.733 74.712 ;
     RECT  3.733 29.088 3.827 74.712 ;
     RECT  3.089 86.64 3.925 90.072 ;
     RECT  3.161 1.392 3.953 1.416 ;
     RECT  3.125 98.928 3.98 110.28 ;
     RECT  3.253 111.408 3.98 129.48 ;
     RECT  3.521 7.152 3.985 13.944 ;
     RECT  2.704 14.928 3.985 16.68 ;
     RECT  3.629 4.272 3.989 6.072 ;
     RECT  3.827 29.088 4.025 51.432 ;
     RECT  2.909 79.968 4.025 79.992 ;
     RECT  3.125 91.44 4.025 97.704 ;
     RECT  3.985 7.152 4.061 16.68 ;
     RECT  4.025 44.64 4.061 49.56 ;
     RECT  4.025 50.64 4.061 51.432 ;
     RECT  3.827 52.416 4.061 74.712 ;
     RECT  4.025 91.44 4.061 96.312 ;
     RECT  3.989 4.848 4.097 6.072 ;
     RECT  4.061 9.504 4.097 16.68 ;
     RECT  4.061 45.264 4.115 49.56 ;
     RECT  3.305 24.48 4.129 27.912 ;
     RECT  4.061 52.416 4.169 61.176 ;
     RECT  3.925 86.448 4.169 90.072 ;
     RECT  3.413 17.904 4.201 18.168 ;
     RECT  4.025 97.488 4.237 97.704 ;
     RECT  3.98 98.928 4.237 129.48 ;
     RECT  4.025 29.184 4.259 43.272 ;
     RECT  4.169 86.448 4.259 86.664 ;
     RECT  2.704 80.976 4.273 85.464 ;
     RECT  4.259 86.448 4.273 86.616 ;
     RECT  4.061 91.44 4.273 96.072 ;
     RECT  4.097 4.848 4.277 5.544 ;
     RECT  4.237 97.488 4.277 129.48 ;
     RECT  4.277 113.472 4.349 129.48 ;
     RECT  4.349 113.712 4.403 129.48 ;
     RECT  3.697 22.128 4.453 23.16 ;
     RECT  4.097 15.264 4.457 16.68 ;
     RECT  4.115 45.264 4.499 49.128 ;
     RECT  4.169 87.792 4.529 90.072 ;
     RECT  4.061 62.16 4.549 74.712 ;
     RECT  3.629 75.84 4.549 76.248 ;
     RECT  3.629 77.424 4.549 78.696 ;
     RECT  4.273 80.976 4.561 86.616 ;
     RECT  4.277 5.136 4.565 5.544 ;
     RECT  4.499 48.672 4.565 49.128 ;
     RECT  4.273 91.056 4.565 96.072 ;
     RECT  4.403 113.712 4.565 128.712 ;
     RECT  4.565 48.96 4.595 49.128 ;
     RECT  4.457 15.264 4.601 15.72 ;
     RECT  4.259 29.184 4.673 37.656 ;
     RECT  4.259 38.688 4.745 43.272 ;
     RECT  4.549 77.424 4.745 78.888 ;
     RECT  4.565 91.056 4.817 91.176 ;
     RECT  4.745 40.752 4.835 43.272 ;
     RECT  4.835 40.752 4.853 41.496 ;
     RECT  3.413 19.92 4.921 20.664 ;
     RECT  4.453 22.08 4.921 23.16 ;
     RECT  4.529 88.416 4.925 90.072 ;
     RECT  4.565 92.16 4.925 96.072 ;
     RECT  4.853 40.752 4.931 40.776 ;
     RECT  4.061 7.152 4.957 8.232 ;
     RECT  4.129 24.48 4.979 28.152 ;
     RECT  4.921 19.92 5.029 23.16 ;
     RECT  4.979 24.48 5.029 25.464 ;
     RECT  4.201 17.664 5.065 18.168 ;
     RECT  4.499 45.264 5.065 47.688 ;
     RECT  4.097 9.504 5.069 13.944 ;
     RECT  4.673 32.64 5.075 37.656 ;
     RECT  4.745 77.424 5.075 78.696 ;
     RECT  5.069 12.528 5.101 13.944 ;
     RECT  4.601 15.264 5.101 15.288 ;
     RECT  4.561 80.928 5.137 86.616 ;
     RECT  4.979 26.736 5.141 28.152 ;
     RECT  4.061 50.64 5.141 51.288 ;
     RECT  5.065 17.664 5.173 18.696 ;
     RECT  5.141 26.832 5.177 28.152 ;
     RECT  5.075 32.64 5.177 37.176 ;
     RECT  4.745 38.688 5.177 39.624 ;
     RECT  5.075 77.424 5.177 78.456 ;
     RECT  4.925 88.416 5.177 89.832 ;
     RECT  4.925 93.888 5.177 96.072 ;
     RECT  4.277 97.488 5.177 111.96 ;
     RECT  5.137 80.88 5.209 86.616 ;
     RECT  4.565 5.52 5.249 5.544 ;
     RECT  5.101 12.528 5.267 15.288 ;
     RECT  5.177 93.984 5.281 96.072 ;
     RECT  5.177 88.704 5.321 89.832 ;
     RECT  5.029 19.92 5.324 25.464 ;
     RECT  5.177 38.688 5.353 38.76 ;
     RECT  4.595 48.96 5.357 49.08 ;
     RECT  5.209 80.496 5.357 86.616 ;
     RECT  4.565 113.712 5.357 125.688 ;
     RECT  4.957 6.72 5.363 8.232 ;
     RECT  5.357 118.176 5.363 125.688 ;
     RECT  5.281 93.984 5.365 96.408 ;
     RECT  5.177 97.488 5.365 111.912 ;
     RECT  5.321 89.808 5.393 89.832 ;
     RECT  5.357 113.712 5.413 117.048 ;
     RECT  5.065 44.4 5.414 47.688 ;
     RECT  5.141 50.832 5.425 51.288 ;
     RECT  4.169 52.464 5.425 61.176 ;
     RECT  5.173 17.664 5.461 18.792 ;
     RECT  5.267 12.768 5.465 15.288 ;
     RECT  5.425 50.832 5.465 61.176 ;
     RECT  5.414 44.448 5.5 47.688 ;
     RECT  5.177 27.168 5.533 28.152 ;
     RECT  4.673 29.184 5.533 31.656 ;
     RECT  5.465 50.832 5.537 53.544 ;
     RECT  4.549 62.16 5.537 74.76 ;
     RECT  5.461 16.944 5.555 18.792 ;
     RECT  5.324 19.872 5.573 25.464 ;
     RECT  5.533 27.168 5.573 31.656 ;
     RECT  5.365 93.984 5.573 111.912 ;
     RECT  5.537 62.544 5.609 74.76 ;
     RECT  5.413 113.424 5.651 117.048 ;
     RECT  5.573 27.408 5.681 31.656 ;
     RECT  5.177 32.64 5.681 35.736 ;
     RECT  5.609 62.544 5.681 66.12 ;
     RECT  5.651 113.952 5.681 117.048 ;
     RECT  4.835 42.576 5.753 43.272 ;
     RECT  5.681 30.768 5.789 31.656 ;
     RECT  5.555 17.664 5.825 18.792 ;
     RECT  5.177 37.056 5.825 37.176 ;
     RECT  4.925 92.16 5.843 92.712 ;
     RECT  4.565 126.816 5.845 128.712 ;
     RECT  5.681 28.464 5.884 29.4 ;
     RECT  5.573 25.296 5.891 25.464 ;
     RECT  5.5 45.024 5.897 47.688 ;
     RECT  5.609 67.104 5.929 74.76 ;
     RECT  4.549 75.792 5.929 76.248 ;
     RECT  5.363 118.32 5.929 125.688 ;
     RECT  5.845 126.816 5.929 129.48 ;
     RECT  4.817 91.104 5.965 91.176 ;
     RECT  5.465 14.88 6.073 15.288 ;
     RECT  5.753 42.576 6.077 42.744 ;
     RECT  5.929 118.32 6.083 129.48 ;
     RECT  5.929 67.104 6.113 76.248 ;
     RECT  5.537 50.832 6.181 51.192 ;
     RECT  5.825 37.056 6.217 37.08 ;
     RECT  6.181 40.464 6.217 40.488 ;
     RECT  5.573 93.984 6.221 107.736 ;
     RECT  5.884 28.464 6.227 28.488 ;
     RECT  5.891 25.44 6.229 25.464 ;
     RECT  5.965 91.104 6.253 91.608 ;
     RECT  5.177 77.52 6.277 78.456 ;
     RECT  5.357 83.904 6.277 86.616 ;
     RECT  6.113 67.104 6.323 73.608 ;
     RECT  6.217 40.464 6.325 41.064 ;
     RECT  6.181 50.736 6.325 51.192 ;
     RECT  6.083 118.32 6.325 128.712 ;
     RECT  5.897 45.024 6.329 45.336 ;
     RECT  6.323 71.808 6.365 73.608 ;
     RECT  6.329 45.264 6.371 45.336 ;
     RECT  5.825 18.048 6.373 18.792 ;
     RECT  5.573 19.872 6.373 24.072 ;
     RECT  6.277 77.52 6.397 78.696 ;
     RECT  5.357 80.496 6.397 82.872 ;
     RECT  6.221 93.984 6.397 107.544 ;
     RECT  5.681 113.952 6.401 116.952 ;
     RECT  5.681 33.024 6.433 35.736 ;
     RECT  6.217 37.008 6.433 37.08 ;
     RECT  6.371 45.264 6.437 45.288 ;
     RECT  6.323 67.104 6.437 70.44 ;
     RECT  6.365 71.856 6.437 73.608 ;
     RECT  6.421 90.048 6.469 90.072 ;
     RECT  6.253 91.056 6.469 91.608 ;
     RECT  6.325 50.688 6.505 51.192 ;
     RECT  5.537 52.176 6.505 53.544 ;
     RECT  6.325 39.744 6.515 41.064 ;
     RECT  6.397 77.52 6.515 79.224 ;
     RECT  5.321 88.704 6.541 88.728 ;
     RECT  6.515 39.744 6.545 40.488 ;
     RECT  6.401 114.24 6.545 116.952 ;
     RECT  5.069 9.504 6.563 11.208 ;
     RECT  6.545 39.744 6.563 40.296 ;
     RECT  6.229 25.44 6.581 26.136 ;
     RECT  5.681 62.736 6.649 66.12 ;
     RECT  6.437 67.104 6.649 70.152 ;
     RECT  6.113 74.592 6.649 76.248 ;
     RECT  5.465 12.768 6.659 13.896 ;
     RECT  6.373 18.048 6.689 24.072 ;
     RECT  6.433 33.024 6.689 37.08 ;
     RECT  6.515 77.52 6.707 79.032 ;
     RECT  6.073 14.88 6.709 15.576 ;
     RECT  5.843 92.688 6.709 92.712 ;
     RECT  6.397 93.84 6.709 107.544 ;
     RECT  5.573 108.864 6.716 111.912 ;
     RECT  6.505 50.688 6.721 53.544 ;
     RECT  5.465 54.672 6.721 61.176 ;
     RECT  6.689 34.8 6.755 37.08 ;
     RECT  6.755 35.04 6.797 37.08 ;
     RECT  6.716 108.864 6.803 112.392 ;
     RECT  5.789 30.912 6.829 31.656 ;
     RECT  6.689 33.024 6.829 33.672 ;
     RECT  6.397 80.304 6.833 82.872 ;
     RECT  6.709 92.688 6.833 107.544 ;
     RECT  6.325 118.032 6.833 128.712 ;
     RECT  6.829 30.912 6.853 33.672 ;
     RECT  6.833 80.592 6.853 82.872 ;
     RECT  6.277 83.904 6.853 86.808 ;
     RECT  6.853 30.72 6.865 33.672 ;
     RECT  5.897 46.656 6.901 47.688 ;
     RECT  5.357 48.96 6.901 48.984 ;
     RECT  5.681 27.408 6.908 27.432 ;
     RECT  6.721 50.688 6.937 61.176 ;
     RECT  6.901 46.656 6.965 48.984 ;
     RECT  6.937 50.304 6.965 61.176 ;
     RECT  6.908 27.408 6.973 27.912 ;
     RECT  5.353 38.16 7.009 38.76 ;
     RECT  6.563 39.744 7.009 39.768 ;
     RECT  6.659 12.768 7.117 13.368 ;
     RECT  6.649 74.592 7.117 76.344 ;
     RECT  6.545 114.288 7.117 116.952 ;
     RECT  6.833 118.032 7.117 127.704 ;
     RECT  6.437 71.904 7.153 73.608 ;
     RECT  7.117 74.592 7.153 76.392 ;
     RECT  6.965 46.656 7.225 61.176 ;
     RECT  6.541 88.704 7.225 88.92 ;
     RECT  6.833 105.36 7.261 107.544 ;
     RECT  6.853 80.592 7.285 86.808 ;
     RECT  6.689 18.672 7.405 24.072 ;
     RECT  6.649 62.736 7.549 70.152 ;
     RECT  6.707 77.856 7.549 79.032 ;
     RECT  7.549 77.856 7.621 79.08 ;
     RECT  7.549 62.736 7.729 70.392 ;
     RECT  7.153 71.904 7.729 76.392 ;
     RECT  5.363 7.104 7.808 8.232 ;
     RECT  6.563 9.504 7.808 9.528 ;
     RECT  6.563 11.184 7.808 11.208 ;
     RECT  7.117 12.336 7.808 13.368 ;
     RECT  6.709 14.352 7.808 15.576 ;
     RECT  7.405 18.672 7.808 24.216 ;
     RECT  6.581 25.44 7.808 25.752 ;
     RECT  6.973 26.784 7.808 27.912 ;
     RECT  7.004 29.04 7.808 29.064 ;
     RECT  6.865 30.672 7.808 33.672 ;
     RECT  6.797 35.424 7.808 37.08 ;
     RECT  7.009 38.16 7.808 39.768 ;
     RECT  6.517 41.904 7.808 41.928 ;
     RECT  7.297 43.008 7.808 43.032 ;
     RECT  7.225 46.608 7.808 61.176 ;
     RECT  7.729 62.736 7.808 76.392 ;
     RECT  7.621 77.856 7.808 79.176 ;
     RECT  7.285 80.592 7.808 87.288 ;
     RECT  7.225 88.368 7.808 88.92 ;
     RECT  6.469 90.048 7.808 91.608 ;
     RECT  6.833 92.688 7.808 104.28 ;
     RECT  7.261 105.36 7.808 107.832 ;
     RECT  6.803 108.864 7.808 111.96 ;
     RECT  7.117 114.288 7.808 127.704 ;
     RECT  6.833 128.688 7.813 128.712 ;
     RECT  7.808 2.148 7.912 127.704 ;
     RECT  7.912 2.418 8.104 127.704 ;
     RECT  8.104 77.52 8.129 79.032 ;
     RECT  8.104 63.648 8.243 70.392 ;
     RECT  8.104 71.616 8.243 76.296 ;
     RECT  8.104 105.36 8.273 107.832 ;
     RECT  8.104 41.856 8.291 42.024 ;
     RECT  8.243 72 8.291 76.296 ;
     RECT  8.104 94.56 8.291 103.752 ;
     RECT  8.104 38.16 8.339 38.424 ;
     RECT  8.104 115.872 8.341 127.704 ;
     RECT  7.813 128.688 8.341 128.808 ;
     RECT  8.104 46.848 8.345 61.176 ;
     RECT  8.104 109.248 8.345 114.312 ;
     RECT  8.291 41.856 8.387 41.928 ;
     RECT  8.291 72.096 8.387 76.296 ;
     RECT  8.345 46.848 8.417 52.44 ;
     RECT  8.339 38.16 8.428 38.184 ;
     RECT  8.104 35.376 8.489 35.496 ;
     RECT  8.345 53.52 8.489 61.176 ;
     RECT  8.104 12.192 8.524 13.272 ;
     RECT  8.417 46.896 8.525 52.44 ;
     RECT  8.129 77.52 8.561 78.6 ;
     RECT  8.525 47.088 8.597 52.44 ;
     RECT  8.104 28.464 8.627 29.4 ;
     RECT  8.273 105.36 8.675 107.592 ;
     RECT  8.104 7.104 8.741 8.52 ;
     RECT  8.104 18.72 8.777 21.672 ;
     RECT  8.597 47.136 8.841 52.44 ;
     RECT  8.345 110.88 8.849 114.312 ;
     RECT  8.341 115.872 8.867 128.808 ;
     RECT  8.387 72.144 8.921 76.296 ;
     RECT  8.104 23.568 9.065 27.336 ;
     RECT  9.065 23.568 9.097 25.32 ;
     RECT  8.849 111.024 9.101 114.312 ;
     RECT  8.243 63.648 9.109 69.528 ;
     RECT  8.867 117.792 9.209 128.808 ;
     RECT  8.921 75.168 9.245 76.296 ;
     RECT  9.209 128.784 9.301 128.808 ;
     RECT  8.921 72.144 9.381 74.04 ;
     RECT  8.104 31.344 9.389 31.368 ;
     RECT  9.301 128.784 9.443 129.48 ;
     RECT  8.524 12.192 9.497 12.888 ;
     RECT  9.443 128.784 9.569 128.808 ;
     RECT  8.841 47.136 9.605 51.192 ;
     RECT  9.109 62.976 9.605 69.528 ;
     RECT  8.627 28.464 9.677 28.488 ;
     RECT  9.605 48.384 9.713 51.192 ;
     RECT  8.561 77.52 9.817 78.456 ;
     RECT  8.104 80.784 9.923 87.288 ;
     RECT  9.065 26.4 9.925 27.336 ;
     RECT  8.777 18.816 9.961 21.672 ;
     RECT  8.489 35.376 9.971 35.448 ;
     RECT  9.097 23.136 10.033 25.32 ;
     RECT  9.605 63.264 10.037 69.528 ;
     RECT  9.817 70.704 10.037 70.728 ;
     RECT  10.033 22.752 10.069 25.32 ;
     RECT  9.925 26.4 10.069 27.768 ;
     RECT  10.069 22.752 10.115 27.768 ;
     RECT  9.925 28.8 10.145 28.824 ;
     RECT  10.115 24.24 10.163 27.768 ;
     RECT  9.817 77.52 10.309 78.648 ;
     RECT  9.497 12.528 10.325 12.888 ;
     RECT  9.209 117.792 10.355 127.752 ;
     RECT  9.925 30.432 10.361 30.456 ;
     RECT  9.961 18.768 10.501 21.672 ;
     RECT  10.501 17.856 10.505 21.672 ;
     RECT  10.505 17.856 10.547 20.136 ;
     RECT  10.309 77.52 10.549 79.224 ;
     RECT  9.245 75.168 10.597 76.104 ;
     RECT  10.549 77.52 10.636 79.656 ;
     RECT  10.115 22.752 10.685 22.776 ;
     RECT  10.547 19.488 10.721 20.136 ;
     RECT  10.355 117.792 10.721 127.704 ;
     RECT  9.713 48.384 10.753 49.56 ;
     RECT  8.104 14.256 10.757 15.288 ;
     RECT  10.636 77.52 10.78 79.608 ;
     RECT  10.78 77.52 10.787 79.464 ;
     RECT  8.675 105.36 10.825 106.44 ;
     RECT  10.645 129.456 10.835 129.48 ;
     RECT  10.547 17.856 10.865 17.88 ;
     RECT  10.163 26.256 10.885 27.768 ;
     RECT  8.387 41.904 10.901 41.928 ;
     RECT  10.721 117.792 10.901 127.128 ;
     RECT  9.923 80.784 10.945 83.496 ;
     RECT  10.505 21.12 11.081 21.672 ;
     RECT  9.381 72.144 11.113 73.992 ;
     RECT  10.597 75.168 11.113 76.488 ;
     RECT  10.885 26.256 11.123 28.488 ;
     RECT  11.113 72.144 11.189 76.488 ;
     RECT  11.189 74.688 11.276 76.488 ;
     RECT  10.163 24.24 11.293 25.176 ;
     RECT  11.276 74.688 11.297 76.632 ;
     RECT  9.605 47.136 11.329 47.16 ;
     RECT  11.297 75.648 11.363 76.632 ;
     RECT  8.104 44.64 11.365 44.664 ;
     RECT  11.329 46.752 11.413 47.16 ;
     RECT  11.123 26.256 11.555 26.28 ;
     RECT  11.293 23.712 11.596 25.176 ;
     RECT  10.787 77.856 11.729 79.464 ;
     RECT  11.729 77.856 11.765 78.456 ;
     RECT  11.363 75.648 12.161 76.488 ;
     RECT  11.729 79.44 12.161 79.464 ;
     RECT  12.181 129.456 12.323 129.48 ;
     RECT  11.765 77.856 12.764 77.88 ;
     RECT  12.764 77.856 13.093 77.976 ;
     RECT  8.741 7.104 13.208 8.184 ;
     RECT  8.104 9.504 13.208 9.528 ;
     RECT  8.104 11.184 13.208 11.208 ;
     RECT  10.325 12.816 13.208 12.888 ;
     RECT  10.757 14.352 13.208 15.288 ;
     RECT  10.721 20.112 13.208 20.136 ;
     RECT  11.081 21.12 13.208 21.144 ;
     RECT  11.596 23.712 13.208 23.736 ;
     RECT  11.596 25.152 13.208 25.176 ;
     RECT  11.123 27.312 13.208 28.2 ;
     RECT  8.104 32.784 13.208 32.808 ;
     RECT  9.971 35.424 13.208 35.448 ;
     RECT  8.104 43.008 13.208 43.032 ;
     RECT  11.365 44.352 13.208 44.664 ;
     RECT  11.413 47.136 13.208 47.16 ;
     RECT  10.753 48.24 13.208 49.56 ;
     RECT  9.713 51.168 13.208 51.192 ;
     RECT  8.841 52.176 13.208 52.44 ;
     RECT  8.489 53.52 13.208 60.6 ;
     RECT  10.037 63.552 13.208 69.528 ;
     RECT  11.189 72.144 13.208 73.368 ;
     RECT  12.161 75.648 13.208 75.72 ;
     RECT  13.093 77.664 13.208 78.216 ;
     RECT  10.945 80.784 13.208 81.72 ;
     RECT  10.945 83.472 13.208 83.496 ;
     RECT  9.923 84.624 13.208 87.288 ;
     RECT  8.104 91.584 13.208 91.608 ;
     RECT  8.104 92.688 13.208 93 ;
     RECT  8.291 94.56 13.208 100.008 ;
     RECT  8.291 101.328 13.208 103.752 ;
     RECT  10.825 105.36 13.208 106.536 ;
     RECT  8.675 107.568 13.208 107.592 ;
     RECT  8.345 109.824 13.208 109.848 ;
     RECT  9.101 111.024 13.208 112.2 ;
     RECT  9.101 113.328 13.208 114.312 ;
     RECT  8.867 115.872 13.208 116.76 ;
     RECT  10.901 117.792 13.208 126.696 ;
     RECT  13.208 2.148 13.285 127.452 ;
     RECT  13.285 2.148 13.312 128.232 ;
     RECT  13.312 2.418 13.504 127.182 ;
     RECT  13.312 128.208 13.709 128.232 ;
     RECT  13.504 79.776 14.365 79.8 ;
     RECT  13.504 80.784 14.732 81.72 ;
     RECT  14.732 80.64 14.819 81.72 ;
     RECT  14.819 80.784 16.481 81.72 ;
     RECT  16.721 129.456 16.805 129.48 ;
     RECT  16.481 81.36 17.228 81.72 ;
     RECT  17.228 81.36 17.737 82.056 ;
     RECT  13.504 83.472 17.737 83.496 ;
     RECT  18.188 128.832 18.275 128.856 ;
     RECT  13.504 7.104 18.608 8.184 ;
     RECT  13.504 9.504 18.608 9.528 ;
     RECT  13.504 11.184 18.608 11.208 ;
     RECT  13.504 12.816 18.608 12.888 ;
     RECT  13.504 14.352 18.608 15.288 ;
     RECT  13.504 20.112 18.608 20.136 ;
     RECT  13.504 21.12 18.608 21.144 ;
     RECT  13.504 25.152 18.608 25.176 ;
     RECT  13.504 27.312 18.608 28.2 ;
     RECT  13.504 29.472 18.608 29.496 ;
     RECT  13.504 32.784 18.608 32.808 ;
     RECT  13.504 35.424 18.608 35.448 ;
     RECT  13.504 43.008 18.608 43.032 ;
     RECT  13.504 44.352 18.608 44.664 ;
     RECT  13.504 47.136 18.608 47.16 ;
     RECT  13.504 48.24 18.608 49.56 ;
     RECT  13.504 51.168 18.608 51.192 ;
     RECT  13.504 52.176 18.608 52.2 ;
     RECT  13.504 53.52 18.608 60.6 ;
     RECT  13.504 63.552 18.608 69.528 ;
     RECT  13.504 72.144 18.608 73.368 ;
     RECT  13.504 75.696 18.608 75.72 ;
     RECT  13.504 77.664 18.608 77.688 ;
     RECT  17.053 80.112 18.608 80.136 ;
     RECT  17.737 81.36 18.608 83.496 ;
     RECT  13.504 84.624 18.608 87.288 ;
     RECT  13.504 91.584 18.608 91.608 ;
     RECT  13.504 92.688 18.608 93 ;
     RECT  13.504 94.56 18.608 100.008 ;
     RECT  13.504 101.328 18.608 103.752 ;
     RECT  13.504 105.36 18.608 106.44 ;
     RECT  13.504 107.568 18.608 107.592 ;
     RECT  13.504 109.824 18.608 109.848 ;
     RECT  13.504 111.024 18.608 112.2 ;
     RECT  13.504 113.328 18.608 114.312 ;
     RECT  13.504 115.872 18.608 116.76 ;
     RECT  13.504 117.792 18.608 126.696 ;
     RECT  18.608 2.148 18.712 127.452 ;
     RECT  18.469 129.456 18.803 129.48 ;
     RECT  18.712 2.418 18.904 127.182 ;
     RECT  18.904 92.688 19.283 100.008 ;
     RECT  18.904 83.472 20.195 83.496 ;
     RECT  19.283 92.688 20.684 93 ;
     RECT  20.684 92.688 20.771 93.384 ;
     RECT  18.904 84.624 20.965 87.288 ;
     RECT  18.904 91.584 21.193 91.608 ;
     RECT  20.771 92.688 21.193 93 ;
     RECT  21.193 91.584 21.491 93 ;
     RECT  20.965 84.576 21.701 87.288 ;
     RECT  22.172 128.832 22.259 128.856 ;
     RECT  22.661 129.408 22.745 129.48 ;
     RECT  21.491 91.584 22.805 91.608 ;
     RECT  21.491 92.688 22.805 93 ;
     RECT  18.904 101.328 22.813 103.752 ;
     RECT  18.904 105.36 22.813 106.44 ;
     RECT  18.904 113.328 22.813 114.312 ;
     RECT  22.813 113.232 22.853 114.312 ;
     RECT  22.745 129.408 23.285 129.432 ;
     RECT  21.701 84.576 23.317 84.6 ;
     RECT  21.701 85.632 23.317 87.288 ;
     RECT  23.677 88.896 23.701 88.92 ;
     RECT  18.904 7.104 24.008 8.184 ;
     RECT  18.904 9.504 24.008 9.528 ;
     RECT  18.904 11.184 24.008 11.208 ;
     RECT  18.904 12.816 24.008 12.888 ;
     RECT  18.904 14.352 24.008 15.288 ;
     RECT  18.904 20.112 24.008 20.136 ;
     RECT  18.904 21.12 24.008 21.144 ;
     RECT  18.904 25.152 24.008 25.176 ;
     RECT  18.904 27.312 24.008 28.2 ;
     RECT  18.904 29.472 24.008 29.496 ;
     RECT  18.904 32.784 24.008 32.808 ;
     RECT  18.904 35.424 24.008 35.448 ;
     RECT  18.904 43.008 24.008 43.032 ;
     RECT  18.904 44.352 24.008 44.664 ;
     RECT  18.904 47.136 24.008 47.16 ;
     RECT  18.904 48.24 24.008 49.56 ;
     RECT  18.904 51.168 24.008 51.192 ;
     RECT  18.904 52.176 24.008 52.2 ;
     RECT  18.904 53.52 24.008 60.6 ;
     RECT  18.904 63.552 24.008 69.528 ;
     RECT  18.904 72.144 24.008 73.368 ;
     RECT  18.904 75.696 24.008 75.72 ;
     RECT  18.904 77.664 24.008 77.688 ;
     RECT  18.904 80.112 24.008 80.136 ;
     RECT  18.904 81.648 24.008 81.672 ;
     RECT  23.317 84.576 24.008 87.288 ;
     RECT  23.701 88.368 24.008 88.92 ;
     RECT  22.805 91.584 24.008 93 ;
     RECT  19.283 94.56 24.008 100.008 ;
     RECT  22.813 101.328 24.008 103.848 ;
     RECT  22.813 105.36 24.008 106.536 ;
     RECT  18.904 107.568 24.008 107.592 ;
     RECT  18.904 109.824 24.008 109.848 ;
     RECT  18.904 111.024 24.008 112.2 ;
     RECT  22.853 113.232 24.008 113.256 ;
     RECT  22.853 114.288 24.008 114.312 ;
     RECT  18.904 115.872 24.008 116.76 ;
     RECT  18.904 117.792 24.008 126.696 ;
     RECT  24.008 2.148 24.112 127.452 ;
     RECT  24.112 2.418 24.304 127.182 ;
     RECT  24.304 84.576 24.419 87.48 ;
     RECT  24.181 129.456 24.419 129.48 ;
     RECT  24.304 91.584 24.445 93 ;
     RECT  24.419 84.576 24.473 87.288 ;
     RECT  24.304 88.752 24.755 88.776 ;
     RECT  24.304 90.048 25.273 90.072 ;
     RECT  25.649 129.456 25.733 129.48 ;
     RECT  26.156 128.832 26.243 128.856 ;
     RECT  24.445 91.584 26.629 91.608 ;
     RECT  26.629 91.2 26.723 91.608 ;
     RECT  26.723 91.584 27.133 91.608 ;
     RECT  24.445 92.688 27.133 93 ;
     RECT  27.133 91.584 27.757 93 ;
     RECT  27.757 91.584 27.965 91.608 ;
     RECT  27.757 92.688 28.573 93 ;
     RECT  24.304 94.56 28.573 100.008 ;
     RECT  24.304 7.104 29.408 8.184 ;
     RECT  24.304 9.504 29.408 9.528 ;
     RECT  24.304 11.184 29.408 11.208 ;
     RECT  24.304 12.816 29.408 12.888 ;
     RECT  24.304 14.352 29.408 15.288 ;
     RECT  24.304 20.112 29.408 20.136 ;
     RECT  24.304 21.12 29.408 21.144 ;
     RECT  24.304 25.152 29.408 25.176 ;
     RECT  24.304 27.312 29.408 28.2 ;
     RECT  24.304 29.472 29.408 29.496 ;
     RECT  24.304 32.784 29.408 32.808 ;
     RECT  24.304 35.424 29.408 35.448 ;
     RECT  24.304 43.008 29.408 43.032 ;
     RECT  24.304 44.352 29.408 44.664 ;
     RECT  24.304 47.136 29.408 47.16 ;
     RECT  24.304 48.24 29.408 49.56 ;
     RECT  24.304 51.168 29.408 51.192 ;
     RECT  24.304 52.176 29.408 52.2 ;
     RECT  24.304 53.52 29.408 60.6 ;
     RECT  24.304 63.552 29.408 69.528 ;
     RECT  24.304 72.144 29.408 73.368 ;
     RECT  24.304 75.696 29.408 75.72 ;
     RECT  24.304 77.664 29.408 77.688 ;
     RECT  24.304 80.112 29.408 80.136 ;
     RECT  24.304 81.648 29.408 81.672 ;
     RECT  24.473 84.576 29.408 86.76 ;
     RECT  28.465 91.392 29.408 91.416 ;
     RECT  28.573 92.688 29.408 100.008 ;
     RECT  24.304 101.328 29.408 103.752 ;
     RECT  24.304 105.36 29.408 106.44 ;
     RECT  24.304 107.568 29.408 107.592 ;
     RECT  24.304 109.824 29.408 109.848 ;
     RECT  24.304 111.024 29.408 112.2 ;
     RECT  24.304 113.328 29.408 114.312 ;
     RECT  24.304 115.872 29.408 116.76 ;
     RECT  24.304 117.792 29.408 126.696 ;
     RECT  29.408 2.148 29.512 127.452 ;
     RECT  29.512 2.418 29.704 127.182 ;
     RECT  29.653 129.456 29.765 129.48 ;
     RECT  29.689 0.096 29.891 0.12 ;
     RECT  29.704 93.216 30.22 100.008 ;
     RECT  29.704 101.328 30.769 103.752 ;
     RECT  29.704 105.36 30.769 106.44 ;
     RECT  30.22 94.56 31.277 100.008 ;
     RECT  31.381 39.888 31.525 39.912 ;
     RECT  31.525 39.504 31.745 39.912 ;
     RECT  29.704 35.424 31.861 35.448 ;
     RECT  31.861 34.896 31.907 35.448 ;
     RECT  32.597 129.456 32.681 129.48 ;
     RECT  31.745 39.888 33.589 39.912 ;
     RECT  33.589 39.792 33.635 39.912 ;
     RECT  31.277 95.136 33.725 100.008 ;
     RECT  33.725 98.496 34.585 100.008 ;
     RECT  33.725 95.136 34.693 97.272 ;
     RECT  34.585 98.496 34.693 100.296 ;
     RECT  29.704 7.104 34.808 8.184 ;
     RECT  29.704 9.504 34.808 9.528 ;
     RECT  29.704 11.184 34.808 11.208 ;
     RECT  29.704 12.816 34.808 12.888 ;
     RECT  29.704 14.352 34.808 15.288 ;
     RECT  29.704 20.112 34.808 20.136 ;
     RECT  29.704 21.12 34.808 21.144 ;
     RECT  29.704 25.152 34.808 25.176 ;
     RECT  29.704 27.312 34.808 28.2 ;
     RECT  29.704 29.472 34.808 29.496 ;
     RECT  29.704 32.784 34.808 32.808 ;
     RECT  31.907 34.896 34.808 34.92 ;
     RECT  33.635 39.792 34.808 39.816 ;
     RECT  29.704 43.008 34.808 43.032 ;
     RECT  29.704 44.352 34.808 44.664 ;
     RECT  29.704 47.136 34.808 47.16 ;
     RECT  29.704 48.24 34.808 49.56 ;
     RECT  29.704 51.168 34.808 51.192 ;
     RECT  29.704 52.176 34.808 52.2 ;
     RECT  29.704 53.52 34.808 60.6 ;
     RECT  29.704 63.552 34.808 69.528 ;
     RECT  29.704 72.144 34.808 73.368 ;
     RECT  29.704 75.696 34.808 75.72 ;
     RECT  29.704 77.664 34.808 77.688 ;
     RECT  29.704 80.112 34.808 80.136 ;
     RECT  29.704 81.648 34.808 81.672 ;
     RECT  29.704 84.576 34.808 86.76 ;
     RECT  29.704 91.392 34.808 91.416 ;
     RECT  30.22 93.216 34.808 93.48 ;
     RECT  34.693 95.136 34.808 100.296 ;
     RECT  30.769 101.328 34.808 103.848 ;
     RECT  30.769 105.36 34.808 106.536 ;
     RECT  29.704 107.568 34.808 107.592 ;
     RECT  29.704 109.824 34.808 109.848 ;
     RECT  29.704 111.024 34.808 112.2 ;
     RECT  29.704 113.328 34.808 114.312 ;
     RECT  29.704 115.872 34.808 116.76 ;
     RECT  29.704 117.792 34.808 126.696 ;
     RECT  34.808 2.148 34.912 127.452 ;
     RECT  34.912 2.418 35.104 127.182 ;
     RECT  35.125 129.408 35.651 129.432 ;
     RECT  35.104 98.112 35.747 103.848 ;
     RECT  35.747 98.112 35.957 100.008 ;
     RECT  35.104 39.792 36.821 39.816 ;
     RECT  36.053 129.456 37.145 129.48 ;
     RECT  35.747 101.328 38.261 103.848 ;
     RECT  38.348 4.272 38.389 4.296 ;
     RECT  35.104 5.472 38.389 5.496 ;
     RECT  38.389 4.272 38.435 5.496 ;
     RECT  38.261 101.616 38.581 103.848 ;
     RECT  38.581 101.616 38.665 104.28 ;
     RECT  38.665 101.616 38.729 103.848 ;
     RECT  35.104 105.36 38.761 106.44 ;
     RECT  38.729 101.616 38.873 102.984 ;
     RECT  35.104 7.104 38.876 8.184 ;
     RECT  35.104 9.504 38.876 9.528 ;
     RECT  38.435 5.136 38.963 5.496 ;
     RECT  38.876 7.104 38.963 9.528 ;
     RECT  35.104 11.184 38.977 11.208 ;
     RECT  38.761 105.36 39.02 106.536 ;
     RECT  38.963 9.504 39.337 9.528 ;
     RECT  38.977 11.184 39.877 11.64 ;
     RECT  35.104 12.816 39.877 12.888 ;
     RECT  39.337 9.504 39.973 10.2 ;
     RECT  39.877 11.184 39.973 12.888 ;
     RECT  38.963 7.104 39.985 8.184 ;
     RECT  39.973 9.504 39.985 13.08 ;
     RECT  39.337 2.832 40.208 2.856 ;
     RECT  39.884 4.272 40.208 4.296 ;
     RECT  39.985 7.104 40.208 13.08 ;
     RECT  35.104 14.352 40.208 15.288 ;
     RECT  38.917 17.184 40.208 17.208 ;
     RECT  35.104 20.112 40.208 20.136 ;
     RECT  35.104 21.12 40.208 21.144 ;
     RECT  39.985 24.096 40.208 24.12 ;
     RECT  35.104 25.152 40.208 25.176 ;
     RECT  35.104 27.312 40.208 28.2 ;
     RECT  35.104 29.472 40.208 29.496 ;
     RECT  35.104 32.784 40.208 32.808 ;
     RECT  35.104 34.896 40.208 34.92 ;
     RECT  38.329 39.744 40.208 39.768 ;
     RECT  35.104 43.008 40.208 43.032 ;
     RECT  35.104 44.352 40.208 44.664 ;
     RECT  35.104 47.136 40.208 47.16 ;
     RECT  35.104 48.24 40.208 49.56 ;
     RECT  35.104 51.168 40.208 51.192 ;
     RECT  35.104 52.176 40.208 52.2 ;
     RECT  35.104 53.52 40.208 60.6 ;
     RECT  35.104 63.552 40.208 69.528 ;
     RECT  35.104 72.144 40.208 73.368 ;
     RECT  35.104 75.696 40.208 75.72 ;
     RECT  35.104 77.664 40.208 77.688 ;
     RECT  35.104 80.112 40.208 80.136 ;
     RECT  35.104 81.648 40.208 81.672 ;
     RECT  35.104 84.576 40.208 86.76 ;
     RECT  35.104 91.296 40.208 91.32 ;
     RECT  35.104 93.216 40.208 93.48 ;
     RECT  35.104 95.136 40.208 97.128 ;
     RECT  35.957 98.112 40.208 99.72 ;
     RECT  38.873 101.616 40.208 102.744 ;
     RECT  39.02 104.832 40.208 106.536 ;
     RECT  35.104 107.568 40.208 107.592 ;
     RECT  35.104 109.824 40.208 109.848 ;
     RECT  35.104 111.024 40.208 112.2 ;
     RECT  35.104 113.328 40.208 114.312 ;
     RECT  35.104 115.872 40.208 116.76 ;
     RECT  35.104 117.792 40.208 126.696 ;
     RECT  40.208 2.148 40.312 127.452 ;
     RECT  40.312 2.418 40.504 127.182 ;
     RECT  40.525 129.456 40.609 129.48 ;
     RECT  40.504 2.832 40.643 3.432 ;
     RECT  40.504 7.104 40.643 9.528 ;
     RECT  40.504 17.184 40.817 17.832 ;
     RECT  40.301 0.096 40.861 0.12 ;
     RECT  40.504 11.184 40.925 15.672 ;
     RECT  40.504 21.12 41.02 21.384 ;
     RECT  40.817 17.28 41.123 17.304 ;
     RECT  40.504 38.784 41.123 39.912 ;
     RECT  40.925 14.352 41.171 15.672 ;
     RECT  40.504 19.488 41.213 20.136 ;
     RECT  41.123 39.888 41.315 39.912 ;
     RECT  41.213 19.536 41.429 20.136 ;
     RECT  40.504 105.36 41.516 106.584 ;
     RECT  40.504 107.568 41.516 107.592 ;
     RECT  40.925 11.184 41.537 13.08 ;
     RECT  41.123 38.784 41.603 38.808 ;
     RECT  40.643 3.408 41.789 3.432 ;
     RECT  40.504 27.312 41.821 28.2 ;
     RECT  41.429 20.112 41.893 20.136 ;
     RECT  41.02 21.12 41.893 21.144 ;
     RECT  41.537 12.816 42.133 13.08 ;
     RECT  41.821 26.784 42.229 28.2 ;
     RECT  42.133 12.816 42.257 13.128 ;
     RECT  41.516 105.36 42.257 107.592 ;
     RECT  40.504 24.096 42.275 24.12 ;
     RECT  40.504 47.136 42.361 47.16 ;
     RECT  40.504 48.24 42.361 49.56 ;
     RECT  42.289 0.528 42.605 0.552 ;
     RECT  42.533 129.456 42.617 129.48 ;
     RECT  42.229 26.256 42.649 28.2 ;
     RECT  42.257 105.504 42.755 107.592 ;
     RECT  42.361 47.136 42.757 49.56 ;
     RECT  42.755 107.568 43.004 107.592 ;
     RECT  42.605 0.096 43.091 0.552 ;
     RECT  43.004 107.568 43.091 108.504 ;
     RECT  41.537 11.184 43.189 11.208 ;
     RECT  42.757 47.04 43.475 49.56 ;
     RECT  40.504 109.824 43.477 109.848 ;
     RECT  43.091 0.096 43.553 0.12 ;
     RECT  43.477 109.296 43.571 109.848 ;
     RECT  41.893 20.112 43.619 21.144 ;
     RECT  40.504 25.152 43.837 25.176 ;
     RECT  43.837 24.528 44.003 25.176 ;
     RECT  44.003 25.104 44.017 25.176 ;
     RECT  42.649 26.208 44.017 28.2 ;
     RECT  40.504 34.896 44.129 34.92 ;
     RECT  40.504 29.472 44.197 29.496 ;
     RECT  44.197 29.472 44.284 30.312 ;
     RECT  40.504 32.784 44.485 32.808 ;
     RECT  44.017 25.104 44.489 28.2 ;
     RECT  44.485 32.784 44.521 32.952 ;
     RECT  43.571 109.728 44.521 109.848 ;
     RECT  41.557 36.768 44.531 36.792 ;
     RECT  44.521 109.728 44.605 109.992 ;
     RECT  44.521 32.688 44.845 32.952 ;
     RECT  44.845 31.92 44.965 32.952 ;
     RECT  44.975 128.832 45.093 128.856 ;
     RECT  44.837 0.096 45.493 0.12 ;
     RECT  40.504 117.792 45.5 126.696 ;
     RECT  45.5 117.792 45.587 127.608 ;
     RECT  40.643 7.104 45.608 8.184 ;
     RECT  40.643 9.504 45.608 9.528 ;
     RECT  43.189 11.184 45.608 11.544 ;
     RECT  42.257 12.816 45.608 12.888 ;
     RECT  41.171 14.352 45.608 15.288 ;
     RECT  43.619 20.112 45.608 20.136 ;
     RECT  43.619 21.12 45.608 21.144 ;
     RECT  44.489 25.152 45.608 28.2 ;
     RECT  44.284 29.472 45.608 29.592 ;
     RECT  44.965 31.248 45.608 32.952 ;
     RECT  44.485 35.232 45.608 35.256 ;
     RECT  44.737 38.688 45.608 38.712 ;
     RECT  40.504 43.008 45.608 43.032 ;
     RECT  40.504 44.352 45.608 44.664 ;
     RECT  43.475 47.04 45.608 47.16 ;
     RECT  43.475 48.24 45.608 49.56 ;
     RECT  40.504 51.168 45.608 51.192 ;
     RECT  40.504 52.176 45.608 52.2 ;
     RECT  40.504 53.52 45.608 60.6 ;
     RECT  40.504 63.552 45.608 69.528 ;
     RECT  40.504 72.144 45.608 73.368 ;
     RECT  40.504 75.696 45.608 75.72 ;
     RECT  40.504 77.664 45.608 77.688 ;
     RECT  40.504 80.112 45.608 80.136 ;
     RECT  40.504 81.648 45.608 81.672 ;
     RECT  40.504 84.576 45.608 86.76 ;
     RECT  40.504 91.296 45.608 91.32 ;
     RECT  40.504 93.216 45.608 93.48 ;
     RECT  40.504 95.136 45.608 97.128 ;
     RECT  40.504 98.112 45.608 99.72 ;
     RECT  40.504 101.616 45.608 102.744 ;
     RECT  42.755 105.504 45.608 106.2 ;
     RECT  43.091 107.568 45.608 107.592 ;
     RECT  44.605 109.728 45.608 109.752 ;
     RECT  40.504 111.024 45.608 112.2 ;
     RECT  40.504 113.328 45.608 114.312 ;
     RECT  40.504 115.872 45.608 116.76 ;
     RECT  45.587 117.792 45.608 127.452 ;
     RECT  45.608 2.148 45.712 127.452 ;
     RECT  45.493 0.096 45.827 0.552 ;
     RECT  45.712 2.418 45.904 127.182 ;
     RECT  45.904 37.584 46.019 37.608 ;
     RECT  45.904 38.688 46.019 38.712 ;
     RECT  45.904 42.672 46.019 43.032 ;
     RECT  45.904 47.04 46.019 50.136 ;
     RECT  45.904 109.728 46.019 112.2 ;
     RECT  45.904 10.608 46.137 11.544 ;
     RECT  46.019 47.04 46.3 49.56 ;
     RECT  45.904 44.208 46.307 44.808 ;
     RECT  46.3 48.192 46.333 49.56 ;
     RECT  46.3 47.04 46.355 47.16 ;
     RECT  46.501 129.456 46.585 129.48 ;
     RECT  46.307 44.352 46.793 44.808 ;
     RECT  46.019 110.256 47.005 112.2 ;
     RECT  45.904 53.52 47.041 60.6 ;
     RECT  45.904 63.552 47.185 69.528 ;
     RECT  47.005 110.256 47.468 112.296 ;
     RECT  45.904 113.328 47.468 114.312 ;
     RECT  46.333 48.24 47.617 49.56 ;
     RECT  45.904 51.168 47.617 51.192 ;
     RECT  47.617 48.24 47.9 51.192 ;
     RECT  45.904 52.176 47.9 52.2 ;
     RECT  47.041 53.52 47.941 60.984 ;
     RECT  47.9 48.24 47.987 52.2 ;
     RECT  47.987 52.176 48.301 52.2 ;
     RECT  47.941 53.232 48.301 60.984 ;
     RECT  45.904 117.792 48.467 126.696 ;
     RECT  48.301 52.176 48.557 60.984 ;
     RECT  48.373 127.68 48.563 127.704 ;
     RECT  48.557 55.104 48.997 60.984 ;
     RECT  47.185 63.216 48.997 69.528 ;
     RECT  45.904 25.152 49.021 25.176 ;
     RECT  45.904 27.312 49.021 28.2 ;
     RECT  45.904 20.112 49.057 20.136 ;
     RECT  45.904 21.12 49.057 21.144 ;
     RECT  49.021 25.152 49.061 25.272 ;
     RECT  48.997 55.104 49.084 61.08 ;
     RECT  48.997 129.456 49.139 129.48 ;
     RECT  48.467 119.52 49.381 126.696 ;
     RECT  49.084 55.104 49.385 60.072 ;
     RECT  48.997 62.4 49.427 69.528 ;
     RECT  48.557 52.176 49.493 54.12 ;
     RECT  47.468 110.256 49.523 114.312 ;
     RECT  49.493 53.52 49.573 54.12 ;
     RECT  49.385 55.104 49.573 57.672 ;
     RECT  49.573 30.768 49.781 30.792 ;
     RECT  45.904 9.504 49.921 9.528 ;
     RECT  46.137 10.608 49.921 11.4 ;
     RECT  49.381 119.52 49.985 127.128 ;
     RECT  49.084 61.056 50.012 61.08 ;
     RECT  45.827 0.096 50.033 0.12 ;
     RECT  49.385 59.184 50.033 60.072 ;
     RECT  49.985 119.52 50.069 127.656 ;
     RECT  49.849 5.04 50.245 5.064 ;
     RECT  49.921 9.504 50.725 11.4 ;
     RECT  45.904 12.816 50.725 12.888 ;
     RECT  50.033 60.048 50.785 60.072 ;
     RECT  50.012 61.056 50.785 61.608 ;
     RECT  50.245 4.656 50.821 5.064 ;
     RECT  45.904 115.872 50.821 116.76 ;
     RECT  50.821 4.464 50.869 5.064 ;
     RECT  45.904 7.104 50.869 8.184 ;
     RECT  50.869 4.416 51.008 5.208 ;
     RECT  50.869 6.24 51.008 8.184 ;
     RECT  50.725 9.504 51.008 12.888 ;
     RECT  45.904 14.352 51.008 15.288 ;
     RECT  49.057 20.112 51.008 21.144 ;
     RECT  49.061 25.248 51.008 25.272 ;
     RECT  49.021 27.168 51.008 28.2 ;
     RECT  45.904 29.568 51.008 29.592 ;
     RECT  46.019 43.008 51.008 43.032 ;
     RECT  46.793 44.352 51.008 44.664 ;
     RECT  46.355 47.136 51.008 47.16 ;
     RECT  47.987 48.24 51.008 49.56 ;
     RECT  47.987 51.168 51.008 51.192 ;
     RECT  49.493 52.176 51.008 52.488 ;
     RECT  49.573 53.52 51.008 57.672 ;
     RECT  50.785 60.048 51.008 61.608 ;
     RECT  49.427 63.36 51.008 69.528 ;
     RECT  45.904 72.144 51.008 73.368 ;
     RECT  45.904 75.696 51.008 75.72 ;
     RECT  45.904 77.664 51.008 77.88 ;
     RECT  45.904 80.112 51.008 80.136 ;
     RECT  45.904 81.648 51.008 81.672 ;
     RECT  45.904 84.576 51.008 86.76 ;
     RECT  45.904 91.296 51.008 91.32 ;
     RECT  45.904 93.216 51.008 93.48 ;
     RECT  45.904 95.136 51.008 97.128 ;
     RECT  45.904 98.112 51.008 99.72 ;
     RECT  45.904 101.616 51.008 102.744 ;
     RECT  45.904 105.504 51.008 106.2 ;
     RECT  45.904 107.568 51.008 107.592 ;
     RECT  49.523 110.256 51.008 113.544 ;
     RECT  50.821 115.344 51.008 116.76 ;
     RECT  48.467 117.792 51.008 118.056 ;
     RECT  50.069 119.52 51.008 127.608 ;
     RECT  51.008 2.148 51.112 127.608 ;
     RECT  51.112 2.418 51.304 127.608 ;
     RECT  51.304 60.576 51.401 60.6 ;
     RECT  51.304 121.296 51.425 127.608 ;
     RECT  51.304 19.536 51.443 21.144 ;
     RECT  51.304 57.408 51.443 57.432 ;
     RECT  51.425 121.296 51.443 127.656 ;
     RECT  51.304 53.52 51.473 56.424 ;
     RECT  51.443 121.584 51.484 127.656 ;
     RECT  51.304 14.064 51.491 15.288 ;
     RECT  51.443 19.536 51.491 20.136 ;
     RECT  51.304 4.464 51.509 5.208 ;
     RECT  51.304 119.328 51.509 120.264 ;
     RECT  51.509 119.328 51.617 119.688 ;
     RECT  51.304 51.072 51.731 52.488 ;
     RECT  51.304 61.776 51.875 61.8 ;
     RECT  51.304 9.504 51.905 12.888 ;
     RECT  51.304 22.752 51.941 25.272 ;
     RECT  51.484 121.584 51.941 122.472 ;
     RECT  51.941 22.752 51.964 24.36 ;
     RECT  51.304 62.832 52.013 69.528 ;
     RECT  51.617 119.328 52.019 119.352 ;
     RECT  52.013 63.36 52.337 69.528 ;
     RECT  51.304 79.392 52.355 80.136 ;
     RECT  51.304 26.736 52.364 28.2 ;
     RECT  52.337 63.456 52.405 69.528 ;
     RECT  51.304 77.664 52.405 77.88 ;
     RECT  52.364 25.872 52.451 28.2 ;
     RECT  51.304 72.144 52.453 73.512 ;
     RECT  52.453 72 52.469 73.8 ;
     RECT  52.451 26.736 52.481 28.2 ;
     RECT  51.304 7.104 52.549 8.184 ;
     RECT  52.481 26.736 52.553 26.76 ;
     RECT  52.481 27.888 52.553 28.2 ;
     RECT  52.469 71.28 52.553 73.8 ;
     RECT  51.304 81.648 52.693 81.672 ;
     RECT  52.355 79.776 52.729 80.136 ;
     RECT  51.304 115.344 52.741 115.368 ;
     RECT  51.304 116.496 52.741 116.76 ;
     RECT  52.553 72 52.769 73.8 ;
     RECT  52.729 79.776 52.801 80.328 ;
     RECT  51.443 21.12 52.837 21.144 ;
     RECT  51.304 117.792 52.873 118.152 ;
     RECT  52.741 115.344 52.885 116.76 ;
     RECT  52.873 117.792 52.885 118.536 ;
     RECT  52.801 79.776 52.913 80.376 ;
     RECT  52.885 115.344 52.957 118.536 ;
     RECT  51.473 53.52 52.977 55.704 ;
     RECT  51.509 5.184 52.981 5.208 ;
     RECT  51.491 19.776 52.981 20.136 ;
     RECT  51.484 123.84 52.985 127.656 ;
     RECT  51.964 23.664 53.021 24.36 ;
     RECT  52.405 63.456 53.027 70.152 ;
     RECT  52.957 115.344 53.123 118.488 ;
     RECT  51.304 58.512 53.165 58.536 ;
     RECT  52.405 77.472 53.233 77.88 ;
     RECT  51.304 84.576 53.233 86.76 ;
     RECT  51.304 32.928 53.269 32.952 ;
     RECT  51.304 110.256 53.269 113.544 ;
     RECT  51.905 9.504 53.309 11.688 ;
     RECT  53.269 32.448 53.315 32.952 ;
     RECT  53.233 77.472 53.381 78.648 ;
     RECT  53.233 84.432 53.413 86.76 ;
     RECT  52.981 19.344 53.417 20.136 ;
     RECT  53.021 23.664 53.485 24.168 ;
     RECT  52.981 4.992 53.525 5.208 ;
     RECT  53.485 22.8 53.525 24.168 ;
     RECT  53.381 77.568 53.557 78.648 ;
     RECT  52.913 80.112 53.557 80.376 ;
     RECT  52.693 81.6 53.557 81.672 ;
     RECT  53.269 110.256 53.557 113.976 ;
     RECT  53.123 115.344 53.557 118.344 ;
     RECT  53.269 39.312 53.603 39.336 ;
     RECT  53.557 77.568 53.603 79.032 ;
     RECT  51.304 75.696 53.605 75.72 ;
     RECT  53.525 22.8 53.633 23.784 ;
     RECT  53.557 80.112 53.644 81.672 ;
     RECT  52.769 72.144 53.747 73.8 ;
     RECT  53.605 75.168 53.747 75.72 ;
     RECT  53.557 110.256 53.747 118.344 ;
     RECT  52.553 28.176 53.777 28.2 ;
     RECT  53.644 80.112 53.795 80.328 ;
     RECT  53.525 4.992 53.921 5.112 ;
     RECT  53.773 25.392 54.025 25.416 ;
     RECT  53.633 22.8 54.097 23.736 ;
     RECT  51.731 51.072 54.097 52.2 ;
     RECT  53.413 83.76 54.097 86.76 ;
     RECT  54.097 83.568 54.133 86.76 ;
     RECT  54.025 25.392 54.173 26.232 ;
     RECT  52.549 6.288 54.179 8.184 ;
     RECT  53.747 114.768 54.205 118.344 ;
     RECT  54.097 22.752 54.209 23.736 ;
     RECT  52.977 53.52 54.277 54.888 ;
     RECT  53.017 55.872 54.277 55.992 ;
     RECT  54.277 53.52 54.281 55.992 ;
     RECT  53.921 5.088 54.317 5.112 ;
     RECT  54.097 50.64 54.317 52.2 ;
     RECT  53.603 77.664 54.317 79.032 ;
     RECT  54.169 120.192 54.349 120.216 ;
     RECT  52.985 123.84 54.349 127.128 ;
     RECT  52.837 21.12 54.353 21.672 ;
     RECT  54.173 26.208 54.353 26.232 ;
     RECT  54.349 123.84 54.467 127.656 ;
     RECT  53.027 63.456 54.517 70.008 ;
     RECT  51.304 47.136 54.529 47.16 ;
     RECT  54.317 50.688 54.529 52.2 ;
     RECT  54.281 53.52 54.529 55.896 ;
     RECT  54.349 119.952 54.601 120.216 ;
     RECT  54.133 83.568 54.605 86.904 ;
     RECT  54.209 23.52 54.613 23.736 ;
     RECT  54.313 24.864 54.613 24.936 ;
     RECT  53.309 9.504 54.629 10.632 ;
     RECT  53.309 11.664 54.629 11.688 ;
     RECT  54.317 78.864 54.637 79.032 ;
     RECT  53.795 80.112 54.637 80.136 ;
     RECT  54.517 62.736 54.659 70.008 ;
     RECT  54.605 84.336 54.659 86.904 ;
     RECT  53.417 19.776 54.673 20.136 ;
     RECT  53.644 81.504 54.673 81.672 ;
     RECT  54.205 114.768 54.673 118.536 ;
     RECT  54.601 119.808 54.673 120.216 ;
     RECT  54.179 6.816 54.709 8.184 ;
     RECT  54.629 9.504 54.709 11.688 ;
     RECT  53.315 32.448 54.709 32.472 ;
     RECT  51.304 44.352 54.709 44.664 ;
     RECT  54.673 114.768 54.709 120.216 ;
     RECT  51.941 121.584 54.709 122.376 ;
     RECT  54.613 23.52 54.713 24.936 ;
     RECT  54.349 88.896 54.713 88.92 ;
     RECT  54.709 6.816 54.749 11.688 ;
     RECT  51.491 14.352 54.749 15.288 ;
     RECT  54.709 32.304 54.749 32.472 ;
     RECT  51.304 93.216 54.749 93.48 ;
     RECT  54.749 7.392 54.755 11.688 ;
     RECT  51.304 101.616 54.755 102.744 ;
     RECT  54.713 23.664 54.821 24.936 ;
     RECT  54.659 63.264 54.889 70.008 ;
     RECT  54.673 81.504 54.925 81.912 ;
     RECT  54.755 9.12 54.929 11.688 ;
     RECT  54.637 78.864 54.929 80.136 ;
     RECT  51.304 105.504 54.949 106.2 ;
     RECT  51.304 107.568 54.949 107.592 ;
     RECT  54.709 114.768 54.995 122.52 ;
     RECT  54.929 9.648 55.009 11.688 ;
     RECT  54.995 114.768 55.009 116.52 ;
     RECT  54.673 18.96 55.069 20.136 ;
     RECT  54.353 21.12 55.069 21.144 ;
     RECT  54.755 7.392 55.18 7.944 ;
     RECT  54.889 63.264 55.181 70.104 ;
     RECT  54.659 84.336 55.181 85.656 ;
     RECT  55.069 18.96 55.189 21.144 ;
     RECT  55.189 18.768 55.235 21.144 ;
     RECT  54.929 79.968 55.244 80.136 ;
     RECT  54.673 1.632 55.249 1.656 ;
     RECT  54.529 50.688 55.253 55.896 ;
     RECT  51.304 48.24 55.285 49.56 ;
     RECT  54.925 81.504 55.285 82.632 ;
     RECT  55.009 9.648 55.289 10.248 ;
     RECT  55.009 11.328 55.289 11.688 ;
     RECT  55.244 79.968 55.292 80.28 ;
     RECT  53.747 72.144 55.325 73.368 ;
     RECT  54.929 78.864 55.331 78.936 ;
     RECT  54.659 86.736 55.331 86.904 ;
     RECT  55.285 88.368 55.357 88.392 ;
     RECT  54.995 117.504 55.361 122.52 ;
     RECT  55.235 20.112 55.397 21.144 ;
     RECT  53.557 41.904 55.429 41.928 ;
     RECT  51.304 43.008 55.429 43.032 ;
     RECT  55.235 18.768 55.433 18.792 ;
     RECT  53.747 110.256 55.532 113.544 ;
     RECT  55.009 114.768 55.537 116.472 ;
     RECT  55.285 48.24 55.609 49.608 ;
     RECT  55.253 50.688 55.609 54.84 ;
     RECT  55.237 38.736 55.669 38.76 ;
     RECT  53.747 75.696 55.676 75.72 ;
     RECT  55.289 11.664 55.717 11.688 ;
     RECT  51.905 12.816 55.717 12.888 ;
     RECT  55.676 75.696 55.717 75.912 ;
     RECT  54.749 14.448 55.753 15.048 ;
     RECT  55.253 55.872 55.789 55.896 ;
     RECT  55.717 22.224 55.813 22.248 ;
     RECT  54.821 23.712 55.813 24.936 ;
     RECT  55.532 109.296 55.853 113.544 ;
     RECT  54.529 47.04 55.861 47.16 ;
     RECT  55.789 55.872 55.861 55.944 ;
     RECT  55.717 75.12 55.861 75.912 ;
     RECT  54.317 77.664 55.861 77.688 ;
     RECT  55.621 78.672 55.861 78.696 ;
     RECT  55.292 79.968 55.861 80.376 ;
     RECT  55.285 81.36 55.861 82.632 ;
     RECT  54.467 123.84 55.861 127.128 ;
     RECT  55.645 57.552 55.897 57.576 ;
     RECT  55.861 46.944 55.933 47.256 ;
     RECT  54.949 105.504 55.964 107.592 ;
     RECT  55.813 22.224 56.005 24.936 ;
     RECT  51.304 29.568 56.005 29.592 ;
     RECT  55.813 104.256 56.041 104.28 ;
     RECT  55.853 108.864 56.041 113.544 ;
     RECT  55.537 114.576 56.041 116.472 ;
     RECT  55.429 41.904 56.06 43.032 ;
     RECT  55.861 17.472 56.077 17.496 ;
     RECT  56.06 41.904 56.101 43.32 ;
     RECT  54.709 44.352 56.101 44.712 ;
     RECT  55.381 35.712 56.149 35.736 ;
     RECT  55.861 58.704 56.197 58.728 ;
     RECT  55.289 10.224 56.204 10.248 ;
     RECT  51.304 91.296 56.257 91.32 ;
     RECT  55.861 55.872 56.293 56.328 ;
     RECT  55.897 57.312 56.293 57.576 ;
     RECT  55.861 74.688 56.365 75.912 ;
     RECT  55.249 1.392 56.408 1.656 ;
     RECT  55.18 7.776 56.408 7.944 ;
     RECT  56.204 10.224 56.408 10.536 ;
     RECT  55.717 11.664 56.408 12.888 ;
     RECT  55.753 14.448 56.408 15.288 ;
     RECT  56.077 17.472 56.408 18.456 ;
     RECT  55.397 20.112 56.408 20.568 ;
     RECT  56.005 22.224 56.408 25.032 ;
     RECT  56.005 29.568 56.408 30.168 ;
     RECT  54.749 32.304 56.408 32.328 ;
     RECT  56.149 35.328 56.408 35.736 ;
     RECT  55.477 36.816 56.408 36.84 ;
     RECT  55.669 38.496 56.408 38.76 ;
     RECT  56.101 41.904 56.408 44.712 ;
     RECT  55.933 46.896 56.408 47.256 ;
     RECT  55.609 48.24 56.408 54.84 ;
     RECT  56.293 55.872 56.408 57.576 ;
     RECT  56.197 58.704 56.408 59.4 ;
     RECT  55.181 63.264 56.408 68.952 ;
     RECT  55.181 69.984 56.408 70.104 ;
     RECT  55.325 72.432 56.408 73.368 ;
     RECT  56.365 74.688 56.408 75.96 ;
     RECT  55.861 77.664 56.408 78.696 ;
     RECT  55.861 79.968 56.408 82.632 ;
     RECT  55.181 84.336 56.408 85.512 ;
     RECT  55.331 86.736 56.408 86.76 ;
     RECT  55.357 88.128 56.408 88.392 ;
     RECT  56.257 91.296 56.408 91.416 ;
     RECT  54.749 93.216 56.408 93.336 ;
     RECT  51.304 95.136 56.408 97.128 ;
     RECT  51.304 98.112 56.408 99.72 ;
     RECT  54.755 101.616 56.408 102.504 ;
     RECT  56.041 104.256 56.408 104.424 ;
     RECT  55.964 105.408 56.408 107.592 ;
     RECT  56.041 108.864 56.408 116.472 ;
     RECT  55.361 117.504 56.408 119.448 ;
     RECT  55.361 120.576 56.408 122.52 ;
     RECT  55.861 123.84 56.408 127.656 ;
     RECT  56.365 128.784 56.483 128.808 ;
     RECT  56.408 1.392 56.704 127.656 ;
     RECT  56.704 121.968 56.725 127.656 ;
     RECT  56.704 98.112 56.801 106.632 ;
     RECT  56.704 71.856 56.819 75.96 ;
     RECT  56.704 77.52 56.873 82.584 ;
     RECT  56.704 17.472 56.909 18.84 ;
     RECT  56.704 119.952 56.909 120.6 ;
     RECT  56.704 11.664 56.915 15.384 ;
     RECT  56.819 71.952 56.945 75.96 ;
     RECT  56.909 17.472 57.011 17.688 ;
     RECT  56.704 52.224 57.017 57.384 ;
     RECT  56.704 26.736 57.052 26.76 ;
     RECT  56.915 12.48 57.053 15.384 ;
     RECT  56.704 28.512 57.059 30.84 ;
     RECT  56.704 24.336 57.097 25.704 ;
     RECT  56.704 88.128 57.107 89.304 ;
     RECT  56.801 99.168 57.107 106.632 ;
     RECT  56.704 109.248 57.107 118.68 ;
     RECT  57.107 114.576 57.125 118.68 ;
     RECT  56.873 81.36 57.148 82.584 ;
     RECT  56.945 72.384 57.155 75.96 ;
     RECT  57.148 81.36 57.155 82.488 ;
     RECT  56.704 43.872 57.203 49.608 ;
     RECT  57.017 52.224 57.203 55.896 ;
     RECT  56.704 50.736 57.205 51.24 ;
     RECT  57.011 17.568 57.233 17.688 ;
     RECT  57.203 53.376 57.233 55.896 ;
     RECT  57.233 53.376 57.299 55.56 ;
     RECT  57.107 88.32 57.299 89.304 ;
     RECT  57.017 57.024 57.341 57.384 ;
     RECT  56.704 91.392 57.341 94.104 ;
     RECT  57.341 57.024 57.377 57.192 ;
     RECT  56.909 119.952 57.413 119.976 ;
     RECT  57.299 53.376 57.443 53.4 ;
     RECT  56.725 121.968 57.443 128.28 ;
     RECT  56.704 95.136 57.449 97.128 ;
     RECT  57.125 114.576 57.485 118.392 ;
     RECT  57.485 114.576 57.491 118.056 ;
     RECT  57.377 57.024 57.521 57.048 ;
     RECT  57.341 91.584 57.539 94.104 ;
     RECT  57.299 54.672 57.593 55.56 ;
     RECT  57.107 109.248 57.593 113.592 ;
     RECT  57.203 43.872 57.601 49.56 ;
     RECT  57.299 88.368 57.629 89.304 ;
     RECT  57.491 115.344 57.629 118.056 ;
     RECT  57.053 12.48 57.635 12.552 ;
     RECT  56.704 39.984 57.635 40.44 ;
     RECT  56.704 84.336 57.665 86.76 ;
     RECT  57.629 115.344 57.665 115.944 ;
     RECT  57.539 93.312 57.683 94.104 ;
     RECT  57.593 109.248 57.692 113.496 ;
     RECT  57.593 54.72 57.701 55.56 ;
     RECT  56.704 42.528 57.733 42.744 ;
     RECT  57.053 13.632 57.737 15.384 ;
     RECT  57.601 43.872 57.737 45.72 ;
     RECT  56.704 59.184 57.737 59.64 ;
     RECT  57.107 101.712 57.737 106.632 ;
     RECT  57.685 40.944 57.773 40.968 ;
     RECT  57.601 46.704 57.779 49.56 ;
     RECT  57.107 99.168 57.779 100.728 ;
     RECT  57.449 95.136 57.805 95.688 ;
     RECT  57.733 42.048 57.827 42.744 ;
     RECT  57.737 103.872 57.827 106.632 ;
     RECT  57.779 46.704 57.845 49.464 ;
     RECT  56.873 77.52 57.877 80.136 ;
     RECT  57.155 81.36 57.877 82.2 ;
     RECT  57.692 109.104 57.881 113.496 ;
     RECT  57.155 72.384 57.917 74.664 ;
     RECT  56.704 69.936 57.923 70.824 ;
     RECT  57.665 84.336 57.98 85.656 ;
     RECT  57.877 77.52 58.017 82.2 ;
     RECT  56.704 20.112 58.021 20.136 ;
     RECT  56.704 38.112 58.021 38.76 ;
     RECT  57.923 69.936 58.067 70.728 ;
     RECT  57.98 83.712 58.067 85.656 ;
     RECT  57.877 34.176 58.097 34.2 ;
     RECT  56.704 63.264 58.115 68.136 ;
     RECT  58.115 63.264 58.117 63.672 ;
     RECT  58.017 80.256 58.117 82.2 ;
     RECT  56.801 98.112 58.117 98.184 ;
     RECT  57.779 99.168 58.117 99.96 ;
     RECT  58.117 98.112 58.163 99.96 ;
     RECT  58.021 19.632 58.165 20.136 ;
     RECT  57.737 59.184 58.165 59.208 ;
     RECT  57.737 43.872 58.169 45.624 ;
     RECT  57.449 96.72 58.169 97.128 ;
     RECT  57.737 101.712 58.201 102.6 ;
     RECT  57.443 121.968 58.205 127.944 ;
     RECT  57.203 52.224 58.211 52.248 ;
     RECT  58.021 38.016 58.213 38.76 ;
     RECT  57.917 73.344 58.213 74.664 ;
     RECT  57.155 75.696 58.213 75.96 ;
     RECT  58.165 19.632 58.237 20.424 ;
     RECT  57.877 26.88 58.237 26.904 ;
     RECT  58.165 59.136 58.273 59.208 ;
     RECT  58.067 84 58.277 85.656 ;
     RECT  58.017 77.52 58.285 79.272 ;
     RECT  58.201 101.472 58.285 102.6 ;
     RECT  58.117 80.256 58.307 82.728 ;
     RECT  58.285 101.712 58.307 102.6 ;
     RECT  58.205 122.496 58.307 127.944 ;
     RECT  58.169 96.864 58.313 97.128 ;
     RECT  58.163 98.112 58.313 98.376 ;
     RECT  57.845 46.704 58.349 47.304 ;
     RECT  58.307 80.256 58.355 82.632 ;
     RECT  58.129 34.8 58.357 34.824 ;
     RECT  56.704 36.24 58.357 37.032 ;
     RECT  58.313 97.104 58.357 97.128 ;
     RECT  58.313 98.112 58.357 98.184 ;
     RECT  57.059 28.512 58.364 28.536 ;
     RECT  57.059 29.568 58.364 30.84 ;
     RECT  56.704 32.304 58.381 32.808 ;
     RECT  57.233 17.664 58.417 17.688 ;
     RECT  58.213 38.016 58.421 39.336 ;
     RECT  58.364 28.512 58.453 30.84 ;
     RECT  58.357 34.8 58.493 37.032 ;
     RECT  58.421 38.4 58.493 39.336 ;
     RECT  58.493 34.8 58.499 36.984 ;
     RECT  57.827 42.192 58.525 42.744 ;
     RECT  58.169 43.872 58.525 43.896 ;
     RECT  58.285 77.52 58.525 79.224 ;
     RECT  58.417 17.664 58.529 18.216 ;
     RECT  58.381 32.304 58.529 33.048 ;
     RECT  58.273 59.04 58.529 59.208 ;
     RECT  58.355 80.256 58.529 82.2 ;
     RECT  58.453 28.464 58.547 31.08 ;
     RECT  58.237 26.88 58.549 27.336 ;
     RECT  57.827 105.648 58.549 106.632 ;
     RECT  58.508 107.76 58.549 107.784 ;
     RECT  58.549 26.688 58.561 27.336 ;
     RECT  57.737 13.92 58.565 15.384 ;
     RECT  58.549 105.648 58.595 107.784 ;
     RECT  58.493 38.4 58.601 38.808 ;
     RECT  57.629 88.944 58.609 88.968 ;
     RECT  58.117 62.736 58.633 63.672 ;
     RECT  58.277 84.336 58.633 85.656 ;
     RECT  57.665 86.736 58.633 86.76 ;
     RECT  58.561 26.688 58.645 27.96 ;
     RECT  58.489 90.624 58.669 90.648 ;
     RECT  57.539 91.776 58.669 92.088 ;
     RECT  58.565 13.92 58.673 14.28 ;
     RECT  58.525 76.944 58.673 79.224 ;
     RECT  58.673 76.944 58.691 77.064 ;
     RECT  58.237 19.632 58.705 20.472 ;
     RECT  56.704 21.456 58.705 23.352 ;
     RECT  57.097 24.336 58.705 25.56 ;
     RECT  58.669 90.624 58.705 92.088 ;
     RECT  58.633 84.336 58.709 86.76 ;
     RECT  58.633 62.688 58.739 63.672 ;
     RECT  58.691 76.944 58.739 76.968 ;
     RECT  58.705 19.632 58.741 25.56 ;
     RECT  57.881 109.104 58.741 112.488 ;
     RECT  58.673 78.432 58.745 79.224 ;
     RECT  58.645 26.688 58.781 27.336 ;
     RECT  57.827 103.872 58.781 104.088 ;
     RECT  58.705 90 58.789 92.232 ;
     RECT  58.349 46.704 58.816 47.208 ;
     RECT  57.205 51.216 58.837 51.24 ;
     RECT  58.805 52.32 58.837 52.68 ;
     RECT  58.169 44.88 58.844 45.624 ;
     RECT  58.816 46.656 58.844 47.208 ;
     RECT  58.741 19.632 58.853 25.656 ;
     RECT  58.789 90.624 58.853 92.232 ;
     RECT  58.853 19.632 58.885 21.672 ;
     RECT  58.499 34.8 58.924 35.928 ;
     RECT  58.837 52.32 58.924 52.776 ;
     RECT  58.529 59.04 58.925 59.16 ;
     RECT  58.709 84.384 58.925 86.76 ;
     RECT  57.629 117.216 58.925 118.056 ;
     RECT  58.844 44.88 58.931 47.208 ;
     RECT  57.845 48.432 58.933 49.464 ;
     RECT  58.837 50.832 58.933 51.24 ;
     RECT  58.924 52.752 58.933 52.776 ;
     RECT  58.885 19.344 58.969 21.672 ;
     RECT  58.933 52.752 58.979 52.872 ;
     RECT  57.683 93.312 58.981 93.336 ;
     RECT  57.805 94.416 58.981 95.688 ;
     RECT  56.704 61.008 59.029 61.032 ;
     RECT  58.067 69.936 59.029 69.96 ;
     RECT  58.213 73.344 59.029 75.96 ;
     RECT  58.529 18.192 59.033 18.216 ;
     RECT  58.931 46.656 59.033 47.208 ;
     RECT  58.499 36.96 59.069 36.984 ;
     RECT  58.525 42.192 59.069 43.896 ;
     RECT  58.925 59.136 59.069 59.16 ;
     RECT  58.853 22.752 59.075 25.656 ;
     RECT  58.933 50.736 59.075 51.24 ;
     RECT  58.979 52.848 59.075 52.872 ;
     RECT  58.307 122.544 59.077 127.944 ;
     RECT  58.781 26.688 59.141 27.24 ;
     RECT  58.163 99.408 59.141 99.96 ;
     RECT  59.029 73.344 59.171 76.488 ;
     RECT  58.921 71.712 59.173 71.736 ;
     RECT  58.924 34.8 59.177 34.824 ;
     RECT  59.029 60.24 59.177 61.032 ;
     RECT  58.529 80.256 59.177 81.624 ;
     RECT  59.029 69.936 59.219 70.104 ;
     RECT  58.853 90.624 59.219 92.04 ;
     RECT  57.881 113.472 59.221 113.496 ;
     RECT  59.171 73.344 59.237 74.136 ;
     RECT  59.173 71.712 59.245 71.832 ;
     RECT  57.635 12.528 59.249 12.552 ;
     RECT  58.933 48.288 59.249 49.464 ;
     RECT  59.075 51.216 59.267 51.24 ;
     RECT  59.245 71.712 59.269 71.928 ;
     RECT  58.115 64.656 59.281 68.136 ;
     RECT  58.745 78.624 59.285 79.224 ;
     RECT  59.177 80.256 59.285 80.376 ;
     RECT  59.177 81.408 59.285 81.624 ;
     RECT  58.565 15.36 59.321 15.384 ;
     RECT  58.969 19.632 59.321 21.672 ;
     RECT  59.075 24.768 59.321 25.656 ;
     RECT  59.237 72.912 59.321 74.136 ;
     RECT  59.171 76.368 59.321 76.392 ;
     RECT  59.285 79.152 59.321 79.224 ;
     RECT  59.285 80.352 59.321 80.376 ;
     RECT  59.069 42.576 59.324 43.896 ;
     RECT  58.931 44.88 59.324 45.576 ;
     RECT  58.547 29.28 59.353 31.08 ;
     RECT  58.529 32.304 59.353 32.472 ;
     RECT  59.321 19.632 59.393 21.48 ;
     RECT  59.285 81.6 59.393 81.624 ;
     RECT  59.393 19.632 59.429 20.136 ;
     RECT  59.353 29.28 59.429 32.472 ;
     RECT  59.269 70.848 59.459 71.928 ;
     RECT  59.321 73.776 59.459 74.136 ;
     RECT  59.459 73.776 59.465 73.8 ;
     RECT  58.925 84.384 59.465 86.04 ;
     RECT  58.739 62.736 59.507 63.672 ;
     RECT  58.741 108.432 59.507 112.488 ;
     RECT  58.595 105.648 59.536 107.208 ;
     RECT  59.033 46.704 59.557 47.208 ;
     RECT  59.249 48.288 59.557 49.368 ;
     RECT  59.557 46.704 59.573 49.368 ;
     RECT  59.465 86.016 59.603 86.04 ;
     RECT  59.281 87.792 59.603 87.816 ;
     RECT  59.065 119.664 59.605 119.688 ;
     RECT  58.525 120.768 59.605 120.792 ;
     RECT  59.459 71.328 59.681 71.928 ;
     RECT  59.465 84.384 59.681 84.744 ;
     RECT  59.536 105.6 59.708 107.208 ;
     RECT  59.507 108.432 59.708 111.336 ;
     RECT  57.701 55.536 59.713 55.56 ;
     RECT  59.173 57.024 59.713 57.048 ;
     RECT  59.219 91.152 59.717 92.04 ;
     RECT  59.708 105.6 59.717 111.336 ;
     RECT  59.281 64.656 59.747 68.424 ;
     RECT  59.075 22.752 59.753 23.736 ;
     RECT  59.507 112.368 59.753 112.392 ;
     RECT  59.393 21.456 59.789 21.48 ;
     RECT  59.717 105.6 59.795 110.568 ;
     RECT  59.681 84.72 59.825 84.744 ;
     RECT  59.681 71.328 59.843 71.352 ;
     RECT  59.569 40.608 59.845 40.632 ;
     RECT  59.713 55.536 59.845 57.048 ;
     RECT  59.177 60.24 59.845 60.888 ;
     RECT  58.781 104.064 59.845 104.088 ;
     RECT  58.981 93.312 59.857 95.688 ;
     RECT  58.357 97.104 59.857 98.184 ;
     RECT  59.795 105.6 59.857 107.4 ;
     RECT  58.601 38.736 59.893 38.808 ;
     RECT  59.845 103.968 59.932 104.088 ;
     RECT  59.845 40.608 59.933 41.16 ;
     RECT  59.507 62.784 59.941 63.672 ;
     RECT  59.747 64.656 59.941 65.544 ;
     RECT  58.673 13.92 59.965 13.944 ;
     RECT  59.845 59.808 59.987 60.888 ;
     RECT  59.941 62.784 59.987 65.544 ;
     RECT  59.429 30.192 59.989 32.472 ;
     RECT  59.857 93.264 59.989 95.688 ;
     RECT  59.845 55.536 59.996 57.096 ;
     RECT  58.307 101.712 60.001 102.408 ;
     RECT  59.077 122.544 60.001 128.712 ;
     RECT  59.996 55.536 60.005 57.816 ;
     RECT  59.932 104.064 60.005 104.088 ;
     RECT  59.795 108.432 60.005 110.568 ;
     RECT  59.324 42.576 60.037 45.576 ;
     RECT  59.573 46.704 60.037 49.032 ;
     RECT  59.753 23.328 60.041 23.736 ;
     RECT  59.941 37.152 60.041 37.176 ;
     RECT  59.893 38.592 60.073 38.808 ;
     RECT  59.857 105.504 60.073 107.4 ;
     RECT  59.987 62.784 60.077 62.808 ;
     RECT  60.037 42.576 60.085 49.032 ;
     RECT  59.989 30.192 60.092 33.048 ;
     RECT  59.989 93.264 60.092 95.784 ;
     RECT  59.857 97.104 60.092 98.232 ;
     RECT  60.085 42.336 60.113 49.032 ;
     RECT  60.001 101.568 60.113 102.408 ;
     RECT  59.141 27.216 60.145 27.24 ;
     RECT  59.429 19.632 60.149 19.656 ;
     RECT  60.092 30.192 60.179 33.624 ;
     RECT  60.092 93.264 60.179 98.232 ;
     RECT  58.924 35.904 60.181 35.928 ;
     RECT  59.747 66.528 60.181 68.424 ;
     RECT  60.179 93.264 60.181 95.784 ;
     RECT  60.113 42.336 60.221 48.936 ;
     RECT  60.005 56.88 60.221 57.816 ;
     RECT  60.221 42.336 60.227 48.792 ;
     RECT  60.179 97.248 60.229 98.232 ;
     RECT  59.141 99.408 60.229 99.624 ;
     RECT  60.145 27.216 60.289 27.96 ;
     RECT  59.785 29.088 60.289 29.112 ;
     RECT  59.605 119.664 60.289 120.792 ;
     RECT  59.461 26.112 60.325 26.232 ;
     RECT  60.289 27.216 60.325 29.112 ;
     RECT  60.005 108.432 60.329 109.272 ;
     RECT  60.227 42.336 60.332 43.32 ;
     RECT  59.987 59.808 60.332 60.792 ;
     RECT  60.179 30.192 60.365 33.048 ;
     RECT  59.933 40.608 60.365 40.632 ;
     RECT  60.221 56.928 60.373 57.816 ;
     RECT  60.181 34.992 60.397 35.928 ;
     RECT  60.109 37.056 60.397 37.08 ;
     RECT  60.229 97.248 60.397 99.624 ;
     RECT  60.181 66.528 60.412 68.664 ;
     RECT  60.073 105.36 60.412 107.4 ;
     RECT  60.332 42.096 60.419 43.32 ;
     RECT  60.227 46.656 60.419 48.792 ;
     RECT  60.332 59.424 60.419 60.792 ;
     RECT  60.412 105.6 60.429 107.4 ;
     RECT  60.397 97.248 60.467 99.96 ;
     RECT  60.397 88.368 60.469 88.92 ;
     RECT  60.041 23.712 60.473 23.736 ;
     RECT  60.419 60.096 60.473 60.792 ;
     RECT  60.181 92.304 60.473 95.784 ;
     RECT  60.429 107.184 60.473 107.4 ;
     RECT  58.925 117.408 60.473 118.056 ;
     RECT  60.227 44.4 60.48 45.576 ;
     RECT  60.325 26.112 60.505 29.112 ;
     RECT  60.365 30.192 60.505 32.472 ;
     RECT  60.505 26.112 60.509 32.472 ;
     RECT  60.397 37.008 60.509 37.08 ;
     RECT  60.373 57.024 60.509 58.152 ;
     RECT  60.469 88.368 60.515 89.688 ;
     RECT  60.397 34.704 60.545 35.928 ;
     RECT  60.473 107.376 60.545 107.4 ;
     RECT  60.515 89.664 60.556 89.688 ;
     RECT  60.419 42.576 60.563 43.32 ;
     RECT  60.429 105.6 60.563 106.152 ;
     RECT  60.473 117.936 60.563 118.056 ;
     RECT  59.321 24.768 60.572 24.792 ;
     RECT  60.509 26.112 60.572 31.8 ;
     RECT  60.48 44.4 60.581 44.664 ;
     RECT  60.289 119.376 60.604 121.08 ;
     RECT  60.515 88.368 60.613 88.584 ;
     RECT  59.717 91.152 60.613 91.32 ;
     RECT  60.581 44.64 60.653 44.664 ;
     RECT  60.473 92.304 60.653 95.736 ;
     RECT  60.563 105.648 60.653 106.152 ;
     RECT  60.572 24.768 60.659 31.8 ;
     RECT  60.563 42.72 60.689 43.32 ;
     RECT  60.659 26.112 60.707 31.8 ;
     RECT  60.469 86.64 60.709 86.664 ;
     RECT  60.613 87.792 60.709 88.584 ;
     RECT  60.709 86.64 60.755 88.584 ;
     RECT  59.987 63.84 60.757 65.544 ;
     RECT  60.412 66.528 60.757 68.424 ;
     RECT  60.473 60.096 60.761 60.12 ;
     RECT  60.659 24.768 60.796 25.08 ;
     RECT  60.707 29.088 60.796 31.8 ;
     RECT  60.755 86.64 60.796 87.432 ;
     RECT  60.653 93.072 60.797 95.736 ;
     RECT  60.604 120 60.833 121.08 ;
     RECT  60.001 122.544 60.937 128.856 ;
     RECT  60.937 122.4 60.947 128.856 ;
     RECT  60.433 9.888 61.045 9.912 ;
     RECT  61.153 17.424 61.405 17.448 ;
     RECT  61.297 77.328 61.405 77.352 ;
     RECT  60.005 55.536 61.549 55.56 ;
     RECT  57.665 115.344 61.549 115.56 ;
     RECT  60.757 63.84 61.657 68.424 ;
     RECT  56.704 1.392 61.808 1.656 ;
     RECT  58.381 6.672 61.808 6.696 ;
     RECT  61.045 9.024 61.808 9.912 ;
     RECT  59.965 13.632 61.808 13.944 ;
     RECT  61.405 16.896 61.808 17.448 ;
     RECT  61.369 19.536 61.808 19.56 ;
     RECT  60.796 24.768 61.808 24.792 ;
     RECT  60.707 26.112 61.808 27.624 ;
     RECT  60.796 29.088 61.808 29.112 ;
     RECT  60.796 30.192 61.808 31.8 ;
     RECT  60.545 34.704 61.808 35.016 ;
     RECT  60.509 37.008 61.808 37.032 ;
     RECT  60.073 38.592 61.808 39.288 ;
     RECT  60.689 42.72 61.808 43.032 ;
     RECT  60.419 47.088 61.808 47.112 ;
     RECT  60.419 48.768 61.808 48.792 ;
     RECT  61.549 55.152 61.808 55.56 ;
     RECT  60.509 57.024 61.808 57.048 ;
     RECT  60.901 58.896 61.808 59.064 ;
     RECT  61.657 63.84 61.808 68.952 ;
     RECT  61.405 77.328 61.808 77.688 ;
     RECT  59.321 79.152 61.808 79.176 ;
     RECT  60.796 86.64 61.808 86.856 ;
     RECT  60.755 88.464 61.808 88.584 ;
     RECT  60.613 90.624 61.808 91.32 ;
     RECT  60.797 93.072 61.808 95.064 ;
     RECT  60.467 98.064 61.808 99.96 ;
     RECT  60.113 101.568 61.808 102.12 ;
     RECT  60.653 106.128 61.808 106.152 ;
     RECT  60.329 109.248 61.808 109.272 ;
     RECT  60.005 110.544 61.808 110.568 ;
     RECT  59.221 113.472 61.808 113.544 ;
     RECT  61.549 114.672 61.808 115.56 ;
     RECT  60.563 118.032 61.808 118.056 ;
     RECT  60.833 120.096 61.808 121.08 ;
     RECT  60.947 122.4 61.808 128.712 ;
     RECT  61.808 1.392 61.945 128.712 ;
     RECT  61.945 1.152 62.104 128.712 ;
     RECT  62.104 19.536 62.129 19.56 ;
     RECT  62.104 113.52 62.165 115.176 ;
     RECT  62.104 121.92 62.201 124.2 ;
     RECT  62.104 31.104 62.243 31.128 ;
     RECT  62.104 93.552 62.243 94.68 ;
     RECT  62.104 46.896 62.291 49.176 ;
     RECT  62.104 1.152 62.665 1.656 ;
     RECT  62.104 126.432 62.737 128.712 ;
     RECT  62.104 6.672 63.097 10.2 ;
     RECT  62.104 4.416 63.169 4.92 ;
     RECT  62.104 82.416 63.169 84.936 ;
     RECT  62.104 86.16 63.169 88.68 ;
     RECT  63.169 4.176 63.205 4.92 ;
     RECT  62.104 22.896 63.205 23.448 ;
     RECT  62.104 105.936 63.205 106.968 ;
     RECT  62.104 108.432 63.205 109.704 ;
     RECT  62.665 0.672 63.241 1.656 ;
     RECT  63.205 2.64 63.241 4.92 ;
     RECT  62.104 15.168 63.241 17.928 ;
     RECT  63.205 20.4 63.241 20.424 ;
     RECT  62.104 21.888 63.241 21.912 ;
     RECT  63.205 22.896 63.241 24.408 ;
     RECT  62.104 26.64 63.241 26.664 ;
     RECT  62.104 28.416 63.241 29.16 ;
     RECT  62.104 34.416 63.241 34.44 ;
     RECT  62.104 37.68 63.241 37.704 ;
     RECT  62.104 38.928 63.241 38.952 ;
     RECT  62.104 41.664 63.241 42.456 ;
     RECT  63.205 45.648 63.241 45.672 ;
     RECT  62.291 46.896 63.241 46.92 ;
     RECT  62.104 53.664 63.241 53.688 ;
     RECT  62.104 54.672 63.241 55.176 ;
     RECT  63.205 57.648 63.241 57.672 ;
     RECT  62.104 59.184 63.241 59.688 ;
     RECT  62.104 62.16 63.241 62.952 ;
     RECT  62.104 65.664 63.241 65.688 ;
     RECT  62.104 66.912 63.241 67.176 ;
     RECT  62.104 68.4 63.241 69.96 ;
     RECT  62.104 79.68 63.241 79.704 ;
     RECT  62.104 81.168 63.241 81.432 ;
     RECT  62.243 93.648 63.241 94.68 ;
     RECT  62.104 95.904 63.241 96.456 ;
     RECT  62.104 99.936 63.241 102.936 ;
     RECT  62.104 104.4 63.241 104.424 ;
     RECT  63.205 105.936 63.241 109.704 ;
     RECT  62.104 116.4 63.241 117.192 ;
     RECT  63.241 14.928 63.277 17.928 ;
     RECT  63.241 35.424 63.277 35.448 ;
     RECT  63.241 36.432 63.277 39.912 ;
     RECT  63.241 56.4 63.277 56.424 ;
     RECT  63.241 57.408 63.277 57.672 ;
     RECT  63.241 58.656 63.277 60.168 ;
     RECT  63.241 61.68 63.277 64.68 ;
     RECT  63.241 65.664 63.277 65.928 ;
     RECT  63.241 66.912 63.277 69.96 ;
     RECT  62.104 71.184 63.277 77.688 ;
     RECT  63.241 79.152 63.277 81.432 ;
     RECT  63.169 82.416 63.277 88.68 ;
     RECT  62.104 89.664 63.277 90.696 ;
     RECT  62.104 92.16 63.277 92.184 ;
     RECT  63.241 93.408 63.277 96.456 ;
     RECT  62.104 97.44 63.277 98.424 ;
     RECT  63.241 99.408 63.277 109.704 ;
     RECT  62.104 110.688 63.277 111.96 ;
     RECT  63.241 113.184 63.277 113.208 ;
     RECT  62.165 114.192 63.277 115.176 ;
     RECT  63.241 116.4 63.277 117.96 ;
     RECT  62.104 119.184 63.277 119.688 ;
     RECT  62.104 120.672 63.277 120.696 ;
     RECT  62.201 121.92 63.277 122.952 ;
     RECT  62.201 124.176 63.277 124.2 ;
     RECT  62.737 126.432 63.277 128.952 ;
     RECT  62.104 12.672 63.565 13.944 ;
     RECT  63.277 14.928 63.565 18.696 ;
     RECT  63.565 12.672 63.601 18.696 ;
     RECT  63.601 12.144 63.637 18.696 ;
     RECT  63.241 44.4 63.745 44.424 ;
     RECT  63.241 45.408 63.745 45.672 ;
     RECT  63.277 61.68 63.745 70.2 ;
     RECT  63.241 19.92 63.781 21.912 ;
     RECT  63.241 22.896 63.781 24.936 ;
     RECT  63.241 34.176 63.781 34.44 ;
     RECT  63.277 35.424 63.781 39.912 ;
     RECT  63.241 41.664 63.781 43.416 ;
     RECT  63.745 44.4 63.781 45.672 ;
     RECT  62.104 50.4 63.781 50.424 ;
     RECT  62.104 51.648 63.781 52.44 ;
     RECT  63.241 53.664 63.781 55.176 ;
     RECT  63.277 56.4 63.781 60.168 ;
     RECT  63.745 61.392 63.781 70.2 ;
     RECT  63.241 0.672 63.817 4.92 ;
     RECT  63.097 6.672 63.817 10.92 ;
     RECT  63.637 11.904 63.817 18.696 ;
     RECT  63.781 19.68 63.817 24.936 ;
     RECT  63.241 25.92 63.817 29.928 ;
     RECT  63.241 31.152 63.817 31.176 ;
     RECT  63.781 33.648 63.817 34.44 ;
     RECT  63.781 35.424 63.817 40.68 ;
     RECT  63.781 41.664 63.817 45.672 ;
     RECT  63.241 46.656 63.817 46.92 ;
     RECT  62.291 47.904 63.817 49.176 ;
     RECT  63.781 50.4 63.817 60.168 ;
     RECT  63.781 61.152 63.817 70.2 ;
     RECT  63.277 116.4 63.817 120.696 ;
     RECT  63.817 6.384 63.853 24.936 ;
     RECT  63.817 25.92 63.853 31.176 ;
     RECT  63.817 32.4 63.853 46.92 ;
     RECT  63.817 47.904 63.853 49.416 ;
     RECT  63.817 50.4 63.853 70.2 ;
     RECT  63.277 71.184 63.853 77.928 ;
     RECT  63.277 79.152 63.853 115.176 ;
     RECT  63.817 116.16 63.853 120.696 ;
     RECT  63.277 121.68 63.853 124.2 ;
     RECT  63.277 125.184 63.853 128.952 ;
     RECT  63.853 6.384 64.609 46.92 ;
     RECT  63.817 0.672 64.645 5.16 ;
     RECT  64.609 6.144 64.645 46.92 ;
     RECT  63.853 47.904 64.645 128.952 ;
     RECT  64.645 0.672 64.764 128.952 ;
     RECT  64.764 7.248 64.793 7.272 ;
     RECT  64.764 12.48 64.793 12.504 ;
     RECT  64.764 62.496 64.793 62.52 ;
    LAYER M5 ;
     RECT  40.32 0.016 49.896 0.131 ;
     RECT  41.232 0.131 44.424 0.563 ;
     RECT  45.792 0.131 45.816 0.563 ;
     RECT  29.856 0.085 29.88 2.137 ;
     RECT  41.232 0.563 42.168 2.137 ;
     RECT  2.4 2.137 2.52 2.151 ;
     RECT  7.8 2.137 7.92 2.151 ;
     RECT  13.2 2.137 13.32 2.151 ;
     RECT  18.6 2.137 18.72 2.151 ;
     RECT  24 2.137 24.12 2.151 ;
     RECT  34.8 2.137 34.92 2.151 ;
     RECT  45.6 2.137 45.72 2.151 ;
     RECT  51 2.137 51.12 2.151 ;
     RECT  56.4 2.137 56.52 2.151 ;
     RECT  61.8 2.137 61.92 2.151 ;
     RECT  40.2 2.137 42.168 3.443 ;
     RECT  2.4 2.151 2.712 4.261 ;
     RECT  40.2 3.443 40.632 4.261 ;
     RECT  51 2.151 51.312 4.405 ;
     RECT  38.4 4.261 38.424 5.125 ;
     RECT  38.4 5.125 38.952 5.171 ;
     RECT  54.144 5.077 54.168 6.851 ;
     RECT  7.8 2.151 8.112 7.381 ;
     RECT  52.56 6.277 52.584 7.475 ;
     RECT  6.864 7.381 8.112 7.715 ;
     RECT  2.4 4.261 3.624 7.717 ;
     RECT  5.328 6.709 5.352 7.765 ;
     RECT  55.104 7.381 55.128 7.909 ;
     RECT  54.72 7.909 55.128 7.955 ;
     RECT  7.2 7.715 8.112 8.197 ;
     RECT  4.608 7.765 5.352 8.243 ;
     RECT  39.936 4.261 40.632 8.675 ;
     RECT  7.2 8.197 8.232 10.213 ;
     RECT  50.88 4.405 51.312 10.453 ;
     RECT  56.4 2.151 56.712 10.501 ;
     RECT  2.256 7.717 3.624 10.597 ;
     RECT  5.328 8.243 5.352 10.597 ;
     RECT  45.6 2.151 45.912 10.597 ;
     RECT  54.72 7.955 54.744 10.597 ;
     RECT  50.736 10.453 51.312 10.789 ;
     RECT  54.72 10.597 54.984 10.789 ;
     RECT  54.672 10.789 54.984 10.883 ;
     RECT  50.352 10.789 51.312 11.411 ;
     RECT  45.6 10.597 46.104 11.555 ;
     RECT  56.256 10.501 56.712 11.653 ;
     RECT  54.672 10.883 54.696 11.699 ;
     RECT  50.736 11.411 51.312 11.941 ;
     RECT  39.936 8.675 40.512 11.987 ;
     RECT  50.736 11.941 51.48 11.987 ;
     RECT  6.528 10.213 8.232 12.181 ;
     RECT  56.256 11.653 56.904 12.469 ;
     RECT  2.256 10.597 5.352 12.563 ;
     RECT  56.256 12.469 57.624 12.563 ;
     RECT  6.528 12.181 8.472 12.997 ;
     RECT  39.984 11.987 40.512 13.045 ;
     RECT  39.984 13.045 40.872 13.091 ;
     RECT  42.144 3.443 42.168 13.139 ;
     RECT  6.336 12.997 8.472 13.283 ;
     RECT  56.4 12.563 57.624 13.667 ;
     RECT  40.2 13.091 40.872 14.677 ;
     RECT  40.2 14.677 41.496 14.867 ;
     RECT  6.336 13.283 8.112 15.013 ;
     RECT  56.4 13.667 56.904 15.253 ;
     RECT  5.232 12.563 5.352 16.933 ;
     RECT  6.336 15.013 8.76 16.933 ;
     RECT  38.928 5.171 38.952 17.219 ;
     RECT  56.4 15.253 57 17.603 ;
     RECT  10.512 14.245 10.536 18.803 ;
     RECT  40.2 14.867 41.16 19.523 ;
     RECT  51 11.987 51.48 19.571 ;
     RECT  52.992 19.333 53.016 19.955 ;
     RECT  55.2 18.757 55.224 20.579 ;
     RECT  58.896 19.333 58.92 20.579 ;
     RECT  51 19.571 51.432 20.627 ;
     RECT  43.968 0.563 44.424 21.013 ;
     RECT  58.752 21.061 58.776 21.637 ;
     RECT  9.744 20.725 9.768 21.683 ;
     RECT  58.656 21.637 58.776 21.683 ;
     RECT  2.256 12.563 3.96 22.069 ;
     RECT  5.232 16.933 8.76 22.069 ;
     RECT  58.656 21.683 58.68 22.691 ;
     RECT  51 20.627 51.312 22.741 ;
     RECT  2.256 22.069 8.76 23.027 ;
     RECT  56.4 17.603 56.904 23.125 ;
     RECT  10.08 22.741 10.104 23.843 ;
     RECT  55.824 23.125 56.904 23.939 ;
     RECT  51 22.741 51.912 24.325 ;
     RECT  51 24.325 52.44 24.371 ;
     RECT  61.8 2.151 62.112 24.757 ;
     RECT  56.4 23.939 56.904 24.997 ;
     RECT  57.936 22.741 57.96 24.997 ;
     RECT  5.232 23.027 8.76 25.045 ;
     RECT  56.4 24.997 57.96 25.045 ;
     RECT  59.04 24.325 59.064 25.045 ;
     RECT  61.392 24.757 62.112 25.045 ;
     RECT  43.584 21.013 44.424 25.139 ;
     RECT  9.744 24.901 9.768 25.141 ;
     RECT  60.72 25.045 62.112 25.285 ;
     RECT  5.136 25.045 8.76 25.429 ;
     RECT  56.4 25.045 59.064 25.715 ;
     RECT  60.624 25.285 62.112 26.101 ;
     RECT  43.584 25.139 43.608 26.243 ;
     RECT  11.52 24.277 11.544 26.291 ;
     RECT  2.256 23.027 3.96 26.341 ;
     RECT  4.944 25.429 8.76 26.341 ;
     RECT  2.256 26.341 8.76 26.725 ;
     RECT  9.744 25.141 10.152 26.725 ;
     RECT  45.6 11.555 45.912 26.725 ;
     RECT  56.4 25.715 56.904 26.725 ;
     RECT  57.936 25.715 59.064 26.725 ;
     RECT  52.416 24.371 52.44 26.771 ;
     RECT  44.784 26.725 45.912 26.773 ;
     RECT  42.24 24.085 42.264 26.819 ;
     RECT  60.336 26.101 62.112 27.155 ;
     RECT  2.256 26.725 11.112 27.347 ;
     RECT  2.256 27.347 8.76 27.829 ;
     RECT  60.384 27.155 62.112 27.971 ;
     RECT  2.208 27.829 8.76 28.453 ;
     RECT  9.744 27.347 11.112 28.453 ;
     RECT  2.208 28.453 11.112 28.499 ;
     RECT  44.208 26.773 45.912 29.603 ;
     RECT  56.4 26.725 59.064 30.133 ;
     RECT  44.208 29.603 44.232 30.323 ;
     RECT  60.432 27.971 62.112 30.419 ;
     RECT  49.584 29.557 49.608 30.803 ;
     RECT  60.576 30.419 62.112 31.093 ;
     RECT  45.6 29.603 45.912 31.237 ;
     RECT  56.016 30.133 59.064 31.525 ;
     RECT  44.976 31.237 45.912 31.955 ;
     RECT  56.016 31.525 59.448 32.341 ;
     RECT  60.576 31.093 62.232 32.341 ;
     RECT  56.016 32.341 62.232 32.483 ;
     RECT  45.6 31.955 45.912 32.917 ;
     RECT  52.464 27.877 52.488 32.917 ;
     RECT  52.464 32.917 53.304 32.963 ;
     RECT  44.976 32.917 45.912 35.221 ;
     RECT  44.496 35.221 45.912 35.267 ;
     RECT  31.872 34.885 31.896 35.413 ;
     RECT  31.536 35.413 31.896 35.459 ;
     RECT  54.624 24.181 54.648 35.701 ;
     RECT  56.016 32.483 58.968 35.701 ;
     RECT  40.2 19.523 41.112 36.757 ;
     RECT  44.496 35.267 44.52 36.803 ;
     RECT  54.624 35.701 58.968 36.949 ;
     RECT  54.624 36.949 59.016 37.141 ;
     RECT  60 32.483 62.232 37.141 ;
     RECT  45.6 35.267 45.912 37.573 ;
     RECT  40.2 36.757 41.592 38.819 ;
     RECT  54.624 37.141 62.232 38.819 ;
     RECT  53.28 32.963 53.304 39.301 ;
     RECT  53.28 39.301 53.592 39.347 ;
     RECT  31.536 35.459 31.56 39.539 ;
     RECT  33.6 39.781 33.624 39.877 ;
     RECT  40.2 38.819 41.112 39.877 ;
     RECT  33.36 39.877 33.624 39.923 ;
     RECT  54.624 38.819 59.016 41.125 ;
     RECT  60 38.819 62.232 41.125 ;
     RECT  53.568 39.347 53.592 41.939 ;
     RECT  45.6 37.573 46.008 42.707 ;
     RECT  45.6 42.707 45.912 44.197 ;
     RECT  2.208 28.499 10.92 44.341 ;
     RECT  45.6 44.197 46.296 44.437 ;
     RECT  40.2 39.877 41.304 44.627 ;
     RECT  2.208 44.341 11.4 46.787 ;
     RECT  45.504 44.437 46.296 47.029 ;
     RECT  54.624 41.125 62.232 47.077 ;
     RECT  45.504 47.029 46.344 47.171 ;
     RECT  45.504 47.171 46.296 48.227 ;
     RECT  43.44 47.125 43.464 49.043 ;
     RECT  45.504 48.227 45.912 49.283 ;
     RECT  45.6 49.283 45.912 50.101 ;
     RECT  54.624 47.077 62.28 50.965 ;
     RECT  51 24.371 51.312 51.541 ;
     RECT  54.144 50.965 62.28 52.067 ;
     RECT  51 51.541 51.72 52.499 ;
     RECT  47.952 50.437 47.976 53.267 ;
     RECT  49.584 54.085 49.608 54.325 ;
     RECT  51 52.499 51.312 54.325 ;
     RECT  49.584 54.325 51.312 54.371 ;
     RECT  53.232 54.085 53.544 54.661 ;
     RECT  52.8 54.661 53.544 54.755 ;
     RECT  2.208 46.787 10.92 55.381 ;
     RECT  45.6 50.101 46.008 55.813 ;
     RECT  50.064 54.371 51.312 56.341 ;
     RECT  49.488 56.341 51.312 56.389 ;
     RECT  49.488 56.389 51.432 57.443 ;
     RECT  49.488 57.443 51.312 57.635 ;
     RECT  45.6 55.813 46.152 58.645 ;
     RECT  2.208 55.381 10.968 59.459 ;
     RECT  45.6 58.645 46.248 59.797 ;
     RECT  45.6 59.797 46.728 60.515 ;
     RECT  50.064 57.635 51.312 61.765 ;
     RECT  52.8 54.755 53.256 61.765 ;
     RECT  49.008 60.853 49.032 62.389 ;
     RECT  50.064 61.765 53.256 62.389 ;
     RECT  49.008 62.389 53.256 62.435 ;
     RECT  54.624 52.067 62.28 62.725 ;
     RECT  49.104 62.435 53.256 63.395 ;
     RECT  54.528 62.725 62.28 64.933 ;
     RECT  54.432 64.933 62.28 65.507 ;
     RECT  50.064 63.395 53.256 65.603 ;
     RECT  54.528 65.507 62.28 65.891 ;
     RECT  2.208 59.459 10.92 65.941 ;
     RECT  45.6 60.515 46.248 66.133 ;
     RECT  1.392 65.941 10.92 66.181 ;
     RECT  29.4 2.137 29.88 66.755 ;
     RECT  50.88 65.603 53.256 66.803 ;
     RECT  54.624 65.891 62.28 67.669 ;
     RECT  54.288 67.669 62.28 68.963 ;
     RECT  0.912 66.181 10.92 72.995 ;
     RECT  51 66.803 53.256 73.765 ;
     RECT  54.624 68.963 62.28 73.765 ;
     RECT  51 73.765 62.28 75.203 ;
     RECT  1.008 72.995 10.92 76.357 ;
     RECT  13.2 2.151 13.512 77.653 ;
     RECT  51 75.203 53.64 77.701 ;
     RECT  54.624 75.203 62.28 77.701 ;
     RECT  45.6 66.133 46.44 77.891 ;
     RECT  13.104 77.653 13.512 77.941 ;
     RECT  12.816 77.941 13.512 79.765 ;
     RECT  51 77.701 62.28 80.339 ;
     RECT  12.816 79.765 14.328 80.629 ;
     RECT  12.816 80.629 14.808 80.917 ;
     RECT  18.6 2.151 18.912 81.349 ;
     RECT  12.816 80.917 15.288 81.445 ;
     RECT  51 80.339 53.592 81.635 ;
     RECT  17.952 81.349 18.912 82.021 ;
     RECT  20.16 83.461 20.184 84.565 ;
     RECT  17.28 82.021 18.912 84.613 ;
     RECT  20.16 84.565 21 84.755 ;
     RECT  1.008 76.357 11.832 84.853 ;
     RECT  24 2.151 24.312 84.853 ;
     RECT  23.328 84.853 24.312 85.141 ;
     RECT  23.328 85.141 24.504 85.669 ;
     RECT  54.624 80.339 62.28 85.811 ;
     RECT  22.848 85.669 24.504 86.099 ;
     RECT  22.848 86.099 24.312 87.445 ;
     RECT  22.848 87.445 24.408 88.741 ;
     RECT  22.848 88.741 24.744 90.037 ;
     RECT  26.688 91.189 26.712 91.717 ;
     RECT  21.456 85.909 21.48 91.811 ;
     RECT  22.848 90.037 25.224 91.811 ;
     RECT  26.688 91.717 27.192 92.293 ;
     RECT  23.664 91.811 25.224 92.387 ;
     RECT  26.688 92.293 27.72 92.821 ;
     RECT  20.16 84.755 20.184 93.349 ;
     RECT  21.216 92.293 21.24 93.349 ;
     RECT  17.28 84.613 19.032 93.877 ;
     RECT  20.16 93.349 21.24 93.877 ;
     RECT  26.688 92.821 28.2 93.877 ;
     RECT  29.4 66.755 29.712 93.877 ;
     RECT  26.688 93.877 29.712 94.405 ;
     RECT  17.28 93.877 21.24 95.701 ;
     RECT  26.688 94.405 30.168 95.701 ;
     RECT  26.688 95.701 30.696 96.277 ;
     RECT  33.36 39.923 33.384 96.371 ;
     RECT  26.688 96.277 31.656 96.853 ;
     RECT  0.912 84.853 11.832 97.141 ;
     RECT  12.816 81.445 16.296 97.141 ;
     RECT  34.8 2.151 35.112 98.149 ;
     RECT  26.688 96.853 32.184 98.581 ;
     RECT  34.704 98.149 35.112 98.675 ;
     RECT  26.688 98.581 33.144 99.157 ;
     RECT  34.8 98.675 35.112 99.445 ;
     RECT  26.688 99.157 33.672 99.685 ;
     RECT  34.8 99.445 35.736 99.685 ;
     RECT  26.688 99.685 35.736 100.499 ;
     RECT  36.864 101.605 36.888 102.083 ;
     RECT  54.96 85.811 62.28 102.469 ;
     RECT  54.72 102.469 62.28 102.755 ;
     RECT  37.584 102.229 37.608 103.621 ;
     RECT  37.584 103.621 38.136 104.245 ;
     RECT  37.584 104.245 38.616 104.821 ;
     RECT  40.2 44.627 40.512 104.821 ;
     RECT  0.912 97.141 16.296 105.683 ;
     RECT  41.952 105.397 41.976 106.165 ;
     RECT  37.584 104.821 40.512 106.549 ;
     RECT  41.952 106.165 42.744 106.549 ;
     RECT  37.584 106.549 42.744 106.643 ;
     RECT  54.96 102.755 62.28 106.691 ;
     RECT  0.912 105.683 6.36 108.853 ;
     RECT  7.344 105.683 16.296 108.853 ;
     RECT  55.152 106.691 62.28 109.283 ;
     RECT  43.056 108.469 43.08 109.285 ;
     RECT  0.912 108.853 16.296 109.667 ;
     RECT  43.056 109.285 43.56 109.717 ;
     RECT  45.6 77.891 45.912 109.717 ;
     RECT  43.056 109.717 43.944 109.813 ;
     RECT  43.056 109.813 44.088 109.957 ;
     RECT  0.912 109.667 6.36 111.301 ;
     RECT  7.344 109.667 16.296 111.301 ;
     RECT  45.6 109.717 46.008 111.445 ;
     RECT  0.912 111.301 16.296 112.403 ;
     RECT  47.04 112.261 47.064 112.501 ;
     RECT  48.48 111.925 48.504 112.501 ;
     RECT  47.04 112.501 48.504 112.643 ;
     RECT  51 81.635 53.256 113.029 ;
     RECT  51 113.029 53.736 113.269 ;
     RECT  50.88 113.269 53.736 115.091 ;
     RECT  0.912 112.403 6.36 115.141 ;
     RECT  7.344 112.403 16.296 115.141 ;
     RECT  50.88 115.091 53.256 115.333 ;
     RECT  55.152 109.283 62.112 115.571 ;
     RECT  55.152 115.571 58.104 116.485 ;
     RECT  50.832 115.333 53.256 116.725 ;
     RECT  0.912 115.141 16.296 116.963 ;
     RECT  54.96 116.485 58.104 117.491 ;
     RECT  54.96 117.491 56.712 117.827 ;
     RECT  57.744 117.491 58.104 117.829 ;
     RECT  59.136 115.571 62.112 117.829 ;
     RECT  57.744 117.829 62.112 117.875 ;
     RECT  58.08 117.875 62.112 117.971 ;
     RECT  0.912 116.963 6.36 118.405 ;
     RECT  7.344 116.963 16.296 118.405 ;
     RECT  47.04 112.643 48.024 118.981 ;
     RECT  50.832 116.725 53.352 119.363 ;
     RECT  55.152 117.827 56.712 119.459 ;
     RECT  45.6 111.445 46.056 120.085 ;
     RECT  47.04 118.981 48.456 120.085 ;
     RECT  45.6 120.085 48.456 120.275 ;
     RECT  55.152 119.459 55.176 120.709 ;
     RECT  0.912 118.405 16.296 120.853 ;
     RECT  0.672 120.853 16.296 121.043 ;
     RECT  49.488 113.509 49.512 121.381 ;
     RECT  54.72 120.709 55.176 121.619 ;
     RECT  58.08 117.971 58.152 122.485 ;
     RECT  59.136 117.971 62.112 122.485 ;
     RECT  49.104 121.381 49.512 122.533 ;
     RECT  58.08 122.485 62.112 123.251 ;
     RECT  45.6 120.275 48.024 123.731 ;
     RECT  58.272 123.251 62.112 123.731 ;
     RECT  55.152 121.619 55.176 124.019 ;
     RECT  49.008 122.533 49.512 124.307 ;
     RECT  52.848 119.363 53.352 124.307 ;
     RECT  50.832 119.363 51.432 124.355 ;
     RECT  58.704 123.731 62.112 124.693 ;
     RECT  50.832 124.355 51.312 124.883 ;
     RECT  55.344 124.693 55.368 125.317 ;
     RECT  56.4 119.459 56.712 125.317 ;
     RECT  55.344 125.317 56.712 125.363 ;
     RECT  49.104 124.307 49.512 125.459 ;
     RECT  55.824 125.363 56.712 125.459 ;
     RECT  58.416 124.693 62.112 125.653 ;
     RECT  52.896 124.307 53.352 126.035 ;
     RECT  58.128 125.653 62.112 126.083 ;
     RECT  58.512 126.083 62.112 126.421 ;
     RECT  58.512 126.421 62.664 126.517 ;
     RECT  58.512 126.517 62.76 126.611 ;
     RECT  53.088 126.035 53.352 126.659 ;
     RECT  60.336 126.611 62.76 126.707 ;
     RECT  49.104 125.459 49.128 127.093 ;
     RECT  51 124.883 51.312 127.093 ;
     RECT  56.4 125.459 56.712 127.093 ;
     RECT  60.336 126.707 62.424 127.187 ;
     RECT  54.96 127.093 56.712 127.381 ;
     RECT  58.512 126.611 59.112 127.381 ;
     RECT  26.688 100.499 35.112 127.449 ;
     RECT  0.912 121.043 16.296 127.463 ;
     RECT  26.688 127.449 34.92 127.463 ;
     RECT  37.584 106.643 42.072 127.463 ;
     RECT  54.96 127.381 56.952 127.463 ;
     RECT  45.6 123.731 46.056 127.573 ;
     RECT  49.104 127.093 49.512 127.621 ;
     RECT  50.496 127.093 52.008 127.621 ;
     RECT  53.472 127.093 53.976 127.621 ;
     RECT  54.96 127.463 55.944 127.621 ;
     RECT  58.416 127.381 59.112 127.621 ;
     RECT  60.336 127.187 60.408 127.621 ;
     RECT  47.04 123.731 48.024 127.669 ;
     RECT  49.104 127.621 55.944 127.669 ;
     RECT  61.392 127.187 62.424 127.717 ;
     RECT  56.928 127.463 56.952 128.245 ;
     RECT  57.936 127.621 60.408 128.245 ;
     RECT  61.392 127.717 63.384 128.245 ;
     RECT  0.912 127.463 7.368 128.773 ;
     RECT  8.352 127.463 16.296 128.773 ;
     RECT  47.04 127.669 55.944 128.773 ;
     RECT  56.928 128.245 60.408 128.773 ;
     RECT  17.28 95.701 21.768 128.821 ;
     RECT  26.688 127.463 34.632 128.821 ;
     RECT  43.056 109.957 44.568 128.821 ;
     RECT  45.552 127.573 46.056 128.821 ;
     RECT  47.04 128.773 60.408 128.821 ;
     RECT  61.392 128.245 63.912 128.821 ;
     RECT  23.712 92.387 25.224 129.397 ;
     RECT  26.208 128.821 34.632 129.397 ;
     RECT  0.912 128.773 16.296 129.445 ;
     RECT  17.28 128.821 22.248 129.445 ;
     RECT  23.232 129.397 25.224 129.445 ;
     RECT  26.208 129.397 35.64 129.445 ;
     RECT  37.584 127.463 40.104 129.445 ;
     RECT  41.088 127.463 42.072 129.445 ;
     RECT  43.056 128.821 46.056 129.445 ;
     RECT  47.04 128.821 63.912 129.445 ;
     RECT  0.912 129.445 63.912 129.552 ;
  END
END qfd_c_land_w257_narrow
END LIBRARY
